VERSION 5.8 ;
BUSBITCHARS "[]" ;
DIVIDERCHAR "/" ;
UNITS
    DATABASE MICRONS 1000 ;
END UNITS

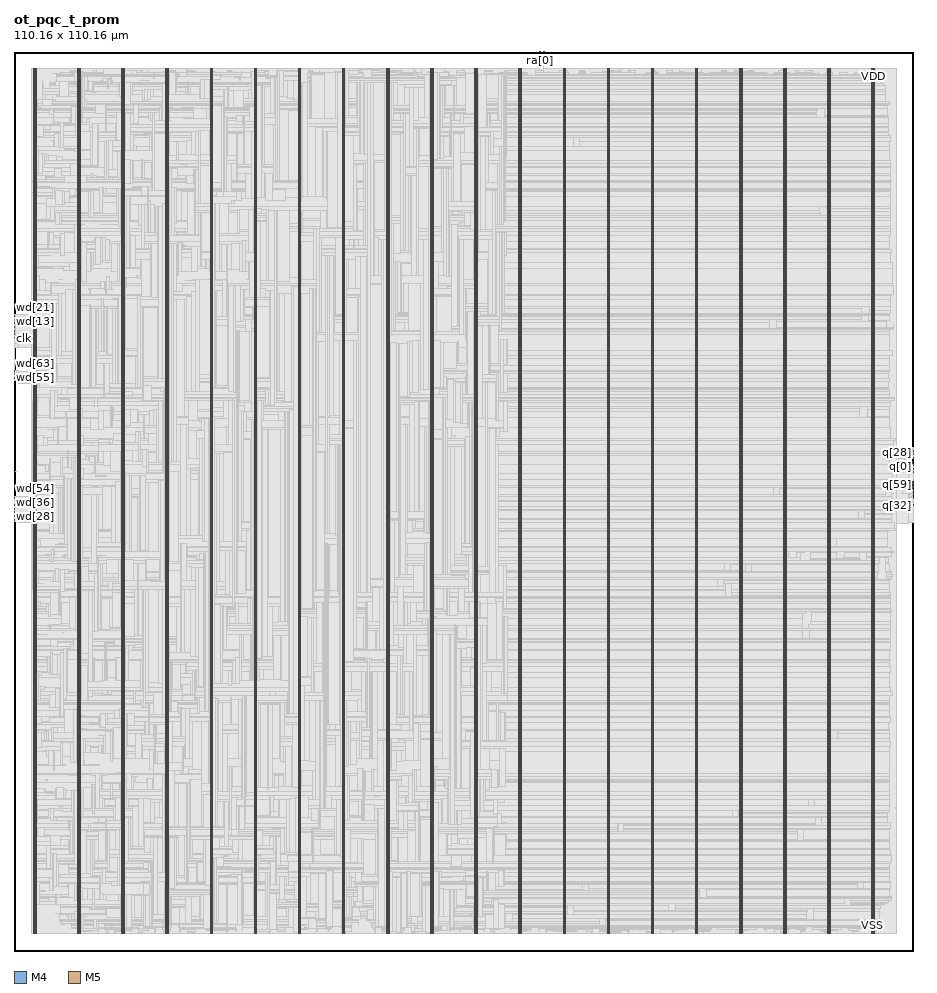
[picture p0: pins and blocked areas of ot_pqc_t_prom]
MACRO ot_pqc_t_prom
  FOREIGN ot_pqc_t_prom 0 0 ;
  CLASS BLOCK ;
  SIZE 110.16 BY 110.16 ;
  PIN clk
    DIRECTION INPUT ;
    USE SIGNAL ;
    PORT
      LAYER M4 ;
        RECT  0 74.928 0.084 74.952 ;
    END
  END clk
  PIN q[0]
    DIRECTION OUTPUT ;
    USE SIGNAL ;
    PORT
      LAYER M4 ;
        RECT  110.076 58.32 110.16 58.344 ;
    END
  END q[0]
  PIN q[10]
    DIRECTION OUTPUT ;
    USE SIGNAL ;
    PORT
      LAYER M4 ;
        RECT  110.076 59.28 110.16 59.304 ;
    END
  END q[10]
  PIN q[11]
    DIRECTION OUTPUT ;
    USE SIGNAL ;
    PORT
      LAYER M4 ;
        RECT  110.076 59.376 110.16 59.4 ;
    END
  END q[11]
  PIN q[12]
    DIRECTION OUTPUT ;
    USE SIGNAL ;
    PORT
      LAYER M4 ;
        RECT  110.076 59.472 110.16 59.496 ;
    END
  END q[12]
  PIN q[13]
    DIRECTION OUTPUT ;
    USE SIGNAL ;
    PORT
      LAYER M4 ;
        RECT  110.076 59.568 110.16 59.592 ;
    END
  END q[13]
  PIN q[14]
    DIRECTION OUTPUT ;
    USE SIGNAL ;
    PORT
      LAYER M4 ;
        RECT  110.076 59.664 110.16 59.688 ;
    END
  END q[14]
  PIN q[15]
    DIRECTION OUTPUT ;
    USE SIGNAL ;
    PORT
      LAYER M4 ;
        RECT  110.076 59.76 110.16 59.784 ;
    END
  END q[15]
  PIN q[16]
    DIRECTION OUTPUT ;
    USE SIGNAL ;
    PORT
      LAYER M4 ;
        RECT  110.076 59.856 110.16 59.88 ;
    END
  END q[16]
  PIN q[17]
    DIRECTION OUTPUT ;
    USE SIGNAL ;
    PORT
      LAYER M4 ;
        RECT  110.076 59.952 110.16 59.976 ;
    END
  END q[17]
  PIN q[18]
    DIRECTION OUTPUT ;
    USE SIGNAL ;
    PORT
      LAYER M4 ;
        RECT  110.076 60.048 110.16 60.072 ;
    END
  END q[18]
  PIN q[19]
    DIRECTION OUTPUT ;
    USE SIGNAL ;
    PORT
      LAYER M4 ;
        RECT  110.076 60.144 110.16 60.168 ;
    END
  END q[19]
  PIN q[1]
    DIRECTION OUTPUT ;
    USE SIGNAL ;
    PORT
      LAYER M4 ;
        RECT  110.076 58.416 110.16 58.44 ;
    END
  END q[1]
  PIN q[20]
    DIRECTION OUTPUT ;
    USE SIGNAL ;
    PORT
      LAYER M4 ;
        RECT  110.076 60.24 110.16 60.264 ;
    END
  END q[20]
  PIN q[21]
    DIRECTION OUTPUT ;
    USE SIGNAL ;
    PORT
      LAYER M4 ;
        RECT  110.076 60.336 110.16 60.36 ;
    END
  END q[21]
  PIN q[22]
    DIRECTION OUTPUT ;
    USE SIGNAL ;
    PORT
      LAYER M4 ;
        RECT  110.076 60.432 110.16 60.456 ;
    END
  END q[22]
  PIN q[23]
    DIRECTION OUTPUT ;
    USE SIGNAL ;
    PORT
      LAYER M4 ;
        RECT  110.076 60.528 110.16 60.552 ;
    END
  END q[23]
  PIN q[24]
    DIRECTION OUTPUT ;
    USE SIGNAL ;
    PORT
      LAYER M4 ;
        RECT  110.076 60.624 110.16 60.648 ;
    END
  END q[24]
  PIN q[25]
    DIRECTION OUTPUT ;
    USE SIGNAL ;
    PORT
      LAYER M4 ;
        RECT  110.076 60.72 110.16 60.744 ;
    END
  END q[25]
  PIN q[26]
    DIRECTION OUTPUT ;
    USE SIGNAL ;
    PORT
      LAYER M4 ;
        RECT  110.076 60.816 110.16 60.84 ;
    END
  END q[26]
  PIN q[27]
    DIRECTION OUTPUT ;
    USE SIGNAL ;
    PORT
      LAYER M4 ;
        RECT  110.076 60.912 110.16 60.936 ;
    END
  END q[27]
  PIN q[28]
    DIRECTION OUTPUT ;
    USE SIGNAL ;
    PORT
      LAYER M4 ;
        RECT  110.076 61.008 110.16 61.032 ;
    END
  END q[28]
  PIN q[29]
    DIRECTION OUTPUT ;
    USE SIGNAL ;
    PORT
      LAYER M4 ;
        RECT  110.076 61.104 110.16 61.128 ;
    END
  END q[29]
  PIN q[2]
    DIRECTION OUTPUT ;
    USE SIGNAL ;
    PORT
      LAYER M4 ;
        RECT  110.076 58.512 110.16 58.536 ;
    END
  END q[2]
  PIN q[30]
    DIRECTION OUTPUT ;
    USE SIGNAL ;
    PORT
      LAYER M4 ;
        RECT  110.076 61.2 110.16 61.224 ;
    END
  END q[30]
  PIN q[31]
    DIRECTION OUTPUT ;
    USE SIGNAL ;
    PORT
      LAYER M4 ;
        RECT  110.076 61.296 110.16 61.32 ;
    END
  END q[31]
  PIN q[32]
    DIRECTION OUTPUT ;
    USE SIGNAL ;
    PORT
      LAYER M4 ;
        RECT  110.076 54.48 110.16 54.504 ;
    END
  END q[32]
  PIN q[33]
    DIRECTION OUTPUT ;
    USE SIGNAL ;
    PORT
      LAYER M4 ;
        RECT  110.076 54.576 110.16 54.6 ;
    END
  END q[33]
  PIN q[34]
    DIRECTION OUTPUT ;
    USE SIGNAL ;
    PORT
      LAYER M4 ;
        RECT  110.076 54.672 110.16 54.696 ;
    END
  END q[34]
  PIN q[35]
    DIRECTION OUTPUT ;
    USE SIGNAL ;
    PORT
      LAYER M4 ;
        RECT  110.076 54.768 110.16 54.792 ;
    END
  END q[35]
  PIN q[36]
    DIRECTION OUTPUT ;
    USE SIGNAL ;
    PORT
      LAYER M4 ;
        RECT  110.076 54.864 110.16 54.888 ;
    END
  END q[36]
  PIN q[37]
    DIRECTION OUTPUT ;
    USE SIGNAL ;
    PORT
      LAYER M4 ;
        RECT  110.076 54.96 110.16 54.984 ;
    END
  END q[37]
  PIN q[38]
    DIRECTION OUTPUT ;
    USE SIGNAL ;
    PORT
      LAYER M4 ;
        RECT  110.076 55.056 110.16 55.08 ;
    END
  END q[38]
  PIN q[39]
    DIRECTION OUTPUT ;
    USE SIGNAL ;
    PORT
      LAYER M4 ;
        RECT  110.076 55.152 110.16 55.176 ;
    END
  END q[39]
  PIN q[3]
    DIRECTION OUTPUT ;
    USE SIGNAL ;
    PORT
      LAYER M4 ;
        RECT  110.076 58.608 110.16 58.632 ;
    END
  END q[3]
  PIN q[40]
    DIRECTION OUTPUT ;
    USE SIGNAL ;
    PORT
      LAYER M4 ;
        RECT  110.076 55.248 110.16 55.272 ;
    END
  END q[40]
  PIN q[41]
    DIRECTION OUTPUT ;
    USE SIGNAL ;
    PORT
      LAYER M4 ;
        RECT  110.076 55.344 110.16 55.368 ;
    END
  END q[41]
  PIN q[42]
    DIRECTION OUTPUT ;
    USE SIGNAL ;
    PORT
      LAYER M4 ;
        RECT  110.076 55.44 110.16 55.464 ;
    END
  END q[42]
  PIN q[43]
    DIRECTION OUTPUT ;
    USE SIGNAL ;
    PORT
      LAYER M4 ;
        RECT  110.076 55.536 110.16 55.56 ;
    END
  END q[43]
  PIN q[44]
    DIRECTION OUTPUT ;
    USE SIGNAL ;
    PORT
      LAYER M4 ;
        RECT  110.076 55.632 110.16 55.656 ;
    END
  END q[44]
  PIN q[45]
    DIRECTION OUTPUT ;
    USE SIGNAL ;
    PORT
      LAYER M4 ;
        RECT  110.076 55.728 110.16 55.752 ;
    END
  END q[45]
  PIN q[46]
    DIRECTION OUTPUT ;
    USE SIGNAL ;
    PORT
      LAYER M4 ;
        RECT  110.076 55.824 110.16 55.848 ;
    END
  END q[46]
  PIN q[47]
    DIRECTION OUTPUT ;
    USE SIGNAL ;
    PORT
      LAYER M4 ;
        RECT  110.076 55.92 110.16 55.944 ;
    END
  END q[47]
  PIN q[48]
    DIRECTION OUTPUT ;
    USE SIGNAL ;
    PORT
      LAYER M4 ;
        RECT  110.076 56.016 110.16 56.04 ;
    END
  END q[48]
  PIN q[49]
    DIRECTION OUTPUT ;
    USE SIGNAL ;
    PORT
      LAYER M4 ;
        RECT  110.076 56.112 110.16 56.136 ;
    END
  END q[49]
  PIN q[4]
    DIRECTION OUTPUT ;
    USE SIGNAL ;
    PORT
      LAYER M4 ;
        RECT  110.076 58.704 110.16 58.728 ;
    END
  END q[4]
  PIN q[50]
    DIRECTION OUTPUT ;
    USE SIGNAL ;
    PORT
      LAYER M4 ;
        RECT  110.076 56.208 110.16 56.232 ;
    END
  END q[50]
  PIN q[51]
    DIRECTION OUTPUT ;
    USE SIGNAL ;
    PORT
      LAYER M4 ;
        RECT  110.076 56.304 110.16 56.328 ;
    END
  END q[51]
  PIN q[52]
    DIRECTION OUTPUT ;
    USE SIGNAL ;
    PORT
      LAYER M4 ;
        RECT  110.076 56.4 110.16 56.424 ;
    END
  END q[52]
  PIN q[53]
    DIRECTION OUTPUT ;
    USE SIGNAL ;
    PORT
      LAYER M4 ;
        RECT  110.076 56.496 110.16 56.52 ;
    END
  END q[53]
  PIN q[54]
    DIRECTION OUTPUT ;
    USE SIGNAL ;
    PORT
      LAYER M4 ;
        RECT  110.076 56.592 110.16 56.616 ;
    END
  END q[54]
  PIN q[55]
    DIRECTION OUTPUT ;
    USE SIGNAL ;
    PORT
      LAYER M4 ;
        RECT  110.076 56.688 110.16 56.712 ;
    END
  END q[55]
  PIN q[56]
    DIRECTION OUTPUT ;
    USE SIGNAL ;
    PORT
      LAYER M4 ;
        RECT  110.076 56.784 110.16 56.808 ;
    END
  END q[56]
  PIN q[57]
    DIRECTION OUTPUT ;
    USE SIGNAL ;
    PORT
      LAYER M4 ;
        RECT  110.076 56.88 110.16 56.904 ;
    END
  END q[57]
  PIN q[58]
    DIRECTION OUTPUT ;
    USE SIGNAL ;
    PORT
      LAYER M4 ;
        RECT  110.076 56.976 110.16 57 ;
    END
  END q[58]
  PIN q[59]
    DIRECTION OUTPUT ;
    USE SIGNAL ;
    PORT
      LAYER M4 ;
        RECT  110.076 57.072 110.16 57.096 ;
    END
  END q[59]
  PIN q[5]
    DIRECTION OUTPUT ;
    USE SIGNAL ;
    PORT
      LAYER M4 ;
        RECT  110.076 58.8 110.16 58.824 ;
    END
  END q[5]
  PIN q[60]
    DIRECTION OUTPUT ;
    USE SIGNAL ;
    PORT
      LAYER M4 ;
        RECT  110.076 57.168 110.16 57.192 ;
    END
  END q[60]
  PIN q[61]
    DIRECTION OUTPUT ;
    USE SIGNAL ;
    PORT
      LAYER M4 ;
        RECT  110.076 57.264 110.16 57.288 ;
    END
  END q[61]
  PIN q[62]
    DIRECTION OUTPUT ;
    USE SIGNAL ;
    PORT
      LAYER M4 ;
        RECT  110.076 57.36 110.16 57.384 ;
    END
  END q[62]
  PIN q[63]
    DIRECTION OUTPUT ;
    USE SIGNAL ;
    PORT
      LAYER M4 ;
        RECT  110.076 57.456 110.16 57.48 ;
    END
  END q[63]
  PIN q[6]
    DIRECTION OUTPUT ;
    USE SIGNAL ;
    PORT
      LAYER M4 ;
        RECT  110.076 58.896 110.16 58.92 ;
    END
  END q[6]
  PIN q[7]
    DIRECTION OUTPUT ;
    USE SIGNAL ;
    PORT
      LAYER M4 ;
        RECT  110.076 58.992 110.16 59.016 ;
    END
  END q[7]
  PIN q[8]
    DIRECTION OUTPUT ;
    USE SIGNAL ;
    PORT
      LAYER M4 ;
        RECT  110.076 59.088 110.16 59.112 ;
    END
  END q[8]
  PIN q[9]
    DIRECTION OUTPUT ;
    USE SIGNAL ;
    PORT
      LAYER M4 ;
        RECT  110.076 59.184 110.16 59.208 ;
    END
  END q[9]
  PIN ra[0]
    DIRECTION INPUT ;
    USE SIGNAL ;
    PORT
      LAYER M5 ;
        RECT  64.368 110.076 64.392 110.16 ;
    END
  END ra[0]
  PIN ra[1]
    DIRECTION INPUT ;
    USE SIGNAL ;
    PORT
      LAYER M5 ;
        RECT  64.464 110.076 64.488 110.16 ;
    END
  END ra[1]
  PIN ra[2]
    DIRECTION INPUT ;
    USE SIGNAL ;
    PORT
      LAYER M5 ;
        RECT  64.56 110.076 64.584 110.16 ;
    END
  END ra[2]
  PIN ra[3]
    DIRECTION INPUT ;
    USE SIGNAL ;
    PORT
      LAYER M5 ;
        RECT  64.656 110.076 64.68 110.16 ;
    END
  END ra[3]
  PIN ra[4]
    DIRECTION INPUT ;
    USE SIGNAL ;
    PORT
      LAYER M5 ;
        RECT  64.752 110.076 64.776 110.16 ;
    END
  END ra[4]
  PIN ra[5]
    DIRECTION INPUT ;
    USE SIGNAL ;
    PORT
      LAYER M5 ;
        RECT  64.848 110.076 64.872 110.16 ;
    END
  END ra[5]
  PIN ra[6]
    DIRECTION INPUT ;
    USE SIGNAL ;
    PORT
      LAYER M5 ;
        RECT  64.944 110.076 64.968 110.16 ;
    END
  END ra[6]
  PIN rst_n
    DIRECTION INPUT ;
    USE SIGNAL ;
    PORT
      LAYER M4 ;
        RECT  0 75.024 0.084 75.048 ;
    END
  END rst_n
  PIN wa[0]
    DIRECTION INPUT ;
    USE SIGNAL ;
    PORT
      LAYER M4 ;
        RECT  0 75.12 0.084 75.144 ;
    END
  END wa[0]
  PIN wa[1]
    DIRECTION INPUT ;
    USE SIGNAL ;
    PORT
      LAYER M4 ;
        RECT  0 75.216 0.084 75.24 ;
    END
  END wa[1]
  PIN wa[2]
    DIRECTION INPUT ;
    USE SIGNAL ;
    PORT
      LAYER M4 ;
        RECT  0 75.312 0.084 75.336 ;
    END
  END wa[2]
  PIN wa[3]
    DIRECTION INPUT ;
    USE SIGNAL ;
    PORT
      LAYER M4 ;
        RECT  0 75.408 0.084 75.432 ;
    END
  END wa[3]
  PIN wa[4]
    DIRECTION INPUT ;
    USE SIGNAL ;
    PORT
      LAYER M4 ;
        RECT  0 75.504 0.084 75.528 ;
    END
  END wa[4]
  PIN wa[5]
    DIRECTION INPUT ;
    USE SIGNAL ;
    PORT
      LAYER M4 ;
        RECT  0 75.6 0.084 75.624 ;
    END
  END wa[5]
  PIN wa[6]
    DIRECTION INPUT ;
    USE SIGNAL ;
    PORT
      LAYER M4 ;
        RECT  0 75.696 0.084 75.72 ;
    END
  END wa[6]
  PIN wd[0]
    DIRECTION INPUT ;
    USE SIGNAL ;
    PORT
      LAYER M4 ;
        RECT  0 75.792 0.084 75.816 ;
    END
  END wd[0]
  PIN wd[10]
    DIRECTION INPUT ;
    USE SIGNAL ;
    PORT
      LAYER M4 ;
        RECT  0 76.752 0.084 76.776 ;
    END
  END wd[10]
  PIN wd[11]
    DIRECTION INPUT ;
    USE SIGNAL ;
    PORT
      LAYER M4 ;
        RECT  0 76.848 0.084 76.872 ;
    END
  END wd[11]
  PIN wd[12]
    DIRECTION INPUT ;
    USE SIGNAL ;
    PORT
      LAYER M4 ;
        RECT  0 76.944 0.084 76.968 ;
    END
  END wd[12]
  PIN wd[13]
    DIRECTION INPUT ;
    USE SIGNAL ;
    PORT
      LAYER M4 ;
        RECT  0 77.04 0.084 77.064 ;
    END
  END wd[13]
  PIN wd[14]
    DIRECTION INPUT ;
    USE SIGNAL ;
    PORT
      LAYER M4 ;
        RECT  0 77.136 0.084 77.16 ;
    END
  END wd[14]
  PIN wd[15]
    DIRECTION INPUT ;
    USE SIGNAL ;
    PORT
      LAYER M4 ;
        RECT  0 77.232 0.084 77.256 ;
    END
  END wd[15]
  PIN wd[16]
    DIRECTION INPUT ;
    USE SIGNAL ;
    PORT
      LAYER M4 ;
        RECT  0 77.328 0.084 77.352 ;
    END
  END wd[16]
  PIN wd[17]
    DIRECTION INPUT ;
    USE SIGNAL ;
    PORT
      LAYER M4 ;
        RECT  0 77.424 0.084 77.448 ;
    END
  END wd[17]
  PIN wd[18]
    DIRECTION INPUT ;
    USE SIGNAL ;
    PORT
      LAYER M4 ;
        RECT  0 77.52 0.084 77.544 ;
    END
  END wd[18]
  PIN wd[19]
    DIRECTION INPUT ;
    USE SIGNAL ;
    PORT
      LAYER M4 ;
        RECT  0 77.616 0.084 77.64 ;
    END
  END wd[19]
  PIN wd[1]
    DIRECTION INPUT ;
    USE SIGNAL ;
    PORT
      LAYER M4 ;
        RECT  0 75.888 0.084 75.912 ;
    END
  END wd[1]
  PIN wd[20]
    DIRECTION INPUT ;
    USE SIGNAL ;
    PORT
      LAYER M4 ;
        RECT  0 77.712 0.084 77.736 ;
    END
  END wd[20]
  PIN wd[21]
    DIRECTION INPUT ;
    USE SIGNAL ;
    PORT
      LAYER M4 ;
        RECT  0 77.808 0.084 77.832 ;
    END
  END wd[21]
  PIN wd[22]
    DIRECTION INPUT ;
    USE SIGNAL ;
    PORT
      LAYER M4 ;
        RECT  0 77.904 0.084 77.928 ;
    END
  END wd[22]
  PIN wd[23]
    DIRECTION INPUT ;
    USE SIGNAL ;
    PORT
      LAYER M4 ;
        RECT  0 52.656 0.084 52.68 ;
    END
  END wd[23]
  PIN wd[24]
    DIRECTION INPUT ;
    USE SIGNAL ;
    PORT
      LAYER M4 ;
        RECT  0 52.752 0.084 52.776 ;
    END
  END wd[24]
  PIN wd[25]
    DIRECTION INPUT ;
    USE SIGNAL ;
    PORT
      LAYER M4 ;
        RECT  0 52.848 0.084 52.872 ;
    END
  END wd[25]
  PIN wd[26]
    DIRECTION INPUT ;
    USE SIGNAL ;
    PORT
      LAYER M4 ;
        RECT  0 52.944 0.084 52.968 ;
    END
  END wd[26]
  PIN wd[27]
    DIRECTION INPUT ;
    USE SIGNAL ;
    PORT
      LAYER M4 ;
        RECT  0 53.04 0.084 53.064 ;
    END
  END wd[27]
  PIN wd[28]
    DIRECTION INPUT ;
    USE SIGNAL ;
    PORT
      LAYER M4 ;
        RECT  0 53.136 0.084 53.16 ;
    END
  END wd[28]
  PIN wd[29]
    DIRECTION INPUT ;
    USE SIGNAL ;
    PORT
      LAYER M4 ;
        RECT  0 53.232 0.084 53.256 ;
    END
  END wd[29]
  PIN wd[2]
    DIRECTION INPUT ;
    USE SIGNAL ;
    PORT
      LAYER M4 ;
        RECT  0 75.984 0.084 76.008 ;
    END
  END wd[2]
  PIN wd[30]
    DIRECTION INPUT ;
    USE SIGNAL ;
    PORT
      LAYER M4 ;
        RECT  0 53.328 0.084 53.352 ;
    END
  END wd[30]
  PIN wd[31]
    DIRECTION INPUT ;
    USE SIGNAL ;
    PORT
      LAYER M4 ;
        RECT  0 53.424 0.084 53.448 ;
    END
  END wd[31]
  PIN wd[32]
    DIRECTION INPUT ;
    USE SIGNAL ;
    PORT
      LAYER M4 ;
        RECT  0 53.52 0.084 53.544 ;
    END
  END wd[32]
  PIN wd[33]
    DIRECTION INPUT ;
    USE SIGNAL ;
    PORT
      LAYER M4 ;
        RECT  0 53.616 0.084 53.64 ;
    END
  END wd[33]
  PIN wd[34]
    DIRECTION INPUT ;
    USE SIGNAL ;
    PORT
      LAYER M4 ;
        RECT  0 53.712 0.084 53.736 ;
    END
  END wd[34]
  PIN wd[35]
    DIRECTION INPUT ;
    USE SIGNAL ;
    PORT
      LAYER M4 ;
        RECT  0 53.808 0.084 53.832 ;
    END
  END wd[35]
  PIN wd[36]
    DIRECTION INPUT ;
    USE SIGNAL ;
    PORT
      LAYER M4 ;
        RECT  0 53.904 0.084 53.928 ;
    END
  END wd[36]
  PIN wd[37]
    DIRECTION INPUT ;
    USE SIGNAL ;
    PORT
      LAYER M4 ;
        RECT  0 54 0.084 54.024 ;
    END
  END wd[37]
  PIN wd[38]
    DIRECTION INPUT ;
    USE SIGNAL ;
    PORT
      LAYER M4 ;
        RECT  0 54.096 0.084 54.12 ;
    END
  END wd[38]
  PIN wd[39]
    DIRECTION INPUT ;
    USE SIGNAL ;
    PORT
      LAYER M4 ;
        RECT  0 54.192 0.084 54.216 ;
    END
  END wd[39]
  PIN wd[3]
    DIRECTION INPUT ;
    USE SIGNAL ;
    PORT
      LAYER M4 ;
        RECT  0 76.08 0.084 76.104 ;
    END
  END wd[3]
  PIN wd[40]
    DIRECTION INPUT ;
    USE SIGNAL ;
    PORT
      LAYER M4 ;
        RECT  0 54.288 0.084 54.312 ;
    END
  END wd[40]
  PIN wd[41]
    DIRECTION INPUT ;
    USE SIGNAL ;
    PORT
      LAYER M4 ;
        RECT  0 54.384 0.084 54.408 ;
    END
  END wd[41]
  PIN wd[42]
    DIRECTION INPUT ;
    USE SIGNAL ;
    PORT
      LAYER M4 ;
        RECT  0 54.48 0.084 54.504 ;
    END
  END wd[42]
  PIN wd[43]
    DIRECTION INPUT ;
    USE SIGNAL ;
    PORT
      LAYER M4 ;
        RECT  0 54.576 0.084 54.6 ;
    END
  END wd[43]
  PIN wd[44]
    DIRECTION INPUT ;
    USE SIGNAL ;
    PORT
      LAYER M4 ;
        RECT  0 54.672 0.084 54.696 ;
    END
  END wd[44]
  PIN wd[45]
    DIRECTION INPUT ;
    USE SIGNAL ;
    PORT
      LAYER M4 ;
        RECT  0 54.768 0.084 54.792 ;
    END
  END wd[45]
  PIN wd[46]
    DIRECTION INPUT ;
    USE SIGNAL ;
    PORT
      LAYER M4 ;
        RECT  0 54.864 0.084 54.888 ;
    END
  END wd[46]
  PIN wd[47]
    DIRECTION INPUT ;
    USE SIGNAL ;
    PORT
      LAYER M4 ;
        RECT  0 54.96 0.084 54.984 ;
    END
  END wd[47]
  PIN wd[48]
    DIRECTION INPUT ;
    USE SIGNAL ;
    PORT
      LAYER M4 ;
        RECT  0 55.056 0.084 55.08 ;
    END
  END wd[48]
  PIN wd[49]
    DIRECTION INPUT ;
    USE SIGNAL ;
    PORT
      LAYER M4 ;
        RECT  0 55.152 0.084 55.176 ;
    END
  END wd[49]
  PIN wd[4]
    DIRECTION INPUT ;
    USE SIGNAL ;
    PORT
      LAYER M4 ;
        RECT  0 76.176 0.084 76.2 ;
    END
  END wd[4]
  PIN wd[50]
    DIRECTION INPUT ;
    USE SIGNAL ;
    PORT
      LAYER M4 ;
        RECT  0 55.248 0.084 55.272 ;
    END
  END wd[50]
  PIN wd[51]
    DIRECTION INPUT ;
    USE SIGNAL ;
    PORT
      LAYER M4 ;
        RECT  0 55.344 0.084 55.368 ;
    END
  END wd[51]
  PIN wd[52]
    DIRECTION INPUT ;
    USE SIGNAL ;
    PORT
      LAYER M4 ;
        RECT  0 55.44 0.084 55.464 ;
    END
  END wd[52]
  PIN wd[53]
    DIRECTION INPUT ;
    USE SIGNAL ;
    PORT
      LAYER M4 ;
        RECT  0 55.536 0.084 55.56 ;
    END
  END wd[53]
  PIN wd[54]
    DIRECTION INPUT ;
    USE SIGNAL ;
    PORT
      LAYER M4 ;
        RECT  0 55.632 0.084 55.656 ;
    END
  END wd[54]
  PIN wd[55]
    DIRECTION INPUT ;
    USE SIGNAL ;
    PORT
      LAYER M4 ;
        RECT  0 70.128 0.084 70.152 ;
    END
  END wd[55]
  PIN wd[56]
    DIRECTION INPUT ;
    USE SIGNAL ;
    PORT
      LAYER M4 ;
        RECT  0 70.224 0.084 70.248 ;
    END
  END wd[56]
  PIN wd[57]
    DIRECTION INPUT ;
    USE SIGNAL ;
    PORT
      LAYER M4 ;
        RECT  0 70.32 0.084 70.344 ;
    END
  END wd[57]
  PIN wd[58]
    DIRECTION INPUT ;
    USE SIGNAL ;
    PORT
      LAYER M4 ;
        RECT  0 70.416 0.084 70.44 ;
    END
  END wd[58]
  PIN wd[59]
    DIRECTION INPUT ;
    USE SIGNAL ;
    PORT
      LAYER M4 ;
        RECT  0 70.512 0.084 70.536 ;
    END
  END wd[59]
  PIN wd[5]
    DIRECTION INPUT ;
    USE SIGNAL ;
    PORT
      LAYER M4 ;
        RECT  0 76.272 0.084 76.296 ;
    END
  END wd[5]
  PIN wd[60]
    DIRECTION INPUT ;
    USE SIGNAL ;
    PORT
      LAYER M4 ;
        RECT  0 70.608 0.084 70.632 ;
    END
  END wd[60]
  PIN wd[61]
    DIRECTION INPUT ;
    USE SIGNAL ;
    PORT
      LAYER M4 ;
        RECT  0 70.704 0.084 70.728 ;
    END
  END wd[61]
  PIN wd[62]
    DIRECTION INPUT ;
    USE SIGNAL ;
    PORT
      LAYER M4 ;
        RECT  0 70.8 0.084 70.824 ;
    END
  END wd[62]
  PIN wd[63]
    DIRECTION INPUT ;
    USE SIGNAL ;
    PORT
      LAYER M4 ;
        RECT  0 70.896 0.084 70.92 ;
    END
  END wd[63]
  PIN wd[6]
    DIRECTION INPUT ;
    USE SIGNAL ;
    PORT
      LAYER M4 ;
        RECT  0 76.368 0.084 76.392 ;
    END
  END wd[6]
  PIN wd[7]
    DIRECTION INPUT ;
    USE SIGNAL ;
    PORT
      LAYER M4 ;
        RECT  0 76.464 0.084 76.488 ;
    END
  END wd[7]
  PIN wd[8]
    DIRECTION INPUT ;
    USE SIGNAL ;
    PORT
      LAYER M4 ;
        RECT  0 76.56 0.084 76.584 ;
    END
  END wd[8]
  PIN wd[9]
    DIRECTION INPUT ;
    USE SIGNAL ;
    PORT
      LAYER M4 ;
        RECT  0 76.656 0.084 76.68 ;
    END
  END wd[9]
  PIN we
    DIRECTION INPUT ;
    USE SIGNAL ;
    PORT
      LAYER M4 ;
        RECT  0 70.992 0.084 71.016 ;
    END
  END we
  PIN VSS
    DIRECTION INOUT ;
    USE GROUND ;
    PORT
      LAYER M5 ;
        RECT  105 2.137 105.12 108.023 ;
        RECT  99.6 2.137 99.72 108.023 ;
        RECT  94.2 2.137 94.32 108.023 ;
        RECT  88.8 2.137 88.92 108.023 ;
        RECT  83.4 2.137 83.52 108.023 ;
        RECT  78 2.137 78.12 108.023 ;
        RECT  72.6 2.137 72.72 108.023 ;
        RECT  67.2 2.137 67.32 108.023 ;
        RECT  61.8 2.137 61.92 108.023 ;
        RECT  56.4 2.137 56.52 108.023 ;
        RECT  51 2.137 51.12 108.023 ;
        RECT  45.6 2.137 45.72 108.023 ;
        RECT  40.2 2.137 40.32 108.023 ;
        RECT  34.8 2.137 34.92 108.023 ;
        RECT  29.4 2.137 29.52 108.023 ;
        RECT  24 2.137 24.12 108.023 ;
        RECT  18.6 2.137 18.72 108.023 ;
        RECT  13.2 2.137 13.32 108.023 ;
        RECT  7.8 2.137 7.92 108.023 ;
        RECT  2.4 2.137 2.52 108.023 ;
    END
  END VSS
  PIN VDD
    DIRECTION INOUT ;
    USE POWER ;
    PORT
      LAYER M5 ;
        RECT  105.192 2.151 105.312 108.009 ;
        RECT  99.792 2.151 99.912 108.009 ;
        RECT  94.392 2.151 94.512 108.009 ;
        RECT  88.992 2.151 89.112 108.009 ;
        RECT  83.592 2.151 83.712 108.009 ;
        RECT  78.192 2.151 78.312 108.009 ;
        RECT  72.792 2.151 72.912 108.009 ;
        RECT  67.392 2.151 67.512 108.009 ;
        RECT  61.992 2.151 62.112 108.009 ;
        RECT  56.592 2.151 56.712 108.009 ;
        RECT  51.192 2.151 51.312 108.009 ;
        RECT  45.792 2.151 45.912 108.009 ;
        RECT  40.392 2.151 40.512 108.009 ;
        RECT  34.992 2.151 35.112 108.009 ;
        RECT  29.592 2.151 29.712 108.009 ;
        RECT  24.192 2.151 24.312 108.009 ;
        RECT  18.792 2.151 18.912 108.009 ;
        RECT  13.392 2.151 13.512 108.009 ;
        RECT  7.992 2.151 8.112 108.009 ;
        RECT  2.592 2.151 2.712 108.009 ;
    END
  END VDD
  OBS
    LAYER RVTN ;
     RECT  2.16 2.16 108 2.295 ;
     RECT  2.16 2.565 108 2.835 ;
     RECT  2.16 3.105 108 3.375 ;
     RECT  2.16 3.645 108 3.915 ;
     RECT  2.16 4.185 108 4.455 ;
     RECT  2.16 4.725 108 4.995 ;
     RECT  2.16 5.265 108 5.535 ;
     RECT  2.16 5.805 108 6.075 ;
     RECT  2.16 6.345 108 6.615 ;
     RECT  2.16 6.885 108 7.155 ;
     RECT  2.16 7.425 108 7.695 ;
     RECT  2.16 7.965 108 8.235 ;
     RECT  2.16 8.505 108 8.775 ;
     RECT  2.16 9.045 108 9.315 ;
     RECT  2.16 9.585 108 9.855 ;
     RECT  2.16 10.125 108 10.395 ;
     RECT  2.16 10.665 108 10.935 ;
     RECT  2.16 11.205 108 11.475 ;
     RECT  2.16 11.745 108 12.015 ;
     RECT  2.16 12.285 108 12.555 ;
     RECT  2.16 12.825 108 13.095 ;
     RECT  2.16 13.365 108 13.635 ;
     RECT  2.16 13.905 108 14.175 ;
     RECT  2.16 14.445 108 14.715 ;
     RECT  2.16 14.985 108 15.255 ;
     RECT  2.16 15.525 108 15.795 ;
     RECT  2.16 16.065 108 16.335 ;
     RECT  2.16 16.605 108 16.875 ;
     RECT  2.16 17.145 108 17.415 ;
     RECT  2.16 17.685 108 17.955 ;
     RECT  2.16 18.225 108 18.495 ;
     RECT  2.16 18.765 108 19.035 ;
     RECT  2.16 19.305 108 19.575 ;
     RECT  2.16 19.845 108 20.115 ;
     RECT  2.16 20.385 108 20.655 ;
     RECT  2.16 20.925 108 21.195 ;
     RECT  2.16 21.465 108 21.735 ;
     RECT  2.16 22.005 108 22.275 ;
     RECT  2.16 22.545 108 22.815 ;
     RECT  2.16 23.085 108 23.355 ;
     RECT  2.16 23.625 108 23.895 ;
     RECT  2.16 24.165 108 24.435 ;
     RECT  2.16 24.705 108 24.975 ;
     RECT  2.16 25.245 108 25.515 ;
     RECT  2.16 25.785 108 26.055 ;
     RECT  2.16 26.325 108 26.595 ;
     RECT  2.16 26.865 108 27.135 ;
     RECT  2.16 27.405 108 27.675 ;
     RECT  2.16 27.945 108 28.215 ;
     RECT  2.16 28.485 108 28.755 ;
     RECT  2.16 29.025 108 29.295 ;
     RECT  2.16 29.565 108 29.835 ;
     RECT  2.16 30.105 108 30.375 ;
     RECT  2.16 30.645 108 30.915 ;
     RECT  2.16 31.185 108 31.455 ;
     RECT  2.16 31.725 108 31.995 ;
     RECT  2.16 32.265 108 32.535 ;
     RECT  2.16 32.805 108 33.075 ;
     RECT  2.16 33.345 108 33.615 ;
     RECT  2.16 33.885 108 34.155 ;
     RECT  2.16 34.425 108 34.695 ;
     RECT  2.16 34.965 108 35.235 ;
     RECT  2.16 35.505 108 35.775 ;
     RECT  2.16 36.045 108 36.315 ;
     RECT  2.16 36.585 108 36.855 ;
     RECT  2.16 37.125 108 37.395 ;
     RECT  2.16 37.665 108 37.935 ;
     RECT  2.16 38.205 108 38.475 ;
     RECT  2.16 38.745 108 39.015 ;
     RECT  2.16 39.285 108 39.555 ;
     RECT  2.16 39.825 108 40.095 ;
     RECT  2.16 40.365 108 40.635 ;
     RECT  2.16 40.905 108 41.175 ;
     RECT  2.16 41.445 108 41.715 ;
     RECT  2.16 41.985 108 42.255 ;
     RECT  2.16 42.525 108 42.795 ;
     RECT  2.16 43.065 108 43.335 ;
     RECT  2.16 43.605 108 43.875 ;
     RECT  2.16 44.145 108 44.415 ;
     RECT  2.16 44.685 108 44.955 ;
     RECT  2.16 45.225 108 45.495 ;
     RECT  2.16 45.765 108 46.035 ;
     RECT  2.16 46.305 108 46.575 ;
     RECT  2.16 46.845 108 47.115 ;
     RECT  2.16 47.385 108 47.655 ;
     RECT  2.16 47.925 108 48.195 ;
     RECT  2.16 48.465 108 48.735 ;
     RECT  2.16 49.005 108 49.275 ;
     RECT  2.16 49.545 108 49.815 ;
     RECT  2.16 50.085 108 50.355 ;
     RECT  2.16 50.625 108 50.895 ;
     RECT  2.16 51.165 108 51.435 ;
     RECT  2.16 51.705 108 51.975 ;
     RECT  2.16 52.245 108 52.515 ;
     RECT  2.16 52.785 108 53.055 ;
     RECT  2.16 53.325 108 53.595 ;
     RECT  2.16 53.865 108 54.135 ;
     RECT  2.16 54.405 108 54.675 ;
     RECT  2.16 54.945 108 55.215 ;
     RECT  2.16 55.485 108 55.755 ;
     RECT  2.16 56.025 108 56.295 ;
     RECT  2.16 56.565 108 56.835 ;
     RECT  2.16 57.105 108 57.375 ;
     RECT  2.16 57.645 108 57.915 ;
     RECT  2.16 58.185 108 58.455 ;
     RECT  2.16 58.725 108 58.995 ;
     RECT  2.16 59.265 108 59.535 ;
     RECT  2.16 59.805 108 60.075 ;
     RECT  2.16 60.345 108 60.615 ;
     RECT  2.16 60.885 108 61.155 ;
     RECT  2.16 61.425 108 61.695 ;
     RECT  2.16 61.965 108 62.235 ;
     RECT  2.16 62.505 108 62.775 ;
     RECT  2.16 63.045 108 63.315 ;
     RECT  2.16 63.585 108 63.855 ;
     RECT  2.16 64.125 108 64.395 ;
     RECT  2.16 64.665 108 64.935 ;
     RECT  2.16 65.205 108 65.475 ;
     RECT  2.16 65.745 108 66.015 ;
     RECT  2.16 66.285 108 66.555 ;
     RECT  2.16 66.825 108 67.095 ;
     RECT  2.16 67.365 108 67.635 ;
     RECT  2.16 67.905 108 68.175 ;
     RECT  2.16 68.445 108 68.715 ;
     RECT  2.16 68.985 108 69.255 ;
     RECT  2.16 69.525 108 69.795 ;
     RECT  2.16 70.065 108 70.335 ;
     RECT  2.16 70.605 108 70.875 ;
     RECT  2.16 71.145 108 71.415 ;
     RECT  2.16 71.685 108 71.955 ;
     RECT  2.16 72.225 108 72.495 ;
     RECT  2.16 72.765 108 73.035 ;
     RECT  2.16 73.305 108 73.575 ;
     RECT  2.16 73.845 108 74.115 ;
     RECT  2.16 74.385 108 74.655 ;
     RECT  2.16 74.925 108 75.195 ;
     RECT  2.16 75.465 108 75.735 ;
     RECT  2.16 76.005 108 76.275 ;
     RECT  2.16 76.545 108 76.815 ;
     RECT  2.16 77.085 108 77.355 ;
     RECT  2.16 77.625 108 77.895 ;
     RECT  2.16 78.165 108 78.435 ;
     RECT  2.16 78.705 108 78.975 ;
     RECT  2.16 79.245 108 79.515 ;
     RECT  2.16 79.785 108 80.055 ;
     RECT  2.16 80.325 108 80.595 ;
     RECT  2.16 80.865 108 81.135 ;
     RECT  2.16 81.405 108 81.675 ;
     RECT  2.16 81.945 108 82.215 ;
     RECT  2.16 82.485 108 82.755 ;
     RECT  2.16 83.025 108 83.295 ;
     RECT  2.16 83.565 108 83.835 ;
     RECT  2.16 84.105 108 84.375 ;
     RECT  2.16 84.645 108 84.915 ;
     RECT  2.16 85.185 108 85.455 ;
     RECT  2.16 85.725 108 85.995 ;
     RECT  2.16 86.265 108 86.535 ;
     RECT  2.16 86.805 108 87.075 ;
     RECT  2.16 87.345 108 87.615 ;
     RECT  2.16 87.885 108 88.155 ;
     RECT  2.16 88.425 108 88.695 ;
     RECT  2.16 88.965 108 89.235 ;
     RECT  2.16 89.505 108 89.775 ;
     RECT  2.16 90.045 108 90.315 ;
     RECT  2.16 90.585 108 90.855 ;
     RECT  2.16 91.125 108 91.395 ;
     RECT  2.16 91.665 108 91.935 ;
     RECT  2.16 92.205 108 92.475 ;
     RECT  2.16 92.745 108 93.015 ;
     RECT  2.16 93.285 108 93.555 ;
     RECT  2.16 93.825 108 94.095 ;
     RECT  2.16 94.365 108 94.635 ;
     RECT  2.16 94.905 108 95.175 ;
     RECT  2.16 95.445 108 95.715 ;
     RECT  2.16 95.985 108 96.255 ;
     RECT  2.16 96.525 108 96.795 ;
     RECT  2.16 97.065 108 97.335 ;
     RECT  2.16 97.605 108 97.875 ;
     RECT  2.16 98.145 108 98.415 ;
     RECT  2.16 98.685 108 98.955 ;
     RECT  2.16 99.225 108 99.495 ;
     RECT  2.16 99.765 108 100.035 ;
     RECT  2.16 100.305 108 100.575 ;
     RECT  2.16 100.845 108 101.115 ;
     RECT  2.16 101.385 108 101.655 ;
     RECT  2.16 101.925 108 102.195 ;
     RECT  2.16 102.465 108 102.735 ;
     RECT  2.16 103.005 108 103.275 ;
     RECT  2.16 103.545 108 103.815 ;
     RECT  2.16 104.085 108 104.355 ;
     RECT  2.16 104.625 108 104.895 ;
     RECT  2.16 105.165 108 105.435 ;
     RECT  2.16 105.705 108 105.975 ;
     RECT  2.16 106.245 108 106.515 ;
     RECT  2.16 106.785 108 107.055 ;
     RECT  2.16 107.325 108 107.595 ;
     RECT  2.16 107.865 108 108 ;
    LAYER RVTP ;
     RECT  2.16 2.295 108 2.565 ;
     RECT  2.16 2.835 108 3.105 ;
     RECT  2.16 3.375 108 3.645 ;
     RECT  2.16 3.915 108 4.185 ;
     RECT  2.16 4.455 108 4.725 ;
     RECT  2.16 4.995 108 5.265 ;
     RECT  2.16 5.535 108 5.805 ;
     RECT  2.16 6.075 108 6.345 ;
     RECT  2.16 6.615 108 6.885 ;
     RECT  2.16 7.155 108 7.425 ;
     RECT  2.16 7.695 108 7.965 ;
     RECT  2.16 8.235 108 8.505 ;
     RECT  2.16 8.775 108 9.045 ;
     RECT  2.16 9.315 108 9.585 ;
     RECT  2.16 9.855 108 10.125 ;
     RECT  2.16 10.395 108 10.665 ;
     RECT  2.16 10.935 108 11.205 ;
     RECT  2.16 11.475 108 11.745 ;
     RECT  2.16 12.015 108 12.285 ;
     RECT  2.16 12.555 108 12.825 ;
     RECT  2.16 13.095 108 13.365 ;
     RECT  2.16 13.635 108 13.905 ;
     RECT  2.16 14.175 108 14.445 ;
     RECT  2.16 14.715 108 14.985 ;
     RECT  2.16 15.255 108 15.525 ;
     RECT  2.16 15.795 108 16.065 ;
     RECT  2.16 16.335 108 16.605 ;
     RECT  2.16 16.875 108 17.145 ;
     RECT  2.16 17.415 108 17.685 ;
     RECT  2.16 17.955 108 18.225 ;
     RECT  2.16 18.495 108 18.765 ;
     RECT  2.16 19.035 108 19.305 ;
     RECT  2.16 19.575 108 19.845 ;
     RECT  2.16 20.115 108 20.385 ;
     RECT  2.16 20.655 108 20.925 ;
     RECT  2.16 21.195 108 21.465 ;
     RECT  2.16 21.735 108 22.005 ;
     RECT  2.16 22.275 108 22.545 ;
     RECT  2.16 22.815 108 23.085 ;
     RECT  2.16 23.355 108 23.625 ;
     RECT  2.16 23.895 108 24.165 ;
     RECT  2.16 24.435 108 24.705 ;
     RECT  2.16 24.975 108 25.245 ;
     RECT  2.16 25.515 108 25.785 ;
     RECT  2.16 26.055 108 26.325 ;
     RECT  2.16 26.595 108 26.865 ;
     RECT  2.16 27.135 108 27.405 ;
     RECT  2.16 27.675 108 27.945 ;
     RECT  2.16 28.215 108 28.485 ;
     RECT  2.16 28.755 108 29.025 ;
     RECT  2.16 29.295 108 29.565 ;
     RECT  2.16 29.835 108 30.105 ;
     RECT  2.16 30.375 108 30.645 ;
     RECT  2.16 30.915 108 31.185 ;
     RECT  2.16 31.455 108 31.725 ;
     RECT  2.16 31.995 108 32.265 ;
     RECT  2.16 32.535 108 32.805 ;
     RECT  2.16 33.075 108 33.345 ;
     RECT  2.16 33.615 108 33.885 ;
     RECT  2.16 34.155 108 34.425 ;
     RECT  2.16 34.695 108 34.965 ;
     RECT  2.16 35.235 108 35.505 ;
     RECT  2.16 35.775 108 36.045 ;
     RECT  2.16 36.315 108 36.585 ;
     RECT  2.16 36.855 108 37.125 ;
     RECT  2.16 37.395 108 37.665 ;
     RECT  2.16 37.935 108 38.205 ;
     RECT  2.16 38.475 108 38.745 ;
     RECT  2.16 39.015 108 39.285 ;
     RECT  2.16 39.555 108 39.825 ;
     RECT  2.16 40.095 108 40.365 ;
     RECT  2.16 40.635 108 40.905 ;
     RECT  2.16 41.175 108 41.445 ;
     RECT  2.16 41.715 108 41.985 ;
     RECT  2.16 42.255 108 42.525 ;
     RECT  2.16 42.795 108 43.065 ;
     RECT  2.16 43.335 108 43.605 ;
     RECT  2.16 43.875 108 44.145 ;
     RECT  2.16 44.415 108 44.685 ;
     RECT  2.16 44.955 108 45.225 ;
     RECT  2.16 45.495 108 45.765 ;
     RECT  2.16 46.035 108 46.305 ;
     RECT  2.16 46.575 108 46.845 ;
     RECT  2.16 47.115 108 47.385 ;
     RECT  2.16 47.655 108 47.925 ;
     RECT  2.16 48.195 108 48.465 ;
     RECT  2.16 48.735 108 49.005 ;
     RECT  2.16 49.275 108 49.545 ;
     RECT  2.16 49.815 108 50.085 ;
     RECT  2.16 50.355 108 50.625 ;
     RECT  2.16 50.895 108 51.165 ;
     RECT  2.16 51.435 108 51.705 ;
     RECT  2.16 51.975 108 52.245 ;
     RECT  2.16 52.515 108 52.785 ;
     RECT  2.16 53.055 108 53.325 ;
     RECT  2.16 53.595 108 53.865 ;
     RECT  2.16 54.135 108 54.405 ;
     RECT  2.16 54.675 108 54.945 ;
     RECT  2.16 55.215 108 55.485 ;
     RECT  2.16 55.755 108 56.025 ;
     RECT  2.16 56.295 108 56.565 ;
     RECT  2.16 56.835 108 57.105 ;
     RECT  2.16 57.375 108 57.645 ;
     RECT  2.16 57.915 108 58.185 ;
     RECT  2.16 58.455 108 58.725 ;
     RECT  2.16 58.995 108 59.265 ;
     RECT  2.16 59.535 108 59.805 ;
     RECT  2.16 60.075 108 60.345 ;
     RECT  2.16 60.615 108 60.885 ;
     RECT  2.16 61.155 108 61.425 ;
     RECT  2.16 61.695 108 61.965 ;
     RECT  2.16 62.235 108 62.505 ;
     RECT  2.16 62.775 108 63.045 ;
     RECT  2.16 63.315 108 63.585 ;
     RECT  2.16 63.855 108 64.125 ;
     RECT  2.16 64.395 108 64.665 ;
     RECT  2.16 64.935 108 65.205 ;
     RECT  2.16 65.475 108 65.745 ;
     RECT  2.16 66.015 108 66.285 ;
     RECT  2.16 66.555 108 66.825 ;
     RECT  2.16 67.095 108 67.365 ;
     RECT  2.16 67.635 108 67.905 ;
     RECT  2.16 68.175 108 68.445 ;
     RECT  2.16 68.715 108 68.985 ;
     RECT  2.16 69.255 108 69.525 ;
     RECT  2.16 69.795 108 70.065 ;
     RECT  2.16 70.335 108 70.605 ;
     RECT  2.16 70.875 108 71.145 ;
     RECT  2.16 71.415 108 71.685 ;
     RECT  2.16 71.955 108 72.225 ;
     RECT  2.16 72.495 108 72.765 ;
     RECT  2.16 73.035 108 73.305 ;
     RECT  2.16 73.575 108 73.845 ;
     RECT  2.16 74.115 108 74.385 ;
     RECT  2.16 74.655 108 74.925 ;
     RECT  2.16 75.195 108 75.465 ;
     RECT  2.16 75.735 108 76.005 ;
     RECT  2.16 76.275 108 76.545 ;
     RECT  2.16 76.815 108 77.085 ;
     RECT  2.16 77.355 108 77.625 ;
     RECT  2.16 77.895 108 78.165 ;
     RECT  2.16 78.435 108 78.705 ;
     RECT  2.16 78.975 108 79.245 ;
     RECT  2.16 79.515 108 79.785 ;
     RECT  2.16 80.055 108 80.325 ;
     RECT  2.16 80.595 108 80.865 ;
     RECT  2.16 81.135 108 81.405 ;
     RECT  2.16 81.675 108 81.945 ;
     RECT  2.16 82.215 108 82.485 ;
     RECT  2.16 82.755 108 83.025 ;
     RECT  2.16 83.295 108 83.565 ;
     RECT  2.16 83.835 108 84.105 ;
     RECT  2.16 84.375 108 84.645 ;
     RECT  2.16 84.915 108 85.185 ;
     RECT  2.16 85.455 108 85.725 ;
     RECT  2.16 85.995 108 86.265 ;
     RECT  2.16 86.535 108 86.805 ;
     RECT  2.16 87.075 108 87.345 ;
     RECT  2.16 87.615 108 87.885 ;
     RECT  2.16 88.155 108 88.425 ;
     RECT  2.16 88.695 108 88.965 ;
     RECT  2.16 89.235 108 89.505 ;
     RECT  2.16 89.775 108 90.045 ;
     RECT  2.16 90.315 108 90.585 ;
     RECT  2.16 90.855 108 91.125 ;
     RECT  2.16 91.395 108 91.665 ;
     RECT  2.16 91.935 108 92.205 ;
     RECT  2.16 92.475 108 92.745 ;
     RECT  2.16 93.015 108 93.285 ;
     RECT  2.16 93.555 108 93.825 ;
     RECT  2.16 94.095 108 94.365 ;
     RECT  2.16 94.635 108 94.905 ;
     RECT  2.16 95.175 108 95.445 ;
     RECT  2.16 95.715 108 95.985 ;
     RECT  2.16 96.255 108 96.525 ;
     RECT  2.16 96.795 108 97.065 ;
     RECT  2.16 97.335 108 97.605 ;
     RECT  2.16 97.875 108 98.145 ;
     RECT  2.16 98.415 108 98.685 ;
     RECT  2.16 98.955 108 99.225 ;
     RECT  2.16 99.495 108 99.765 ;
     RECT  2.16 100.035 108 100.305 ;
     RECT  2.16 100.575 108 100.845 ;
     RECT  2.16 101.115 108 101.385 ;
     RECT  2.16 101.655 108 101.925 ;
     RECT  2.16 102.195 108 102.465 ;
     RECT  2.16 102.735 108 103.005 ;
     RECT  2.16 103.275 108 103.545 ;
     RECT  2.16 103.815 108 104.085 ;
     RECT  2.16 104.355 108 104.625 ;
     RECT  2.16 104.895 108 105.165 ;
     RECT  2.16 105.435 108 105.705 ;
     RECT  2.16 105.975 108 106.245 ;
     RECT  2.16 106.515 108 106.785 ;
     RECT  2.16 107.055 108 107.325 ;
     RECT  2.16 107.595 108 107.865 ;
    LAYER M1 ;
     RECT  2.16 2.151 108 108.009 ;
    LAYER M2 ;
     RECT  0.031 69.804 0.103 69.822 ;
     RECT  0.103 75.204 0.463 75.222 ;
     RECT  0.103 69.804 0.499 70.02 ;
     RECT  0.103 52.992 0.535 54.162 ;
     RECT  0.499 69.804 0.535 70.524 ;
     RECT  0.499 73.926 0.535 73.944 ;
     RECT  0.463 74.826 0.535 75.222 ;
     RECT  0.535 52.452 2.16 54.162 ;
     RECT  0.103 55.26 2.16 55.278 ;
     RECT  0.535 69.498 2.16 70.524 ;
     RECT  0.535 73.926 2.16 75.222 ;
     RECT  0.103 76.86 2.16 76.878 ;
     RECT  2.16 2.151 74.011 108.009 ;
     RECT  74.011 2.106 75.155 108.009 ;
     RECT  75.155 2.151 104.971 108.009 ;
     RECT  104.971 2.106 105.431 108.009 ;
     RECT  105.431 2.151 108 108.009 ;
     RECT  108 52.326 109.463 61.614 ;
     RECT  109.463 52.326 109.499 56.754 ;
     RECT  109.463 57.546 109.499 61.614 ;
     RECT  109.499 52.326 109.535 55.584 ;
     RECT  109.499 56.574 109.535 56.592 ;
     RECT  109.499 60.354 109.535 61.614 ;
     RECT  109.499 58.392 109.571 59.454 ;
     RECT  109.571 58.626 109.607 59.454 ;
     RECT  109.535 52.416 109.679 55.584 ;
     RECT  109.679 52.416 109.751 53.892 ;
     RECT  109.751 52.416 109.787 52.974 ;
     RECT  109.679 55.224 109.931 55.584 ;
     RECT  109.931 55.26 109.967 55.584 ;
     RECT  109.967 55.26 110.003 55.278 ;
     RECT  109.751 53.874 110.039 53.892 ;
     RECT  109.607 58.806 110.039 59.454 ;
     RECT  109.535 60.354 110.039 60.534 ;
     RECT  109.787 52.416 110.075 52.434 ;
     RECT  109.499 57.546 110.075 57.564 ;
     RECT  110.039 58.806 110.075 59.184 ;
     RECT  110.039 60.516 110.075 60.534 ;
     RECT  109.535 61.596 110.075 61.614 ;
    LAYER M3 ;
     RECT  45.615 2.143 45.705 2.191 ;
     RECT  13.215 2.143 13.305 2.227 ;
     RECT  18.615 2.143 18.705 2.227 ;
     RECT  40.215 2.143 40.305 2.227 ;
     RECT  47.484 2.191 47.502 2.227 ;
     RECT  49.104 2.191 49.122 2.227 ;
     RECT  72.615 2.143 72.705 2.227 ;
     RECT  74.016 2.101 74.034 2.227 ;
     RECT  78.015 2.143 78.105 2.227 ;
     RECT  88.815 2.143 88.905 2.227 ;
     RECT  99.615 2.143 99.705 2.227 ;
     RECT  34.815 2.143 34.905 2.251 ;
     RECT  51.015 2.143 51.105 2.251 ;
     RECT  72.615 2.227 74.034 2.251 ;
     RECT  88.704 2.227 88.905 2.251 ;
     RECT  13.215 2.227 13.374 2.263 ;
     RECT  15.228 2.227 15.246 2.263 ;
     RECT  18.252 2.227 18.774 2.263 ;
     RECT  31.14 2.227 31.158 2.263 ;
     RECT  40.068 2.227 40.305 2.263 ;
     RECT  58.716 2.191 58.734 2.263 ;
     RECT  72.615 2.251 74.178 2.263 ;
     RECT  77.688 2.227 78.105 2.263 ;
     RECT  94.215 2.143 94.305 2.263 ;
     RECT  11.376 2.227 11.394 2.299 ;
     RECT  21.24 2.191 21.258 2.299 ;
     RECT  84.312 2.263 84.33 2.299 ;
     RECT  88.416 2.251 89.262 2.299 ;
     RECT  20.376 2.263 20.394 2.335 ;
     RECT  25.992 2.299 26.01 2.335 ;
     RECT  29.415 2.143 29.505 2.335 ;
     RECT  44.172 2.263 44.19 2.335 ;
     RECT  56.415 2.143 56.505 2.335 ;
     RECT  58.716 2.263 58.77 2.335 ;
     RECT  65.196 2.263 65.214 2.335 ;
     RECT  67.215 2.143 67.305 2.335 ;
     RECT  68.112 2.299 68.13 2.335 ;
     RECT  70.74 2.299 70.758 2.335 ;
     RECT  84.312 2.299 84.402 2.335 ;
     RECT  104.976 2.101 105.426 2.335 ;
     RECT  8.784 2.299 8.802 2.371 ;
     RECT  12.348 2.191 12.366 2.371 ;
     RECT  13.215 2.263 13.59 2.371 ;
     RECT  21.24 2.299 22.086 2.371 ;
     RECT  25.992 2.335 26.118 2.371 ;
     RECT  29.415 2.335 29.574 2.371 ;
     RECT  31.14 2.263 31.374 2.371 ;
     RECT  34.2 2.251 34.905 2.371 ;
     RECT  40.068 2.263 40.554 2.371 ;
     RECT  50.4 2.251 51.105 2.371 ;
     RECT  67.104 2.335 68.13 2.371 ;
     RECT  71.64 2.227 71.658 2.371 ;
     RECT  72.396 2.263 74.178 2.371 ;
     RECT  75.132 2.101 75.15 2.371 ;
     RECT  77.472 2.263 78.105 2.371 ;
     RECT  80.568 2.191 80.586 2.371 ;
     RECT  84.276 2.335 84.402 2.371 ;
     RECT  93.852 2.263 94.305 2.371 ;
     RECT  96.264 2.227 96.282 2.371 ;
     RECT  99.18 2.227 99.705 2.371 ;
     RECT  102.744 2.227 102.762 2.371 ;
     RECT  2.415 2.143 2.505 2.413 ;
     RECT  7.815 2.143 7.905 2.413 ;
     RECT  8.784 2.371 9.522 2.413 ;
     RECT  24.015 2.143 24.105 2.413 ;
     RECT  34.2 2.371 34.974 2.413 ;
     RECT  45.108 2.191 45.705 2.413 ;
     RECT  56.16 2.335 56.505 2.413 ;
     RECT  61.815 2.143 61.905 2.413 ;
     RECT  62.676 2.371 62.694 2.413 ;
     RECT  77.364 2.371 78.105 2.413 ;
     RECT  83.415 2.143 83.505 2.413 ;
     RECT  84.276 2.371 85.122 2.413 ;
     RECT  98.892 2.371 99.774 2.413 ;
     RECT  17.244 2.299 17.262 2.461 ;
     RECT  18.252 2.263 19.062 2.461 ;
     RECT  24.015 2.413 24.297 2.461 ;
     RECT  45.108 2.413 45.897 2.461 ;
     RECT  71.64 2.371 74.358 2.461 ;
     RECT  75.132 2.371 75.33 2.461 ;
     RECT  88.308 2.299 89.262 2.461 ;
     RECT  102.564 2.371 103.338 2.461 ;
     RECT  50.4 2.371 52.002 2.488 ;
     RECT  61.815 2.413 62.694 2.491 ;
     RECT  15.228 2.263 15.678 2.497 ;
     RECT  16.416 2.371 16.434 2.497 ;
     RECT  25.992 2.371 26.262 2.497 ;
     RECT  27.072 2.371 27.09 2.497 ;
     RECT  80.568 2.371 80.838 2.497 ;
     RECT  83.415 2.413 85.122 2.497 ;
     RECT  98.892 2.413 99.897 2.497 ;
     RECT  100.836 2.371 100.854 2.497 ;
     RECT  104.904 2.335 105.426 2.497 ;
     RECT  24.015 2.461 24.678 2.533 ;
     RECT  25.884 2.497 26.262 2.533 ;
     RECT  65.052 2.335 65.214 2.533 ;
     RECT  65.988 2.371 68.814 2.533 ;
     RECT  80.496 2.497 80.838 2.533 ;
     RECT  96.264 2.371 96.786 2.533 ;
     RECT  98.892 2.497 100.854 2.533 ;
     RECT  7.815 2.413 9.522 2.569 ;
     RECT  10.296 2.371 10.314 2.569 ;
     RECT  12.348 2.371 13.59 2.569 ;
     RECT  14.364 2.371 14.382 2.569 ;
     RECT  24.015 2.533 26.262 2.569 ;
     RECT  46.8 2.227 47.502 2.569 ;
     RECT  83.415 2.497 85.302 2.569 ;
     RECT  104.904 2.497 105.498 2.569 ;
     RECT  64.26 2.371 64.278 2.587 ;
     RECT  11.376 2.299 11.61 2.605 ;
     RECT  12.348 2.569 14.382 2.605 ;
     RECT  38.484 2.371 38.502 2.605 ;
     RECT  53.424 2.371 53.442 2.605 ;
     RECT  54.576 2.335 54.594 2.605 ;
     RECT  70.02 2.335 70.758 2.605 ;
     RECT  80.496 2.533 81.342 2.605 ;
     RECT  83.232 2.569 85.302 2.605 ;
     RECT  93.852 2.371 94.77 2.605 ;
     RECT  96.264 2.533 96.858 2.605 ;
     RECT  104.112 2.461 104.13 2.605 ;
     RECT  104.904 2.569 105.606 2.605 ;
     RECT  18.252 2.461 19.206 2.641 ;
     RECT  20.232 2.335 20.394 2.641 ;
     RECT  21.24 2.371 22.194 2.641 ;
     RECT  23.508 2.569 26.262 2.641 ;
     RECT  27.072 2.497 27.234 2.641 ;
     RECT  29.415 2.371 31.374 2.641 ;
     RECT  32.256 2.371 33.21 2.641 ;
     RECT  34.2 2.413 35.097 2.641 ;
     RECT  38.196 2.605 38.502 2.641 ;
     RECT  44.064 2.335 44.19 2.641 ;
     RECT  45.108 2.461 45.954 2.641 ;
     RECT  48.636 2.227 49.122 2.641 ;
     RECT  50.4 2.488 52.326 2.641 ;
     RECT  53.388 2.605 53.442 2.641 ;
     RECT  54.576 2.605 54.954 2.641 ;
     RECT  56.16 2.413 56.697 2.641 ;
     RECT  57.564 2.371 57.582 2.641 ;
     RECT  58.356 2.335 58.77 2.641 ;
     RECT  60.768 2.605 60.786 2.641 ;
     RECT  61.815 2.491 63.234 2.641 ;
     RECT  64.224 2.587 64.278 2.641 ;
     RECT  65.052 2.533 68.814 2.641 ;
     RECT  69.912 2.605 70.758 2.641 ;
     RECT  71.64 2.461 75.33 2.641 ;
     RECT  76.608 2.491 76.626 2.641 ;
     RECT  77.364 2.413 78.297 2.641 ;
     RECT  79.092 2.227 79.11 2.641 ;
     RECT  80.496 2.605 81.486 2.641 ;
     RECT  82.332 2.569 82.35 2.641 ;
     RECT  86.868 2.605 86.886 2.641 ;
     RECT  88.308 2.461 89.766 2.641 ;
     RECT  90.828 2.605 90.846 2.641 ;
     RECT  92.124 2.371 92.142 2.641 ;
     RECT  93.096 2.227 93.114 2.641 ;
     RECT  93.852 2.605 94.806 2.641 ;
     RECT  96.264 2.605 96.93 2.641 ;
     RECT  97.74 2.497 97.758 2.641 ;
     RECT  98.676 2.533 100.854 2.641 ;
     RECT  7.815 2.569 10.314 2.731 ;
     RECT  11.052 2.605 14.382 2.731 ;
     RECT  20.232 2.641 22.194 2.731 ;
     RECT  23.4 2.641 27.234 2.731 ;
     RECT  37.08 2.371 37.098 2.731 ;
     RECT  38.196 2.641 38.718 2.731 ;
     RECT  50.4 2.641 57.582 2.731 ;
     RECT  65.052 2.641 70.758 2.731 ;
     RECT  79.092 2.641 82.494 2.731 ;
     RECT  83.232 2.605 85.41 2.731 ;
     RECT  20.232 2.731 27.234 2.759 ;
     RECT  104.112 2.605 105.606 2.759 ;
     RECT  7.815 2.731 14.382 2.767 ;
     RECT  15.228 2.497 16.434 2.767 ;
     RECT  37.08 2.731 37.35 2.767 ;
     RECT  38.196 2.731 38.826 2.767 ;
     RECT  58.356 2.641 59.49 2.767 ;
     RECT  60.768 2.641 60.894 2.767 ;
     RECT  61.74 2.641 63.378 2.767 ;
     RECT  64.152 2.641 64.278 2.767 ;
     RECT  65.052 2.731 70.902 2.767 ;
     RECT  91.692 2.641 92.142 2.767 ;
     RECT  93.096 2.641 94.914 2.767 ;
     RECT  95.724 2.641 96.93 2.767 ;
     RECT  7.056 2.767 7.074 2.803 ;
     RECT  7.815 2.767 16.434 2.803 ;
     RECT  17.244 2.461 17.334 2.803 ;
     RECT  28.008 2.497 28.026 2.803 ;
     RECT  45 2.641 45.954 2.803 ;
     RECT  46.8 2.569 47.826 2.803 ;
     RECT  50.4 2.731 57.618 2.803 ;
     RECT  58.356 2.767 59.67 2.803 ;
     RECT  64.152 2.767 70.902 2.803 ;
     RECT  71.64 2.641 78.297 2.803 ;
     RECT  79.092 2.731 85.41 2.803 ;
     RECT  102.096 2.461 103.338 2.803 ;
     RECT  104.112 2.759 105.534 2.803 ;
     RECT  101.988 2.803 105.534 2.813 ;
     RECT  27.936 2.803 28.026 2.839 ;
     RECT  37.08 2.767 38.826 2.839 ;
     RECT  44.064 2.641 44.226 2.839 ;
     RECT  45 2.803 47.826 2.839 ;
     RECT  50.4 2.803 59.958 2.839 ;
     RECT  60.768 2.767 63.378 2.839 ;
     RECT  86.148 2.641 90.918 2.839 ;
     RECT  91.692 2.767 96.93 2.839 ;
     RECT  97.74 2.641 101.25 2.839 ;
     RECT  101.988 2.813 105.498 2.839 ;
     RECT  29.376 2.641 33.246 2.869 ;
     RECT  20.232 2.759 27.126 2.875 ;
     RECT  27.936 2.839 28.134 2.875 ;
     RECT  29.376 2.869 33.282 2.875 ;
     RECT  40.068 2.371 41.274 2.875 ;
     RECT  50.4 2.839 63.378 2.875 ;
     RECT  64.152 2.803 85.41 2.875 ;
     RECT  86.148 2.839 96.93 2.875 ;
     RECT  7.056 2.803 17.334 2.911 ;
     RECT  18.144 2.641 19.206 2.911 ;
     RECT  27.936 2.875 33.282 2.911 ;
     RECT  34.2 2.641 36.054 2.911 ;
     RECT  36.972 2.839 38.826 2.911 ;
     RECT  44.064 2.839 47.826 2.911 ;
     RECT  48.636 2.641 49.446 2.911 ;
     RECT  36.972 2.911 38.934 2.939 ;
     RECT  39.96 2.875 41.274 3.001 ;
     RECT  50.4 2.875 96.966 3.037 ;
     RECT  97.74 2.839 105.498 3.037 ;
     RECT  7.056 2.911 19.242 3.145 ;
     RECT  50.4 3.037 105.498 3.145 ;
     RECT  50.328 3.145 105.498 3.173 ;
     RECT  37.008 2.939 38.934 3.181 ;
     RECT  39.672 3.001 41.274 3.181 ;
     RECT  43.812 2.911 49.446 3.181 ;
     RECT  50.328 3.173 71.658 3.181 ;
     RECT  7.056 3.145 19.314 3.271 ;
     RECT  20.088 2.875 27.126 3.271 ;
     RECT  27.936 2.911 36.054 3.299 ;
     RECT  43.812 3.181 71.658 3.335 ;
     RECT  5.868 3.271 6.138 3.379 ;
     RECT  6.948 3.271 27.126 3.379 ;
     RECT  37.008 3.181 41.274 3.451 ;
     RECT  42.156 3.271 42.174 3.451 ;
     RECT  43.812 3.335 48.69 3.451 ;
     RECT  49.428 3.335 71.658 3.569 ;
     RECT  27.936 3.299 33.93 3.605 ;
     RECT  5.724 3.379 27.126 3.649 ;
     RECT  5.724 3.649 27.162 3.685 ;
     RECT  37.008 3.451 42.174 3.685 ;
     RECT  43.56 3.451 48.69 3.685 ;
     RECT  72.396 3.173 105.498 3.685 ;
     RECT  5.58 3.685 27.162 3.721 ;
     RECT  5.58 3.721 27.198 3.811 ;
     RECT  27.936 3.605 33.678 3.811 ;
     RECT  36.864 3.685 42.174 3.839 ;
     RECT  72.396 3.685 106.038 3.839 ;
     RECT  72.396 3.839 105.894 3.911 ;
     RECT  34.704 3.299 36.054 3.919 ;
     RECT  36.864 3.839 41.454 3.919 ;
     RECT  43.128 3.685 48.69 3.991 ;
     RECT  60.984 3.569 71.658 3.991 ;
     RECT  72.396 3.911 97.038 3.991 ;
     RECT  42.372 3.991 48.69 4.225 ;
     RECT  49.428 3.569 60.102 4.225 ;
     RECT  34.704 3.919 41.454 4.315 ;
     RECT  42.372 4.225 60.102 4.387 ;
     RECT  5.58 3.811 33.678 4.411 ;
     RECT  5.58 4.411 33.786 4.459 ;
     RECT  60.984 3.991 97.038 4.493 ;
     RECT  42.372 4.387 60.21 4.531 ;
     RECT  60.984 4.493 67.698 4.531 ;
     RECT  5.58 4.459 33.858 4.555 ;
     RECT  34.668 4.315 41.454 4.555 ;
     RECT  5.58 4.555 41.454 4.589 ;
     RECT  42.372 4.531 67.698 4.801 ;
     RECT  68.508 4.493 97.038 4.801 ;
     RECT  97.848 3.911 105.894 4.801 ;
     RECT  68.508 4.801 97.074 4.991 ;
     RECT  80.964 4.991 97.074 5.161 ;
     RECT  97.848 4.801 105.966 5.161 ;
     RECT  5.724 4.589 41.454 5.269 ;
     RECT  42.228 4.801 67.698 5.269 ;
     RECT  5.724 5.269 67.698 5.495 ;
     RECT  80.964 5.161 106.11 5.531 ;
     RECT  42.66 5.495 67.698 5.611 ;
     RECT  68.508 4.991 80.118 5.611 ;
     RECT  5.724 5.495 41.778 5.707 ;
     RECT  5.112 5.707 41.778 5.729 ;
     RECT  102.384 5.531 106.11 5.737 ;
     RECT  102.384 5.737 106.542 5.773 ;
     RECT  42.66 5.611 80.118 5.803 ;
     RECT  80.964 5.531 101.646 5.803 ;
     RECT  2.415 2.413 2.697 5.881 ;
     RECT  3.672 5.701 3.69 5.881 ;
     RECT  102.384 5.773 106.758 5.881 ;
     RECT  32.364 5.729 41.778 5.909 ;
     RECT  2.415 5.881 4.086 5.971 ;
     RECT  2.415 5.971 4.194 5.995 ;
     RECT  33.336 5.909 41.778 6.077 ;
     RECT  102.384 5.881 107.082 6.151 ;
     RECT  2.415 5.995 4.266 6.421 ;
     RECT  42.66 5.803 101.646 6.421 ;
     RECT  102.384 6.151 107.406 6.421 ;
     RECT  42.66 6.421 107.406 6.539 ;
     RECT  5.112 5.729 31.626 6.547 ;
     RECT  32.364 5.909 32.382 6.547 ;
     RECT  2.415 6.421 4.338 6.583 ;
     RECT  5.112 6.547 32.382 6.583 ;
     RECT  84.708 6.539 107.406 6.683 ;
     RECT  2.415 6.583 32.382 6.691 ;
     RECT  33.336 6.077 41.598 6.691 ;
     RECT  42.66 6.539 83.934 6.925 ;
     RECT  2.415 6.691 41.598 6.953 ;
     RECT  16.632 6.953 41.598 7.189 ;
     RECT  42.588 6.925 83.934 7.189 ;
     RECT  16.632 7.189 83.934 7.349 ;
     RECT  16.632 7.349 69.57 7.493 ;
     RECT  84.708 6.683 107.118 7.501 ;
     RECT  84.708 7.501 107.262 7.619 ;
     RECT  70.344 7.349 83.934 7.627 ;
     RECT  84.708 7.619 103.194 7.627 ;
     RECT  103.932 7.619 107.262 7.663 ;
     RECT  16.668 7.493 69.57 8.167 ;
     RECT  70.344 7.627 103.194 8.167 ;
     RECT  2.415 6.953 15.894 8.239 ;
     RECT  16.668 8.167 103.194 8.239 ;
     RECT  2.415 8.239 103.194 8.401 ;
     RECT  103.932 7.663 107.334 8.401 ;
     RECT  2.415 8.401 107.334 8.429 ;
     RECT  42.516 8.429 107.334 8.465 ;
     RECT  42.516 8.465 107.226 8.537 ;
     RECT  2.415 8.429 41.742 9.053 ;
     RECT  42.516 8.537 107.154 9.113 ;
     RECT  5.724 9.053 41.742 9.661 ;
     RECT  42.516 9.113 107.118 9.661 ;
     RECT  2.415 9.053 4.878 9.931 ;
     RECT  5.724 9.661 107.118 9.931 ;
     RECT  2.415 9.931 107.118 10.093 ;
     RECT  2.415 10.093 107.154 10.165 ;
     RECT  2.376 10.165 107.154 10.669 ;
     RECT  2.376 10.669 107.226 10.895 ;
     RECT  33.516 10.895 107.226 11.011 ;
     RECT  2.376 10.895 32.778 11.039 ;
     RECT  2.376 11.039 32.67 11.273 ;
     RECT  33.516 11.011 107.37 11.669 ;
     RECT  2.415 11.273 32.67 11.785 ;
     RECT  33.516 11.669 107.262 11.785 ;
     RECT  2.415 11.785 107.262 12.479 ;
     RECT  2.415 12.479 107.19 12.551 ;
     RECT  2.415 12.551 107.154 13.433 ;
     RECT  39.924 13.433 107.154 13.469 ;
     RECT  39.924 13.469 95.85 13.595 ;
     RECT  96.588 13.469 107.154 13.639 ;
     RECT  2.415 13.433 39.186 14.009 ;
     RECT  3.636 14.009 39.186 14.099 ;
     RECT  3.636 14.099 26.586 14.135 ;
     RECT  27.432 14.099 39.186 14.341 ;
     RECT  39.96 13.595 95.85 14.341 ;
     RECT  27.432 14.341 95.85 14.675 ;
     RECT  74.628 14.675 95.85 14.827 ;
     RECT  96.588 13.639 107.19 14.827 ;
     RECT  3.708 14.135 26.586 14.917 ;
     RECT  27.432 14.675 73.818 14.917 ;
     RECT  74.628 14.827 107.19 15.025 ;
     RECT  2.415 14.009 2.898 15.061 ;
     RECT  3.708 14.917 73.818 15.061 ;
     RECT  74.628 15.025 107.334 15.359 ;
     RECT  74.628 15.359 98.118 15.499 ;
     RECT  2.415 15.061 73.818 15.601 ;
     RECT  74.592 15.499 98.118 15.601 ;
     RECT  98.892 15.359 107.334 15.719 ;
     RECT  2.415 15.601 98.118 16.339 ;
     RECT  98.892 15.719 106.938 16.339 ;
     RECT  2.415 16.339 106.938 16.403 ;
     RECT  88.74 16.403 106.938 16.843 ;
     RECT  88.74 16.843 106.974 16.915 ;
     RECT  2.415 16.403 88.002 17.149 ;
     RECT  88.74 16.915 107.118 17.149 ;
     RECT  107.856 17.491 107.874 17.609 ;
     RECT  2.415 17.149 107.118 17.753 ;
     RECT  2.415 17.753 97.29 18.535 ;
     RECT  98.028 17.753 107.118 18.535 ;
     RECT  2.415 18.535 107.118 19.075 ;
     RECT  2.415 19.075 107.19 19.499 ;
     RECT  2.415 19.499 107.118 20.579 ;
     RECT  38.88 20.579 107.118 20.731 ;
     RECT  38.88 20.731 107.154 20.849 ;
     RECT  38.916 20.849 107.154 21.001 ;
     RECT  38.916 21.001 107.19 21.299 ;
     RECT  2.415 20.579 38.106 21.547 ;
     RECT  2.415 21.547 38.178 21.667 ;
     RECT  38.916 21.299 107.118 21.667 ;
     RECT  2.415 21.667 107.118 24.475 ;
     RECT  2.415 24.475 107.19 25.015 ;
     RECT  2.415 25.015 107.226 25.619 ;
     RECT  2.415 25.619 107.19 26.015 ;
     RECT  100.8 26.015 107.19 26.663 ;
     RECT  2.415 26.015 99.897 26.941 ;
     RECT  100.8 26.663 107.154 26.941 ;
     RECT  2.415 26.941 107.154 27.059 ;
     RECT  2.415 27.059 107.082 27.131 ;
     RECT  2.415 27.131 38.574 27.751 ;
     RECT  2.376 27.751 38.574 28.021 ;
     RECT  39.348 27.131 107.082 28.021 ;
     RECT  2.376 28.021 107.226 28.561 ;
     RECT  2.376 28.561 107.262 28.751 ;
     RECT  2.376 28.751 107.19 29.399 ;
     RECT  2.376 29.399 107.154 30.181 ;
     RECT  2.376 30.181 107.19 30.299 ;
     RECT  2.376 30.299 107.154 30.371 ;
     RECT  2.376 30.371 107.118 30.605 ;
     RECT  2.415 30.605 107.118 31.261 ;
     RECT  2.415 31.261 107.478 31.721 ;
     RECT  2.415 31.721 107.334 32.297 ;
     RECT  2.415 32.297 107.118 33.421 ;
     RECT  2.415 33.421 107.154 34.051 ;
     RECT  2.415 34.051 107.226 34.763 ;
     RECT  2.415 34.763 107.19 35.311 ;
     RECT  2.34 35.311 107.19 35.509 ;
     RECT  2.34 35.509 107.226 35.735 ;
     RECT  2.34 35.735 107.19 36.787 ;
     RECT  2.34 36.787 107.298 36.959 ;
     RECT  2.34 36.959 36.99 37.319 ;
     RECT  2.34 37.319 4.554 37.355 ;
     RECT  5.364 37.319 36.99 37.723 ;
     RECT  37.764 36.959 107.298 37.723 ;
     RECT  5.364 37.723 107.298 37.831 ;
     RECT  2.34 37.355 4.446 38.137 ;
     RECT  5.364 37.831 107.334 38.137 ;
     RECT  2.34 38.137 107.334 38.237 ;
     RECT  2.34 38.237 96.534 39.253 ;
     RECT  97.308 38.237 107.334 39.253 ;
     RECT  2.34 39.253 107.334 39.479 ;
     RECT  2.34 39.479 96.498 39.893 ;
     RECT  97.236 39.479 107.334 39.917 ;
     RECT  97.308 39.917 107.334 40.019 ;
     RECT  97.452 40.019 107.334 40.325 ;
     RECT  2.34 39.893 9.27 40.675 ;
     RECT  10.008 39.893 96.498 40.675 ;
     RECT  2.34 40.675 96.498 41.371 ;
     RECT  97.56 40.325 107.334 41.449 ;
     RECT  2.34 41.371 96.822 41.521 ;
     RECT  97.56 41.449 107.442 41.521 ;
     RECT  2.34 41.521 107.442 41.819 ;
     RECT  2.34 41.819 107.334 41.909 ;
     RECT  2.34 41.909 107.226 42.485 ;
     RECT  58.896 42.485 107.226 42.799 ;
     RECT  58.896 42.799 107.262 43.141 ;
     RECT  2.34 42.485 58.014 43.267 ;
     RECT  58.896 43.141 107.334 43.267 ;
     RECT  2.34 43.267 107.334 43.331 ;
     RECT  87.804 43.331 107.334 43.529 ;
     RECT  87.804 43.529 107.262 43.871 ;
     RECT  2.34 43.331 87.03 44.149 ;
     RECT  2.34 44.149 87.066 44.221 ;
     RECT  87.804 43.871 107.154 44.249 ;
     RECT  2.304 44.221 87.066 44.609 ;
     RECT  87.804 44.249 107.118 44.995 ;
     RECT  86.832 44.609 87.066 45.019 ;
     RECT  87.804 44.995 107.154 45.019 ;
     RECT  86.832 45.019 107.154 45.301 ;
     RECT  86.832 45.301 107.19 45.427 ;
     RECT  2.304 44.609 86.094 45.451 ;
     RECT  86.832 45.427 107.298 45.451 ;
     RECT  2.304 45.451 107.298 45.527 ;
     RECT  106.776 45.527 107.298 45.571 ;
     RECT  2.304 45.527 105.75 45.689 ;
     RECT  106.776 45.571 107.406 45.841 ;
     RECT  106.776 45.841 107.55 46.031 ;
     RECT  106.776 46.031 107.442 46.139 ;
     RECT  106.776 46.139 107.37 46.273 ;
     RECT  12.132 45.689 105.75 46.309 ;
     RECT  12.132 46.309 105.822 46.409 ;
     RECT  106.704 46.273 107.37 46.409 ;
     RECT  2.304 45.689 10.854 46.471 ;
     RECT  106.704 46.409 107.226 46.499 ;
     RECT  12.132 46.409 89.586 46.571 ;
     RECT  2.304 46.471 11.286 46.615 ;
     RECT  12.132 46.571 86.922 46.615 ;
     RECT  87.732 46.571 89.586 47.317 ;
     RECT  90.324 46.409 105.822 47.317 ;
     RECT  87.732 47.317 105.822 47.419 ;
     RECT  106.704 46.499 107.118 47.453 ;
     RECT  87.732 47.419 105.93 47.459 ;
     RECT  2.304 46.615 86.922 47.461 ;
     RECT  87.732 47.459 105.894 47.461 ;
     RECT  106.704 47.453 107.082 47.551 ;
     RECT  2.304 47.461 105.894 47.849 ;
     RECT  97.488 47.849 103.59 47.885 ;
     RECT  97.488 47.885 103.482 47.993 ;
     RECT  101.412 47.993 103.482 48.119 ;
     RECT  2.304 47.849 96.318 48.155 ;
     RECT  104.328 47.849 105.894 48.199 ;
     RECT  106.668 47.551 107.082 48.199 ;
     RECT  104.328 48.199 107.082 48.271 ;
     RECT  101.628 48.119 103.482 48.739 ;
     RECT  104.328 48.271 107.406 48.739 ;
     RECT  97.488 47.993 100.674 48.763 ;
     RECT  95.76 48.155 96.318 48.811 ;
     RECT  101.628 48.739 107.406 48.811 ;
     RECT  97.488 48.763 100.746 48.901 ;
     RECT  101.628 48.811 107.802 48.901 ;
     RECT  97.488 48.901 107.802 48.929 ;
     RECT  2.304 48.155 94.77 48.937 ;
     RECT  95.76 48.811 96.75 48.937 ;
     RECT  97.488 48.929 107.406 48.937 ;
     RECT  2.304 48.937 107.406 49.343 ;
     RECT  2.304 49.343 107.046 49.379 ;
     RECT  2.304 49.379 106.902 49.565 ;
     RECT  2.304 49.565 99.918 50.431 ;
     RECT  100.728 49.565 106.902 50.431 ;
     RECT  2.304 50.431 106.902 51.331 ;
     RECT  2.304 51.331 107.082 51.511 ;
     RECT  2.304 51.511 107.874 51.737 ;
     RECT  109.512 52.321 109.53 52.411 ;
     RECT  2.304 51.737 107.802 52.439 ;
     RECT  0.54 52.447 0.558 52.555 ;
     RECT  2.304 52.439 107.406 52.795 ;
     RECT  2.196 52.795 107.406 52.973 ;
     RECT  2.268 52.973 107.406 52.979 ;
     RECT  0.108 52.555 0.558 53.069 ;
     RECT  104.148 52.979 107.406 53.401 ;
     RECT  104.148 53.401 107.55 53.591 ;
     RECT  2.268 52.979 103.374 53.869 ;
     RECT  104.148 53.591 106.938 53.869 ;
     RECT  0.108 53.069 0.198 53.941 ;
     RECT  109.512 52.411 110.07 53.941 ;
     RECT  2.268 53.869 106.938 54.059 ;
     RECT  0.108 53.941 0.558 54.317 ;
     RECT  0.18 54.317 0.558 54.365 ;
     RECT  2.268 54.059 106.362 54.445 ;
     RECT  107.172 54.607 107.478 54.667 ;
     RECT  0.504 54.365 0.558 54.712 ;
     RECT  107.172 54.667 107.55 54.715 ;
     RECT  0.504 54.712 0.522 54.797 ;
     RECT  109.44 53.941 110.07 54.859 ;
     RECT  108.828 54.859 110.07 54.905 ;
     RECT  107.172 54.715 107.658 54.949 ;
     RECT  109.548 54.905 110.07 54.989 ;
     RECT  2.232 54.445 106.362 55.021 ;
     RECT  107.1 54.949 107.658 55.021 ;
     RECT  2.232 55.021 107.658 55.085 ;
     RECT  109.584 54.989 110.07 55.085 ;
     RECT  2.268 55.085 107.658 55.175 ;
     RECT  109.62 55.085 110.07 55.181 ;
     RECT  0.108 55.255 0.126 55.373 ;
     RECT  109.656 55.181 110.07 55.565 ;
     RECT  2.268 55.175 107.442 55.589 ;
     RECT  2.268 55.589 106.65 55.661 ;
     RECT  109.656 55.565 110.034 55.661 ;
     RECT  109.656 55.661 109.998 55.853 ;
     RECT  2.304 55.661 106.65 55.859 ;
     RECT  109.656 55.853 109.962 55.921 ;
     RECT  109.476 55.921 109.962 55.949 ;
     RECT  107.388 55.589 107.442 55.957 ;
     RECT  109.476 55.949 109.926 55.957 ;
     RECT  107.388 55.957 107.586 56.011 ;
     RECT  108.792 55.957 109.926 56.429 ;
     RECT  93.708 55.859 106.65 56.587 ;
     RECT  107.388 56.011 107.658 56.587 ;
     RECT  93.708 56.587 107.658 56.641 ;
     RECT  108.792 56.429 109.53 56.641 ;
     RECT  2.304 55.859 92.934 56.731 ;
     RECT  93.708 56.641 109.53 56.731 ;
     RECT  2.304 56.731 109.53 56.939 ;
     RECT  108.324 56.939 109.53 57.005 ;
     RECT  108.828 57.005 109.53 57.101 ;
     RECT  109.44 57.101 109.53 57.485 ;
     RECT  109.476 57.485 109.53 57.541 ;
     RECT  2.304 56.939 107.298 57.691 ;
     RECT  109.476 57.541 110.07 58.411 ;
     RECT  2.304 57.691 107.514 58.507 ;
     RECT  108.324 58.495 108.342 58.637 ;
     RECT  2.304 58.507 107.55 59.495 ;
     RECT  109.44 58.411 110.07 59.501 ;
     RECT  2.304 59.495 107.298 59.567 ;
     RECT  109.44 59.501 109.53 59.597 ;
     RECT  109.44 59.597 109.494 59.611 ;
     RECT  109.404 59.611 109.494 59.881 ;
     RECT  108.828 59.881 109.494 59.947 ;
     RECT  108.324 59.947 109.494 60.269 ;
     RECT  109.44 60.269 109.494 60.331 ;
     RECT  2.304 59.567 107.154 60.619 ;
     RECT  108.324 60.269 108.342 60.619 ;
     RECT  2.304 60.619 108.342 60.851 ;
     RECT  109.44 60.331 110.07 61.003 ;
     RECT  2.304 60.851 107.802 61.187 ;
     RECT  109.404 61.003 110.07 61.195 ;
     RECT  109.368 61.195 110.07 61.232 ;
     RECT  109.404 61.232 110.07 61.349 ;
     RECT  109.44 61.349 110.07 61.529 ;
     RECT  110.052 61.529 110.07 61.619 ;
     RECT  2.304 61.187 107.658 62.041 ;
     RECT  2.304 62.041 107.694 62.545 ;
     RECT  2.304 62.545 107.874 62.699 ;
     RECT  2.304 62.699 107.262 64.049 ;
     RECT  2.304 64.049 107.19 64.121 ;
     RECT  2.304 64.121 107.118 65.273 ;
     RECT  104.328 65.273 107.118 65.435 ;
     RECT  2.304 65.273 103.518 65.975 ;
     RECT  104.472 65.435 107.118 66.325 ;
     RECT  29.052 65.975 103.518 66.361 ;
     RECT  29.052 66.361 103.662 66.631 ;
     RECT  104.472 66.325 107.154 66.631 ;
     RECT  2.304 65.975 28.242 66.749 ;
     RECT  26.784 66.749 28.242 67.135 ;
     RECT  29.052 66.631 107.262 67.135 ;
     RECT  26.784 67.135 107.262 67.171 ;
     RECT  2.304 66.749 26.01 67.199 ;
     RECT  26.784 67.171 107.334 67.441 ;
     RECT  2.34 67.199 26.01 67.567 ;
     RECT  26.784 67.441 107.73 67.567 ;
     RECT  2.34 67.567 107.73 67.739 ;
     RECT  2.34 67.739 107.154 68.099 ;
     RECT  2.34 68.099 51.318 68.135 ;
     RECT  52.056 68.099 107.154 68.485 ;
     RECT  52.056 68.485 107.19 68.783 ;
     RECT  6.552 68.135 51.318 68.881 ;
     RECT  52.056 68.783 107.046 68.881 ;
     RECT  6.552 68.881 107.046 68.945 ;
     RECT  2.34 68.135 5.814 68.953 ;
     RECT  6.552 68.945 107.01 68.953 ;
     RECT  107.784 69.061 107.802 69.179 ;
     RECT  2.34 68.953 107.01 69.763 ;
     RECT  0.54 69.493 0.558 69.799 ;
     RECT  2.34 69.763 107.118 70.061 ;
     RECT  0.036 69.799 0.558 70.541 ;
     RECT  2.34 70.061 107.082 70.699 ;
     RECT  2.304 70.699 107.082 70.951 ;
     RECT  0.036 70.541 0.522 71.021 ;
     RECT  2.304 70.951 107.154 71.105 ;
     RECT  2.34 71.105 107.154 71.609 ;
     RECT  2.34 71.609 107.118 72.571 ;
     RECT  2.34 72.571 107.19 72.841 ;
     RECT  2.34 72.841 107.586 73.499 ;
     RECT  0.036 71.021 0.054 73.921 ;
     RECT  0.036 73.921 0.522 74.389 ;
     RECT  0.036 74.389 1.17 74.489 ;
     RECT  0.036 74.489 0.558 74.861 ;
     RECT  2.34 73.499 107.154 75.461 ;
     RECT  0.108 74.861 0.558 75.533 ;
     RECT  0.108 75.533 0.342 75.629 ;
     RECT  0.144 75.629 0.342 75.725 ;
     RECT  29.088 75.461 107.154 75.811 ;
     RECT  1.152 75.691 1.17 75.821 ;
     RECT  2.34 75.461 28.35 75.883 ;
     RECT  29.088 75.811 107.19 76.045 ;
     RECT  29.088 76.045 107.658 76.109 ;
     RECT  29.124 76.109 107.658 76.199 ;
     RECT  93.24 76.199 107.658 76.235 ;
     RECT  93.276 76.235 107.658 76.271 ;
     RECT  2.304 75.883 28.35 76.351 ;
     RECT  0.324 75.725 0.342 76.493 ;
     RECT  2.304 76.351 28.386 76.513 ;
     RECT  107.64 76.271 107.658 76.739 ;
     RECT  0.108 76.855 0.162 76.973 ;
     RECT  29.124 76.199 92.43 76.981 ;
     RECT  93.276 76.271 106.83 77.009 ;
     RECT  104.544 77.009 106.83 77.125 ;
     RECT  2.268 76.513 28.386 77.251 ;
     RECT  29.124 76.981 92.502 77.251 ;
     RECT  93.276 77.009 103.698 77.251 ;
     RECT  2.268 77.251 103.698 77.659 ;
     RECT  2.196 77.659 103.698 77.791 ;
     RECT  104.544 77.125 107.118 77.791 ;
     RECT  2.196 77.791 107.118 77.837 ;
     RECT  0.144 76.973 0.162 77.885 ;
     RECT  2.304 77.837 107.118 77.963 ;
     RECT  2.34 77.963 107.118 78.061 ;
     RECT  2.34 78.061 107.262 78.089 ;
     RECT  104.724 78.089 107.262 78.403 ;
     RECT  2.34 78.089 103.698 78.665 ;
     RECT  2.376 78.665 103.698 78.907 ;
     RECT  104.724 78.403 107.298 78.907 ;
     RECT  2.376 78.907 107.298 79.745 ;
     RECT  2.415 79.745 107.298 80.293 ;
     RECT  2.415 80.293 107.442 80.329 ;
     RECT  2.415 80.329 107.658 81.509 ;
     RECT  2.415 81.509 107.514 81.751 ;
     RECT  2.376 81.751 107.514 83.561 ;
     RECT  2.376 83.561 107.478 84.299 ;
     RECT  2.376 84.299 107.262 85.459 ;
     RECT  2.376 85.459 107.37 85.919 ;
     RECT  2.376 85.919 107.118 85.991 ;
     RECT  2.415 85.991 107.118 86.809 ;
     RECT  2.415 86.809 107.154 87.619 ;
     RECT  2.415 87.619 107.334 88.051 ;
     RECT  2.376 88.051 107.334 88.109 ;
     RECT  2.415 88.109 107.334 88.397 ;
     RECT  27.288 88.397 107.334 88.691 ;
     RECT  2.415 88.397 26.334 89.323 ;
     RECT  2.415 89.323 26.37 89.401 ;
     RECT  27.288 88.691 107.298 89.401 ;
     RECT  2.415 89.401 107.298 89.815 ;
     RECT  2.415 89.815 107.334 90.005 ;
     RECT  2.415 90.005 98.766 90.275 ;
     RECT  99.576 90.005 107.334 90.509 ;
     RECT  2.415 90.275 98.586 90.625 ;
     RECT  99.576 90.509 107.226 90.859 ;
     RECT  2.376 90.625 98.586 91.147 ;
     RECT  99.504 90.859 107.226 91.147 ;
     RECT  2.376 91.147 107.226 92.309 ;
     RECT  2.376 92.309 24.822 92.435 ;
     RECT  2.376 92.435 6.75 92.515 ;
     RECT  2.34 92.515 6.75 92.813 ;
     RECT  25.632 92.309 107.226 92.983 ;
     RECT  7.56 92.435 24.822 93.055 ;
     RECT  25.632 92.983 107.262 93.055 ;
     RECT  7.56 93.055 107.262 93.217 ;
     RECT  2.415 92.813 6.75 93.325 ;
     RECT  7.56 93.217 107.298 93.325 ;
     RECT  2.415 93.325 107.298 94.019 ;
     RECT  35.964 94.019 107.298 94.135 ;
     RECT  2.415 94.019 35.19 94.219 ;
     RECT  35.964 94.135 107.442 94.361 ;
     RECT  2.376 94.219 35.19 94.433 ;
     RECT  7.815 94.433 35.19 94.829 ;
     RECT  2.376 94.433 7.074 94.865 ;
     RECT  35.964 94.361 107.334 94.945 ;
     RECT  35.856 94.945 107.334 95.171 ;
     RECT  35.856 95.171 107.298 95.207 ;
     RECT  2.376 94.865 6.966 95.369 ;
     RECT  7.815 94.829 35.097 95.899 ;
     RECT  35.856 95.207 107.262 95.899 ;
     RECT  2.376 95.369 6.93 95.909 ;
     RECT  7.815 95.899 107.262 95.989 ;
     RECT  2.415 95.909 6.93 96.331 ;
     RECT  7.815 95.989 107.334 96.331 ;
     RECT  2.415 96.331 107.334 96.719 ;
     RECT  2.415 96.719 107.154 97.979 ;
     RECT  2.415 97.979 107.118 98.483 ;
     RECT  69.228 98.483 107.118 99.031 ;
     RECT  2.415 98.483 68.49 99.571 ;
     RECT  69.228 99.031 107.334 99.571 ;
     RECT  2.376 99.571 107.334 99.869 ;
     RECT  2.376 99.869 107.046 100.229 ;
     RECT  2.415 100.229 107.046 100.265 ;
     RECT  9 100.265 107.046 100.301 ;
     RECT  9.252 100.301 107.046 100.769 ;
     RECT  35.82 100.769 107.046 100.883 ;
     RECT  2.415 100.265 8.19 101.011 ;
     RECT  2.376 101.011 8.19 101.069 ;
     RECT  2.415 101.069 8.19 101.191 ;
     RECT  9.252 100.769 35.097 101.191 ;
     RECT  35.892 100.883 107.046 101.309 ;
     RECT  2.415 101.191 35.097 102.001 ;
     RECT  35.928 101.309 107.046 102.029 ;
     RECT  99.144 102.029 107.046 102.155 ;
     RECT  99.144 102.155 106.974 102.263 ;
     RECT  35.928 102.029 98.262 102.397 ;
     RECT  35.856 102.397 98.262 102.469 ;
     RECT  2.376 102.001 35.097 102.667 ;
     RECT  35.82 102.469 98.262 102.667 ;
     RECT  2.376 102.667 98.262 102.901 ;
     RECT  2.376 102.901 98.37 103.009 ;
     RECT  2.376 103.009 98.406 103.073 ;
     RECT  2.412 103.073 98.406 103.081 ;
     RECT  99.144 102.263 106.938 103.081 ;
     RECT  2.412 103.081 106.938 103.085 ;
     RECT  2.415 103.085 106.938 103.469 ;
     RECT  4.608 103.469 106.938 103.621 ;
     RECT  2.415 103.469 3.546 103.739 ;
     RECT  4.608 103.621 107.154 103.775 ;
     RECT  4.68 103.775 107.154 104.009 ;
     RECT  3.528 103.739 3.546 104.251 ;
     RECT  4.68 104.009 106.722 104.791 ;
     RECT  3.528 104.251 3.834 104.863 ;
     RECT  4.572 104.791 106.722 104.863 ;
     RECT  3.528 104.863 106.722 105.197 ;
     RECT  47.268 105.197 106.722 105.245 ;
     RECT  47.304 105.245 106.722 105.437 ;
     RECT  3.528 105.197 5.742 105.511 ;
     RECT  3.456 105.511 5.742 105.539 ;
     RECT  6.48 105.197 46.53 105.773 ;
     RECT  3.456 105.539 3.618 105.899 ;
     RECT  54.288 105.437 106.722 105.935 ;
     RECT  4.356 105.539 5.742 106.015 ;
     RECT  6.48 105.773 35.154 106.015 ;
     RECT  36 105.773 46.53 106.015 ;
     RECT  47.304 105.437 53.55 106.015 ;
     RECT  3.528 105.899 3.618 106.169 ;
     RECT  54.288 105.935 106.398 106.169 ;
     RECT  4.356 106.015 35.154 106.205 ;
     RECT  4.428 106.205 35.154 106.313 ;
     RECT  5.256 106.313 35.154 106.349 ;
     RECT  4.428 106.313 4.446 106.475 ;
     RECT  54.288 106.169 106.074 106.511 ;
     RECT  36 106.015 53.55 106.555 ;
     RECT  54.288 106.511 105.462 106.555 ;
     RECT  3.528 106.169 3.546 106.583 ;
     RECT  35.928 106.555 105.462 106.733 ;
     RECT  35.928 106.733 105.297 106.781 ;
     RECT  35.964 106.781 105.297 106.889 ;
     RECT  5.256 106.349 35.097 107.015 ;
     RECT  35.964 106.889 42.786 107.087 ;
     RECT  43.74 106.889 103.914 107.123 ;
     RECT  5.256 107.015 20.286 107.131 ;
     RECT  28.944 107.015 35.097 107.159 ;
     RECT  5.148 107.131 20.286 107.249 ;
     RECT  21.06 107.015 27.99 107.249 ;
     RECT  43.74 107.123 53.334 107.249 ;
     RECT  54.108 107.123 62.91 107.249 ;
     RECT  63.792 107.123 100.242 107.249 ;
     RECT  100.98 107.123 103.914 107.249 ;
     RECT  6.876 107.249 11.862 107.285 ;
     RECT  13.104 107.249 20.142 107.285 ;
     RECT  21.132 107.249 27.846 107.285 ;
     RECT  69.084 107.249 76.41 107.285 ;
     RECT  92.988 107.249 100.242 107.285 ;
     RECT  100.98 107.249 101.97 107.285 ;
     RECT  63.792 107.249 68.346 107.321 ;
     RECT  28.944 107.159 31.194 107.33 ;
     RECT  5.148 107.249 5.778 107.357 ;
     RECT  35.964 107.087 42.75 107.357 ;
     RECT  79.812 107.249 92.25 107.357 ;
     RECT  92.988 107.285 98.478 107.357 ;
     RECT  6.876 107.285 10.998 107.393 ;
     RECT  56.232 107.249 56.79 107.393 ;
     RECT  57.564 107.249 62.91 107.393 ;
     RECT  79.812 107.357 92.142 107.393 ;
     RECT  4.68 107.365 4.698 107.405 ;
     RECT  56.232 107.393 56.754 107.405 ;
     RECT  69.084 107.285 69.93 107.429 ;
     RECT  77.22 107.249 78.894 107.429 ;
     RECT  92.988 107.357 97.686 107.429 ;
     RECT  102.744 107.249 103.122 107.429 ;
     RECT  13.14 107.285 20.142 107.501 ;
     RECT  21.168 107.285 27.846 107.501 ;
     RECT  6.948 107.393 10.998 107.519 ;
     RECT  13.14 107.501 19.746 107.519 ;
     RECT  21.168 107.501 27.738 107.519 ;
     RECT  36.072 107.357 42.75 107.519 ;
     RECT  43.74 107.249 49.914 107.519 ;
     RECT  50.652 107.249 53.334 107.519 ;
     RECT  54.108 107.249 55.278 107.519 ;
     RECT  56.232 107.405 56.697 107.519 ;
     RECT  59.328 107.393 62.91 107.519 ;
     RECT  63.792 107.321 67.878 107.519 ;
     RECT  69.084 107.429 69.894 107.519 ;
     RECT  70.668 107.285 76.014 107.519 ;
     RECT  79.884 107.393 84.402 107.519 ;
     RECT  85.176 107.393 92.142 107.519 ;
     RECT  93.024 107.429 94.914 107.519 ;
     RECT  95.688 107.429 97.686 107.519 ;
     RECT  99.288 107.285 100.242 107.519 ;
     RECT  101.016 107.285 101.97 107.519 ;
     RECT  102.96 107.429 103.122 107.519 ;
     RECT  103.896 107.249 103.914 107.519 ;
     RECT  5.76 107.357 5.778 107.549 ;
     RECT  16.488 107.519 17.046 107.549 ;
     RECT  37.368 107.519 38.034 107.549 ;
     RECT  66.708 107.519 67.734 107.549 ;
     RECT  77.472 107.429 78.894 107.549 ;
     RECT  83.16 107.519 84.258 107.549 ;
     RECT  16.488 107.549 16.794 107.555 ;
     RECT  17.964 107.519 19.746 107.555 ;
     RECT  24.015 107.519 24.894 107.555 ;
     RECT  27.54 107.519 27.738 107.555 ;
     RECT  39.06 107.519 41.238 107.555 ;
     RECT  50.652 107.519 51.786 107.555 ;
     RECT  54.216 107.519 55.278 107.555 ;
     RECT  59.328 107.519 59.346 107.555 ;
     RECT  63.792 107.519 64.854 107.555 ;
     RECT  65.916 107.519 65.934 107.555 ;
     RECT  70.668 107.519 70.686 107.555 ;
     RECT  75.204 107.519 76.014 107.555 ;
     RECT  77.472 107.549 78.606 107.555 ;
     RECT  85.356 107.519 85.374 107.555 ;
     RECT  98.46 107.357 98.478 107.555 ;
     RECT  99.288 107.519 100.026 107.555 ;
     RECT  101.016 107.519 101.034 107.555 ;
     RECT  102.96 107.519 102.978 107.555 ;
     RECT  23.112 107.519 23.13 107.591 ;
     RECT  26.136 107.519 26.694 107.591 ;
     RECT  50.652 107.555 51.297 107.591 ;
     RECT  72.072 107.519 74.394 107.591 ;
     RECT  28.944 107.33 31.158 107.597 ;
     RECT  72.504 107.591 74.394 107.597 ;
     RECT  88.164 107.519 90.486 107.597 ;
     RECT  88.236 107.597 90.486 107.6 ;
     RECT  27.684 107.555 27.738 107.627 ;
     RECT  57.564 107.393 58.554 107.627 ;
     RECT  13.14 107.519 13.497 107.645 ;
     RECT  24.015 107.555 24.606 107.663 ;
     RECT  56.304 107.519 56.697 107.663 ;
     RECT  32.112 107.159 35.097 107.693 ;
     RECT  72.615 107.597 74.394 107.693 ;
     RECT  6.948 107.519 8.478 107.699 ;
     RECT  15.228 107.519 15.714 107.699 ;
     RECT  18.18 107.555 19.746 107.699 ;
     RECT  21.168 107.519 22.302 107.699 ;
     RECT  24.015 107.663 24.354 107.699 ;
     RECT  27.684 107.627 27.702 107.699 ;
     RECT  36.072 107.519 36.63 107.699 ;
     RECT  39.24 107.555 41.238 107.699 ;
     RECT  52.668 107.519 53.19 107.699 ;
     RECT  69.264 107.519 69.894 107.699 ;
     RECT  78.012 107.555 78.606 107.699 ;
     RECT  81.432 107.519 81.918 107.699 ;
     RECT  86.652 107.519 87.246 107.699 ;
     RECT  60.084 107.519 62.097 107.741 ;
     RECT  2.415 103.739 2.697 107.747 ;
     RECT  6.948 107.699 8.097 107.747 ;
     RECT  13.215 107.645 13.497 107.747 ;
     RECT  24.015 107.699 24.297 107.747 ;
     RECT  33.948 107.693 35.097 107.747 ;
     RECT  40.215 107.699 41.238 107.747 ;
     RECT  51.015 107.591 51.297 107.747 ;
     RECT  56.415 107.663 56.697 107.747 ;
     RECT  61.815 107.741 62.097 107.747 ;
     RECT  72.615 107.693 73.458 107.747 ;
     RECT  88.236 107.6 89.097 107.747 ;
     RECT  93.564 107.519 94.497 107.747 ;
     RECT  105.015 106.889 105.297 107.747 ;
     RECT  6.948 107.747 7.905 107.789 ;
     RECT  9.72 107.519 10.134 107.789 ;
     RECT  10.98 107.519 10.998 107.789 ;
     RECT  14.472 107.519 14.49 107.789 ;
     RECT  15.516 107.699 15.714 107.789 ;
     RECT  16.488 107.555 16.506 107.789 ;
     RECT  18.615 107.699 19.746 107.789 ;
     RECT  21.168 107.699 22.122 107.789 ;
     RECT  26.136 107.591 26.658 107.789 ;
     RECT  29.415 107.597 31.158 107.789 ;
     RECT  32.112 107.693 32.922 107.789 ;
     RECT  36.072 107.699 36.594 107.789 ;
     RECT  37.368 107.549 37.386 107.789 ;
     RECT  41.076 107.747 41.238 107.789 ;
     RECT  42.012 107.519 42.534 107.789 ;
     RECT  43.74 107.519 47.61 107.789 ;
     RECT  48.852 107.519 49.122 107.789 ;
     RECT  49.896 107.519 49.914 107.789 ;
     RECT  54.216 107.555 55.17 107.789 ;
     RECT  57.6 107.627 58.554 107.789 ;
     RECT  60.084 107.741 60.966 107.789 ;
     RECT  63.792 107.555 64.818 107.789 ;
     RECT  66.78 107.549 67.734 107.789 ;
     RECT  69.264 107.699 69.786 107.789 ;
     RECT  73.44 107.747 73.458 107.789 ;
     RECT  74.232 107.693 74.394 107.789 ;
     RECT  75.312 107.555 76.014 107.789 ;
     RECT  78.012 107.699 78.534 107.789 ;
     RECT  79.884 107.519 80.658 107.789 ;
     RECT  81.432 107.699 81.45 107.789 ;
     RECT  86.652 107.699 87.21 107.789 ;
     RECT  89.82 107.6 90.486 107.789 ;
     RECT  95.688 107.519 96.066 107.789 ;
     RECT  96.84 107.519 97.686 107.789 ;
     RECT  99.504 107.555 100.026 107.789 ;
     RECT  32.292 107.789 32.31 107.795 ;
     RECT  6.948 107.789 6.966 107.825 ;
     RECT  15.516 107.789 15.534 107.825 ;
     RECT  18.615 107.789 19.17 107.825 ;
     RECT  33.948 107.747 34.905 107.825 ;
     RECT  41.076 107.789 41.094 107.825 ;
     RECT  57.6 107.789 57.618 107.825 ;
     RECT  66.78 107.789 67.374 107.825 ;
     RECT  69.264 107.789 69.282 107.825 ;
     RECT  75.312 107.789 75.33 107.825 ;
     RECT  78.012 107.789 78.105 107.825 ;
     RECT  80.496 107.789 80.514 107.825 ;
     RECT  89.82 107.789 89.838 107.825 ;
     RECT  93.564 107.747 94.305 107.825 ;
     RECT  99.504 107.789 99.705 107.825 ;
     RECT  67.215 107.825 67.374 107.897 ;
     RECT  99.576 107.825 99.705 107.897 ;
     RECT  43.74 107.789 44.874 107.899 ;
     RECT  21.168 107.789 21.186 107.933 ;
     RECT  36.072 107.789 36.09 107.933 ;
     RECT  42.156 107.789 42.534 107.933 ;
     RECT  43.56 107.899 44.874 107.933 ;
     RECT  48.852 107.789 48.87 107.933 ;
     RECT  54.972 107.789 54.99 107.933 ;
     RECT  43.56 107.933 43.578 107.939 ;
     RECT  44.856 107.933 44.874 107.939 ;
     RECT  34.092 107.825 34.905 107.969 ;
     RECT  42.516 107.933 42.534 107.969 ;
     RECT  52.668 107.699 52.686 107.969 ;
     RECT  74.232 107.789 74.25 107.969 ;
     RECT  83.415 107.549 84.114 107.969 ;
     RECT  88.236 107.747 88.905 107.969 ;
     RECT  93.888 107.825 94.305 107.969 ;
     RECT  2.415 107.747 2.505 108.017 ;
     RECT  7.815 107.789 7.905 108.017 ;
     RECT  13.215 107.747 13.305 108.017 ;
     RECT  18.615 107.825 18.705 108.017 ;
     RECT  24.015 107.747 24.105 108.017 ;
     RECT  29.415 107.789 29.505 108.017 ;
     RECT  34.815 107.969 34.905 108.017 ;
     RECT  40.215 107.747 40.305 108.017 ;
     RECT  45.615 107.789 45.705 108.017 ;
     RECT  51.015 107.747 51.105 108.017 ;
     RECT  56.415 107.747 56.505 108.017 ;
     RECT  61.815 107.747 61.905 108.017 ;
     RECT  67.215 107.897 67.305 108.017 ;
     RECT  72.615 107.747 72.705 108.017 ;
     RECT  78.015 107.825 78.105 108.017 ;
     RECT  83.415 107.969 83.505 108.017 ;
     RECT  88.815 107.969 88.905 108.017 ;
     RECT  94.215 107.969 94.305 108.017 ;
     RECT  99.615 107.897 99.705 108.017 ;
     RECT  105.015 107.747 105.105 108.017 ;
     RECT  64.296 107.789 64.818 108.317 ;
     RECT  64.44 108.317 64.818 109.517 ;
     RECT  64.44 109.517 64.458 109.565 ;
    LAYER M4 ;
     RECT  0.025 74.832 0.06 74.856 ;
     RECT  0.06 52.656 0.097 55.656 ;
     RECT  0.06 74.832 0.137 77.928 ;
     RECT  0.137 74.928 0.227 77.928 ;
     RECT  0.06 70.128 0.277 71.016 ;
     RECT  0.181 58.656 0.323 58.68 ;
     RECT  0.277 70.032 0.533 71.016 ;
     RECT  2.293 94.032 2.365 94.248 ;
     RECT  2.365 41.904 2.408 41.928 ;
     RECT  2.365 44.976 2.408 45 ;
     RECT  0.097 52.56 2.408 55.656 ;
     RECT  0.533 70.032 2.408 70.92 ;
     RECT  2.365 72.72 2.408 72.744 ;
     RECT  0.227 75.216 2.408 77.928 ;
     RECT  2.365 88.08 2.408 88.104 ;
     RECT  2.285 92.784 2.408 92.808 ;
     RECT  2.365 94.032 2.408 95.784 ;
     RECT  2.365 101.04 2.408 101.064 ;
     RECT  2.401 103.056 2.408 103.08 ;
     RECT  2.408 2.148 2.512 108.012 ;
     RECT  2.512 2.418 2.704 107.742 ;
     RECT  2.704 15.84 2.819 18.408 ;
     RECT  2.704 68.928 2.86 72.744 ;
     RECT  2.819 16.272 2.867 18.408 ;
     RECT  2.704 59.472 2.867 59.736 ;
     RECT  2.704 65.52 2.867 67.848 ;
     RECT  2.704 103.056 2.867 104.28 ;
     RECT  2.704 61.008 2.873 63.096 ;
     RECT  2.704 93.504 2.873 94.056 ;
     RECT  2.867 17.328 2.908 17.64 ;
     RECT  2.704 30.72 2.945 34.2 ;
     RECT  2.704 83.712 2.945 85.128 ;
     RECT  2.704 44.976 2.963 46.632 ;
     RECT  2.945 83.712 2.963 84.024 ;
     RECT  2.704 41.904 2.981 42.744 ;
     RECT  2.704 95.184 2.981 98.136 ;
     RECT  2.704 5.712 3.089 8.568 ;
     RECT  2.704 80.832 3.089 82.68 ;
     RECT  2.704 64.08 3.107 64.104 ;
     RECT  3.089 5.712 3.155 8.52 ;
     RECT  2.963 46.608 3.161 46.632 ;
     RECT  2.86 68.928 3.161 70.824 ;
     RECT  2.704 49.536 3.203 50.232 ;
     RECT  2.981 42.144 3.233 42.744 ;
     RECT  2.945 30.72 3.269 32.376 ;
     RECT  2.704 27.888 3.305 28.68 ;
     RECT  2.867 103.2 3.305 103.224 ;
     RECT  2.704 24.96 3.347 26.76 ;
     RECT  2.945 33.696 3.377 34.2 ;
     RECT  2.981 95.184 3.443 97.56 ;
     RECT  2.963 44.976 3.449 45 ;
     RECT  2.873 61.92 3.629 63.096 ;
     RECT  2.704 99.696 3.635 101.064 ;
     RECT  3.347 25.728 3.697 26.76 ;
     RECT  2.704 19.392 3.701 19.848 ;
     RECT  3.203 49.536 3.737 49.56 ;
     RECT  3.269 32.016 3.773 32.376 ;
     RECT  3.443 96.192 3.773 97.56 ;
     RECT  2.867 59.472 3.841 59.496 ;
     RECT  3.701 19.392 3.845 19.752 ;
     RECT  3.773 32.352 3.845 32.376 ;
     RECT  3.089 80.832 3.845 82.248 ;
     RECT  3.155 7.344 3.881 7.368 ;
     RECT  2.704 48.384 3.913 48.408 ;
     RECT  3.161 69.744 3.925 70.824 ;
     RECT  2.86 71.808 3.925 72.744 ;
     RECT  2.704 89.568 3.925 91.464 ;
     RECT  3.913 19.344 3.949 19.368 ;
     RECT  3.697 24.528 3.949 24.552 ;
     RECT  3.233 42.144 3.949 42.504 ;
     RECT  3.925 89.568 3.971 92.136 ;
     RECT  3.829 94.608 3.971 94.824 ;
     RECT  3.697 14.112 3.985 14.136 ;
     RECT  2.704 36 3.985 36.024 ;
     RECT  3.773 96.72 3.989 97.56 ;
     RECT  2.704 10.128 4.021 10.68 ;
     RECT  2.704 11.952 4.021 12.888 ;
     RECT  3.985 35.472 4.021 36.024 ;
     RECT  3.697 25.728 4.025 26.808 ;
     RECT  3.841 20.928 4.061 20.952 ;
     RECT  3.629 61.92 4.061 62.856 ;
     RECT  3.949 39.84 4.093 39.864 ;
     RECT  2.704 38.688 4.097 38.712 ;
     RECT  2.704 86.448 4.117 88.104 ;
     RECT  3.377 34.128 4.129 34.2 ;
     RECT  4.021 35.376 4.129 36.024 ;
     RECT  4.025 25.776 4.165 26.808 ;
     RECT  2.867 16.272 4.201 16.296 ;
     RECT  2.908 17.328 4.201 17.352 ;
     RECT  2.704 22.752 4.201 22.776 ;
     RECT  3.949 23.808 4.201 24.552 ;
     RECT  3.949 41.616 4.201 42.504 ;
     RECT  4.117 86.16 4.204 88.104 ;
     RECT  3.985 14.112 4.205 14.232 ;
     RECT  4.093 39.744 4.237 39.864 ;
     RECT  3.841 58.704 4.273 59.496 ;
     RECT  2.873 93.504 4.273 93.528 ;
     RECT  3.989 96.72 4.277 97.464 ;
     RECT  3.269 30.72 4.309 30.888 ;
     RECT  4.237 39.744 4.309 39.912 ;
     RECT  2.704 51.648 4.309 55.896 ;
     RECT  4.273 58.656 4.309 59.496 ;
     RECT  2.867 65.52 4.309 67.704 ;
     RECT  4.204 86.496 4.313 88.104 ;
     RECT  4.273 93.408 4.313 93.528 ;
     RECT  3.155 8.496 4.345 8.52 ;
     RECT  4.309 30.624 4.345 30.888 ;
     RECT  3.913 48.384 4.345 48.504 ;
     RECT  4.309 102.96 4.345 102.984 ;
     RECT  4.345 7.392 4.381 8.52 ;
     RECT  4.345 29.808 4.381 30.888 ;
     RECT  4.129 34.128 4.381 36.024 ;
     RECT  3.925 69.744 4.381 72.744 ;
     RECT  2.704 73.824 4.381 79.032 ;
     RECT  3.305 28.128 4.385 28.68 ;
     RECT  2.704 57.6 4.405 57.624 ;
     RECT  4.309 58.656 4.405 60.264 ;
     RECT  4.021 10.128 4.417 12.888 ;
     RECT  4.205 14.112 4.417 14.136 ;
     RECT  4.309 39.216 4.421 39.912 ;
     RECT  4.201 40.992 4.421 42.504 ;
     RECT  4.405 57.6 4.421 60.264 ;
     RECT  2.945 85.104 4.421 85.128 ;
     RECT  4.421 58.128 4.451 60.264 ;
     RECT  4.421 41.232 4.453 42.504 ;
     RECT  3.971 92.112 4.453 92.136 ;
     RECT  4.417 10.128 4.489 14.136 ;
     RECT  4.201 16.272 4.489 17.448 ;
     RECT  3.845 80.832 4.489 81.768 ;
     RECT  4.489 10.08 4.493 14.136 ;
     RECT  3.635 100.512 4.493 101.064 ;
     RECT  4.381 33.792 4.525 36.024 ;
     RECT  4.453 41.232 4.525 42.792 ;
     RECT  2.704 43.872 4.525 43.896 ;
     RECT  4.309 65.136 4.525 67.704 ;
     RECT  3.971 89.568 4.525 91.128 ;
     RECT  4.489 80.256 4.529 81.768 ;
     RECT  4.345 47.664 4.561 48.504 ;
     RECT  4.165 25.776 4.597 27.096 ;
     RECT  4.381 69.744 4.597 72.84 ;
     RECT  4.381 73.824 4.597 79.272 ;
     RECT  4.421 39.744 4.673 39.912 ;
     RECT  4.453 92.112 4.705 92.376 ;
     RECT  4.313 93.408 4.705 93.432 ;
     RECT  4.525 33.792 4.709 36.504 ;
     RECT  4.381 7.392 4.741 9.048 ;
     RECT  4.493 10.08 4.741 11.976 ;
     RECT  2.963 83.712 4.745 83.784 ;
     RECT  4.525 45.264 4.777 45.288 ;
     RECT  4.549 101.28 4.777 101.304 ;
     RECT  4.345 102.384 4.777 102.984 ;
     RECT  4.313 86.496 4.781 87.912 ;
     RECT  4.453 99.168 4.813 99.192 ;
     RECT  4.777 101.28 4.835 102.984 ;
     RECT  4.061 62.448 4.849 62.856 ;
     RECT  4.129 63.84 4.849 63.864 ;
     RECT  4.741 7.392 4.853 11.976 ;
     RECT  4.309 51.12 4.885 55.896 ;
     RECT  4.489 15.936 4.889 17.448 ;
     RECT  4.597 25.776 4.889 27.384 ;
     RECT  4.561 47.664 4.889 49.128 ;
     RECT  4.201 22.752 4.892 24.552 ;
     RECT  4.673 39.84 4.925 39.912 ;
     RECT  4.889 48.48 4.925 49.128 ;
     RECT  4.525 65.136 4.925 68.568 ;
     RECT  4.525 89.424 4.925 91.128 ;
     RECT  4.705 92.112 4.925 93.432 ;
     RECT  4.835 102.624 4.925 102.984 ;
     RECT  4.813 98.592 4.957 99.192 ;
     RECT  4.892 22.128 4.979 24.552 ;
     RECT  2.867 104.256 4.988 104.28 ;
     RECT  3.971 94.656 4.993 94.824 ;
     RECT  4.957 98.496 4.993 99.192 ;
     RECT  4.381 29.808 5.029 31.368 ;
     RECT  4.777 45.264 5.029 46.2 ;
     RECT  4.345 105.984 5.029 106.008 ;
     RECT  4.925 92.112 5.065 93.096 ;
     RECT  4.988 104.112 5.075 104.28 ;
     RECT  3.155 5.712 5.101 6.024 ;
     RECT  3.949 19.248 5.101 19.368 ;
     RECT  4.925 89.424 5.101 90.36 ;
     RECT  4.597 69.744 5.141 79.272 ;
     RECT  5.101 5.712 5.171 6.888 ;
     RECT  4.889 15.936 5.177 16.296 ;
     RECT  4.925 48.48 5.177 48.504 ;
     RECT  5.101 18.72 5.209 19.848 ;
     RECT  4.853 7.92 5.213 11.976 ;
     RECT  5.213 7.92 5.249 11.832 ;
     RECT  4.277 96.72 5.249 97.368 ;
     RECT  4.925 66.624 5.285 68.568 ;
     RECT  4.709 33.792 5.317 36.264 ;
     RECT  4.889 26.736 5.321 27.384 ;
     RECT  4.849 62.448 5.353 63.864 ;
     RECT  5.285 67.248 5.357 68.568 ;
     RECT  5.141 70.032 5.363 71.928 ;
     RECT  5.353 62.448 5.381 64.152 ;
     RECT  4.529 81.744 5.393 81.768 ;
     RECT  4.925 102.96 5.393 102.984 ;
     RECT  4.835 101.28 5.429 101.592 ;
     RECT  5.029 45.264 5.437 46.776 ;
     RECT  4.889 17.424 5.461 17.448 ;
     RECT  4.525 41.232 5.461 43.896 ;
     RECT  5.029 49.728 5.461 49.752 ;
     RECT  4.993 98.496 5.461 100.104 ;
     RECT  5.249 7.92 5.465 10.92 ;
     RECT  5.381 62.16 5.465 64.152 ;
     RECT  4.885 51.12 5.497 55.992 ;
     RECT  5.141 72.912 5.497 79.272 ;
     RECT  4.529 80.256 5.497 80.424 ;
     RECT  5.413 60.864 5.5 60.888 ;
     RECT  5.461 17.424 5.533 17.496 ;
     RECT  4.385 28.656 5.533 28.68 ;
     RECT  5.029 29.808 5.533 32.184 ;
     RECT  5.461 41.232 5.533 44.088 ;
     RECT  5.245 104.64 5.533 104.712 ;
     RECT  5.029 105.984 5.533 106.392 ;
     RECT  5.101 88.944 5.597 90.36 ;
     RECT  4.781 86.496 5.605 87.336 ;
     RECT  5.357 67.248 5.645 67.608 ;
     RECT  4.925 39.888 5.653 39.912 ;
     RECT  5.533 41.04 5.677 44.088 ;
     RECT  5.437 45.264 5.677 46.728 ;
     RECT  5.461 98.352 5.677 100.104 ;
     RECT  5.429 101.28 5.677 101.448 ;
     RECT  5.653 39.888 5.699 40.056 ;
     RECT  5.497 51.12 5.713 56.712 ;
     RECT  5.605 86.064 5.713 87.336 ;
     RECT  5.171 6.576 5.717 6.888 ;
     RECT  5.677 41.04 5.717 46.728 ;
     RECT  4.493 12.96 5.747 14.136 ;
     RECT  4.979 22.752 5.749 24.552 ;
     RECT  5.533 28.656 5.749 32.184 ;
     RECT  5.317 33.744 5.749 36.264 ;
     RECT  4.451 58.128 5.749 59.784 ;
     RECT  5.713 85.728 5.749 87.336 ;
     RECT  4.669 107.376 5.749 107.4 ;
     RECT  5.125 4.56 5.753 4.584 ;
     RECT  5.497 72.912 5.753 80.424 ;
     RECT  4.745 83.76 5.785 83.784 ;
     RECT  5.597 88.896 5.789 90.36 ;
     RECT  4.993 94.656 5.789 95.736 ;
     RECT  5.749 107.376 5.789 107.544 ;
     RECT  5.699 40.032 5.845 40.056 ;
     RECT  5.717 41.04 5.845 42.648 ;
     RECT  5.713 51.12 5.893 56.76 ;
     RECT  5.749 58.128 5.897 60.408 ;
     RECT  5.461 82.224 5.897 82.248 ;
     RECT  5.533 17.424 5.929 17.688 ;
     RECT  5.749 22.752 5.933 25.512 ;
     RECT  5.249 96.72 5.933 97.272 ;
     RECT  5.929 17.04 5.969 17.688 ;
     RECT  5.065 91.344 5.969 93.096 ;
     RECT  5.749 28.656 6.005 36.504 ;
     RECT  5.893 38.976 6.005 39 ;
     RECT  5.677 98.352 6.005 101.448 ;
     RECT  5.461 49.728 6.037 49.848 ;
     RECT  5.893 51.12 6.037 56.952 ;
     RECT  6.005 30.768 6.073 36.504 ;
     RECT  6.005 98.352 6.077 98.376 ;
     RECT  6.037 50.928 6.109 56.952 ;
     RECT  5.897 58.128 6.109 58.152 ;
     RECT  5.785 83.52 6.109 83.784 ;
     RECT  5.209 18.72 6.113 20.04 ;
     RECT  5.321 26.784 6.145 27.384 ;
     RECT  6.005 28.656 6.145 29.592 ;
     RECT  5.789 94.656 6.145 94.968 ;
     RECT  5.717 44.064 6.149 46.728 ;
     RECT  6.109 50.928 6.149 58.152 ;
     RECT  5.749 85.152 6.149 87.864 ;
     RECT  5.969 91.344 6.149 92.904 ;
     RECT  5.929 48.336 6.181 48.36 ;
     RECT  6.037 49.728 6.181 49.896 ;
     RECT  6.149 50.928 6.181 57.864 ;
     RECT  6.149 44.4 6.185 46.728 ;
     RECT  6.149 85.536 6.217 87.864 ;
     RECT  6.181 48.336 6.289 48.504 ;
     RECT  5.753 73.344 6.289 80.424 ;
     RECT  6.113 18.72 6.293 19.944 ;
     RECT  5.933 22.752 6.293 22.776 ;
     RECT  4.925 65.136 6.332 65.16 ;
     RECT  5.465 62.544 6.373 64.152 ;
     RECT  6.332 65.136 6.373 65.928 ;
     RECT  6.373 62.544 6.419 65.928 ;
     RECT  5.929 4.416 6.433 4.44 ;
     RECT  6.073 30.768 6.437 37.08 ;
     RECT  5.789 88.896 6.473 88.968 ;
     RECT  5.897 59.232 6.505 60.408 ;
     RECT  6.419 62.544 6.505 65.16 ;
     RECT  5.177 15.936 6.541 15.96 ;
     RECT  6.437 31.68 6.545 37.08 ;
     RECT  5.465 7.92 6.577 8.232 ;
     RECT  6.289 48.096 6.577 48.504 ;
     RECT  6.181 49.728 6.577 57.864 ;
     RECT  5.747 12.96 6.613 13.704 ;
     RECT  6.541 15.888 6.613 15.96 ;
     RECT  6.505 59.232 6.617 61.32 ;
     RECT  5.465 9.408 6.653 10.632 ;
     RECT  6.185 46.176 6.653 46.728 ;
     RECT  5.533 104.64 6.653 106.392 ;
     RECT  6.433 4.176 6.685 4.44 ;
     RECT  6.613 15.6 6.685 15.96 ;
     RECT  5.645 67.248 6.685 67.464 ;
     RECT  5.717 6.576 6.721 6.6 ;
     RECT  6.577 7.632 6.721 8.232 ;
     RECT  6.653 9.408 6.725 9.624 ;
     RECT  6.505 21.552 6.725 21.576 ;
     RECT  6.613 12.432 6.757 13.704 ;
     RECT  6.685 14.832 6.757 15.96 ;
     RECT  6.149 91.584 6.761 92.904 ;
     RECT  5.845 40.032 6.793 42.648 ;
     RECT  6.685 67.248 6.793 67.8 ;
     RECT  6.653 46.176 6.797 46.632 ;
     RECT  6.109 83.28 6.805 83.784 ;
     RECT  6.793 40.032 6.829 43.32 ;
     RECT  6.005 101.28 6.853 101.448 ;
     RECT  6.577 48.096 6.86 57.864 ;
     RECT  6.545 36.912 6.865 37.08 ;
     RECT  6.853 101.28 6.865 101.88 ;
     RECT  6.757 11.904 6.901 13.704 ;
     RECT  6.757 14.688 6.901 15.96 ;
     RECT  5.933 23.856 6.901 25.512 ;
     RECT  6.86 47.76 7.004 57.864 ;
     RECT  6.685 3.84 7.009 4.44 ;
     RECT  5.363 70.32 7.009 71.928 ;
     RECT  5.969 17.04 7.045 17.448 ;
     RECT  6.293 18.72 7.045 19.656 ;
     RECT  6.617 59.232 7.045 60.408 ;
     RECT  6.865 101.28 7.081 102.744 ;
     RECT  6.901 11.904 7.117 15.96 ;
     RECT  7.009 69.36 7.189 71.928 ;
     RECT  6.289 73.344 7.189 81 ;
     RECT  6.901 23.04 7.225 25.512 ;
     RECT  7.004 47.712 7.225 57.864 ;
     RECT  7.045 58.944 7.225 60.408 ;
     RECT  7.117 11.904 7.237 16.056 ;
     RECT  7.045 17.04 7.237 19.656 ;
     RECT  7.225 23.04 7.333 25.56 ;
     RECT  6.145 26.784 7.333 29.592 ;
     RECT  6.865 36.912 7.333 37.464 ;
     RECT  7.009 3.84 7.369 4.488 ;
     RECT  6.721 6.576 7.369 8.232 ;
     RECT  6.217 85.536 7.369 87.912 ;
     RECT  6.473 88.896 7.369 88.92 ;
     RECT  6.217 98.16 7.369 98.184 ;
     RECT  6.653 106.368 7.369 106.392 ;
     RECT  7.369 3.84 7.429 4.776 ;
     RECT  6.653 10.608 7.441 10.632 ;
     RECT  7.237 11.904 7.441 19.656 ;
     RECT  6.185 44.4 7.441 45.048 ;
     RECT  6.797 46.176 7.441 46.248 ;
     RECT  7.369 106.368 7.441 106.536 ;
     RECT  5.789 107.52 7.441 107.544 ;
     RECT  6.829 39.504 7.513 43.32 ;
     RECT  7.189 69.36 7.513 81 ;
     RECT  6.005 99.792 7.549 100.296 ;
     RECT  7.081 101.28 7.549 103.32 ;
     RECT  7.225 47.712 7.585 60.408 ;
     RECT  7.513 69.36 7.585 81.96 ;
     RECT  6.653 104.64 7.657 104.952 ;
     RECT  7.369 6.144 7.669 8.232 ;
     RECT  7.333 23.04 7.669 29.592 ;
     RECT  7.669 23.04 7.729 29.784 ;
     RECT  7.657 104.544 7.729 104.952 ;
     RECT  6.505 62.496 7.765 65.16 ;
     RECT  7.369 97.824 7.801 98.184 ;
     RECT  7.549 99.792 7.801 103.32 ;
     RECT  7.045 2.784 7.808 2.808 ;
     RECT  7.429 3.84 7.808 4.872 ;
     RECT  7.669 6.144 7.808 8.424 ;
     RECT  6.725 9.408 7.808 9.576 ;
     RECT  7.441 10.608 7.808 19.656 ;
     RECT  6.829 21.504 7.808 21.528 ;
     RECT  7.729 23.04 7.808 30.696 ;
     RECT  6.545 31.68 7.808 35.736 ;
     RECT  7.333 36.912 7.808 38.184 ;
     RECT  7.513 39.312 7.808 43.32 ;
     RECT  7.441 44.4 7.808 46.248 ;
     RECT  7.585 47.712 7.808 60.648 ;
     RECT  7.765 61.92 7.808 65.16 ;
     RECT  6.793 66.336 7.808 67.8 ;
     RECT  7.585 69.36 7.808 82.2 ;
     RECT  6.805 83.28 7.808 84.264 ;
     RECT  7.369 85.536 7.808 88.92 ;
     RECT  5.789 90.048 7.808 90.36 ;
     RECT  6.761 91.584 7.808 92.232 ;
     RECT  6.145 94.032 7.808 94.968 ;
     RECT  5.933 96.72 7.808 96.84 ;
     RECT  7.801 97.824 7.808 103.32 ;
     RECT  7.729 104.544 7.808 105.24 ;
     RECT  7.441 106.368 7.808 107.544 ;
     RECT  7.808 2.148 7.912 108.012 ;
     RECT  7.912 2.418 8.104 107.742 ;
     RECT  8.104 80.256 8.165 80.28 ;
     RECT  8.104 97.824 8.165 100.296 ;
     RECT  8.104 30.672 8.201 47.064 ;
     RECT  8.104 81.936 8.237 87.336 ;
     RECT  8.104 67.536 8.243 67.56 ;
     RECT  8.104 2.784 8.273 4.488 ;
     RECT  8.104 16.032 8.273 19.992 ;
     RECT  8.104 101.424 8.273 107.544 ;
     RECT  8.201 36.384 8.291 47.064 ;
     RECT  8.104 88.752 8.309 88.92 ;
     RECT  8.104 48.096 8.345 56.856 ;
     RECT  8.273 101.424 8.38 107.016 ;
     RECT  8.104 6.336 8.381 7.752 ;
     RECT  8.345 49.392 8.381 56.856 ;
     RECT  8.104 65.136 8.417 66.36 ;
     RECT  8.104 57.84 8.453 59.112 ;
     RECT  8.273 2.784 8.489 4.2 ;
     RECT  8.273 16.656 8.489 19.992 ;
     RECT  8.104 61.92 8.525 63.096 ;
     RECT  8.453 58.512 8.531 59.112 ;
     RECT  8.104 22.752 8.561 26.04 ;
     RECT  8.525 61.92 8.561 62.28 ;
     RECT  8.531 59.088 8.572 59.112 ;
     RECT  8.309 88.896 8.597 88.92 ;
     RECT  8.38 103.2 8.597 107.016 ;
     RECT  8.561 22.752 8.669 23.304 ;
     RECT  8.104 60.144 8.705 60.936 ;
     RECT  8.561 24.336 8.741 26.04 ;
     RECT  8.104 28.8 8.741 28.824 ;
     RECT  8.237 81.936 8.813 86.76 ;
     RECT  8.104 94.032 8.813 94.968 ;
     RECT  8.597 103.2 8.813 104.28 ;
     RECT  8.104 9.504 8.849 14.712 ;
     RECT  8.38 101.424 8.849 101.976 ;
     RECT  8.104 27.168 8.921 27.192 ;
     RECT  8.489 4.176 8.957 4.2 ;
     RECT  8.381 6.336 8.957 7.704 ;
     RECT  8.201 30.672 8.957 34.92 ;
     RECT  8.597 105.36 8.957 107.016 ;
     RECT  8.104 90.336 9.097 93 ;
     RECT  8.705 60.144 9.131 60.552 ;
     RECT  8.849 14.688 9.133 14.712 ;
     RECT  8.291 45.264 9.133 47.064 ;
     RECT  8.345 48.096 9.133 48.216 ;
     RECT  9.097 81.072 9.133 81.096 ;
     RECT  8.957 30.672 9.137 31.944 ;
     RECT  8.957 105.36 9.137 106.536 ;
     RECT  9.133 45.264 9.155 48.216 ;
     RECT  8.957 32.928 9.169 34.92 ;
     RECT  8.291 36.384 9.169 44.088 ;
     RECT  9.131 60.096 9.205 60.552 ;
     RECT  9.205 5.184 9.241 5.208 ;
     RECT  9.133 80.976 9.241 81.096 ;
     RECT  8.849 101.424 9.245 101.928 ;
     RECT  8.104 68.928 9.269 78.984 ;
     RECT  8.417 65.136 9.313 65.16 ;
     RECT  9.133 14.688 9.317 15.336 ;
     RECT  8.813 83.232 9.317 85.512 ;
     RECT  9.097 89.808 9.349 93 ;
     RECT  8.741 24.336 9.353 25.176 ;
     RECT  9.269 68.928 9.353 79.08 ;
     RECT  9.241 80.304 9.353 81.096 ;
     RECT  8.849 9.504 9.385 13.656 ;
     RECT  9.313 64.272 9.385 65.16 ;
     RECT  8.104 96.144 9.385 96.84 ;
     RECT  8.165 98.16 9.385 100.296 ;
     RECT  9.317 83.28 9.425 85.512 ;
     RECT  9.353 68.928 9.461 78.744 ;
     RECT  8.489 17.424 9.493 19.992 ;
     RECT  9.155 47.376 9.493 48.216 ;
     RECT  8.381 49.392 9.493 55.896 ;
     RECT  9.425 83.328 9.497 85.512 ;
     RECT  9.205 21.648 9.529 21.672 ;
     RECT  8.813 94.704 9.529 94.968 ;
     RECT  9.137 105.36 9.565 106.44 ;
     RECT  8.561 61.92 9.596 62.232 ;
     RECT  9.385 9.168 9.605 13.656 ;
     RECT  9.169 32.928 9.605 44.088 ;
     RECT  9.241 5.088 9.637 5.208 ;
     RECT  8.957 6.336 9.637 7.608 ;
     RECT  9.493 17.424 9.637 20.328 ;
     RECT  9.385 96.144 9.637 100.296 ;
     RECT  9.137 31.104 9.641 31.944 ;
     RECT  9.605 37.344 9.641 44.088 ;
     RECT  9.529 94.704 9.683 95.16 ;
     RECT  8.489 2.784 9.709 3.144 ;
     RECT  9.497 83.904 9.713 85.512 ;
     RECT  9.605 32.928 9.749 35.88 ;
     RECT  9.349 89.808 9.749 93.096 ;
     RECT  9.565 105.072 9.749 106.44 ;
     RECT  9.493 67.776 9.817 67.8 ;
     RECT  9.637 5.088 9.821 7.608 ;
     RECT  9.641 31.488 9.821 31.944 ;
     RECT  9.749 32.976 9.821 35.88 ;
     RECT  9.637 16.8 9.827 20.328 ;
     RECT  9.641 39.12 9.853 44.088 ;
     RECT  9.155 45.264 9.853 46.248 ;
     RECT  9.601 58.56 9.884 58.584 ;
     RECT  9.205 59.808 9.884 60.552 ;
     RECT  9.817 66.864 9.889 67.8 ;
     RECT  8.813 86.496 9.889 86.76 ;
     RECT  9.605 10.32 9.893 13.656 ;
     RECT  9.884 58.56 9.925 60.552 ;
     RECT  9.713 84.048 9.925 85.512 ;
     RECT  9.889 86.496 9.925 87.288 ;
     RECT  8.813 103.2 9.925 103.56 ;
     RECT  9.461 68.928 9.929 78.648 ;
     RECT  9.925 58.128 9.971 60.552 ;
     RECT  9.827 17.424 10.033 20.328 ;
     RECT  9.529 21.504 10.033 21.672 ;
     RECT  9.971 59.808 10.033 60.552 ;
     RECT  9.749 105.072 10.037 105.096 ;
     RECT  9.709 2.784 10.073 3.912 ;
     RECT  9.929 69.312 10.073 78.648 ;
     RECT  9.493 47.376 10.109 55.896 ;
     RECT  9.317 14.688 10.141 14.712 ;
     RECT  9.683 94.704 10.145 94.968 ;
     RECT  10.109 47.376 10.153 49.032 ;
     RECT  9.853 39.12 10.177 46.248 ;
     RECT  10.153 47.376 10.177 48.456 ;
     RECT  10.033 59.808 10.177 60.648 ;
     RECT  9.637 96.144 10.177 101.256 ;
     RECT  10.177 39.12 10.217 48.456 ;
     RECT  9.637 56.88 10.217 56.904 ;
     RECT  9.889 66.672 10.253 67.8 ;
     RECT  9.893 11.088 10.285 13.656 ;
     RECT  10.141 14.64 10.285 14.712 ;
     RECT  10.073 2.784 10.289 3.336 ;
     RECT  10.073 73.152 10.289 78.648 ;
     RECT  10.177 95.952 10.289 101.256 ;
     RECT  10.177 59.808 10.321 60.936 ;
     RECT  9.596 61.92 10.321 62.28 ;
     RECT  10.217 39.312 10.325 48.456 ;
     RECT  10.109 50.016 10.325 55.896 ;
     RECT  10.285 26.352 10.357 26.376 ;
     RECT  9.205 27.84 10.357 27.864 ;
     RECT  9.753 15.696 10.393 15.72 ;
     RECT  9.353 24.336 10.393 24.936 ;
     RECT  9.385 63.792 10.393 65.16 ;
     RECT  10.321 59.808 10.397 62.568 ;
     RECT  10.357 27.84 10.465 28.728 ;
     RECT  9.749 90.336 10.465 93.096 ;
     RECT  10.033 17.424 10.469 21.672 ;
     RECT  9.821 6.336 10.501 7.608 ;
     RECT  9.605 9.168 10.501 9.192 ;
     RECT  8.669 22.752 10.505 22.776 ;
     RECT  9.353 81.072 10.537 81.096 ;
     RECT  10.501 6.336 10.541 9.192 ;
     RECT  10.325 39.312 10.541 47.4 ;
     RECT  9.925 84.048 10.541 87.288 ;
     RECT  10.537 81.072 10.609 81.96 ;
     RECT  10.465 27.408 10.645 28.728 ;
     RECT  10.289 73.344 10.681 78.648 ;
     RECT  10.681 73.344 10.717 78.984 ;
     RECT  10.541 39.312 10.721 43.608 ;
     RECT  10.469 19.776 10.753 21.672 ;
     RECT  10.393 24.336 10.753 25.128 ;
     RECT  9.749 106.416 10.753 106.44 ;
     RECT  10.253 67.68 10.757 67.8 ;
     RECT  10.753 24.192 10.789 25.128 ;
     RECT  9.821 31.488 10.789 31.848 ;
     RECT  10.469 17.424 10.793 18.792 ;
     RECT  10.465 90.336 10.825 93.48 ;
     RECT  10.753 106.416 10.825 106.584 ;
     RECT  9.821 32.976 10.829 35.544 ;
     RECT  10.541 8.208 10.837 9.192 ;
     RECT  10.753 19.776 10.865 21.768 ;
     RECT  10.541 44.688 10.865 47.4 ;
     RECT  10.541 84.288 10.865 87.288 ;
     RECT  10.825 90.24 10.865 93.48 ;
     RECT  10.325 51.648 10.885 55.896 ;
     RECT  10.717 73.344 10.937 79.848 ;
     RECT  10.789 24.192 10.969 25.176 ;
     RECT  10.357 26.352 10.969 26.424 ;
     RECT  10.397 59.808 11.005 61.176 ;
     RECT  10.757 67.776 11.005 67.8 ;
     RECT  10.073 69.312 11.005 71.928 ;
     RECT  10.145 94.704 11.005 94.728 ;
     RECT  10.541 6.336 11.009 7.032 ;
     RECT  10.393 63.792 11.009 66.216 ;
     RECT  10.865 92.688 11.009 93.48 ;
     RECT  10.937 73.344 11.045 78.984 ;
     RECT  10.289 2.88 11.081 3.336 ;
     RECT  10.609 81.072 11.113 82.008 ;
     RECT  11.005 94.464 11.113 94.728 ;
     RECT  10.289 95.952 11.113 99.144 ;
     RECT  10.793 17.424 11.117 18.696 ;
     RECT  11.005 67.776 11.117 71.928 ;
     RECT  10.829 33.072 11.125 35.544 ;
     RECT  9.641 37.344 11.125 37.944 ;
     RECT  10.969 24.192 11.149 26.424 ;
     RECT  10.645 27.408 11.149 29.064 ;
     RECT  10.285 11.088 11.185 14.712 ;
     RECT  10.393 15.696 11.185 16.392 ;
     RECT  10.837 8.208 11.189 10.056 ;
     RECT  11.125 33.072 11.189 37.944 ;
     RECT  10.325 48.432 11.189 48.456 ;
     RECT  10.865 84.576 11.219 87.288 ;
     RECT  9.821 5.088 11.221 5.208 ;
     RECT  11.113 80.976 11.221 82.008 ;
     RECT  10.289 100.272 11.221 101.256 ;
     RECT  9.925 102.48 11.221 103.56 ;
     RECT  11.149 24.192 11.225 29.064 ;
     RECT  11.221 100.272 11.261 103.56 ;
     RECT  11.221 80.352 11.293 82.008 ;
     RECT  11.185 11.088 11.297 16.392 ;
     RECT  10.865 21.504 11.297 21.768 ;
     RECT  11.189 33.072 11.297 37.704 ;
     RECT  11.009 92.688 11.297 93.384 ;
     RECT  11.261 100.272 11.308 102.648 ;
     RECT  11.113 94.464 11.327 99.144 ;
     RECT  11.081 2.88 11.329 3.144 ;
     RECT  11.221 4.464 11.329 5.208 ;
     RECT  11.297 37.344 11.333 37.704 ;
     RECT  9.971 58.128 11.333 58.152 ;
     RECT  11.009 6.336 11.365 6.888 ;
     RECT  10.865 46.224 11.365 47.4 ;
     RECT  11.045 73.344 11.365 78.792 ;
     RECT  11.293 80.352 11.369 82.584 ;
     RECT  11.308 102.288 11.369 102.648 ;
     RECT  10.753 104.832 11.369 104.856 ;
     RECT  11.189 9.744 11.401 10.056 ;
     RECT  11.297 11.088 11.401 14.856 ;
     RECT  10.825 106.416 11.401 106.776 ;
     RECT  11.365 72.96 11.405 78.792 ;
     RECT  11.401 9.744 11.411 14.856 ;
     RECT  10.789 31.44 11.413 31.848 ;
     RECT  11.225 27.84 11.441 29.064 ;
     RECT  11.297 33.072 11.441 35.544 ;
     RECT  11.413 31.44 11.513 31.944 ;
     RECT  11.401 105.6 11.549 106.776 ;
     RECT  10.865 44.688 11.581 45.192 ;
     RECT  11.327 94.464 11.621 99.192 ;
     RECT  10.397 62.208 11.653 62.568 ;
     RECT  11.219 84.576 11.657 87.144 ;
     RECT  11.411 9.744 11.729 14.712 ;
     RECT  10.721 39.312 11.729 43.176 ;
     RECT  11.117 68.208 11.729 71.928 ;
     RECT  11.369 80.976 11.729 82.584 ;
     RECT  11.225 24.192 11.761 26.808 ;
     RECT  11.009 64.08 11.761 66.216 ;
     RECT  11.761 24.096 11.797 26.808 ;
     RECT  11.005 59.472 11.797 61.176 ;
     RECT  11.549 106.032 11.797 106.776 ;
     RECT  11.117 18.624 11.833 18.696 ;
     RECT  10.865 19.776 11.833 20.52 ;
     RECT  11.513 31.44 11.873 31.848 ;
     RECT  11.797 106.032 11.884 107.256 ;
     RECT  11.729 80.976 11.909 82.008 ;
     RECT  11.329 2.832 11.941 3.144 ;
     RECT  11.189 8.208 11.941 8.472 ;
     RECT  11.761 64.08 11.969 66.696 ;
     RECT  10.325 50.016 11.977 50.616 ;
     RECT  10.885 51.648 11.977 56.856 ;
     RECT  11.761 83.136 11.989 83.208 ;
     RECT  11.657 84.576 11.989 86.568 ;
     RECT  11.729 69.504 12.013 71.928 ;
     RECT  11.405 72.96 12.013 78.648 ;
     RECT  11.941 2.784 12.017 3.144 ;
     RECT  11.833 18.624 12.017 20.52 ;
     RECT  11.653 62.16 12.017 62.568 ;
     RECT  11.621 94.464 12.017 94.728 ;
     RECT  11.621 95.712 12.017 99.192 ;
     RECT  11.797 23.184 12.028 26.808 ;
     RECT  11.729 39.6 12.037 43.176 ;
     RECT  11.581 44.304 12.037 45.192 ;
     RECT  11.969 64.08 12.053 66.744 ;
     RECT  12.037 39.6 12.083 45.192 ;
     RECT  11.884 106.032 12.089 106.584 ;
     RECT  12.053 64.896 12.125 66.552 ;
     RECT  11.297 16.032 12.157 16.392 ;
     RECT  11.117 17.424 12.157 17.64 ;
     RECT  12.017 62.496 12.193 62.568 ;
     RECT  12.125 64.896 12.197 66.216 ;
     RECT  12.028 23.616 12.229 26.808 ;
     RECT  11.297 21.744 12.233 21.768 ;
     RECT  11.909 80.976 12.233 81 ;
     RECT  11.441 28.512 12.301 29.064 ;
     RECT  11.333 37.344 12.337 37.656 ;
     RECT  12.017 99.168 12.373 99.192 ;
     RECT  11.308 100.272 12.373 101.256 ;
     RECT  12.157 16.032 12.401 17.64 ;
     RECT  12.401 15.984 12.409 17.64 ;
     RECT  12.017 18.624 12.409 18.744 ;
     RECT  11.729 12.48 12.445 14.712 ;
     RECT  11.873 31.824 12.481 31.848 ;
     RECT  11.441 33.456 12.481 35.544 ;
     RECT  11.977 50.016 12.481 56.856 ;
     RECT  12.013 69.504 12.481 78.648 ;
     RECT  12.481 33.12 12.517 35.832 ;
     RECT  10.865 90.24 12.553 91.608 ;
     RECT  11.297 92.688 12.553 93.288 ;
     RECT  12.373 99.168 12.553 101.256 ;
     RECT  11.369 102.288 12.553 102.6 ;
     RECT  11.941 8.016 12.625 8.472 ;
     RECT  11.729 9.744 12.625 11.4 ;
     RECT  12.017 94.656 12.661 94.728 ;
     RECT  12.017 95.712 12.661 97.8 ;
     RECT  12.481 69.504 12.697 78.696 ;
     RECT  12.049 79.824 12.697 79.848 ;
     RECT  11.909 81.984 12.697 82.008 ;
     RECT  11.989 83.136 12.697 86.568 ;
     RECT  12.697 69.504 12.733 79.848 ;
     RECT  11.365 6.24 12.769 6.888 ;
     RECT  12.089 106.032 12.769 106.296 ;
     RECT  10.645 88.896 12.805 88.92 ;
     RECT  12.553 90.24 12.805 93.288 ;
     RECT  12.083 44.928 12.841 45.192 ;
     RECT  11.365 46.224 12.841 47.976 ;
     RECT  12.805 88.896 12.841 93.288 ;
     RECT  12.017 19.776 12.877 20.52 ;
     RECT  12.625 8.016 12.913 11.4 ;
     RECT  12.445 12.48 12.913 14.856 ;
     RECT  12.301 28.512 12.913 29.448 ;
     RECT  12.769 105.168 12.913 106.296 ;
     RECT  12.697 81.984 12.949 86.568 ;
     RECT  12.481 50.016 12.985 57.432 ;
     RECT  11.797 58.656 12.985 61.176 ;
     RECT  12.409 15.984 13.045 18.744 ;
     RECT  12.877 19.776 13.045 20.664 ;
     RECT  11.329 4.128 13.057 5.208 ;
     RECT  12.769 6.24 13.057 6.936 ;
     RECT  12.841 88.656 13.057 93.288 ;
     RECT  12.661 94.656 13.057 97.8 ;
     RECT  12.083 39.6 13.093 43.896 ;
     RECT  12.841 44.928 13.093 47.976 ;
     RECT  13.057 94.656 13.093 97.944 ;
     RECT  12.949 81.984 13.129 86.616 ;
     RECT  13.057 87.696 13.129 93.288 ;
     RECT  12.017 2.784 13.165 2.904 ;
     RECT  12.517 33.12 13.165 35.928 ;
     RECT  13.165 2.784 13.208 3.048 ;
     RECT  13.057 4.128 13.208 6.936 ;
     RECT  12.913 8.016 13.208 14.856 ;
     RECT  13.045 15.984 13.208 20.664 ;
     RECT  12.517 21.792 13.208 21.816 ;
     RECT  12.229 23.616 13.208 27.384 ;
     RECT  12.913 28.512 13.208 29.64 ;
     RECT  12.481 31.824 13.208 31.944 ;
     RECT  13.165 33.024 13.208 35.928 ;
     RECT  12.337 37.344 13.208 38.184 ;
     RECT  13.093 39.6 13.208 47.976 ;
     RECT  12.985 50.016 13.208 61.176 ;
     RECT  12.193 62.496 13.208 63.288 ;
     RECT  12.197 64.896 13.208 65.688 ;
     RECT  11.729 68.208 13.208 68.52 ;
     RECT  12.733 69.504 13.208 80.28 ;
     RECT  13.129 81.984 13.208 93.288 ;
     RECT  13.093 94.416 13.208 97.944 ;
     RECT  12.553 99.168 13.208 102.6 ;
     RECT  12.733 103.584 13.208 103.608 ;
     RECT  12.913 104.64 13.208 106.296 ;
     RECT  13.129 107.616 13.208 107.64 ;
     RECT  13.208 2.148 13.312 108.012 ;
     RECT  13.312 2.418 13.504 107.742 ;
     RECT  13.504 62.256 13.565 63.288 ;
     RECT  13.504 73.776 13.619 82.488 ;
     RECT  13.504 33.024 13.637 37.368 ;
     RECT  13.504 97.92 13.637 102.552 ;
     RECT  13.504 48.96 13.673 58.68 ;
     RECT  13.619 73.776 13.673 82.44 ;
     RECT  13.504 2.784 13.709 6.936 ;
     RECT  13.504 8.976 13.709 9.096 ;
     RECT  13.504 17.424 13.709 21.768 ;
     RECT  13.709 19.776 13.745 21.768 ;
     RECT  13.504 23.616 13.745 29.016 ;
     RECT  13.673 81.168 13.781 82.44 ;
     RECT  13.504 83.616 13.781 92.472 ;
     RECT  13.781 81.168 13.817 81.192 ;
     RECT  13.745 25.104 13.889 29.016 ;
     RECT  13.504 10.896 13.997 16.296 ;
     RECT  13.637 33.072 13.997 37.368 ;
     RECT  13.709 17.424 14.033 18.696 ;
     RECT  13.781 83.664 14.105 92.472 ;
     RECT  13.673 48.96 14.177 58.488 ;
     RECT  13.504 64.32 14.213 66.264 ;
     RECT  13.504 103.584 14.213 106.296 ;
     RECT  13.997 10.896 14.249 10.92 ;
     RECT  13.997 12.432 14.285 16.296 ;
     RECT  14.105 83.664 14.285 87.864 ;
     RECT  14.105 89.472 14.285 92.472 ;
     RECT  13.504 93.936 14.285 96.936 ;
     RECT  13.637 98.016 14.291 102.552 ;
     RECT  13.709 2.832 14.357 6.936 ;
     RECT  14.177 48.96 14.357 58.2 ;
     RECT  14.357 56.592 14.393 58.2 ;
     RECT  14.357 4.128 14.429 6.936 ;
     RECT  13.745 19.776 14.429 21.72 ;
     RECT  13.504 107.28 14.461 107.742 ;
     RECT  14.285 93.936 14.465 96.744 ;
     RECT  14.285 12.768 14.485 16.296 ;
     RECT  14.033 17.424 14.485 17.688 ;
     RECT  13.997 36.768 14.501 37.368 ;
     RECT  14.213 103.584 14.501 103.656 ;
     RECT  13.504 60.048 14.533 61.272 ;
     RECT  13.504 67.968 14.537 68.52 ;
     RECT  14.213 104.88 14.537 106.296 ;
     RECT  13.504 30.288 14.569 30.888 ;
     RECT  13.504 31.872 14.569 31.896 ;
     RECT  14.291 98.016 14.573 99.96 ;
     RECT  14.291 101.328 14.641 102.552 ;
     RECT  14.501 103.584 14.641 103.608 ;
     RECT  14.465 94.608 14.645 96.744 ;
     RECT  14.429 19.776 14.681 21.336 ;
     RECT  13.504 45.36 14.681 47.928 ;
     RECT  14.501 37.104 14.713 37.368 ;
     RECT  13.504 38.496 14.713 42.552 ;
     RECT  13.504 43.872 14.713 44.232 ;
     RECT  13.889 27.648 14.717 29.016 ;
     RECT  14.713 38.496 14.717 44.232 ;
     RECT  14.429 4.128 14.753 6.84 ;
     RECT  13.709 8.976 14.753 9 ;
     RECT  14.713 37.104 14.753 37.464 ;
     RECT  13.745 23.616 14.821 24.12 ;
     RECT  13.889 25.104 14.821 26.616 ;
     RECT  13.565 62.256 14.821 63.192 ;
     RECT  13.504 69.504 14.821 72.792 ;
     RECT  14.681 20.88 14.825 21.336 ;
     RECT  14.569 30.288 14.861 31.896 ;
     RECT  14.285 83.664 14.897 87.576 ;
     RECT  14.537 106.272 14.897 106.296 ;
     RECT  14.461 107.28 14.933 107.784 ;
     RECT  13.781 82.416 14.965 82.44 ;
     RECT  14.573 98.016 15.041 98.616 ;
     RECT  14.821 68.928 15.073 72.792 ;
     RECT  13.673 73.776 15.073 79.848 ;
     RECT  14.965 82.416 15.073 82.68 ;
     RECT  14.357 2.832 15.109 3.096 ;
     RECT  14.825 21.312 15.113 21.336 ;
     RECT  14.213 64.704 15.113 66.264 ;
     RECT  14.357 48.96 15.145 55.512 ;
     RECT  14.717 38.592 15.157 44.232 ;
     RECT  14.681 45.36 15.157 47.448 ;
     RECT  15.073 68.928 15.164 79.848 ;
     RECT  14.485 12.768 15.217 17.688 ;
     RECT  14.033 18.672 15.217 18.696 ;
     RECT  15.113 64.704 15.221 65.976 ;
     RECT  14.641 101.328 15.221 103.608 ;
     RECT  15.157 38.592 15.244 47.448 ;
     RECT  14.533 59.904 15.253 61.272 ;
     RECT  14.821 62.256 15.253 63.624 ;
     RECT  14.285 89.472 15.26 91.416 ;
     RECT  15.145 48.912 15.349 55.512 ;
     RECT  14.393 56.592 15.349 58.152 ;
     RECT  15.109 2.784 15.361 3.096 ;
     RECT  14.861 30.288 15.433 30.696 ;
     RECT  15.073 82.32 15.433 82.68 ;
     RECT  14.897 83.664 15.433 84.6 ;
     RECT  15.164 68.928 15.437 80.232 ;
     RECT  15.349 48.912 15.473 58.152 ;
     RECT  14.749 67.296 15.473 67.32 ;
     RECT  15.253 59.904 15.509 63.624 ;
     RECT  14.861 31.872 15.541 31.896 ;
     RECT  13.997 33.072 15.541 35.592 ;
     RECT  14.933 107.52 15.545 107.784 ;
     RECT  15.437 80.112 15.577 80.232 ;
     RECT  15.433 82.32 15.577 84.6 ;
     RECT  14.897 86.016 15.577 87.576 ;
     RECT  15.26 88.752 15.577 91.416 ;
     RECT  14.821 23.616 15.581 26.616 ;
     RECT  14.285 92.448 15.589 92.472 ;
     RECT  14.497 93.456 15.589 93.528 ;
     RECT  14.753 4.128 15.613 6.744 ;
     RECT  15.221 103.584 15.617 103.608 ;
     RECT  14.645 94.656 15.637 96.744 ;
     RECT  15.433 30.144 15.649 30.696 ;
     RECT  15.541 31.872 15.685 35.592 ;
     RECT  15.637 94.656 15.685 96.936 ;
     RECT  14.537 104.88 15.685 105.288 ;
     RECT  14.753 37.2 15.721 37.464 ;
     RECT  15.244 38.592 15.721 44.232 ;
     RECT  15.509 59.904 15.721 61.416 ;
     RECT  15.685 94.512 15.725 96.936 ;
     RECT  15.685 31.872 15.757 36.072 ;
     RECT  15.721 37.2 15.757 44.232 ;
     RECT  15.613 67.392 15.757 67.416 ;
     RECT  15.437 68.928 15.757 78.744 ;
     RECT  15.581 23.616 15.761 25.32 ;
     RECT  15.361 2.736 15.793 3.096 ;
     RECT  15.613 4.08 15.793 6.744 ;
     RECT  14.573 99.936 15.829 99.96 ;
     RECT  15.793 2.736 15.833 6.744 ;
     RECT  15.685 10.08 15.865 10.104 ;
     RECT  15.649 29.808 15.865 30.696 ;
     RECT  15.757 31.872 15.865 44.232 ;
     RECT  15.217 12.768 15.869 18.696 ;
     RECT  15.757 67.392 15.875 78.744 ;
     RECT  15.509 62.736 15.901 63.624 ;
     RECT  15.221 64.704 15.901 65.688 ;
     RECT  15.829 99.936 15.913 100.344 ;
     RECT  15.725 94.512 15.923 96.744 ;
     RECT  15.581 26.496 15.937 26.616 ;
     RECT  14.717 27.648 15.937 28.152 ;
     RECT  15.685 104.112 15.973 105.288 ;
     RECT  15.577 86.016 15.977 91.416 ;
     RECT  15.869 12.768 16.009 14.664 ;
     RECT  15.901 62.736 16.013 65.688 ;
     RECT  16.009 12.048 16.019 14.664 ;
     RECT  15.244 45.36 16.045 47.448 ;
     RECT  15.865 29.808 16.049 44.232 ;
     RECT  15.473 49.056 16.049 58.152 ;
     RECT  15.937 26.496 16.067 28.152 ;
     RECT  15.833 3.024 16.153 6.744 ;
     RECT  15.721 59.328 16.189 61.416 ;
     RECT  16.045 45.36 16.265 47.88 ;
     RECT  15.977 87.888 16.316 91.416 ;
     RECT  15.589 92.448 16.316 93.528 ;
     RECT  15.973 104.112 16.337 105.48 ;
     RECT  14.681 19.776 16.369 19.8 ;
     RECT  16.225 20.928 16.369 21.144 ;
     RECT  16.316 87.888 16.403 93.528 ;
     RECT  15.865 10.08 16.405 10.872 ;
     RECT  15.221 102.144 16.405 102.6 ;
     RECT  16.049 49.056 16.441 57.336 ;
     RECT  16.189 58.608 16.445 61.416 ;
     RECT  15.977 86.016 16.445 86.616 ;
     RECT  16.067 26.544 16.477 28.152 ;
     RECT  16.049 29.808 16.477 30.312 ;
     RECT  16.013 62.736 16.477 63.288 ;
     RECT  16.049 31.632 16.517 44.232 ;
     RECT  15.761 23.616 16.549 24.648 ;
     RECT  16.013 64.368 16.549 65.688 ;
     RECT  15.041 98.016 16.585 98.52 ;
     RECT  15.913 99.936 16.585 100.056 ;
     RECT  16.477 26.544 16.589 30.312 ;
     RECT  16.153 3.024 16.621 6.84 ;
     RECT  15.361 106.512 16.625 106.536 ;
     RECT  15.541 8.496 16.645 8.52 ;
     RECT  16.405 9.696 16.657 10.872 ;
     RECT  16.019 12.048 16.657 13.896 ;
     RECT  15.869 15.744 16.661 18.696 ;
     RECT  16.403 87.888 16.697 91.848 ;
     RECT  16.657 11.952 16.729 13.896 ;
     RECT  16.661 15.744 16.733 18.552 ;
     RECT  16.337 104.208 16.733 105.48 ;
     RECT  15.577 80.112 16.765 84.6 ;
     RECT  16.445 86.016 16.765 86.568 ;
     RECT  16.405 101.952 16.765 102.6 ;
     RECT  15.875 67.392 16.769 69.192 ;
     RECT  16.403 93.072 16.801 93.528 ;
     RECT  15.923 94.512 16.801 96.456 ;
     RECT  16.621 3.024 16.837 6.888 ;
     RECT  16.645 7.92 16.837 8.52 ;
     RECT  16.837 3.024 16.873 8.52 ;
     RECT  16.657 9.6 16.873 10.872 ;
     RECT  16.265 45.36 16.873 45.384 ;
     RECT  16.765 80.112 16.873 86.568 ;
     RECT  16.585 98.016 16.873 100.056 ;
     RECT  16.769 67.392 16.877 68.952 ;
     RECT  16.873 3.024 16.913 10.872 ;
     RECT  16.873 97.968 16.945 100.056 ;
     RECT  16.369 19.776 16.981 21.144 ;
     RECT  16.801 93.072 16.981 96.456 ;
     RECT  16.945 97.824 16.981 100.056 ;
     RECT  16.765 101.616 16.981 102.6 ;
     RECT  16.589 28.992 17.017 30.312 ;
     RECT  16.517 31.632 17.017 31.656 ;
     RECT  15.545 107.52 17.017 107.544 ;
     RECT  16.981 19.728 17.029 21.144 ;
     RECT  16.549 22.176 17.029 24.648 ;
     RECT  16.913 4.368 17.053 10.872 ;
     RECT  16.729 11.856 17.053 13.896 ;
     RECT  17.029 19.728 17.068 24.648 ;
     RECT  17.068 19.776 17.075 24.648 ;
     RECT  16.589 26.544 17.089 27.672 ;
     RECT  16.549 64.368 17.125 66.216 ;
     RECT  17.053 4.368 17.129 13.896 ;
     RECT  16.733 104.592 17.129 105.48 ;
     RECT  17.075 22.896 17.161 24.648 ;
     RECT  17.089 25.968 17.161 27.672 ;
     RECT  17.017 106.848 17.164 107.544 ;
     RECT  16.697 87.888 17.171 91.416 ;
     RECT  16.981 93.072 17.219 102.6 ;
     RECT  16.733 15.744 17.237 18.168 ;
     RECT  17.219 93.072 17.237 100.488 ;
     RECT  17.171 87.888 17.269 91.176 ;
     RECT  17.161 22.896 17.345 27.672 ;
     RECT  17.345 25.392 17.453 27.672 ;
     RECT  16.445 59.76 17.485 60.984 ;
     RECT  16.477 61.968 17.485 63.288 ;
     RECT  17.125 64.368 17.485 66.312 ;
     RECT  16.873 45.264 17.521 45.384 ;
     RECT  17.345 22.896 17.525 24.408 ;
     RECT  17.129 4.512 17.561 13.896 ;
     RECT  15.875 70.32 17.593 78.744 ;
     RECT  16.873 80.016 17.601 86.568 ;
     RECT  17.269 87.792 17.601 91.176 ;
     RECT  16.517 32.88 17.629 44.232 ;
     RECT  17.485 59.76 17.629 66.312 ;
     RECT  16.877 67.392 17.629 67.416 ;
     RECT  17.593 70.032 17.701 78.744 ;
     RECT  17.601 80.016 17.701 91.176 ;
     RECT  16.441 48.912 17.737 57.336 ;
     RECT  17.237 16.32 17.773 18.168 ;
     RECT  16.265 46.464 17.809 47.88 ;
     RECT  17.219 101.616 17.809 102.6 ;
     RECT  17.521 45.264 17.845 45.432 ;
     RECT  17.809 46.464 17.845 47.928 ;
     RECT  17.845 45.264 17.881 47.928 ;
     RECT  17.737 48.912 17.881 57.576 ;
     RECT  16.877 68.928 17.953 68.952 ;
     RECT  17.809 101.616 18.061 103.272 ;
     RECT  16.913 3.024 18.133 3.384 ;
     RECT  17.773 16.32 18.133 18.264 ;
     RECT  17.075 19.776 18.133 21.624 ;
     RECT  17.129 104.592 18.133 105.432 ;
     RECT  17.017 28.992 18.181 31.656 ;
     RECT  17.629 32.688 18.181 44.232 ;
     RECT  17.561 9.6 18.197 13.896 ;
     RECT  18.097 14.928 18.197 15.24 ;
     RECT  18.197 9.6 18.205 15.24 ;
     RECT  18.133 16.32 18.205 21.624 ;
     RECT  16.445 58.608 18.205 58.776 ;
     RECT  17.629 59.76 18.205 67.416 ;
     RECT  17.701 70.032 18.205 91.176 ;
     RECT  18.061 101.616 18.205 103.608 ;
     RECT  18.133 104.592 18.205 106.2 ;
     RECT  17.953 68.496 18.313 68.952 ;
     RECT  18.205 58.608 18.349 67.416 ;
     RECT  18.313 68.496 18.349 69 ;
     RECT  17.525 22.992 18.385 24.408 ;
     RECT  17.453 25.392 18.385 25.416 ;
     RECT  17.881 45.264 18.421 57.576 ;
     RECT  18.349 58.608 18.421 69 ;
     RECT  18.205 9.6 18.428 21.624 ;
     RECT  18.133 3.024 18.469 3.432 ;
     RECT  17.561 4.512 18.469 8.52 ;
     RECT  18.428 9.6 18.493 21.72 ;
     RECT  17.237 93.072 18.565 100.056 ;
     RECT  18.469 3.024 18.608 8.52 ;
     RECT  18.493 9.6 18.608 21.816 ;
     RECT  18.385 22.992 18.608 25.416 ;
     RECT  17.453 26.64 18.608 27.672 ;
     RECT  18.181 28.992 18.608 44.232 ;
     RECT  18.421 45.264 18.608 69 ;
     RECT  18.205 70.032 18.608 91.464 ;
     RECT  18.565 93.024 18.608 100.056 ;
     RECT  18.205 101.616 18.608 106.2 ;
     RECT  17.164 107.52 18.608 107.544 ;
     RECT  18.608 2.148 18.712 108.012 ;
     RECT  18.712 2.418 18.904 107.742 ;
     RECT  18.904 3.36 19.001 13.896 ;
     RECT  18.904 104.88 19.001 107.544 ;
     RECT  18.904 47.616 19.037 95.736 ;
     RECT  18.904 97.392 19.043 100.344 ;
     RECT  18.904 101.616 19.043 103.272 ;
     RECT  18.904 29.28 19.073 37.464 ;
     RECT  19.037 47.616 19.073 86.568 ;
     RECT  19.043 101.616 19.073 101.928 ;
     RECT  19.001 3.36 19.109 6.696 ;
     RECT  19.043 100.032 19.109 100.344 ;
     RECT  19.073 29.28 19.181 35.544 ;
     RECT  19.109 100.032 19.181 100.056 ;
     RECT  19.109 3.36 19.253 6.648 ;
     RECT  19.181 29.28 19.253 35.496 ;
     RECT  19.253 29.28 19.289 35.448 ;
     RECT  19.073 59.76 19.289 86.568 ;
     RECT  19.037 87.552 19.325 95.736 ;
     RECT  19.073 101.616 19.325 101.64 ;
     RECT  18.904 23.088 19.397 28.056 ;
     RECT  19.289 32.016 19.433 35.448 ;
     RECT  19.289 59.856 19.469 86.568 ;
     RECT  19.043 103.248 19.469 103.272 ;
     RECT  18.904 15.216 19.613 22.104 ;
     RECT  19.001 7.68 19.649 13.896 ;
     RECT  19.325 87.552 19.685 93.48 ;
     RECT  19.001 104.88 19.793 107.496 ;
     RECT  19.469 80.784 19.829 86.568 ;
     RECT  19.685 87.552 19.829 88.008 ;
     RECT  19.685 88.992 19.865 93.48 ;
     RECT  19.043 97.392 19.897 99.048 ;
     RECT  19.649 7.968 19.901 13.896 ;
     RECT  19.469 59.856 19.901 79.752 ;
     RECT  19.865 89.472 19.901 93.48 ;
     RECT  19.793 105.168 19.901 107.496 ;
     RECT  19.073 36.576 19.933 37.464 ;
     RECT  18.904 38.496 19.933 42.216 ;
     RECT  19.829 87.552 19.973 87.96 ;
     RECT  19.325 94.608 19.973 95.736 ;
     RECT  19.829 82.704 20.041 86.568 ;
     RECT  19.901 7.968 20.045 7.992 ;
     RECT  19.289 29.28 20.045 30.6 ;
     RECT  19.901 106.8 20.045 107.496 ;
     RECT  19.897 96.864 20.081 99.048 ;
     RECT  19.901 9.216 20.113 13.896 ;
     RECT  20.045 29.28 20.113 29.784 ;
     RECT  19.073 47.616 20.117 58.68 ;
     RECT  20.041 82.704 20.153 86.76 ;
     RECT  19.613 15.216 20.189 20.52 ;
     RECT  19.253 3.36 20.197 5.352 ;
     RECT  19.253 6.336 20.221 6.648 ;
     RECT  20.197 2.64 20.284 5.352 ;
     RECT  19.613 21.6 20.333 22.104 ;
     RECT  19.433 32.016 20.369 35.064 ;
     RECT  19.397 26.256 20.401 28.056 ;
     RECT  20.113 29.088 20.401 29.784 ;
     RECT  20.369 32.016 20.401 32.568 ;
     RECT  20.117 50.832 20.401 58.68 ;
     RECT  19.901 59.856 20.401 64.392 ;
     RECT  19.933 36.576 20.437 42.216 ;
     RECT  18.904 43.392 20.437 46.584 ;
     RECT  20.117 47.616 20.437 49.848 ;
     RECT  19.901 89.472 20.441 93.048 ;
     RECT  20.153 83.184 20.483 86.76 ;
     RECT  20.401 26.256 20.531 29.784 ;
     RECT  20.401 31.968 20.54 32.568 ;
     RECT  20.437 36.576 20.549 49.848 ;
     RECT  20.333 21.744 20.581 22.104 ;
     RECT  19.397 23.088 20.581 25.08 ;
     RECT  20.485 30.768 20.581 30.792 ;
     RECT  20.54 31.92 20.581 32.568 ;
     RECT  19.829 80.784 20.585 81.72 ;
     RECT  20.483 86.016 20.585 86.76 ;
     RECT  20.581 30.768 20.627 32.568 ;
     RECT  20.585 81.696 20.657 81.72 ;
     RECT  20.581 21.744 20.693 25.08 ;
     RECT  20.585 86.016 20.729 86.52 ;
     RECT  20.729 86.208 20.801 86.52 ;
     RECT  20.693 23.616 20.833 25.08 ;
     RECT  19.901 65.376 20.837 79.752 ;
     RECT  20.113 9.216 20.869 14.136 ;
     RECT  20.549 36.576 20.869 44.232 ;
     RECT  20.369 33.936 20.941 35.064 ;
     RECT  20.284 3.408 20.977 5.352 ;
     RECT  20.221 6.336 20.977 6.696 ;
     RECT  20.833 23.616 20.977 25.272 ;
     RECT  20.531 26.256 20.977 29.64 ;
     RECT  19.973 87.744 21.02 87.96 ;
     RECT  19.973 94.608 21.048 94.92 ;
     RECT  19.901 105.168 21.049 105.672 ;
     RECT  20.837 68.448 21.085 79.752 ;
     RECT  20.549 45.312 21.107 49.848 ;
     RECT  20.437 96.288 21.109 96.312 ;
     RECT  20.869 8.928 21.121 14.136 ;
     RECT  20.189 15.216 21.121 20.472 ;
     RECT  21.048 94.608 21.121 94.968 ;
     RECT  21.107 45.312 21.125 47.16 ;
     RECT  20.401 50.832 21.125 64.392 ;
     RECT  20.801 86.208 21.125 86.328 ;
     RECT  21.109 96 21.155 96.312 ;
     RECT  21.121 8.928 21.157 20.472 ;
     RECT  20.941 33.936 21.161 35.352 ;
     RECT  20.081 97.44 21.164 99.048 ;
     RECT  21.049 104.88 21.253 105.672 ;
     RECT  21.02 87.744 21.265 88.392 ;
     RECT  20.441 89.472 21.265 92.952 ;
     RECT  21.157 8.448 21.269 20.472 ;
     RECT  21.107 48.336 21.269 49.512 ;
     RECT  20.045 107.472 21.299 107.496 ;
     RECT  21.269 8.448 21.301 10.248 ;
     RECT  20.693 21.744 21.305 22.584 ;
     RECT  21.253 104.88 21.341 106.44 ;
     RECT  21.125 60.288 21.409 64.392 ;
     RECT  20.837 65.376 21.409 67.416 ;
     RECT  21.409 60.288 21.413 67.416 ;
     RECT  21.269 11.376 21.445 20.472 ;
     RECT  20.977 23.616 21.449 29.64 ;
     RECT  21.125 50.832 21.557 59.112 ;
     RECT  20.627 31.344 21.589 32.568 ;
     RECT  21.155 96 21.593 96.024 ;
     RECT  21.341 104.88 21.625 105.768 ;
     RECT  21.445 11.376 21.629 21.048 ;
     RECT  20.869 36.48 21.661 44.232 ;
     RECT  21.125 45.312 21.683 47.064 ;
     RECT  20.483 83.184 21.692 84.84 ;
     RECT  21.125 86.208 21.692 86.28 ;
     RECT  21.164 97.44 21.697 99.192 ;
     RECT  21.205 100.32 21.697 100.344 ;
     RECT  20.977 3.408 21.701 6.696 ;
     RECT  21.085 68.448 21.769 80.088 ;
     RECT  21.305 22.176 21.841 22.584 ;
     RECT  21.449 23.616 21.841 28.056 ;
     RECT  21.049 82.032 21.841 82.056 ;
     RECT  21.589 31.344 21.877 32.952 ;
     RECT  21.161 33.936 21.877 34.392 ;
     RECT  21.629 11.376 21.881 13.704 ;
     RECT  20.509 103.248 21.917 103.272 ;
     RECT  21.841 82.032 21.949 82.152 ;
     RECT  20.689 101.856 21.949 101.88 ;
     RECT  21.121 93.984 22.021 94.968 ;
     RECT  21.877 31.344 22.057 34.392 ;
     RECT  21.265 87.744 22.093 92.952 ;
     RECT  22.021 93.984 22.093 95.688 ;
     RECT  22.057 30.816 22.165 34.392 ;
     RECT  21.661 36.048 22.165 44.232 ;
     RECT  21.683 45.312 22.165 46.92 ;
     RECT  21.697 97.44 22.165 100.344 ;
     RECT  22.165 30.816 22.169 34.488 ;
     RECT  21.269 49.488 22.205 49.512 ;
     RECT  22.093 87.744 22.205 95.688 ;
     RECT  21.557 58.8 22.237 59.112 ;
     RECT  21.769 68.448 22.273 80.664 ;
     RECT  21.949 82.032 22.273 82.2 ;
     RECT  22.169 32.016 22.277 34.488 ;
     RECT  21.413 60.288 22.277 63.768 ;
     RECT  22.169 30.816 22.309 30.984 ;
     RECT  21.269 48.336 22.309 48.36 ;
     RECT  21.301 8.4 22.381 10.248 ;
     RECT  22.309 47.952 22.381 48.36 ;
     RECT  22.381 8.4 22.421 10.872 ;
     RECT  21.413 64.944 22.421 67.416 ;
     RECT  21.449 29.088 22.453 29.64 ;
     RECT  22.309 30.624 22.453 30.984 ;
     RECT  21.692 83.184 22.457 86.28 ;
     RECT  22.277 63.744 22.489 63.768 ;
     RECT  22.277 32.352 22.561 34.488 ;
     RECT  22.165 36.048 22.561 46.92 ;
     RECT  22.205 91.44 22.561 95.688 ;
     RECT  22.165 97.344 22.561 100.344 ;
     RECT  22.205 87.744 22.597 90.36 ;
     RECT  21.557 50.832 22.633 57.72 ;
     RECT  22.237 58.8 22.633 59.208 ;
     RECT  22.421 64.944 22.705 65.208 ;
     RECT  21.625 104.784 22.705 105.768 ;
     RECT  21.701 4.224 22.741 6.696 ;
     RECT  22.381 47.952 22.741 48.456 ;
     RECT  22.633 50.832 22.741 59.208 ;
     RECT  22.277 60.288 22.741 62.712 ;
     RECT  22.453 29.088 22.745 30.984 ;
     RECT  22.273 68.448 22.745 82.2 ;
     RECT  22.705 104.4 22.777 105.768 ;
     RECT  22.561 91.44 22.835 100.44 ;
     RECT  22.457 83.76 22.849 86.28 ;
     RECT  22.597 87.552 22.849 90.36 ;
     RECT  22.129 2.736 22.853 2.76 ;
     RECT  22.741 3.888 22.885 6.696 ;
     RECT  21.841 22.176 22.921 28.056 ;
     RECT  22.849 83.76 22.925 90.36 ;
     RECT  22.489 63.744 22.957 63.816 ;
     RECT  22.705 64.848 22.957 65.208 ;
     RECT  21.629 15.216 22.993 21.048 ;
     RECT  22.921 22.176 22.993 28.152 ;
     RECT  22.993 15.216 22.997 28.152 ;
     RECT  22.741 50.832 23.065 62.712 ;
     RECT  23.065 50.592 23.101 62.712 ;
     RECT  22.421 8.448 23.173 10.872 ;
     RECT  21.881 11.904 23.173 13.704 ;
     RECT  22.957 2.784 23.209 2.808 ;
     RECT  22.885 3.888 23.209 6.888 ;
     RECT  22.561 32.352 23.209 46.92 ;
     RECT  22.741 47.952 23.209 48.696 ;
     RECT  22.997 15.216 23.221 19.128 ;
     RECT  22.745 29.28 23.317 30.984 ;
     RECT  23.209 32.352 23.317 48.696 ;
     RECT  23.101 50.16 23.353 62.712 ;
     RECT  22.957 63.744 23.353 65.208 ;
     RECT  22.777 104.4 23.353 106.728 ;
     RECT  22.925 83.76 23.461 84.6 ;
     RECT  23.173 8.448 23.497 13.704 ;
     RECT  23.317 29.28 23.497 48.696 ;
     RECT  23.461 83.616 23.533 84.6 ;
     RECT  21.949 101.856 23.612 103.08 ;
     RECT  23.497 29.28 23.749 48.888 ;
     RECT  23.353 50.16 23.749 65.208 ;
     RECT  22.997 20.448 23.821 28.152 ;
     RECT  22.835 97.44 23.929 100.44 ;
     RECT  23.821 20.448 23.965 28.2 ;
     RECT  23.749 29.28 23.965 65.208 ;
     RECT  23.533 83.568 23.965 84.6 ;
     RECT  23.612 101.856 23.965 103.128 ;
     RECT  23.353 104.352 23.965 106.728 ;
     RECT  23.209 2.784 24.008 6.888 ;
     RECT  23.497 7.968 24.008 13.704 ;
     RECT  23.221 15.072 24.008 19.128 ;
     RECT  23.965 20.448 24.008 65.208 ;
     RECT  22.421 66.24 24.008 67.416 ;
     RECT  22.745 68.448 24.008 69.624 ;
     RECT  22.745 70.608 24.008 82.2 ;
     RECT  23.965 83.232 24.008 84.6 ;
     RECT  22.925 85.632 24.008 90.36 ;
     RECT  22.835 91.44 24.008 96.12 ;
     RECT  23.929 97.296 24.008 100.44 ;
     RECT  23.965 101.856 24.008 106.728 ;
     RECT  24.008 2.148 24.112 108.012 ;
     RECT  24.112 2.418 24.304 107.742 ;
     RECT  24.304 2.784 24.329 13.944 ;
     RECT  24.329 2.784 24.473 11.496 ;
     RECT  24.304 32.736 24.515 65.448 ;
     RECT  24.473 3.312 24.581 11.496 ;
     RECT  24.515 43.68 24.581 64.056 ;
     RECT  24.304 68.928 24.581 91.464 ;
     RECT  24.581 68.928 24.653 80.904 ;
     RECT  24.304 15.216 24.689 30.984 ;
     RECT  24.581 82.032 24.689 91.464 ;
     RECT  24.581 43.68 24.761 60.936 ;
     RECT  24.581 3.312 24.833 11.4 ;
     RECT  24.653 69.168 24.833 80.904 ;
     RECT  24.689 15.216 24.94 30.936 ;
     RECT  24.94 19.488 25.013 30.936 ;
     RECT  24.833 3.312 25.085 9.24 ;
     RECT  24.329 12.576 25.121 13.944 ;
     RECT  24.761 45.216 25.121 60.936 ;
     RECT  24.689 83.232 25.187 91.464 ;
     RECT  24.304 106.704 25.229 107.16 ;
     RECT  24.515 32.736 25.301 42.456 ;
     RECT  25.187 83.232 25.337 86.568 ;
     RECT  25.229 106.992 25.337 107.16 ;
     RECT  24.304 92.928 25.369 92.952 ;
     RECT  24.304 94.08 25.369 103.512 ;
     RECT  25.301 32.736 25.509 42.264 ;
     RECT  25.509 32.736 25.516 35.496 ;
     RECT  24.833 77.664 25.549 80.904 ;
     RECT  24.689 82.032 25.549 82.248 ;
     RECT  25.013 19.488 25.553 30.408 ;
     RECT  24.833 10.368 25.585 11.4 ;
     RECT  24.94 15.216 25.621 18.312 ;
     RECT  25.121 50.064 25.621 60.936 ;
     RECT  25.369 92.928 25.621 103.512 ;
     RECT  24.304 104.544 25.621 105.48 ;
     RECT  25.509 36.912 25.661 42.264 ;
     RECT  24.515 65.184 25.693 65.448 ;
     RECT  24.304 66.576 25.693 67.416 ;
     RECT  25.585 10.368 25.697 11.64 ;
     RECT  25.621 92.928 25.733 105.48 ;
     RECT  25.121 12.768 25.801 13.944 ;
     RECT  25.621 15.168 25.801 18.312 ;
     RECT  24.761 43.68 25.945 44.232 ;
     RECT  25.121 45.216 25.945 48.984 ;
     RECT  25.733 92.928 25.949 102.168 ;
     RECT  25.661 36.912 25.985 42.216 ;
     RECT  25.549 77.664 26.005 82.248 ;
     RECT  25.337 83.232 26.005 86.472 ;
     RECT  24.581 61.968 26.017 64.056 ;
     RECT  25.085 3.312 26.06 8.088 ;
     RECT  25.985 39.744 26.093 42.216 ;
     RECT  25.553 19.488 26.129 26.664 ;
     RECT  26.06 2.832 26.147 8.088 ;
     RECT  26.005 77.664 26.147 86.472 ;
     RECT  25.949 97.344 26.147 101.928 ;
     RECT  25.733 103.2 26.156 105.48 ;
     RECT  24.833 69.168 26.161 76.584 ;
     RECT  26.147 77.664 26.161 81.672 ;
     RECT  25.516 32.736 26.197 34.344 ;
     RECT  26.017 61.968 26.233 64.152 ;
     RECT  25.693 65.184 26.233 67.416 ;
     RECT  25.801 12.768 26.237 18.312 ;
     RECT  26.156 103.2 26.243 105.816 ;
     RECT  26.161 69.168 26.269 81.672 ;
     RECT  25.697 11.616 26.273 11.64 ;
     RECT  26.237 12.768 26.309 13.752 ;
     RECT  26.269 68.448 26.309 81.672 ;
     RECT  25.187 87.84 26.309 91.464 ;
     RECT  26.237 14.88 26.377 18.312 ;
     RECT  26.129 19.488 26.377 22.632 ;
     RECT  25.945 43.68 26.377 48.984 ;
     RECT  26.093 39.84 26.417 40.968 ;
     RECT  25.553 27.744 26.444 30.408 ;
     RECT  25.085 9.072 26.449 9.24 ;
     RECT  25.697 10.368 26.489 10.392 ;
     RECT  26.444 27.744 26.531 31.272 ;
     RECT  26.377 14.88 26.561 22.632 ;
     RECT  26.309 91.44 26.593 91.464 ;
     RECT  26.147 83.376 26.629 86.472 ;
     RECT  26.531 27.744 26.633 30.936 ;
     RECT  25.949 92.928 26.633 96.36 ;
     RECT  26.629 83.376 26.665 86.52 ;
     RECT  26.197 32.448 26.669 34.344 ;
     RECT  26.669 32.736 26.701 34.344 ;
     RECT  25.516 35.472 26.701 35.496 ;
     RECT  26.093 42 26.701 42.216 ;
     RECT  26.377 43.344 26.701 48.984 ;
     RECT  26.309 12.768 26.737 13.704 ;
     RECT  26.701 42 26.737 48.984 ;
     RECT  25.621 50.064 26.737 60.984 ;
     RECT  26.233 61.968 26.737 67.416 ;
     RECT  26.561 20.064 26.779 22.632 ;
     RECT  26.243 103.2 26.813 105.384 ;
     RECT  26.309 68.448 26.845 81.48 ;
     RECT  26.737 42 26.957 67.416 ;
     RECT  25.337 106.992 26.989 107.016 ;
     RECT  26.593 91.44 26.993 91.896 ;
     RECT  26.845 68.4 27.059 81.48 ;
     RECT  26.417 40.128 27.061 40.968 ;
     RECT  26.957 42 27.061 42.6 ;
     RECT  26.701 32.736 27.157 35.592 ;
     RECT  26.633 94.272 27.197 96.36 ;
     RECT  26.147 97.344 27.197 100.056 ;
     RECT  26.561 14.88 27.203 18.792 ;
     RECT  26.147 101.616 27.205 101.928 ;
     RECT  26.957 43.728 27.241 67.416 ;
     RECT  27.059 68.4 27.241 75.96 ;
     RECT  26.993 91.872 27.241 91.896 ;
     RECT  26.633 92.928 27.241 93.096 ;
     RECT  27.205 101.616 27.277 102.312 ;
     RECT  27.241 91.872 27.281 93.096 ;
     RECT  26.147 3.216 27.313 8.088 ;
     RECT  26.449 9.072 27.313 9.384 ;
     RECT  26.309 87.84 27.313 90.408 ;
     RECT  27.197 94.272 27.317 100.056 ;
     RECT  27.241 43.728 27.395 75.96 ;
     RECT  26.737 12.048 27.421 13.704 ;
     RECT  27.395 50.064 27.425 75.96 ;
     RECT  27.203 14.88 27.493 17.736 ;
     RECT  26.129 23.616 27.493 26.664 ;
     RECT  26.633 27.744 27.493 30.744 ;
     RECT  27.061 40.128 27.497 42.6 ;
     RECT  27.157 32.736 27.565 35.88 ;
     RECT  25.985 36.912 27.565 38.712 ;
     RECT  27.565 32.736 27.569 38.712 ;
     RECT  26.989 106.896 27.589 107.016 ;
     RECT  27.425 67.248 27.605 75.96 ;
     RECT  26.665 83.376 27.637 86.616 ;
     RECT  27.493 14.832 27.641 17.736 ;
     RECT  27.313 87.84 27.641 90.792 ;
     RECT  27.589 106.56 27.676 107.016 ;
     RECT  27.059 76.992 27.713 81.48 ;
     RECT  27.203 18.768 27.817 18.792 ;
     RECT  26.779 20.112 27.817 22.632 ;
     RECT  27.493 23.616 27.817 30.744 ;
     RECT  27.676 106.896 27.817 107.016 ;
     RECT  27.425 50.064 27.82 66.168 ;
     RECT  27.569 33.072 27.857 38.712 ;
     RECT  27.313 3.216 27.877 9.384 ;
     RECT  27.82 50.064 27.893 66.072 ;
     RECT  27.281 91.872 27.893 92.952 ;
     RECT  27.877 3.216 27.923 10.008 ;
     RECT  27.421 11.088 27.923 13.704 ;
     RECT  27.277 101.472 27.925 102.312 ;
     RECT  27.637 83.232 27.932 86.616 ;
     RECT  27.817 18.768 27.961 30.744 ;
     RECT  27.923 3.216 27.965 8.424 ;
     RECT  27.317 96.24 28.033 100.056 ;
     RECT  27.925 101.04 28.033 102.312 ;
     RECT  27.857 35.52 28.037 38.712 ;
     RECT  27.893 52.512 28.037 66.072 ;
     RECT  26.813 103.296 28.067 105.384 ;
     RECT  27.965 3.216 28.073 8.232 ;
     RECT  27.713 76.992 28.145 81 ;
     RECT  27.641 14.88 28.177 17.736 ;
     RECT  27.961 18.768 28.177 31.32 ;
     RECT  28.177 14.88 28.217 31.32 ;
     RECT  28.145 77.904 28.217 81 ;
     RECT  28.033 96.24 28.217 102.312 ;
     RECT  27.893 92.112 28.285 92.952 ;
     RECT  27.317 94.272 28.285 95.208 ;
     RECT  27.932 83.232 28.289 87 ;
     RECT  27.923 9.792 28.325 10.008 ;
     RECT  28.217 15.648 28.355 31.32 ;
     RECT  27.395 43.728 28.361 49.08 ;
     RECT  28.355 18.864 28.397 31.32 ;
     RECT  28.037 63.6 28.397 66.072 ;
     RECT  28.361 44.208 28.453 49.08 ;
     RECT  27.893 50.064 28.453 51.48 ;
     RECT  27.497 40.128 28.537 42.216 ;
     RECT  28.465 82.224 28.645 82.248 ;
     RECT  28.289 83.232 28.645 84.36 ;
     RECT  28.289 85.44 28.753 87 ;
     RECT  27.641 88.368 28.753 90.792 ;
     RECT  28.067 104.352 28.753 105.384 ;
     RECT  28.217 101.472 28.789 102.312 ;
     RECT  28.067 103.296 28.789 103.32 ;
     RECT  27.857 33.072 28.825 34.2 ;
     RECT  27.605 67.392 28.861 75.768 ;
     RECT  28.217 79.968 28.861 81 ;
     RECT  28.645 82.224 28.861 84.36 ;
     RECT  28.825 33.072 28.933 34.44 ;
     RECT  28.453 44.208 28.933 51.48 ;
     RECT  28.037 52.512 28.933 62.616 ;
     RECT  27.817 106.896 28.933 107.496 ;
     RECT  28.537 40.128 28.969 43.128 ;
     RECT  28.933 33.072 29.005 34.488 ;
     RECT  28.037 35.712 29.005 38.712 ;
     RECT  28.933 44.208 29.041 62.616 ;
     RECT  28.397 63.6 29.041 65.016 ;
     RECT  28.397 66.048 29.041 66.072 ;
     RECT  28.861 67.152 29.041 75.768 ;
     RECT  29.005 33.072 29.077 38.712 ;
     RECT  29.041 66.048 29.077 75.768 ;
     RECT  28.285 92.112 29.077 95.208 ;
     RECT  28.217 96.24 29.077 100.296 ;
     RECT  28.753 104.352 29.105 105.48 ;
     RECT  28.933 106.896 29.105 107.592 ;
     RECT  29.077 33.072 29.185 38.76 ;
     RECT  28.969 39.84 29.185 43.128 ;
     RECT  28.217 77.904 29.185 78.744 ;
     RECT  28.073 4.32 29.293 8.232 ;
     RECT  28.325 9.792 29.293 9.816 ;
     RECT  29.185 77.328 29.293 78.744 ;
     RECT  29.185 33.072 29.365 43.128 ;
     RECT  29.041 44.208 29.365 65.016 ;
     RECT  28.753 85.44 29.365 90.792 ;
     RECT  28.355 15.648 29.401 17.736 ;
     RECT  28.397 19.392 29.401 31.32 ;
     RECT  28.073 3.216 29.408 3.24 ;
     RECT  29.293 4.32 29.408 9.816 ;
     RECT  27.923 11.136 29.408 13.704 ;
     RECT  29.401 15.648 29.408 31.32 ;
     RECT  29.365 33.072 29.408 65.016 ;
     RECT  29.077 66.048 29.408 75.864 ;
     RECT  29.293 77.28 29.408 78.744 ;
     RECT  28.861 79.968 29.408 84.36 ;
     RECT  29.365 85.44 29.408 91.08 ;
     RECT  29.077 92.112 29.408 100.296 ;
     RECT  28.789 101.472 29.408 103.32 ;
     RECT  29.105 104.352 29.408 107.592 ;
     RECT  29.408 2.148 29.512 108.012 ;
     RECT  29.512 2.418 29.704 107.742 ;
     RECT  29.704 33.12 29.837 67.416 ;
     RECT  29.704 8.448 29.891 11.736 ;
     RECT  29.704 19.968 29.945 30.696 ;
     RECT  29.837 33.12 30.089 34.488 ;
     RECT  29.945 19.968 30.161 30.264 ;
     RECT  29.891 10.704 30.197 11.736 ;
     RECT  29.704 79.968 30.227 89.256 ;
     RECT  29.704 92.208 30.233 105.912 ;
     RECT  30.197 11.712 30.269 11.736 ;
     RECT  29.837 35.856 30.269 67.416 ;
     RECT  29.704 90.288 30.305 90.936 ;
     RECT  30.269 35.856 30.377 63.912 ;
     RECT  30.233 96.24 30.377 105.912 ;
     RECT  29.704 12.864 30.413 14.76 ;
     RECT  30.377 35.856 30.419 63.816 ;
     RECT  30.269 64.944 30.485 67.416 ;
     RECT  30.089 33.264 30.557 34.488 ;
     RECT  29.704 107.568 30.661 107.742 ;
     RECT  30.377 96.24 30.665 105.816 ;
     RECT  30.233 92.208 30.701 95.256 ;
     RECT  30.227 79.968 30.737 81.096 ;
     RECT  30.661 107.568 30.757 107.784 ;
     RECT  30.757 106.848 30.803 107.784 ;
     RECT  29.704 4.176 30.805 7.368 ;
     RECT  29.891 8.448 30.805 9.576 ;
     RECT  30.485 66.768 30.805 67.416 ;
     RECT  29.704 68.496 30.805 68.712 ;
     RECT  30.701 92.208 30.805 95.208 ;
     RECT  30.227 82.08 30.901 89.256 ;
     RECT  30.305 90.288 30.901 90.792 ;
     RECT  29.704 2.592 30.985 3.192 ;
     RECT  30.805 4.176 30.985 9.576 ;
     RECT  30.161 19.968 30.985 30.168 ;
     RECT  30.419 36.096 31.025 63.816 ;
     RECT  30.901 82.08 31.091 90.792 ;
     RECT  30.985 19.824 31.097 30.168 ;
     RECT  31.025 43.248 31.097 63.816 ;
     RECT  30.197 10.704 31.165 10.728 ;
     RECT  30.805 66.768 31.165 68.712 ;
     RECT  29.704 31.776 31.237 31.8 ;
     RECT  29.704 16.608 31.273 18.6 ;
     RECT  29.704 70.176 31.273 78.936 ;
     RECT  30.737 79.968 31.273 80.856 ;
     RECT  30.413 12.864 31.277 14.136 ;
     RECT  30.985 2.592 31.313 9.576 ;
     RECT  31.273 16.608 31.349 19.032 ;
     RECT  31.165 66.768 31.417 68.904 ;
     RECT  31.273 70.176 31.417 80.856 ;
     RECT  30.665 102.48 31.429 105.816 ;
     RECT  30.803 106.848 31.429 106.872 ;
     RECT  31.313 8.16 31.436 9.576 ;
     RECT  31.165 10.704 31.436 10.968 ;
     RECT  31.097 20.064 31.637 30.168 ;
     RECT  31.025 36.096 31.637 42.216 ;
     RECT  30.805 91.872 31.637 95.208 ;
     RECT  31.637 23.04 31.673 30.168 ;
     RECT  31.277 12.864 31.741 13.992 ;
     RECT  30.557 33.264 31.741 34.44 ;
     RECT  31.741 33.264 31.813 35.064 ;
     RECT  31.637 36.096 31.813 38.664 ;
     RECT  31.637 94.368 31.813 95.208 ;
     RECT  30.665 96.24 31.813 101.16 ;
     RECT  31.349 17.04 31.817 19.032 ;
     RECT  31.417 66.768 31.849 80.856 ;
     RECT  31.091 82.08 31.849 90.696 ;
     RECT  31.849 66.768 31.853 90.696 ;
     RECT  31.429 102.48 31.861 106.872 ;
     RECT  31.637 20.064 31.907 21.672 ;
     RECT  31.436 8.16 31.993 10.968 ;
     RECT  31.741 12.048 31.993 13.992 ;
     RECT  31.813 94.368 31.993 101.16 ;
     RECT  31.861 102.24 31.993 106.872 ;
     RECT  31.237 31.296 32.033 31.8 ;
     RECT  31.313 2.592 32.069 7.08 ;
     RECT  31.853 67.152 32.069 90.696 ;
     RECT  32.069 4.176 32.105 7.08 ;
     RECT  31.993 8.16 32.141 13.992 ;
     RECT  32.069 68.544 32.213 90.696 ;
     RECT  31.993 94.368 32.281 106.872 ;
     RECT  32.069 2.592 32.285 3.144 ;
     RECT  32.213 68.544 32.285 90.6 ;
     RECT  31.907 20.064 32.348 21.48 ;
     RECT  31.637 40.176 32.38 42.216 ;
     RECT  31.817 17.04 32.425 18.504 ;
     RECT  30.485 64.944 32.425 65.688 ;
     RECT  32.348 19.68 32.435 21.48 ;
     RECT  32.425 16.608 32.461 18.504 ;
     RECT  32.281 94.368 32.465 107.784 ;
     RECT  32.105 6.336 32.485 7.08 ;
     RECT  32.141 8.16 32.485 9.144 ;
     RECT  31.673 23.616 32.497 30.168 ;
     RECT  32.285 68.544 32.531 80.52 ;
     RECT  31.097 43.344 32.569 63.816 ;
     RECT  32.38 40.32 32.605 42.216 ;
     RECT  32.141 10.416 32.609 13.992 ;
     RECT  32.497 23.616 32.609 30.36 ;
     RECT  31.813 33.264 32.609 38.664 ;
     RECT  32.609 11.952 32.629 13.992 ;
     RECT  31.561 15.024 32.629 15.048 ;
     RECT  32.609 23.616 32.641 24.984 ;
     RECT  32.605 40.32 32.677 42.264 ;
     RECT  32.569 43.248 32.677 63.816 ;
     RECT  32.069 67.152 32.681 67.416 ;
     RECT  32.609 33.264 32.713 38.616 ;
     RECT  32.641 23.184 32.965 24.984 ;
     RECT  32.465 104.544 33.005 107.784 ;
     RECT  32.435 20.112 33.037 21.48 ;
     RECT  32.629 11.952 33.059 15.048 ;
     RECT  32.677 40.32 33.061 63.816 ;
     RECT  32.425 64.944 33.061 65.976 ;
     RECT  32.681 67.248 33.073 67.416 ;
     RECT  32.531 68.544 33.073 80.472 ;
     RECT  32.609 26.256 33.077 30.36 ;
     RECT  32.485 6.336 33.113 9.144 ;
     RECT  31.637 91.872 33.181 93.192 ;
     RECT  33.181 91.872 33.221 93.336 ;
     RECT  33.037 20.112 33.253 21.72 ;
     RECT  33.253 20.112 33.289 21.816 ;
     RECT  32.965 23.04 33.289 24.984 ;
     RECT  33.061 40.32 33.289 65.976 ;
     RECT  33.077 28.704 33.293 30.36 ;
     RECT  33.113 7.968 33.329 9.144 ;
     RECT  33.293 29.04 33.361 30.36 ;
     RECT  32.105 4.176 33.397 5.256 ;
     RECT  33.059 12 33.397 15.048 ;
     RECT  32.461 16.32 33.397 18.504 ;
     RECT  33.005 104.544 33.433 106.584 ;
     RECT  33.289 40.32 33.5 66.024 ;
     RECT  33.361 29.04 33.505 30.792 ;
     RECT  32.033 31.776 33.505 31.8 ;
     RECT  33.005 107.664 33.545 107.784 ;
     RECT  33.505 29.04 33.577 31.8 ;
     RECT  32.713 33.072 33.577 38.616 ;
     RECT  33.5 39.888 33.577 66.024 ;
     RECT  32.465 94.368 33.581 103.032 ;
     RECT  32.285 2.88 33.649 3.144 ;
     RECT  33.397 4.176 33.649 5.352 ;
     RECT  33.329 8.016 33.649 9.144 ;
     RECT  32.609 10.416 33.649 10.968 ;
     RECT  33.649 8.016 33.653 10.968 ;
     RECT  32.285 81.936 33.683 90.6 ;
     RECT  33.397 12 33.721 18.504 ;
     RECT  33.683 81.936 33.725 88.008 ;
     RECT  33.577 29.04 33.757 66.024 ;
     RECT  33.073 67.248 33.937 80.472 ;
     RECT  33.289 20.112 34.021 24.984 ;
     RECT  34.021 19.968 34.081 24.984 ;
     RECT  33.077 26.256 34.081 27.72 ;
     RECT  33.433 104.4 34.153 106.584 ;
     RECT  33.649 2.88 34.172 5.352 ;
     RECT  34.153 104.304 34.261 106.584 ;
     RECT  33.757 29.04 34.268 66.264 ;
     RECT  33.937 67.248 34.268 81.336 ;
     RECT  33.113 6.336 34.369 6.888 ;
     RECT  33.653 8.016 34.369 8.568 ;
     RECT  33.721 12 34.477 18.696 ;
     RECT  33.653 9.696 34.765 10.968 ;
     RECT  34.477 12 34.765 18.792 ;
     RECT  34.172 2.256 34.808 5.352 ;
     RECT  34.369 6.336 34.808 8.568 ;
     RECT  34.765 9.696 34.808 18.84 ;
     RECT  34.081 19.968 34.808 27.72 ;
     RECT  34.268 29.04 34.808 81.336 ;
     RECT  33.725 82.464 34.808 88.008 ;
     RECT  33.683 89.088 34.808 90.6 ;
     RECT  33.221 92.256 34.808 93.336 ;
     RECT  33.581 94.368 34.808 102.936 ;
     RECT  34.261 104.256 34.808 106.584 ;
     RECT  33.545 107.76 34.808 107.784 ;
     RECT  34.808 2.148 34.912 108.012 ;
     RECT  34.912 2.418 35.104 107.742 ;
     RECT  35.104 20.112 35.201 22.152 ;
     RECT  35.104 41.904 35.219 80.424 ;
     RECT  35.104 81.6 35.219 86.808 ;
     RECT  35.104 87.84 35.219 90.696 ;
     RECT  35.104 91.728 35.219 106.296 ;
     RECT  35.104 10.176 35.273 10.728 ;
     RECT  35.219 87.888 35.273 90.696 ;
     RECT  35.219 92.256 35.345 106.296 ;
     RECT  35.104 23.328 35.555 32.52 ;
     RECT  35.104 2.736 35.561 3.144 ;
     RECT  35.104 4.128 35.849 9.096 ;
     RECT  35.104 33.552 35.885 40.92 ;
     RECT  35.345 92.4 35.98 106.296 ;
     RECT  35.104 16.32 36.065 19.08 ;
     RECT  35.273 10.272 36.137 10.728 ;
     RECT  35.98 101.856 36.169 106.296 ;
     RECT  35.555 23.328 36.205 30.648 ;
     RECT  35.219 64.32 36.205 80.424 ;
     RECT  36.169 101.856 36.277 106.584 ;
     RECT  35.849 5.76 36.313 9.096 ;
     RECT  35.104 11.76 36.385 14.472 ;
     RECT  35.555 31.68 36.421 32.52 ;
     RECT  35.885 33.552 36.421 40.872 ;
     RECT  36.065 16.32 36.457 17.496 ;
     RECT  36.277 101.856 36.461 107.304 ;
     RECT  35.219 41.904 36.493 63.144 ;
     RECT  36.205 64.32 36.493 81.144 ;
     RECT  36.137 10.704 36.529 10.728 ;
     RECT  36.385 11.76 36.529 14.952 ;
     RECT  36.065 18.576 36.565 19.08 ;
     RECT  35.201 20.208 36.565 22.152 ;
     RECT  36.529 10.704 36.605 14.952 ;
     RECT  36.493 41.904 36.605 81.144 ;
     RECT  36.605 11.664 36.641 14.952 ;
     RECT  36.421 31.68 36.641 40.872 ;
     RECT  35.219 82.176 36.709 86.808 ;
     RECT  35.273 87.888 36.709 88.392 ;
     RECT  36.641 31.68 36.745 34.2 ;
     RECT  36.605 41.904 36.745 42.6 ;
     RECT  35.98 92.4 36.851 100.872 ;
     RECT  36.565 18.576 36.853 22.152 ;
     RECT  36.205 23.184 36.853 30.648 ;
     RECT  35.849 4.128 36.925 4.776 ;
     RECT  36.605 43.968 36.929 81.144 ;
     RECT  36.929 44.208 36.965 81.144 ;
     RECT  35.561 2.736 36.997 2.76 ;
     RECT  36.965 61.968 36.997 81.144 ;
     RECT  36.709 82.176 36.997 88.392 ;
     RECT  36.641 35.184 37.033 40.872 ;
     RECT  36.745 41.856 37.033 42.6 ;
     RECT  36.997 61.968 37.073 88.392 ;
     RECT  36.641 14.928 37.213 14.952 ;
     RECT  36.457 15.984 37.213 17.496 ;
     RECT  37.073 61.968 37.217 74.664 ;
     RECT  36.925 3.936 37.249 4.776 ;
     RECT  36.313 5.76 37.249 9.528 ;
     RECT  37.073 75.744 37.361 88.392 ;
     RECT  37.213 14.928 37.381 17.496 ;
     RECT  36.853 18.576 37.381 30.648 ;
     RECT  36.641 11.664 37.469 13.704 ;
     RECT  37.381 14.928 37.469 30.648 ;
     RECT  35.273 89.616 37.573 90.696 ;
     RECT  37.361 75.744 37.685 87.384 ;
     RECT  36.745 31.632 37.717 34.2 ;
     RECT  37.033 35.184 37.717 42.6 ;
     RECT  36.851 92.4 37.757 100.824 ;
     RECT  37.757 92.4 37.789 100.296 ;
     RECT  37.789 92.304 37.861 100.296 ;
     RECT  37.469 17.424 37.897 30.648 ;
     RECT  37.717 31.632 37.897 42.6 ;
     RECT  37.897 17.424 38.005 42.6 ;
     RECT  36.965 44.208 38.005 60.984 ;
     RECT  36.461 101.952 38.005 107.304 ;
     RECT  38.005 17.424 38.045 60.984 ;
     RECT  38.045 51.12 38.113 60.984 ;
     RECT  37.217 61.968 38.113 64.392 ;
     RECT  38.045 17.424 38.117 49.848 ;
     RECT  36.997 2.736 38.185 2.952 ;
     RECT  37.249 3.936 38.185 9.528 ;
     RECT  38.113 51.12 38.185 64.392 ;
     RECT  37.217 65.424 38.185 74.664 ;
     RECT  37.685 75.744 38.185 85.08 ;
     RECT  38.117 20.112 38.189 49.848 ;
     RECT  38.185 2.736 38.225 9.528 ;
     RECT  38.189 20.112 38.225 26.376 ;
     RECT  37.573 88.464 38.225 90.696 ;
     RECT  38.225 88.512 38.243 90.696 ;
     RECT  37.861 92.256 38.245 100.296 ;
     RECT  38.225 3.024 38.257 9.528 ;
     RECT  38.243 88.608 38.329 90.696 ;
     RECT  38.245 92.112 38.329 100.296 ;
     RECT  38.189 27.696 38.333 49.848 ;
     RECT  38.185 51.12 38.405 85.08 ;
     RECT  38.333 27.696 38.441 49.8 ;
     RECT  38.441 43.68 38.585 49.8 ;
     RECT  38.405 51.12 38.621 64.392 ;
     RECT  38.405 65.424 38.657 85.08 ;
     RECT  38.117 17.424 38.801 19.08 ;
     RECT  38.257 3.024 38.945 9.816 ;
     RECT  38.945 6.24 39.053 9.816 ;
     RECT  38.657 65.568 39.053 85.08 ;
     RECT  39.053 75.744 39.197 85.08 ;
     RECT  37.469 11.76 39.265 13.704 ;
     RECT  37.469 14.928 39.265 16.44 ;
     RECT  38.225 20.112 39.301 25.32 ;
     RECT  38.225 26.352 39.301 26.376 ;
     RECT  39.197 77.904 39.301 85.08 ;
     RECT  37.685 86.304 39.301 87.384 ;
     RECT  38.005 101.952 39.301 107.544 ;
     RECT  38.621 51.12 39.349 61.992 ;
     RECT  39.265 11.76 39.481 16.44 ;
     RECT  38.801 17.424 39.481 18.6 ;
     RECT  38.585 44.112 39.589 49.8 ;
     RECT  39.349 50.832 39.589 61.992 ;
     RECT  38.329 88.608 39.589 100.296 ;
     RECT  39.301 101.856 39.589 107.544 ;
     RECT  39.589 44.112 39.625 61.992 ;
     RECT  39.625 44.016 39.733 61.992 ;
     RECT  38.441 27.696 39.877 42.6 ;
     RECT  39.733 43.584 39.877 61.992 ;
     RECT  38.621 63.216 39.877 64.392 ;
     RECT  39.053 65.568 39.877 74.712 ;
     RECT  39.301 20.112 39.913 26.376 ;
     RECT  39.877 27.696 39.913 61.992 ;
     RECT  39.481 11.76 39.985 18.6 ;
     RECT  38.945 3.024 40.057 5.208 ;
     RECT  39.913 20.112 40.165 61.992 ;
     RECT  39.877 63.216 40.165 74.712 ;
     RECT  40.057 2.784 40.208 5.208 ;
     RECT  39.053 6.24 40.208 9.624 ;
     RECT  39.985 11.424 40.208 18.6 ;
     RECT  40.165 20.064 40.208 74.712 ;
     RECT  39.197 75.744 40.208 76.92 ;
     RECT  39.301 77.904 40.208 87.384 ;
     RECT  39.589 88.608 40.208 107.544 ;
     RECT  40.208 2.148 40.312 108.012 ;
     RECT  40.312 2.418 40.504 107.784 ;
     RECT  40.504 101.04 40.529 107.784 ;
     RECT  40.504 75.744 40.637 84.696 ;
     RECT  40.504 2.88 40.673 2.904 ;
     RECT  40.504 3.936 40.673 9.624 ;
     RECT  40.673 4.128 40.739 9.624 ;
     RECT  40.504 22.56 40.745 30.696 ;
     RECT  40.504 15.984 40.817 21.528 ;
     RECT  40.529 102.288 40.925 107.784 ;
     RECT  40.745 22.56 40.961 28.104 ;
     RECT  40.925 102.288 40.961 106.296 ;
     RECT  40.637 80.976 40.997 84.648 ;
     RECT  40.739 7.728 41.027 9.624 ;
     RECT  40.739 4.128 41.033 6.696 ;
     RECT  40.817 16.032 41.033 21.528 ;
     RECT  41.033 16.032 41.069 18.504 ;
     RECT  40.504 86.304 41.069 87.144 ;
     RECT  41.069 16.608 41.105 18.504 ;
     RECT  40.504 10.8 41.171 14.856 ;
     RECT  41.171 10.8 41.213 14.136 ;
     RECT  40.961 22.848 41.213 28.104 ;
     RECT  41.027 7.728 41.249 9.096 ;
     RECT  41.033 4.128 41.285 6.648 ;
     RECT  41.285 4.176 41.321 6.648 ;
     RECT  40.504 31.776 41.357 34.2 ;
     RECT  40.504 89.28 41.497 99.816 ;
     RECT  41.321 5.472 41.537 6.648 ;
     RECT  40.504 35.472 41.569 63.912 ;
     RECT  40.504 64.992 41.569 74.712 ;
     RECT  41.069 86.304 41.569 87.096 ;
     RECT  41.497 88.8 41.569 99.816 ;
     RECT  41.569 35.472 41.603 74.712 ;
     RECT  41.569 88.224 41.603 99.816 ;
     RECT  41.603 35.472 41.609 35.928 ;
     RECT  41.249 7.728 41.681 8.472 ;
     RECT  41.569 86.064 41.681 87.096 ;
     RECT  40.997 81.12 41.785 84.648 ;
     RECT  41.213 22.848 41.861 25.752 ;
     RECT  41.603 37.008 41.861 74.712 ;
     RECT  41.603 88.224 41.861 96.312 ;
     RECT  41.861 41.76 41.897 74.712 ;
     RECT  40.961 102.288 41.929 103.224 ;
     RECT  40.961 104.352 41.929 106.296 ;
     RECT  41.213 26.784 41.939 28.104 ;
     RECT  41.897 41.76 41.969 42.696 ;
     RECT  41.213 10.8 42.001 13.8 ;
     RECT  40.637 75.744 42.001 79.992 ;
     RECT  41.861 88.224 42.005 93.288 ;
     RECT  41.537 6 42.037 6.648 ;
     RECT  41.681 7.728 42.037 7.896 ;
     RECT  40.529 101.04 42.037 101.064 ;
     RECT  41.929 102.288 42.037 106.296 ;
     RECT  41.033 19.632 42.073 21.528 ;
     RECT  40.745 29.28 42.073 30.696 ;
     RECT  41.897 43.824 42.109 74.712 ;
     RECT  42.001 75.696 42.109 79.992 ;
     RECT  41.681 86.304 42.109 87.096 ;
     RECT  41.105 16.608 42.145 18.312 ;
     RECT  40.925 107.328 42.145 107.784 ;
     RECT  41.609 35.76 42.185 35.928 ;
     RECT  42.145 107.328 42.221 107.928 ;
     RECT  41.861 23.616 42.325 25.752 ;
     RECT  41.939 26.784 42.325 28.056 ;
     RECT  41.603 97.584 42.325 99.816 ;
     RECT  42.037 101.04 42.325 106.296 ;
     RECT  42.325 97.584 42.361 106.296 ;
     RECT  42.109 43.824 42.397 80.088 ;
     RECT  41.785 81.12 42.397 84.984 ;
     RECT  42.145 16.608 42.541 18.6 ;
     RECT  42.001 10.752 42.545 13.8 ;
     RECT  42.325 23.616 42.545 28.056 ;
     RECT  42.073 29.28 42.577 30.744 ;
     RECT  41.357 32.016 42.577 34.2 ;
     RECT  42.545 25.728 42.581 28.056 ;
     RECT  42.541 15.984 42.649 18.6 ;
     RECT  42.073 19.632 42.649 22.344 ;
     RECT  42.037 6 42.685 7.896 ;
     RECT  42.649 9.408 42.685 9.432 ;
     RECT  41.861 37.008 42.721 40.776 ;
     RECT  41.861 94.272 42.721 96.312 ;
     RECT  42.649 15.984 42.725 22.344 ;
     RECT  42.361 97.584 42.725 106.536 ;
     RECT  42.685 9.408 42.757 9.624 ;
     RECT  42.545 10.752 42.757 13.704 ;
     RECT  42.109 86.304 42.793 87.144 ;
     RECT  42.005 88.224 42.793 90.744 ;
     RECT  42.685 6 42.797 7.944 ;
     RECT  42.005 91.728 42.829 93.288 ;
     RECT  42.721 94.272 42.829 96.504 ;
     RECT  42.185 35.76 42.865 35.88 ;
     RECT  42.725 15.984 42.899 21.96 ;
     RECT  42.725 97.584 42.949 106.296 ;
     RECT  42.721 36.96 42.973 40.776 ;
     RECT  41.969 42.048 42.973 42.696 ;
     RECT  42.899 19.296 42.977 21.96 ;
     RECT  42.577 29.28 43.009 34.2 ;
     RECT  42.793 86.304 43.009 90.744 ;
     RECT  42.829 91.728 43.009 96.504 ;
     RECT  42.865 35.472 43.049 35.88 ;
     RECT  41.321 4.176 43.117 4.2 ;
     RECT  42.581 27.312 43.189 28.056 ;
     RECT  43.009 29.232 43.189 34.2 ;
     RECT  42.973 36.96 43.189 42.696 ;
     RECT  42.397 43.824 43.189 84.984 ;
     RECT  43.009 86.304 43.225 96.504 ;
     RECT  42.949 97.536 43.225 106.296 ;
     RECT  43.189 27.312 43.261 34.2 ;
     RECT  43.049 35.472 43.261 35.832 ;
     RECT  43.189 43.824 43.261 85.128 ;
     RECT  43.225 86.304 43.261 106.296 ;
     RECT  43.189 36.96 43.265 42.744 ;
     RECT  43.117 3.888 43.285 4.2 ;
     RECT  43.261 27.312 43.517 35.832 ;
     RECT  42.545 23.616 43.525 24.696 ;
     RECT  42.581 25.728 43.525 26.28 ;
     RECT  43.525 23.616 43.585 26.28 ;
     RECT  43.517 27.312 43.585 34.2 ;
     RECT  43.261 43.824 43.589 106.296 ;
     RECT  43.589 43.824 43.667 81.576 ;
     RECT  42.977 19.584 43.724 21.96 ;
     RECT  43.585 23.616 43.765 34.2 ;
     RECT  43.517 35.28 43.769 35.832 ;
     RECT  43.265 40.32 43.868 42.744 ;
     RECT  43.667 43.824 43.868 44.472 ;
     RECT  43.765 23.568 43.913 34.2 ;
     RECT  43.724 19.584 44.021 22.2 ;
     RECT  43.589 82.704 44.021 106.296 ;
     RECT  43.285 3.888 44.053 5.064 ;
     RECT  42.797 6.144 44.053 7.944 ;
     RECT  44.012 2.688 44.099 2.712 ;
     RECT  42.899 15.984 44.129 17.928 ;
     RECT  44.021 82.704 44.129 96.504 ;
     RECT  42.757 9.408 44.197 13.704 ;
     RECT  43.265 36.96 44.197 39.288 ;
     RECT  44.053 3.888 44.269 7.944 ;
     RECT  44.197 36.768 44.417 39.288 ;
     RECT  44.197 9.408 44.449 14.424 ;
     RECT  44.129 15.984 44.449 17.496 ;
     RECT  44.021 20.112 44.485 22.2 ;
     RECT  43.913 23.568 44.485 34.152 ;
     RECT  44.485 20.112 44.525 34.152 ;
     RECT  44.269 3.024 44.557 7.944 ;
     RECT  44.449 9.168 44.557 17.496 ;
     RECT  44.129 82.704 44.561 87.288 ;
     RECT  44.161 18.96 44.597 18.984 ;
     RECT  44.417 36.96 44.737 39.288 ;
     RECT  43.868 40.32 44.737 44.472 ;
     RECT  42.221 107.904 44.845 107.928 ;
     RECT  43.667 45.552 44.989 81.576 ;
     RECT  44.561 82.704 44.989 87.096 ;
     RECT  44.737 36.96 45.205 44.472 ;
     RECT  44.989 45.552 45.205 87.096 ;
     RECT  44.525 20.112 45.277 25.752 ;
     RECT  44.525 27.072 45.277 34.152 ;
     RECT  43.769 35.28 45.277 35.592 ;
     RECT  44.557 3.024 45.385 17.496 ;
     RECT  44.953 18.528 45.385 18.552 ;
     RECT  44.129 88.368 45.385 96.504 ;
     RECT  44.021 97.536 45.385 106.296 ;
     RECT  45.385 3.024 45.608 18.552 ;
     RECT  45.277 19.536 45.608 25.752 ;
     RECT  45.277 27.072 45.608 34.2 ;
     RECT  45.277 35.28 45.608 35.832 ;
     RECT  45.205 36.96 45.608 87.096 ;
     RECT  45.385 88.368 45.608 106.296 ;
     RECT  44.845 107.712 45.608 107.928 ;
     RECT  45.608 2.148 45.712 108.012 ;
     RECT  45.712 2.418 45.904 107.742 ;
     RECT  45.904 2.418 45.929 9.816 ;
     RECT  45.904 27.072 45.929 34.2 ;
     RECT  45.904 35.184 46.019 42.792 ;
     RECT  45.904 43.92 46.045 74.424 ;
     RECT  45.904 21.936 46.109 25.992 ;
     RECT  45.904 11.136 46.145 15.048 ;
     RECT  45.904 75.408 46.163 106.296 ;
     RECT  46.163 90 46.252 106.296 ;
     RECT  46.109 22.128 46.253 25.992 ;
     RECT  46.163 75.408 46.253 89.016 ;
     RECT  46.252 90 46.253 100.584 ;
     RECT  45.929 2.418 46.289 9.72 ;
     RECT  46.019 37.344 46.433 42.792 ;
     RECT  46.252 101.712 46.469 106.296 ;
     RECT  46.253 75.984 46.505 89.016 ;
     RECT  46.045 43.92 46.54 52.728 ;
     RECT  46.505 75.984 46.685 84.36 ;
     RECT  45.904 16.032 46.757 20.904 ;
     RECT  46.289 2.418 46.789 9 ;
     RECT  45.929 27.696 46.793 34.2 ;
     RECT  46.045 53.856 46.793 74.424 ;
     RECT  46.253 22.128 46.828 24.504 ;
     RECT  46.828 22.752 46.865 24.504 ;
     RECT  46.793 28.944 46.885 34.2 ;
     RECT  46.019 35.184 46.885 36.12 ;
     RECT  46.433 39.792 46.897 42.792 ;
     RECT  46.54 43.92 46.897 44.616 ;
     RECT  46.469 103.536 46.901 106.296 ;
     RECT  46.145 11.136 46.933 13.896 ;
     RECT  46.685 77.952 46.973 84.36 ;
     RECT  46.433 37.344 47.005 38.712 ;
     RECT  46.757 18.048 47.009 20.904 ;
     RECT  45.904 107.616 47.041 107.736 ;
     RECT  46.933 10.704 47.045 13.896 ;
     RECT  46.145 14.928 47.077 15.048 ;
     RECT  46.757 16.032 47.077 17.064 ;
     RECT  46.793 27.696 47.077 27.72 ;
     RECT  46.54 45.744 47.113 52.728 ;
     RECT  46.793 53.856 47.113 74.328 ;
     RECT  46.253 25.536 47.117 25.992 ;
     RECT  47.113 45.744 47.153 74.328 ;
     RECT  47.153 46.032 47.189 74.328 ;
     RECT  46.789 2.256 47.257 9 ;
     RECT  46.505 85.344 47.257 89.016 ;
     RECT  46.253 90 47.257 99.96 ;
     RECT  46.469 101.712 47.257 102.504 ;
     RECT  47.257 85.344 47.261 99.96 ;
     RECT  47.257 2.256 47.315 9.432 ;
     RECT  46.885 28.944 47.329 36.12 ;
     RECT  47.261 85.728 47.329 99.96 ;
     RECT  47.189 46.032 47.333 66.84 ;
     RECT  46.973 78.192 47.333 84.36 ;
     RECT  47.041 107.376 47.333 107.736 ;
     RECT  47.315 2.64 47.369 9.432 ;
     RECT  47.333 78.192 47.369 84.312 ;
     RECT  47.009 20.112 47.401 20.904 ;
     RECT  47.077 27.6 47.401 27.72 ;
     RECT  47.333 107.376 47.401 107.4 ;
     RECT  47.369 82.704 47.405 84.312 ;
     RECT  46.865 23.184 47.441 24.504 ;
     RECT  47.329 28.944 47.585 36.168 ;
     RECT  47.077 14.928 47.621 17.064 ;
     RECT  47.585 35.232 47.653 36.168 ;
     RECT  47.005 37.152 47.653 38.712 ;
     RECT  47.369 78.192 47.657 81.72 ;
     RECT  47.329 85.728 47.725 100.104 ;
     RECT  47.257 101.664 47.725 102.504 ;
     RECT  46.897 39.792 47.729 44.616 ;
     RECT  47.585 28.944 47.761 34.248 ;
     RECT  46.685 75.984 47.797 76.92 ;
     RECT  47.117 25.536 47.801 25.848 ;
     RECT  47.729 39.792 47.801 42.744 ;
     RECT  46.901 103.536 47.801 106.056 ;
     RECT  47.441 23.328 47.869 24.504 ;
     RECT  47.801 25.536 47.869 25.8 ;
     RECT  47.333 46.032 47.873 64.44 ;
     RECT  47.009 18.048 47.891 18.84 ;
     RECT  47.873 48.432 47.909 64.44 ;
     RECT  47.725 85.728 47.945 102.504 ;
     RECT  47.369 2.832 48.049 9.432 ;
     RECT  47.891 18.192 48.049 18.84 ;
     RECT  47.401 107.328 48.049 107.4 ;
     RECT  47.653 35.232 48.085 38.712 ;
     RECT  47.801 39.792 48.125 42.6 ;
     RECT  47.909 48.432 48.125 49.848 ;
     RECT  47.045 10.896 48.157 13.848 ;
     RECT  47.621 14.928 48.157 17.016 ;
     RECT  47.189 67.824 48.157 74.328 ;
     RECT  48.049 2.832 48.161 9.672 ;
     RECT  47.909 51.168 48.161 64.44 ;
     RECT  47.873 46.032 48.169 47.352 ;
     RECT  48.161 2.832 48.197 3.144 ;
     RECT  48.157 10.896 48.197 17.016 ;
     RECT  48.049 18.192 48.229 18.936 ;
     RECT  47.401 20.112 48.229 21.528 ;
     RECT  47.797 75.936 48.265 76.92 ;
     RECT  47.657 78.192 48.265 81.672 ;
     RECT  47.945 85.728 48.301 94.968 ;
     RECT  47.401 26.976 48.373 27.72 ;
     RECT  47.761 28.704 48.373 34.248 ;
     RECT  48.157 67.824 48.377 74.664 ;
     RECT  48.161 53.856 48.38 64.44 ;
     RECT  47.333 65.472 48.38 66.84 ;
     RECT  47.945 96 48.409 102.504 ;
     RECT  47.801 103.536 48.409 105.672 ;
     RECT  48.301 85.44 48.481 94.968 ;
     RECT  48.161 4.176 48.557 9.672 ;
     RECT  48.125 40.128 48.557 42.6 ;
     RECT  48.197 2.832 48.625 3.096 ;
     RECT  47.405 82.704 48.625 84.12 ;
     RECT  48.481 85.2 48.625 94.968 ;
     RECT  48.229 18.192 48.733 21.528 ;
     RECT  48.161 51.168 48.773 52.728 ;
     RECT  48.373 26.976 48.805 34.248 ;
     RECT  48.377 68.352 48.805 74.664 ;
     RECT  48.805 26.88 48.841 34.248 ;
     RECT  48.085 35.232 48.841 38.76 ;
     RECT  48.049 107.28 48.841 107.4 ;
     RECT  48.409 96 48.845 105.672 ;
     RECT  47.869 23.328 48.913 25.8 ;
     RECT  48.841 26.88 48.913 38.76 ;
     RECT  47.729 43.92 48.913 44.616 ;
     RECT  48.169 46.032 48.913 47.16 ;
     RECT  48.913 23.328 48.953 38.76 ;
     RECT  48.197 15.984 48.985 17.016 ;
     RECT  48.38 53.856 49.021 66.84 ;
     RECT  48.625 2.352 49.025 3.096 ;
     RECT  49.025 2.352 49.061 2.856 ;
     RECT  48.733 18.192 49.061 22.2 ;
     RECT  48.773 51.696 49.097 52.728 ;
     RECT  48.197 10.896 49.165 14.76 ;
     RECT  48.985 15.984 49.165 17.112 ;
     RECT  49.061 19.536 49.205 22.2 ;
     RECT  48.557 40.272 49.241 42.6 ;
     RECT  48.953 28.848 49.277 38.76 ;
     RECT  48.625 82.704 49.309 94.968 ;
     RECT  48.845 96 49.309 100.632 ;
     RECT  48.841 107.184 49.345 107.4 ;
     RECT  49.345 107.088 49.385 107.4 ;
     RECT  49.309 82.704 49.493 100.632 ;
     RECT  49.021 53.856 49.523 67.32 ;
     RECT  48.805 68.352 49.523 74.76 ;
     RECT  48.953 23.328 49.529 27.816 ;
     RECT  48.845 101.664 49.529 105.672 ;
     RECT  49.165 10.896 49.561 17.112 ;
     RECT  49.061 18.192 49.561 18.264 ;
     RECT  48.557 4.176 49.597 9.432 ;
     RECT  49.561 10.896 49.601 18.264 ;
     RECT  49.523 53.856 49.601 67.272 ;
     RECT  49.601 65.136 49.637 67.272 ;
     RECT  49.493 97.104 49.637 100.632 ;
     RECT  49.523 68.688 49.705 74.76 ;
     RECT  48.265 75.936 49.705 81.672 ;
     RECT  49.529 23.328 49.709 27.72 ;
     RECT  49.601 10.896 49.781 16.344 ;
     RECT  49.205 20.112 49.813 22.2 ;
     RECT  49.709 23.328 49.813 25.896 ;
     RECT  49.597 4.176 49.817 9.528 ;
     RECT  49.241 40.272 49.957 40.728 ;
     RECT  49.277 28.848 49.997 36.216 ;
     RECT  49.061 2.352 50.06 2.76 ;
     RECT  49.817 4.176 50.06 8.04 ;
     RECT  49.097 51.696 50.065 52.584 ;
     RECT  49.705 68.688 50.101 81.672 ;
     RECT  49.493 82.704 50.101 87.096 ;
     RECT  49.241 41.712 50.149 42.6 ;
     RECT  48.913 43.92 50.149 47.16 ;
     RECT  50.065 51.216 50.173 52.584 ;
     RECT  49.529 102 50.209 105.672 ;
     RECT  49.385 107.088 50.209 107.304 ;
     RECT  50.173 51.168 50.245 52.824 ;
     RECT  49.601 53.856 50.245 64.152 ;
     RECT  50.149 41.712 50.281 47.16 ;
     RECT  48.125 48.48 50.281 49.848 ;
     RECT  49.957 39.888 50.353 40.728 ;
     RECT  50.06 2.352 50.389 8.04 ;
     RECT  50.281 41.712 50.444 49.848 ;
     RECT  50.245 51.168 50.533 64.152 ;
     RECT  49.601 17.328 50.569 18.264 ;
     RECT  49.277 37.44 50.605 38.76 ;
     RECT  50.353 39.792 50.605 40.728 ;
     RECT  49.997 28.992 50.677 36.216 ;
     RECT  50.605 37.44 50.677 40.728 ;
     RECT  50.101 68.688 50.713 87.096 ;
     RECT  49.493 88.416 50.713 96.024 ;
     RECT  50.533 51.12 50.725 64.152 ;
     RECT  49.637 65.184 50.725 67.272 ;
     RECT  50.725 51.12 50.821 67.272 ;
     RECT  49.637 97.344 50.821 100.632 ;
     RECT  50.677 28.992 50.869 40.728 ;
     RECT  50.444 41.712 50.869 50.04 ;
     RECT  50.821 97.008 50.893 100.632 ;
     RECT  50.209 102 50.893 107.304 ;
     RECT  49.709 26.88 50.965 27.72 ;
     RECT  50.869 28.992 50.965 50.04 ;
     RECT  50.389 2.256 51.008 8.04 ;
     RECT  49.817 9.024 51.008 9.528 ;
     RECT  49.781 10.896 51.008 16.056 ;
     RECT  50.569 17.184 51.008 18.264 ;
     RECT  49.813 20.112 51.008 25.896 ;
     RECT  50.965 26.88 51.008 50.04 ;
     RECT  50.821 51.12 51.008 67.32 ;
     RECT  50.713 68.688 51.008 96.024 ;
     RECT  50.893 97.008 51.008 107.304 ;
     RECT  51.008 2.148 51.112 108.012 ;
     RECT  51.112 2.418 51.304 107.742 ;
     RECT  51.304 40.848 51.401 44.904 ;
     RECT  51.304 19.632 51.473 22.584 ;
     RECT  51.401 41.952 51.491 44.904 ;
     RECT  51.473 19.632 51.587 20.904 ;
     RECT  51.401 40.848 51.617 40.968 ;
     RECT  51.617 40.944 51.653 40.968 ;
     RECT  51.304 26.784 51.689 39.288 ;
     RECT  51.304 75.744 51.761 80.136 ;
     RECT  51.473 22.224 51.797 22.584 ;
     RECT  51.304 96.912 51.833 107.544 ;
     RECT  51.304 3.024 51.905 9.672 ;
     RECT  51.304 10.896 51.941 18.216 ;
     RECT  51.941 10.896 52.013 14.328 ;
     RECT  51.304 81.12 52.013 84.456 ;
     RECT  51.833 97.008 52.049 107.544 ;
     RECT  51.905 4.176 52.121 9.672 ;
     RECT  51.304 68.976 52.157 74.712 ;
     RECT  52.049 97.008 52.229 105.96 ;
     RECT  51.905 3.024 52.297 3.096 ;
     RECT  51.304 85.488 52.297 87.624 ;
     RECT  51.304 88.656 52.297 95.736 ;
     RECT  51.941 15.6 52.333 18.216 ;
     RECT  52.121 9.024 52.373 9.672 ;
     RECT  51.304 46.032 52.405 62.616 ;
     RECT  51.304 63.84 52.405 67.704 ;
     RECT  52.229 100.848 52.409 105.96 ;
     RECT  52.333 15.6 52.441 18.6 ;
     RECT  51.304 23.616 52.441 25.8 ;
     RECT  51.689 26.784 52.441 38.76 ;
     RECT  52.405 46.032 52.513 67.704 ;
     RECT  52.121 4.176 52.517 7.608 ;
     RECT  51.491 41.952 52.549 44.376 ;
     RECT  52.229 97.008 52.553 99.72 ;
     RECT  51.587 20.208 52.585 20.904 ;
     RECT  52.157 68.976 52.589 74.472 ;
     RECT  52.013 82.656 52.621 84.456 ;
     RECT  52.297 85.488 52.621 95.736 ;
     RECT  52.409 102 52.661 105.96 ;
     RECT  52.585 20.112 52.721 20.904 ;
     RECT  52.721 20.112 52.765 20.952 ;
     RECT  52.661 103.488 52.769 105.96 ;
     RECT  52.513 46.032 52.805 67.8 ;
     RECT  52.549 41.712 52.945 44.376 ;
     RECT  52.621 82.656 52.981 95.736 ;
     RECT  52.013 11.664 52.985 14.328 ;
     RECT  52.589 68.976 52.985 70.296 ;
     RECT  52.297 2.496 53.017 3.096 ;
     RECT  52.805 65.088 53.017 67.8 ;
     RECT  52.985 68.976 53.017 70.008 ;
     RECT  52.013 81.12 53.017 81.144 ;
     RECT  52.945 41.04 53.057 44.376 ;
     RECT  52.805 46.032 53.057 64.104 ;
     RECT  53.017 65.088 53.075 70.008 ;
     RECT  52.441 15.6 53.077 18.648 ;
     RECT  52.765 19.92 53.077 20.952 ;
     RECT  52.985 11.664 53.093 14.232 ;
     RECT  53.077 15.6 53.125 20.952 ;
     RECT  53.093 11.664 53.129 11.736 ;
     RECT  52.049 106.992 53.129 107.544 ;
     RECT  53.125 15.504 53.197 20.952 ;
     RECT  52.981 82.56 53.201 95.736 ;
     RECT  53.017 2.496 53.269 3.144 ;
     RECT  52.517 4.176 53.269 7.512 ;
     RECT  51.797 22.224 53.269 22.248 ;
     RECT  52.441 23.616 53.269 38.76 ;
     RECT  52.553 97.248 53.269 99.72 ;
     RECT  53.057 41.04 53.273 44.328 ;
     RECT  53.201 82.56 53.309 90.648 ;
     RECT  53.269 2.496 53.315 7.512 ;
     RECT  53.269 97.248 53.377 100.44 ;
     RECT  52.661 102 53.377 102.504 ;
     RECT  53.197 15.504 53.413 21.24 ;
     RECT  53.269 22.224 53.413 38.76 ;
     RECT  53.315 2.64 53.417 7.512 ;
     RECT  53.057 46.032 53.417 61.752 ;
     RECT  53.377 97.248 53.489 102.504 ;
     RECT  51.761 75.84 53.507 80.136 ;
     RECT  53.449 10.368 53.521 10.392 ;
     RECT  53.129 11.664 53.521 11.688 ;
     RECT  53.129 106.992 53.521 107.112 ;
     RECT  53.093 12.864 53.525 14.232 ;
     RECT  53.057 62.784 53.548 64.104 ;
     RECT  53.417 46.032 53.557 46.056 ;
     RECT  53.507 76.464 53.557 80.136 ;
     RECT  53.017 81.12 53.557 81.336 ;
     RECT  53.309 82.56 53.557 88.872 ;
     RECT  53.201 91.68 53.557 95.736 ;
     RECT  52.373 9.024 53.561 9.048 ;
     RECT  53.309 90 53.603 90.648 ;
     RECT  53.603 90.192 53.633 90.648 ;
     RECT  53.521 106.944 53.741 107.112 ;
     RECT  53.489 101.712 53.809 102.504 ;
     RECT  52.769 103.536 53.809 105.96 ;
     RECT  53.741 106.944 53.813 107.016 ;
     RECT  53.075 65.088 53.845 69.96 ;
     RECT  53.557 91.68 53.845 96.024 ;
     RECT  53.489 97.248 53.845 100.248 ;
     RECT  53.417 2.832 53.849 7.512 ;
     RECT  53.845 64.704 53.849 69.96 ;
     RECT  53.845 91.68 53.849 100.248 ;
     RECT  53.417 47.136 53.885 61.752 ;
     RECT  53.809 101.712 53.893 105.96 ;
     RECT  53.413 15.504 53.921 38.76 ;
     RECT  53.921 19.872 53.948 38.76 ;
     RECT  53.917 39.888 53.948 39.912 ;
     RECT  53.849 2.832 53.957 3.384 ;
     RECT  53.849 4.368 53.957 7.512 ;
     RECT  53.548 62.784 53.957 63.144 ;
     RECT  53.957 63.12 53.993 63.144 ;
     RECT  53.849 64.704 53.993 69.864 ;
     RECT  53.948 19.872 54.001 39.912 ;
     RECT  53.921 15.504 54.101 17.256 ;
     RECT  53.893 103.536 54.133 105.96 ;
     RECT  53.813 106.944 54.133 106.968 ;
     RECT  52.589 71.28 54.173 74.472 ;
     RECT  53.957 5.232 54.209 7.512 ;
     RECT  54.001 19.872 54.209 39.864 ;
     RECT  54.173 71.856 54.229 74.472 ;
     RECT  53.525 13.104 54.236 14.232 ;
     RECT  54.101 15.504 54.236 17.208 ;
     RECT  54.236 13.104 54.281 17.208 ;
     RECT  54.209 38.208 54.281 39.864 ;
     RECT  53.273 41.04 54.281 42.84 ;
     RECT  53.557 76.464 54.317 88.872 ;
     RECT  54.281 15.168 54.323 17.208 ;
     RECT  54.281 41.568 54.349 42.84 ;
     RECT  53.273 43.92 54.349 44.328 ;
     RECT  54.229 71.856 54.353 74.568 ;
     RECT  54.317 88.656 54.421 88.872 ;
     RECT  53.633 90.192 54.425 90.552 ;
     RECT  54.317 76.464 54.461 87.576 ;
     RECT  54.281 13.104 54.493 13.752 ;
     RECT  54.461 76.464 54.529 87.096 ;
     RECT  53.993 64.704 54.601 69.624 ;
     RECT  54.421 88.656 54.605 89.112 ;
     RECT  53.849 91.68 54.605 100.056 ;
     RECT  53.893 101.712 54.637 102.504 ;
     RECT  54.209 19.872 54.641 37.08 ;
     RECT  54.641 32.496 54.749 37.08 ;
     RECT  54.425 90.192 54.749 90.456 ;
     RECT  53.885 48.528 54.785 61.752 ;
     RECT  54.605 91.68 54.785 96.552 ;
     RECT  53.521 10.368 54.821 11.688 ;
     RECT  54.323 15.504 54.821 17.208 ;
     RECT  54.641 19.872 54.821 31.512 ;
     RECT  54.601 64.608 54.857 69.624 ;
     RECT  53.957 2.832 54.965 3.096 ;
     RECT  54.529 75.504 54.995 87.096 ;
     RECT  54.601 8.592 55.033 8.616 ;
     RECT  54.637 101.28 55.037 102.504 ;
     RECT  54.605 88.848 55.105 89.112 ;
     RECT  54.749 90.192 55.105 90.36 ;
     RECT  54.349 41.568 55.109 44.328 ;
     RECT  54.785 48.528 55.141 48.552 ;
     RECT  54.785 49.824 55.141 61.752 ;
     RECT  54.605 97.776 55.141 100.056 ;
     RECT  54.209 5.568 55.217 7.512 ;
     RECT  54.821 25.776 55.217 27.144 ;
     RECT  55.033 8.592 55.249 9.144 ;
     RECT  54.857 68.16 55.249 69.624 ;
     RECT  55.037 102.48 55.249 102.504 ;
     RECT  54.133 103.536 55.249 106.968 ;
     RECT  55.217 25.776 55.253 26.952 ;
     RECT  54.995 75.504 55.253 81.144 ;
     RECT  55.253 75.504 55.283 78.264 ;
     RECT  55.249 8.592 55.289 9.816 ;
     RECT  53.557 45.936 55.321 46.056 ;
     RECT  55.141 49.824 55.321 62.568 ;
     RECT  55.283 75.504 55.321 78.216 ;
     RECT  55.217 6.624 55.325 7.512 ;
     RECT  55.253 79.248 55.325 81.144 ;
     RECT  55.249 68.16 55.357 70.296 ;
     RECT  55.325 6.72 55.393 7.512 ;
     RECT  54.821 11.664 55.393 11.688 ;
     RECT  53.885 47.136 55.393 47.16 ;
     RECT  55.141 48.432 55.393 48.552 ;
     RECT  54.353 71.856 55.393 73.848 ;
     RECT  55.321 74.88 55.393 78.216 ;
     RECT  54.749 35.904 55.429 37.08 ;
     RECT  54.281 38.256 55.429 39.864 ;
     RECT  55.357 68.16 55.429 70.584 ;
     RECT  54.493 13.056 55.501 13.752 ;
     RECT  55.429 68.16 55.501 70.776 ;
     RECT  55.393 71.856 55.501 78.216 ;
     RECT  54.857 64.608 55.537 67.08 ;
     RECT  55.109 41.568 55.573 42.84 ;
     RECT  55.109 43.872 55.609 44.328 ;
     RECT  55.321 45.552 55.609 46.056 ;
     RECT  55.393 47.136 55.609 48.552 ;
     RECT  55.537 64.176 55.645 67.08 ;
     RECT  55.321 49.824 55.753 63 ;
     RECT  55.645 64.08 55.753 67.08 ;
     RECT  53.921 18.432 55.765 18.84 ;
     RECT  54.821 19.872 55.765 24.744 ;
     RECT  55.573 41.424 55.789 42.84 ;
     RECT  55.765 18.432 55.82 24.744 ;
     RECT  55.253 25.776 55.82 26.808 ;
     RECT  54.821 16.176 55.861 17.208 ;
     RECT  55.82 18.432 55.861 26.808 ;
     RECT  54.749 32.496 55.861 34.2 ;
     RECT  55.105 88.848 55.909 90.36 ;
     RECT  55.393 11.664 55.964 11.736 ;
     RECT  55.717 4.512 55.969 4.536 ;
     RECT  55.429 35.904 55.969 37.176 ;
     RECT  55.753 49.824 56.005 67.08 ;
     RECT  54.965 3.072 56.041 3.096 ;
     RECT  55.609 43.872 56.077 48.552 ;
     RECT  56.005 49.584 56.077 67.08 ;
     RECT  56.077 43.872 56.185 67.08 ;
     RECT  55.501 68.16 56.185 78.216 ;
     RECT  55.969 4.224 56.221 4.536 ;
     RECT  55.217 5.568 56.221 5.592 ;
     RECT  54.995 82.224 56.221 87.096 ;
     RECT  56.041 2.784 56.257 3.096 ;
     RECT  56.221 4.224 56.257 5.592 ;
     RECT  55.325 79.296 56.329 81.144 ;
     RECT  56.221 82.128 56.329 87.096 ;
     RECT  55.909 88.272 56.365 90.36 ;
     RECT  55.393 6.72 56.401 8.184 ;
     RECT  56.257 2.784 56.408 5.592 ;
     RECT  56.401 6.624 56.408 8.184 ;
     RECT  55.289 9.264 56.408 9.816 ;
     RECT  55.964 10.992 56.408 11.736 ;
     RECT  55.501 13.008 56.408 13.752 ;
     RECT  55.861 16.176 56.408 26.808 ;
     RECT  54.821 28.752 56.408 31.224 ;
     RECT  55.861 32.496 56.408 34.728 ;
     RECT  55.969 35.76 56.408 37.176 ;
     RECT  55.429 38.16 56.408 39.864 ;
     RECT  55.789 40.848 56.408 42.84 ;
     RECT  56.185 43.872 56.408 78.216 ;
     RECT  56.329 79.296 56.408 87.096 ;
     RECT  56.365 88.08 56.408 90.36 ;
     RECT  54.785 91.68 56.408 96.312 ;
     RECT  55.141 97.776 56.408 100.92 ;
     RECT  55.249 102.48 56.408 107.4 ;
     RECT  56.408 2.148 56.512 108.012 ;
     RECT  56.512 2.418 56.704 107.742 ;
     RECT  56.704 85.632 56.765 107.4 ;
     RECT  56.704 4.224 56.819 9.288 ;
     RECT  56.765 85.632 56.873 107.256 ;
     RECT  56.873 85.632 56.908 99.72 ;
     RECT  56.704 14.928 56.909 15.048 ;
     RECT  56.704 40.848 56.989 42.84 ;
     RECT  56.704 16.656 57.017 20.952 ;
     RECT  57.017 17.088 57.053 20.952 ;
     RECT  56.989 40.848 57.053 42.792 ;
     RECT  56.908 88.08 57.053 99.72 ;
     RECT  56.704 22.176 57.125 39.864 ;
     RECT  56.704 43.872 57.125 46.056 ;
     RECT  56.704 77.616 57.125 78.264 ;
     RECT  56.819 4.224 57.305 9 ;
     RECT  56.704 65.184 57.305 76.584 ;
     RECT  57.125 25.776 57.341 39.864 ;
     RECT  57.053 17.136 57.413 20.952 ;
     RECT  57.305 5.664 57.449 9 ;
     RECT  56.704 2.784 57.697 3.144 ;
     RECT  57.305 4.224 57.697 4.44 ;
     RECT  57.053 88.368 57.701 99.72 ;
     RECT  57.413 18.432 57.737 20.952 ;
     RECT  56.704 47.088 57.769 64.2 ;
     RECT  57.305 65.184 57.769 69.624 ;
     RECT  57.341 25.776 57.773 34.2 ;
     RECT  56.873 100.752 57.779 107.256 ;
     RECT  57.341 35.232 57.845 39.864 ;
     RECT  56.704 10.896 57.877 13.848 ;
     RECT  56.909 15.024 57.877 15.048 ;
     RECT  57.449 7.392 57.884 9 ;
     RECT  57.845 35.664 57.949 39.864 ;
     RECT  57.053 40.848 57.949 42.504 ;
     RECT  57.769 47.088 57.953 69.624 ;
     RECT  57.884 7.392 57.971 9.768 ;
     RECT  57.125 77.904 57.98 78.264 ;
     RECT  56.704 79.296 57.98 84.6 ;
     RECT  57.953 47.088 57.989 64.008 ;
     RECT  57.779 100.752 57.989 103.176 ;
     RECT  57.773 25.776 58.061 30.456 ;
     RECT  57.701 94.08 58.061 99.72 ;
     RECT  57.98 77.904 58.093 84.6 ;
     RECT  56.908 85.632 58.093 87.096 ;
     RECT  57.971 7.392 58.097 9.624 ;
     RECT  57.305 70.608 58.124 76.584 ;
     RECT  57.125 43.92 58.165 46.056 ;
     RECT  57.989 47.088 58.165 63.912 ;
     RECT  57.125 22.176 58.205 24.744 ;
     RECT  58.124 70.608 58.211 76.68 ;
     RECT  57.737 19.776 58.241 20.952 ;
     RECT  57.989 100.752 58.241 102.504 ;
     RECT  58.061 97.536 58.273 99.72 ;
     RECT  58.205 22.176 58.349 22.344 ;
     RECT  58.241 101.424 58.349 102.504 ;
     RECT  58.211 70.608 58.355 76.584 ;
     RECT  57.449 5.664 58.417 6.024 ;
     RECT  58.241 20.016 58.417 20.952 ;
     RECT  58.349 22.176 58.417 22.248 ;
     RECT  57.773 31.776 58.493 34.2 ;
     RECT  58.093 77.904 58.525 87.096 ;
     RECT  57.701 88.368 58.525 93.096 ;
     RECT  57.877 10.896 58.561 15.048 ;
     RECT  57.413 17.136 58.645 17.256 ;
     RECT  57.737 18.432 58.645 18.552 ;
     RECT  57.697 2.784 58.669 4.44 ;
     RECT  58.417 5.664 58.669 6.36 ;
     RECT  58.561 10.8 58.669 15.048 ;
     RECT  58.645 17.136 58.669 18.552 ;
     RECT  58.669 10.8 58.709 15.24 ;
     RECT  58.669 16.704 58.721 18.552 ;
     RECT  58.273 97.536 58.745 100.248 ;
     RECT  58.709 11.664 58.781 15.24 ;
     RECT  58.525 77.904 58.889 93.096 ;
     RECT  58.097 7.44 58.925 9.624 ;
     RECT  57.953 65.184 58.933 69.624 ;
     RECT  58.165 43.92 58.979 63.912 ;
     RECT  57.949 35.664 59.029 42.504 ;
     RECT  58.889 77.904 59.029 87.912 ;
     RECT  58.933 64.992 59.036 69.624 ;
     RECT  58.355 70.608 59.036 70.776 ;
     RECT  58.979 62.976 59.065 63.912 ;
     RECT  58.061 25.776 59.101 29.304 ;
     RECT  58.061 30.288 59.101 30.456 ;
     RECT  58.781 15.216 59.137 15.24 ;
     RECT  58.721 16.656 59.137 18.552 ;
     RECT  58.349 101.712 59.137 102.504 ;
     RECT  59.137 15.216 59.141 18.552 ;
     RECT  58.417 20.016 59.177 22.248 ;
     RECT  59.141 15.6 59.213 18.552 ;
     RECT  58.889 88.896 59.221 93.096 ;
     RECT  58.061 94.08 59.221 96.36 ;
     RECT  58.669 2.784 59.249 6.36 ;
     RECT  57.779 104.4 59.269 107.256 ;
     RECT  58.979 43.92 59.285 61.992 ;
     RECT  58.925 7.92 59.317 9.624 ;
     RECT  59.137 101.712 59.317 103.224 ;
     RECT  59.269 104.256 59.317 107.256 ;
     RECT  59.177 20.064 59.321 22.248 ;
     RECT  59.101 25.776 59.321 30.456 ;
     RECT  59.036 64.992 59.357 70.776 ;
     RECT  58.355 71.856 59.357 76.584 ;
     RECT  59.221 88.896 59.389 96.36 ;
     RECT  58.745 97.536 59.389 98.424 ;
     RECT  59.065 62.976 59.393 63.96 ;
     RECT  59.389 88.896 59.393 98.424 ;
     RECT  59.321 20.112 59.413 22.248 ;
     RECT  58.205 23.328 59.413 24.744 ;
     RECT  59.357 75.984 59.42 76.584 ;
     RECT  59.029 77.616 59.42 87.912 ;
     RECT  59.357 68.352 59.497 70.776 ;
     RECT  59.357 71.856 59.497 74.904 ;
     RECT  59.321 25.776 59.573 29.304 ;
     RECT  59.213 15.6 59.609 16.872 ;
     RECT  59.42 75.984 59.609 87.912 ;
     RECT  58.745 99.504 59.641 100.248 ;
     RECT  59.317 101.712 59.641 107.256 ;
     RECT  58.493 32.208 59.713 34.2 ;
     RECT  59.393 88.944 59.713 98.424 ;
     RECT  59.029 35.664 59.761 42.792 ;
     RECT  59.609 77.616 59.825 87.912 ;
     RECT  59.497 68.352 59.861 74.904 ;
     RECT  59.713 88.944 59.891 98.472 ;
     RECT  59.285 43.92 59.893 47.16 ;
     RECT  59.393 63.552 59.893 63.96 ;
     RECT  59.357 64.992 59.893 67.272 ;
     RECT  59.761 41.952 59.929 42.792 ;
     RECT  59.893 43.824 59.929 47.16 ;
     RECT  59.891 89.328 59.929 98.472 ;
     RECT  59.641 99.504 59.929 107.256 ;
     RECT  59.317 7.92 59.933 9.816 ;
     RECT  59.713 31.536 59.965 34.2 ;
     RECT  59.761 35.664 59.965 40.968 ;
     RECT  59.249 2.784 60.005 5.736 ;
     RECT  59.573 25.776 60.005 29.208 ;
     RECT  59.965 31.536 60.005 40.968 ;
     RECT  59.825 78.048 60.005 87.912 ;
     RECT  59.933 7.968 60.041 9.816 ;
     RECT  59.213 18.144 60.073 18.552 ;
     RECT  60.005 31.536 60.073 40.92 ;
     RECT  59.929 89.328 60.073 107.256 ;
     RECT  59.413 20.112 60.109 24.744 ;
     RECT  60.005 25.776 60.109 29.16 ;
     RECT  58.781 11.664 60.113 14.232 ;
     RECT  59.321 30.384 60.185 30.456 ;
     RECT  60.073 89.328 60.185 107.736 ;
     RECT  60.185 97.104 60.257 107.736 ;
     RECT  59.929 41.952 60.293 47.16 ;
     RECT  59.861 71.808 60.323 74.904 ;
     RECT  60.113 12.768 60.325 14.232 ;
     RECT  59.609 15.6 60.325 15.72 ;
     RECT  60.005 85.104 60.329 87.912 ;
     RECT  60.185 30.432 60.361 30.456 ;
     RECT  60.073 31.488 60.361 40.92 ;
     RECT  59.893 63.552 60.361 67.272 ;
     RECT  59.861 68.352 60.361 70.68 ;
     RECT  60.361 30.432 60.401 40.92 ;
     RECT  60.323 71.904 60.401 74.904 ;
     RECT  60.329 85.344 60.437 87.912 ;
     RECT  60.257 102.336 60.437 107.736 ;
     RECT  60.437 85.344 60.581 85.752 ;
     RECT  59.609 16.704 60.649 16.872 ;
     RECT  60.073 18.144 60.649 19.08 ;
     RECT  60.113 11.664 60.685 11.784 ;
     RECT  60.325 12.768 60.721 15.72 ;
     RECT  60.649 16.704 60.721 19.08 ;
     RECT  60.257 97.104 60.761 100.92 ;
     RECT  60.041 8.496 60.793 9.816 ;
     RECT  60.685 10.896 60.793 11.784 ;
     RECT  60.005 2.784 60.797 3.336 ;
     RECT  59.609 75.984 60.829 76.584 ;
     RECT  60.361 63.552 60.865 70.68 ;
     RECT  60.829 75.984 60.865 76.632 ;
     RECT  60.005 78.048 60.865 83.784 ;
     RECT  59.285 48.144 60.901 61.992 ;
     RECT  60.437 86.832 60.973 87.912 ;
     RECT  60.185 89.328 60.973 95.736 ;
     RECT  60.401 37.104 61.009 40.92 ;
     RECT  60.293 41.952 61.009 44.52 ;
     RECT  60.865 75.984 61.009 83.784 ;
     RECT  60.721 12.768 61.045 19.08 ;
     RECT  60.109 20.112 61.045 29.16 ;
     RECT  60.865 63.552 61.045 70.92 ;
     RECT  59.929 6.864 61.261 6.888 ;
     RECT  60.793 8.496 61.261 11.784 ;
     RECT  60.293 45.744 61.261 47.16 ;
     RECT  60.901 48.144 61.261 62.04 ;
     RECT  61.261 45.744 61.297 62.04 ;
     RECT  61.045 63.216 61.297 70.92 ;
     RECT  61.009 75.984 61.436 84.312 ;
     RECT  61.297 45.744 61.513 70.92 ;
     RECT  60.401 71.904 61.513 74.616 ;
     RECT  61.261 6.864 61.621 11.784 ;
     RECT  61.045 12.768 61.621 29.16 ;
     RECT  61.009 37.104 61.621 44.52 ;
     RECT  61.513 45.744 61.621 74.616 ;
     RECT  61.436 75.792 61.621 84.312 ;
     RECT  60.581 85.392 61.621 85.752 ;
     RECT  60.973 86.832 61.621 95.736 ;
     RECT  61.621 37.104 61.628 74.616 ;
     RECT  61.628 37.104 61.657 74.712 ;
     RECT  61.621 75.792 61.729 95.736 ;
     RECT  60.797 2.88 61.808 3.336 ;
     RECT  60.005 4.944 61.808 5.736 ;
     RECT  61.621 6.864 61.808 29.16 ;
     RECT  60.401 30.432 61.808 35.736 ;
     RECT  61.657 37.056 61.808 74.712 ;
     RECT  61.729 75.696 61.808 95.736 ;
     RECT  60.761 97.104 61.808 100.344 ;
     RECT  60.437 102.336 61.808 105.624 ;
     RECT  60.437 106.848 61.808 107.736 ;
     RECT  61.808 2.148 61.912 108.012 ;
     RECT  61.912 2.418 62.104 107.742 ;
     RECT  62.104 51.696 62.165 74.712 ;
     RECT  62.104 15.456 62.273 25.128 ;
     RECT  62.104 75.696 62.273 90.072 ;
     RECT  62.104 11.76 62.339 14.472 ;
     RECT  62.104 4.176 62.345 10.632 ;
     RECT  62.339 11.76 62.345 14.232 ;
     RECT  62.104 26.736 62.387 29.112 ;
     RECT  62.273 15.456 62.417 22.584 ;
     RECT  62.165 51.696 62.489 69.624 ;
     RECT  62.417 15.456 62.525 21.816 ;
     RECT  62.273 75.744 62.531 90.072 ;
     RECT  62.489 63.264 62.597 69.624 ;
     RECT  62.165 70.608 62.705 74.712 ;
     RECT  62.531 88.896 62.705 90.072 ;
     RECT  62.705 70.656 62.723 74.712 ;
     RECT  62.387 28.464 62.741 29.112 ;
     RECT  62.531 75.744 62.741 87.672 ;
     RECT  62.273 23.664 62.777 25.128 ;
     RECT  62.104 103.488 62.849 106.728 ;
     RECT  62.777 23.664 62.921 24.12 ;
     RECT  62.597 68.976 62.993 69.624 ;
     RECT  62.849 103.488 63.029 105.48 ;
     RECT  62.849 106.464 63.029 106.728 ;
     RECT  62.104 102.48 63.097 102.504 ;
     RECT  62.705 88.896 63.101 89.784 ;
     RECT  62.387 26.736 63.116 27.48 ;
     RECT  62.345 11.76 63.137 13.704 ;
     RECT  62.777 25.104 63.157 25.128 ;
     RECT  63.029 104.304 63.209 105.48 ;
     RECT  62.104 2.496 63.245 3.144 ;
     RECT  63.097 102.096 63.253 102.504 ;
     RECT  62.104 94.368 63.281 100.104 ;
     RECT  63.253 101.424 63.299 102.504 ;
     RECT  62.345 4.176 63.313 7.944 ;
     RECT  62.345 9.072 63.313 10.632 ;
     RECT  63.209 104.4 63.317 105.48 ;
     RECT  63.245 2.592 63.349 3.144 ;
     RECT  63.313 4.176 63.349 10.632 ;
     RECT  62.597 63.264 63.353 67.896 ;
     RECT  62.104 30.432 63.385 50.712 ;
     RECT  62.489 51.696 63.385 62.28 ;
     RECT  63.299 102.48 63.385 102.504 ;
     RECT  63.281 97.488 63.389 100.104 ;
     RECT  62.921 23.664 63.421 23.928 ;
     RECT  63.157 25.104 63.457 25.368 ;
     RECT  63.116 26.448 63.457 27.48 ;
     RECT  63.349 2.592 63.461 10.632 ;
     RECT  62.104 91.584 63.493 93.24 ;
     RECT  63.281 94.368 63.493 96.504 ;
     RECT  63.353 63.264 63.497 67.704 ;
     RECT  62.741 86.832 63.601 87.672 ;
     RECT  63.457 25.104 63.637 27.48 ;
     RECT  62.741 28.464 63.637 29.016 ;
     RECT  62.525 15.456 63.673 18.456 ;
     RECT  63.385 30.432 63.677 62.28 ;
     RECT  63.493 91.584 63.677 96.504 ;
     RECT  63.677 30.432 63.745 37.08 ;
     RECT  63.101 89.472 63.745 89.784 ;
     RECT  63.461 10.464 63.781 10.632 ;
     RECT  63.299 101.424 63.785 101.448 ;
     RECT  62.993 69.12 63.817 69.624 ;
     RECT  62.723 70.656 63.817 74.616 ;
     RECT  63.677 91.584 63.817 95.592 ;
     RECT  63.421 23.568 63.889 23.928 ;
     RECT  63.817 91.104 63.893 95.592 ;
     RECT  63.677 38.448 63.929 62.28 ;
     RECT  63.893 91.104 63.929 95.496 ;
     RECT  63.889 22.848 63.932 23.928 ;
     RECT  62.525 19.68 63.961 21.816 ;
     RECT  63.932 22.848 63.961 24.12 ;
     RECT  63.817 69.12 63.973 74.616 ;
     RECT  63.137 13.008 63.997 13.704 ;
     RECT  63.673 14.736 63.997 18.456 ;
     RECT  63.961 19.68 63.997 24.12 ;
     RECT  63.637 25.104 63.997 29.016 ;
     RECT  63.973 68.976 64.06 74.616 ;
     RECT  63.929 44.208 64.069 62.28 ;
     RECT  63.497 63.264 64.069 67.416 ;
     RECT  64.06 69.312 64.069 74.616 ;
     RECT  62.741 75.744 64.069 85.752 ;
     RECT  63.601 86.832 64.069 88.488 ;
     RECT  64.069 69.312 64.073 88.488 ;
     RECT  63.781 10.464 64.105 10.68 ;
     RECT  63.137 11.76 64.105 12.024 ;
     RECT  64.105 10.464 64.177 12.024 ;
     RECT  63.997 13.008 64.177 18.456 ;
     RECT  63.317 104.4 64.213 105.24 ;
     RECT  64.177 10.464 64.217 18.456 ;
     RECT  64.073 72.24 64.249 88.488 ;
     RECT  63.745 89.472 64.249 90.024 ;
     RECT  63.461 2.592 64.253 9.288 ;
     RECT  64.073 69.312 64.253 71.16 ;
     RECT  64.217 15.84 64.285 18.456 ;
     RECT  63.997 19.68 64.285 29.016 ;
     RECT  64.253 70.608 64.325 71.16 ;
     RECT  64.249 72.24 64.385 90.024 ;
     RECT  63.929 91.104 64.385 95.16 ;
     RECT  64.285 15.84 64.393 29.016 ;
     RECT  64.285 108.288 64.393 108.312 ;
     RECT  64.385 72.24 64.397 95.16 ;
     RECT  63.389 97.584 64.465 100.056 ;
     RECT  63.929 38.448 64.469 43.176 ;
     RECT  64.397 72.624 64.469 95.16 ;
     RECT  64.393 108.24 64.498 108.312 ;
     RECT  64.469 91.248 64.505 95.16 ;
     RECT  64.325 70.608 64.577 70.872 ;
     RECT  64.505 91.68 64.613 95.16 ;
     RECT  64.469 72.624 64.649 80.136 ;
     RECT  64.069 44.208 64.681 67.416 ;
     RECT  64.613 91.68 64.685 93.384 ;
     RECT  64.429 109.536 64.7 109.56 ;
     RECT  63.745 30.192 64.717 37.08 ;
     RECT  64.717 30.192 64.721 37.224 ;
     RECT  64.498 108.192 64.721 108.312 ;
     RECT  64.681 44.208 64.757 67.56 ;
     RECT  64.649 77.376 64.757 80.136 ;
     RECT  64.7 109.44 64.787 109.56 ;
     RECT  63.029 106.704 64.825 106.728 ;
     RECT  64.253 2.784 64.829 9.288 ;
     RECT  64.787 109.488 64.883 109.56 ;
     RECT  64.825 106.704 64.892 107.544 ;
     RECT  64.757 44.208 64.897 44.424 ;
     RECT  64.217 10.464 64.901 14.808 ;
     RECT  64.721 35.424 64.933 37.224 ;
     RECT  64.469 38.448 64.933 42.744 ;
     RECT  64.465 96.912 64.933 100.056 ;
     RECT  64.613 94.368 64.969 95.16 ;
     RECT  63.385 102.48 64.969 103.08 ;
     RECT  64.213 104.304 64.969 105.24 ;
     RECT  64.892 106.32 64.979 107.544 ;
     RECT  64.883 109.536 64.979 109.56 ;
     RECT  64.933 96.912 65.009 100.104 ;
     RECT  65.009 97.104 65.039 100.104 ;
     RECT  64.393 15.84 65.045 29.112 ;
     RECT  64.469 81.12 65.045 89.976 ;
     RECT  64.577 70.608 65.081 70.728 ;
     RECT  65.045 22.992 65.153 29.112 ;
     RECT  64.649 72.72 65.153 76.344 ;
     RECT  65.153 72.72 65.189 74.184 ;
     RECT  65.153 23.376 65.225 29.112 ;
     RECT  64.901 13.968 65.297 14.808 ;
     RECT  64.757 45.456 65.305 67.56 ;
     RECT  65.045 81.12 65.333 86.04 ;
     RECT  65.225 25.344 65.365 29.112 ;
     RECT  64.721 30.192 65.365 32.232 ;
     RECT  64.933 35.424 65.405 42.744 ;
     RECT  64.829 2.784 65.441 8.76 ;
     RECT  64.969 102.48 65.509 105.24 ;
     RECT  64.897 43.92 65.545 44.424 ;
     RECT  65.545 43.776 65.549 44.424 ;
     RECT  65.039 97.104 65.557 101.064 ;
     RECT  65.509 102.48 65.557 105.48 ;
     RECT  65.153 75.168 65.585 76.344 ;
     RECT  65.557 97.104 65.603 105.48 ;
     RECT  64.901 10.464 65.621 12.744 ;
     RECT  65.297 14.736 65.621 14.808 ;
     RECT  64.685 91.68 65.621 93.336 ;
     RECT  65.549 43.776 65.653 44.376 ;
     RECT  65.045 87.072 65.657 89.976 ;
     RECT  65.621 10.464 65.689 11.688 ;
     RECT  65.621 14.784 65.689 14.808 ;
     RECT  65.045 15.84 65.689 22.008 ;
     RECT  64.721 33.216 65.689 34.2 ;
     RECT  65.405 35.424 65.689 42.168 ;
     RECT  64.969 94.368 65.689 95.592 ;
     RECT  65.365 25.344 65.725 32.232 ;
     RECT  65.689 33.216 65.725 42.168 ;
     RECT  65.653 43.296 65.74 44.376 ;
     RECT  65.725 25.344 65.747 42.168 ;
     RECT  64.757 77.712 65.833 80.136 ;
     RECT  65.333 81.12 65.833 85.8 ;
     RECT  65.689 14.784 65.837 22.008 ;
     RECT  65.747 25.344 65.837 36.072 ;
     RECT  65.657 89.952 65.837 89.976 ;
     RECT  65.603 103.68 65.837 105.48 ;
     RECT  65.621 12.72 65.843 12.744 ;
     RECT  65.797 67.92 65.869 68.232 ;
     RECT  64.253 69.312 65.869 69.624 ;
     RECT  65.689 94.368 65.909 95.976 ;
     RECT  65.621 91.68 65.977 93.096 ;
     RECT  65.441 4.752 66.013 8.76 ;
     RECT  64.979 107.52 66.157 107.544 ;
     RECT  66.013 4.752 66.161 9.096 ;
     RECT  65.603 97.104 66.161 102.552 ;
     RECT  65.837 14.832 66.179 22.008 ;
     RECT  66.157 107.28 66.193 107.544 ;
     RECT  65.081 70.656 66.229 70.728 ;
     RECT  65.869 67.92 66.265 69.624 ;
     RECT  66.229 70.656 66.265 71.208 ;
     RECT  65.977 91.632 66.265 93.096 ;
     RECT  66.301 72.432 66.332 72.456 ;
     RECT  65.189 73.584 66.332 74.184 ;
     RECT  65.585 75.216 66.337 76.344 ;
     RECT  66.337 75.216 66.373 76.728 ;
     RECT  65.833 77.712 66.373 85.8 ;
     RECT  65.837 103.728 66.373 105.48 ;
     RECT  66.193 106.512 66.373 107.544 ;
     RECT  66.332 72.432 66.445 74.184 ;
     RECT  66.373 75.216 66.445 85.8 ;
     RECT  65.305 45.456 66.481 66.936 ;
     RECT  66.265 67.92 66.481 71.208 ;
     RECT  65.441 2.784 66.565 3.384 ;
     RECT  65.837 25.344 66.589 29.832 ;
     RECT  66.179 16.272 66.623 22.008 ;
     RECT  65.225 23.376 66.623 24.12 ;
     RECT  66.265 91.008 66.625 93.096 ;
     RECT  65.689 10.08 66.661 11.688 ;
     RECT  66.445 75.216 66.661 85.944 ;
     RECT  65.657 87.072 66.661 88.968 ;
     RECT  66.161 97.104 66.661 100.104 ;
     RECT  66.373 103.728 66.709 107.544 ;
     RECT  66.565 2.784 66.769 3.432 ;
     RECT  66.661 87.072 66.805 89.016 ;
     RECT  66.625 90.24 66.805 93.096 ;
     RECT  66.769 2.784 66.841 3.624 ;
     RECT  66.161 4.752 66.841 5.208 ;
     RECT  66.161 6.24 66.913 9.096 ;
     RECT  66.661 10.08 66.913 12.6 ;
     RECT  66.179 14.832 67.057 14.856 ;
     RECT  67.057 13.92 67.093 14.856 ;
     RECT  65.74 43.776 67.093 44.376 ;
     RECT  66.481 45.456 67.093 71.208 ;
     RECT  66.805 87.072 67.093 93.096 ;
     RECT  67.093 43.776 67.129 71.208 ;
     RECT  66.161 101.856 67.165 102.552 ;
     RECT  66.709 103.728 67.165 107.784 ;
     RECT  66.841 2.784 67.208 5.208 ;
     RECT  66.913 6.24 67.208 12.6 ;
     RECT  67.093 13.584 67.208 14.856 ;
     RECT  66.623 16.272 67.208 24.12 ;
     RECT  66.589 25.248 67.208 29.832 ;
     RECT  65.837 30.912 67.208 36.072 ;
     RECT  65.747 37.104 67.208 42.168 ;
     RECT  67.129 43.296 67.208 71.208 ;
     RECT  66.445 72.192 67.208 74.184 ;
     RECT  66.661 75.168 67.208 85.944 ;
     RECT  67.093 87.072 67.208 93.336 ;
     RECT  65.909 94.368 67.208 95.928 ;
     RECT  66.661 97.056 67.208 100.104 ;
     RECT  67.165 101.856 67.208 107.784 ;
     RECT  67.208 2.148 67.312 108.012 ;
     RECT  67.312 2.418 67.504 107.742 ;
     RECT  67.504 30.912 67.601 36.552 ;
     RECT  67.504 23.616 67.709 29.256 ;
     RECT  67.504 7.392 67.745 18.744 ;
     RECT  67.504 102.48 67.745 107.112 ;
     RECT  67.504 2.784 67.853 6.408 ;
     RECT  67.504 19.776 67.853 22.488 ;
     RECT  67.504 75.216 67.853 87.672 ;
     RECT  67.601 31.008 68.003 36.552 ;
     RECT  67.504 37.68 68.033 41.928 ;
     RECT  67.853 78.096 68.105 87.672 ;
     RECT  67.504 44.352 68.141 74.088 ;
     RECT  67.745 12.768 68.177 18.744 ;
     RECT  68.177 12.768 68.185 14.568 ;
     RECT  67.504 43.296 68.285 43.32 ;
     RECT  68.141 44.352 68.38 50.664 ;
     RECT  67.745 7.392 68.393 11.784 ;
     RECT  68.177 15.6 68.429 18.744 ;
     RECT  67.504 89.328 68.465 93.336 ;
     RECT  67.745 102.48 68.497 105.528 ;
     RECT  67.745 106.704 68.533 107.112 ;
     RECT  68.141 51.648 68.569 74.088 ;
     RECT  68.465 89.424 68.629 93.336 ;
     RECT  67.504 94.32 68.629 100.776 ;
     RECT  67.853 2.784 68.677 3.384 ;
     RECT  68.38 44.352 68.677 48.792 ;
     RECT  68.003 31.2 68.713 36.552 ;
     RECT  68.569 51.648 68.723 74.232 ;
     RECT  67.709 26.304 68.749 29.256 ;
     RECT  68.749 26.304 68.785 29.4 ;
     RECT  68.723 51.648 68.825 72.936 ;
     RECT  68.723 74.064 68.857 74.232 ;
     RECT  67.853 75.216 68.857 77.112 ;
     RECT  68.713 31.2 68.897 36.6 ;
     RECT  68.629 89.424 68.965 100.776 ;
     RECT  68.497 102.24 68.965 105.528 ;
     RECT  68.533 106.704 68.965 107.16 ;
     RECT  67.853 19.776 68.969 22.008 ;
     RECT  68.897 31.2 69.005 36.312 ;
     RECT  68.677 43.968 69.005 48.792 ;
     RECT  68.429 15.696 69.077 18.744 ;
     RECT  68.965 89.424 69.077 105.528 ;
     RECT  67.709 23.616 69.109 25.272 ;
     RECT  68.785 26.256 69.109 29.4 ;
     RECT  68.033 37.68 69.217 41.64 ;
     RECT  67.853 4.416 69.221 6.408 ;
     RECT  68.185 12.768 69.221 13.944 ;
     RECT  69.077 16.656 69.251 18.744 ;
     RECT  68.825 62.976 69.257 72.936 ;
     RECT  68.713 42.96 69.289 42.984 ;
     RECT  68.965 106.704 69.293 107.784 ;
     RECT  69.005 44.352 69.361 48.792 ;
     RECT  68.38 49.824 69.361 50.664 ;
     RECT  68.969 20.928 69.397 22.008 ;
     RECT  69.221 4.416 69.433 5.832 ;
     RECT  69.077 101.712 69.505 105.528 ;
     RECT  69.293 106.704 69.505 107.16 ;
     RECT  68.105 78.096 69.541 87.48 ;
     RECT  68.393 7.44 69.545 11.784 ;
     RECT  69.545 7.68 69.581 11.784 ;
     RECT  69.077 89.424 69.587 100.728 ;
     RECT  69.109 23.616 69.617 29.4 ;
     RECT  68.857 74.064 69.637 77.112 ;
     RECT  69.541 78.096 69.637 88.344 ;
     RECT  69.005 31.632 69.653 36.312 ;
     RECT  69.637 74.064 69.653 88.344 ;
     RECT  68.677 2.64 69.685 3.384 ;
     RECT  69.433 4.368 69.685 5.832 ;
     RECT  69.581 8.592 69.797 11.784 ;
     RECT  69.685 2.64 69.833 5.832 ;
     RECT  69.653 74.112 69.833 88.344 ;
     RECT  69.797 11.28 69.865 11.784 ;
     RECT  69.221 12.768 69.865 13.224 ;
     RECT  69.361 44.352 69.865 50.664 ;
     RECT  68.825 51.648 69.865 61.752 ;
     RECT  69.833 77.952 69.868 88.344 ;
     RECT  69.617 27.792 69.937 29.4 ;
     RECT  69.937 27.792 69.973 29.784 ;
     RECT  69.865 44.352 69.977 61.752 ;
     RECT  69.587 89.616 69.977 100.728 ;
     RECT  69.973 27.792 70.06 30.6 ;
     RECT  69.397 20.928 70.081 22.296 ;
     RECT  69.617 23.616 70.081 26.808 ;
     RECT  69.251 16.656 70.117 16.92 ;
     RECT  69.865 11.28 70.121 13.224 ;
     RECT  69.653 31.632 70.121 33.096 ;
     RECT  69.868 78.192 70.121 88.344 ;
     RECT  69.977 44.448 70.153 61.752 ;
     RECT  69.257 62.976 70.153 72.84 ;
     RECT  70.081 20.928 70.211 26.808 ;
     RECT  69.397 14.784 70.261 14.808 ;
     RECT  70.121 31.728 70.337 33.096 ;
     RECT  69.505 101.712 70.337 107.16 ;
     RECT  69.251 18.384 70.357 18.744 ;
     RECT  68.969 19.776 70.357 19.896 ;
     RECT  70.337 101.712 70.373 103.656 ;
     RECT  70.117 16.512 70.405 16.92 ;
     RECT  70.357 18.384 70.405 19.896 ;
     RECT  69.833 2.64 70.547 5.4 ;
     RECT  70.261 14.784 70.553 15.048 ;
     RECT  70.405 16.512 70.585 19.896 ;
     RECT  70.211 20.928 70.585 26.76 ;
     RECT  70.121 11.424 70.621 13.224 ;
     RECT  69.217 37.584 70.621 41.64 ;
     RECT  69.653 34.128 70.657 36.312 ;
     RECT  70.621 37.392 70.657 41.64 ;
     RECT  69.977 89.616 70.657 96.216 ;
     RECT  70.337 104.64 70.661 107.16 ;
     RECT  69.289 42.96 70.693 43.128 ;
     RECT  70.153 44.448 70.693 72.84 ;
     RECT  69.833 74.112 70.693 76.872 ;
     RECT  70.657 34.128 70.733 41.64 ;
     RECT  70.693 42.96 70.733 43.32 ;
     RECT  70.693 44.448 70.733 76.872 ;
     RECT  70.373 101.712 70.733 103.56 ;
     RECT  70.657 89.376 70.801 96.216 ;
     RECT  70.06 27.792 70.805 30.168 ;
     RECT  70.121 78.192 70.805 87.672 ;
     RECT  70.805 27.792 70.913 29.784 ;
     RECT  70.733 103.536 70.913 103.56 ;
     RECT  69.977 97.584 70.945 100.728 ;
     RECT  70.733 101.712 70.945 102.408 ;
     RECT  70.585 16.512 70.949 26.76 ;
     RECT  70.913 28.272 70.949 29.784 ;
     RECT  70.805 85.632 71.027 87.672 ;
     RECT  69.797 8.592 71.089 10.056 ;
     RECT  70.621 11.424 71.089 13.608 ;
     RECT  70.733 72.576 71.089 76.872 ;
     RECT  70.805 78.192 71.089 84.6 ;
     RECT  71.089 8.592 71.129 13.608 ;
     RECT  70.949 16.512 71.161 25.464 ;
     RECT  71.027 86.064 71.161 87.672 ;
     RECT  70.801 89.184 71.201 96.216 ;
     RECT  71.161 5.808 71.233 6.408 ;
     RECT  71.161 15.984 71.237 25.464 ;
     RECT  71.089 72.576 71.267 84.6 ;
     RECT  70.661 107.088 71.269 107.16 ;
     RECT  71.129 8.592 71.305 13.224 ;
     RECT  70.337 31.728 71.305 33.048 ;
     RECT  71.237 15.984 71.309 22.008 ;
     RECT  70.553 14.784 71.341 14.952 ;
     RECT  71.305 7.872 71.417 13.224 ;
     RECT  71.417 8.976 71.489 13.224 ;
     RECT  71.237 23.232 71.489 25.464 ;
     RECT  71.489 9.072 71.561 13.224 ;
     RECT  71.267 73.2 71.597 79.704 ;
     RECT  70.547 2.64 71.629 4.536 ;
     RECT  70.949 26.496 71.629 26.76 ;
     RECT  70.733 44.448 71.737 71.208 ;
     RECT  71.737 44.448 71.773 71.4 ;
     RECT  70.733 35.184 71.845 41.64 ;
     RECT  70.733 43.104 71.852 43.32 ;
     RECT  71.773 44.448 71.852 72.216 ;
     RECT  70.945 97.584 71.881 102.408 ;
     RECT  70.661 104.64 71.917 106.008 ;
     RECT  71.305 30.816 71.953 33.048 ;
     RECT  71.953 30.816 72.025 33.816 ;
     RECT  70.949 28.272 72.097 29.112 ;
     RECT  71.161 86.064 72.097 87.96 ;
     RECT  71.629 26.496 72.169 27.096 ;
     RECT  72.025 30.816 72.169 34.152 ;
     RECT  71.845 35.184 72.169 41.784 ;
     RECT  71.233 5.808 72.205 6.648 ;
     RECT  72.169 26.496 72.229 27.144 ;
     RECT  72.097 28.272 72.229 29.64 ;
     RECT  71.417 7.872 72.241 7.992 ;
     RECT  72.241 7.68 72.313 7.992 ;
     RECT  71.881 97.296 72.313 102.408 ;
     RECT  71.309 20.928 72.325 22.008 ;
     RECT  72.229 26.496 72.341 29.64 ;
     RECT  72.169 30.816 72.341 41.784 ;
     RECT  72.097 85.776 72.373 87.96 ;
     RECT  71.201 89.184 72.373 89.64 ;
     RECT  71.201 90.624 72.373 96.216 ;
     RECT  72.373 85.776 72.385 96.216 ;
     RECT  71.267 80.832 72.421 84.6 ;
     RECT  71.852 43.104 72.457 72.216 ;
     RECT  71.597 73.2 72.457 79.32 ;
     RECT  72.385 85.728 72.469 96.216 ;
     RECT  72.313 97.296 72.469 102.504 ;
     RECT  71.269 107.088 72.493 107.4 ;
     RECT  71.629 2.496 72.608 4.536 ;
     RECT  72.205 5.568 72.608 6.648 ;
     RECT  72.313 7.632 72.608 7.992 ;
     RECT  71.561 9.12 72.608 13.224 ;
     RECT  71.341 14.208 72.608 14.952 ;
     RECT  71.309 15.984 72.608 19.896 ;
     RECT  72.325 20.928 72.608 22.152 ;
     RECT  71.489 23.232 72.608 25.272 ;
     RECT  72.341 26.496 72.608 41.784 ;
     RECT  72.457 43.104 72.608 79.32 ;
     RECT  72.421 80.304 72.608 84.6 ;
     RECT  72.469 85.728 72.608 102.504 ;
     RECT  71.917 103.968 72.608 106.008 ;
     RECT  72.493 107.088 72.608 107.592 ;
     RECT  72.608 2.148 72.712 108.012 ;
     RECT  72.712 2.418 72.904 107.742 ;
     RECT  72.904 43.824 72.965 50.088 ;
     RECT  72.904 51.216 72.965 66.84 ;
     RECT  72.904 15.312 73.001 27.192 ;
     RECT  72.904 28.272 73.001 29.016 ;
     RECT  73.001 15.312 73.073 16.008 ;
     RECT  72.965 45.024 73.109 50.088 ;
     RECT  72.904 86.928 73.145 95.256 ;
     RECT  72.904 2.496 73.217 9.384 ;
     RECT  73.109 47.136 73.325 50.088 ;
     RECT  72.904 72.432 73.325 76.968 ;
     RECT  73.325 72.432 73.361 76.776 ;
     RECT  72.904 70.8 73.397 71.4 ;
     RECT  73.361 72.816 73.397 76.776 ;
     RECT  73.001 28.464 73.433 29.016 ;
     RECT  73.145 91.44 73.433 95.256 ;
     RECT  72.904 31.104 73.571 42.36 ;
     RECT  73.001 17.04 73.577 27.192 ;
     RECT  72.904 10.368 73.613 14.28 ;
     RECT  72.904 96.432 73.667 100.632 ;
     RECT  73.109 45.024 73.685 46.104 ;
     RECT  73.613 10.704 73.721 14.28 ;
     RECT  73.721 13.008 73.756 14.28 ;
     RECT  73.073 15.312 73.793 15.912 ;
     RECT  72.904 101.712 73.811 106.296 ;
     RECT  73.433 28.992 73.897 29.016 ;
     RECT  73.577 20.208 73.937 27.192 ;
     RECT  72.904 67.92 73.937 69.768 ;
     RECT  72.965 51.216 73.969 64.824 ;
     RECT  72.965 66 73.969 66.84 ;
     RECT  73.897 28.992 74.005 29.304 ;
     RECT  73.811 101.712 74.005 105.24 ;
     RECT  73.937 24.624 74.077 27.192 ;
     RECT  72.904 107.568 74.077 107.688 ;
     RECT  73.217 2.496 74.149 3.768 ;
     RECT  73.571 31.104 74.149 35.496 ;
     RECT  73.217 5.184 74.153 9.384 ;
     RECT  73.969 51.216 74.153 66.84 ;
     RECT  73.667 98.304 74.153 100.632 ;
     RECT  73.685 45.264 74.189 46.104 ;
     RECT  74.153 62.784 74.189 66.84 ;
     RECT  73.397 72.912 74.189 76.776 ;
     RECT  74.153 98.688 74.189 100.632 ;
     RECT  74.189 99.168 74.257 100.632 ;
     RECT  74.005 101.616 74.257 105.24 ;
     RECT  74.189 62.784 74.261 63.288 ;
     RECT  74.261 62.784 74.333 63.096 ;
     RECT  73.145 86.928 74.333 90.408 ;
     RECT  73.325 47.664 74.365 50.088 ;
     RECT  74.153 51.216 74.365 61.752 ;
     RECT  74.153 5.184 74.369 7.944 ;
     RECT  74.149 30.816 74.369 35.496 ;
     RECT  74.369 30.816 74.396 34.776 ;
     RECT  73.571 36.816 74.401 42.36 ;
     RECT  74.149 2.256 74.437 3.768 ;
     RECT  74.437 2.256 74.483 4.152 ;
     RECT  74.369 5.472 74.585 7.944 ;
     RECT  74.333 88.896 74.585 90.408 ;
     RECT  73.756 13.632 74.617 14.28 ;
     RECT  73.793 15.312 74.617 15.528 ;
     RECT  74.401 36.816 74.617 42.552 ;
     RECT  73.433 91.44 74.621 94.968 ;
     RECT  73.721 10.704 74.653 11.976 ;
     RECT  73.811 106.272 74.653 106.296 ;
     RECT  74.077 107.28 74.653 107.688 ;
     RECT  74.585 5.52 74.657 7.944 ;
     RECT  74.585 88.896 74.675 90.36 ;
     RECT  73.577 17.04 74.689 18.984 ;
     RECT  74.077 24.624 74.693 28.008 ;
     RECT  74.257 99.168 74.693 105.24 ;
     RECT  74.693 25.248 74.729 28.008 ;
     RECT  74.189 45.264 74.729 45.288 ;
     RECT  74.333 86.928 74.729 87.912 ;
     RECT  72.904 78.048 74.761 85.8 ;
     RECT  74.729 86.928 74.761 87.672 ;
     RECT  74.396 30.768 74.765 34.776 ;
     RECT  74.761 78.048 74.765 87.672 ;
     RECT  74.765 78.048 74.801 85.512 ;
     RECT  74.693 101.616 74.801 105.24 ;
     RECT  74.189 73.488 74.819 76.776 ;
     RECT  74.689 16.896 74.833 18.984 ;
     RECT  74.653 106.272 74.833 107.688 ;
     RECT  73.937 20.208 74.837 23.64 ;
     RECT  73.937 68.112 74.837 69.768 ;
     RECT  74.765 30.768 74.909 34.44 ;
     RECT  74.005 28.992 74.941 29.352 ;
     RECT  74.909 30.768 74.941 32.664 ;
     RECT  73.667 96.432 74.941 97.32 ;
     RECT  74.765 86.592 74.963 87.672 ;
     RECT  74.617 13.632 74.977 15.528 ;
     RECT  74.833 16.896 74.977 19.224 ;
     RECT  74.801 104.352 74.977 105.24 ;
     RECT  74.833 106.224 74.977 107.688 ;
     RECT  74.617 36.432 74.981 42.552 ;
     RECT  74.819 73.488 75.017 75 ;
     RECT  74.977 13.632 75.068 19.224 ;
     RECT  74.653 10.608 75.109 11.976 ;
     RECT  75.068 13.296 75.109 19.224 ;
     RECT  74.729 25.248 75.125 27.336 ;
     RECT  74.153 9.12 75.157 9.384 ;
     RECT  75.109 10.608 75.157 19.224 ;
     RECT  74.621 91.584 75.157 94.968 ;
     RECT  74.837 69.312 75.185 69.768 ;
     RECT  73.397 70.8 75.185 71.352 ;
     RECT  74.365 47.664 75.193 61.752 ;
     RECT  74.819 76.08 75.193 76.776 ;
     RECT  74.801 78.048 75.193 84.648 ;
     RECT  75.185 69.312 75.205 71.352 ;
     RECT  75.157 72.384 75.205 72.408 ;
     RECT  74.977 104.352 75.205 107.688 ;
     RECT  74.657 5.664 75.229 7.944 ;
     RECT  75.157 9.12 75.229 19.224 ;
     RECT  72.965 43.824 75.229 43.848 ;
     RECT  74.189 64.272 75.229 66.84 ;
     RECT  74.837 68.112 75.229 68.136 ;
     RECT  75.193 76.08 75.233 84.648 ;
     RECT  75.193 47.424 75.265 61.752 ;
     RECT  74.801 101.712 75.269 103.08 ;
     RECT  75.229 64.272 75.301 68.136 ;
     RECT  74.483 2.88 75.341 4.152 ;
     RECT  75.205 104.352 75.341 107.784 ;
     RECT  74.941 28.992 75.445 29.64 ;
     RECT  74.941 30.624 75.445 32.664 ;
     RECT  75.205 69.312 75.445 72.408 ;
     RECT  75.017 73.488 75.445 74.712 ;
     RECT  75.229 5.664 75.449 19.224 ;
     RECT  74.693 99.168 75.452 100.632 ;
     RECT  75.157 91.584 75.481 95.256 ;
     RECT  74.941 96.432 75.481 97.416 ;
     RECT  75.449 9.12 75.485 19.224 ;
     RECT  75.452 98.496 75.539 100.632 ;
     RECT  74.837 20.688 75.557 23.64 ;
     RECT  74.981 36.912 75.557 42.552 ;
     RECT  74.333 62.784 75.589 62.808 ;
     RECT  75.445 28.992 75.629 32.664 ;
     RECT  75.233 76.608 75.629 84.648 ;
     RECT  75.341 104.352 75.629 107.064 ;
     RECT  75.629 28.992 75.661 32.616 ;
     RECT  75.539 98.64 75.665 100.632 ;
     RECT  74.909 34.032 75.701 34.44 ;
     RECT  75.661 28.752 75.769 32.616 ;
     RECT  75.229 43.824 75.769 44.472 ;
     RECT  75.265 47.328 75.769 61.752 ;
     RECT  75.589 62.784 75.769 62.904 ;
     RECT  74.963 87.072 75.769 87.672 ;
     RECT  74.675 88.944 75.769 90.36 ;
     RECT  75.481 91.584 75.769 97.416 ;
     RECT  75.341 3.456 75.773 4.152 ;
     RECT  75.125 25.68 75.829 27.336 ;
     RECT  75.769 28.464 75.829 32.616 ;
     RECT  75.481 45.552 75.841 45.672 ;
     RECT  75.769 47.328 75.841 62.904 ;
     RECT  75.301 63.984 75.841 68.136 ;
     RECT  75.445 69.312 75.841 74.712 ;
     RECT  75.485 9.12 75.845 12.84 ;
     RECT  75.769 43.344 75.877 44.472 ;
     RECT  75.841 45.552 75.877 46.008 ;
     RECT  75.829 25.68 75.881 32.616 ;
     RECT  75.769 91.584 75.881 97.608 ;
     RECT  75.269 102.48 75.913 103.08 ;
     RECT  75.557 20.688 75.917 23.208 ;
     RECT  75.881 30.768 75.964 32.616 ;
     RECT  75.769 87.072 75.989 90.36 ;
     RECT  75.485 14.112 76.021 19.224 ;
     RECT  75.917 20.688 76.021 22.584 ;
     RECT  75.877 43.344 76.021 46.008 ;
     RECT  75.841 47.328 76.021 74.712 ;
     RECT  75.989 87.072 76.021 88.872 ;
     RECT  76.021 43.344 76.093 74.712 ;
     RECT  75.629 104.544 76.097 107.064 ;
     RECT  76.021 14.112 76.105 22.584 ;
     RECT  75.773 4.128 76.241 4.152 ;
     RECT  76.093 43.344 76.313 75.24 ;
     RECT  76.021 86.88 76.349 88.872 ;
     RECT  75.913 102.48 76.385 103.512 ;
     RECT  76.105 20.688 76.421 22.584 ;
     RECT  75.881 25.68 76.421 29.64 ;
     RECT  75.629 76.608 76.421 78.648 ;
     RECT  75.881 91.776 76.457 97.608 ;
     RECT  75.557 36.912 76.525 42.36 ;
     RECT  76.313 43.344 76.525 72.216 ;
     RECT  76.313 73.488 76.525 75.24 ;
     RECT  76.097 104.544 76.565 106.008 ;
     RECT  75.845 12.528 76.633 12.84 ;
     RECT  76.105 14.112 76.633 19.224 ;
     RECT  76.525 36.912 76.637 72.216 ;
     RECT  75.629 79.776 76.669 84.648 ;
     RECT  75.964 31.296 76.745 32.616 ;
     RECT  76.669 79.728 76.777 84.648 ;
     RECT  76.457 92.352 76.813 97.608 ;
     RECT  75.665 98.64 76.813 100.008 ;
     RECT  76.777 79.728 76.861 85.032 ;
     RECT  75.769 34.704 76.885 35.256 ;
     RECT  76.633 12.528 76.889 19.224 ;
     RECT  75.989 90.048 76.921 90.36 ;
     RECT  75.845 9.12 76.925 11.112 ;
     RECT  76.421 25.968 76.925 29.64 ;
     RECT  76.925 11.088 76.961 11.112 ;
     RECT  76.861 79.728 76.961 80.04 ;
     RECT  76.385 103.488 76.961 103.512 ;
     RECT  76.885 34.416 76.993 35.256 ;
     RECT  76.889 12.528 76.997 16.92 ;
     RECT  76.889 18.048 77.033 19.224 ;
     RECT  76.421 20.736 77.033 22.584 ;
     RECT  76.925 9.12 77.101 10.056 ;
     RECT  75.449 5.664 77.173 7.704 ;
     RECT  77.101 9.024 77.173 10.056 ;
     RECT  76.861 81.12 77.173 85.032 ;
     RECT  76.349 86.88 77.173 88.776 ;
     RECT  76.565 104.832 77.173 106.008 ;
     RECT  76.097 107.04 77.173 107.064 ;
     RECT  76.993 34.416 77.209 35.4 ;
     RECT  76.813 92.352 77.245 100.008 ;
     RECT  75.805 100.992 77.245 101.352 ;
     RECT  77.209 34.416 77.281 35.736 ;
     RECT  77.173 5.04 77.317 7.704 ;
     RECT  77.173 8.784 77.317 10.056 ;
     RECT  77.281 34.416 77.317 35.832 ;
     RECT  76.637 36.912 77.317 43.32 ;
     RECT  76.385 102.48 77.317 102.504 ;
     RECT  76.637 44.448 77.353 72.216 ;
     RECT  76.525 73.488 77.353 76.056 ;
     RECT  76.597 2.496 77.461 2.52 ;
     RECT  77.033 20.736 77.461 22.104 ;
     RECT  77.173 81.12 77.461 88.776 ;
     RECT  76.921 90.048 77.461 90.648 ;
     RECT  77.245 92.352 77.461 101.352 ;
     RECT  77.317 102.384 77.461 102.504 ;
     RECT  77.173 104.832 77.461 107.064 ;
     RECT  77.461 20.496 77.509 22.104 ;
     RECT  77.461 81.12 77.533 90.648 ;
     RECT  77.353 44.448 77.569 76.056 ;
     RECT  76.421 77.424 77.569 78.648 ;
     RECT  77.533 81.12 77.605 90.84 ;
     RECT  77.461 92.352 77.677 102.504 ;
     RECT  77.317 34.416 77.749 43.32 ;
     RECT  76.925 26.784 77.845 29.64 ;
     RECT  77.749 34.416 77.857 43.416 ;
     RECT  77.569 44.448 77.857 78.648 ;
     RECT  76.961 80.016 77.929 80.04 ;
     RECT  77.605 81.12 77.929 91.272 ;
     RECT  77.821 25.728 78.001 25.752 ;
     RECT  77.845 26.784 78.001 30.216 ;
     RECT  77.461 2.496 78.008 2.856 ;
     RECT  77.317 5.04 78.008 10.056 ;
     RECT  77.461 11.664 78.008 11.688 ;
     RECT  76.997 13.44 78.008 16.92 ;
     RECT  77.033 18.048 78.008 18.984 ;
     RECT  77.509 20.064 78.008 22.104 ;
     RECT  77.137 23.28 78.008 23.304 ;
     RECT  78.001 25.728 78.008 30.216 ;
     RECT  76.745 31.776 78.008 32.616 ;
     RECT  77.857 34.416 78.008 78.648 ;
     RECT  77.929 80.016 78.008 91.272 ;
     RECT  77.677 92.352 78.008 103.464 ;
     RECT  77.461 104.832 78.008 107.544 ;
     RECT  78.008 2.148 78.112 108.012 ;
     RECT  78.112 2.418 78.304 107.742 ;
     RECT  78.304 10.944 78.329 17.112 ;
     RECT  78.304 31.488 78.329 67.704 ;
     RECT  78.304 28.512 78.365 30.504 ;
     RECT  78.329 10.944 78.419 14.952 ;
     RECT  78.365 28.656 78.419 30.504 ;
     RECT  78.329 31.488 78.419 35.784 ;
     RECT  78.419 10.944 78.473 14.664 ;
     RECT  78.304 96.72 78.473 102.504 ;
     RECT  78.304 76.032 78.617 95.256 ;
     RECT  78.304 4.848 78.659 9.72 ;
     RECT  78.419 31.488 78.689 31.704 ;
     RECT  78.329 36.912 78.689 67.704 ;
     RECT  78.419 32.688 78.725 35.784 ;
     RECT  78.304 18.24 78.761 27.288 ;
     RECT  78.304 2.832 78.797 3.336 ;
     RECT  78.659 4.848 78.797 8.184 ;
     RECT  78.689 36.912 78.797 67.176 ;
     RECT  78.797 5.04 78.941 8.184 ;
     RECT  78.419 30.48 78.941 30.504 ;
     RECT  78.941 5.04 79.085 7.368 ;
     RECT  78.617 80.304 79.193 95.256 ;
     RECT  78.304 73.056 79.229 74.328 ;
     RECT  78.473 96.72 79.229 99.72 ;
     RECT  78.797 40.32 79.235 67.176 ;
     RECT  79.235 40.32 79.265 43.128 ;
     RECT  78.304 104.784 79.265 107.544 ;
     RECT  79.229 96.72 79.301 96.888 ;
     RECT  78.617 76.032 79.369 78.84 ;
     RECT  79.193 89.856 79.409 95.256 ;
     RECT  78.761 23.328 79.436 27.288 ;
     RECT  78.419 28.656 79.436 29.304 ;
     RECT  79.193 80.304 79.445 88.776 ;
     RECT  79.436 23.328 79.477 29.304 ;
     RECT  78.329 15.984 79.513 17.112 ;
     RECT  78.761 18.24 79.513 22.248 ;
     RECT  79.301 96.72 79.513 96.744 ;
     RECT  79.235 66 79.517 67.176 ;
     RECT  79.265 104.784 79.517 105.72 ;
     RECT  79.477 23.328 79.523 30.264 ;
     RECT  79.085 5.04 79.553 5.976 ;
     RECT  79.229 73.056 79.585 73.896 ;
     RECT  79.229 97.968 79.625 99.72 ;
     RECT  78.304 68.928 79.657 71.304 ;
     RECT  79.585 73.008 79.657 73.896 ;
     RECT  78.473 10.944 79.693 14.136 ;
     RECT  79.445 80.304 79.693 87.096 ;
     RECT  79.235 44.448 79.697 65.016 ;
     RECT  79.523 23.328 79.729 27.288 ;
     RECT  79.693 79.824 79.733 87.096 ;
     RECT  79.445 88.656 79.733 88.776 ;
     RECT  78.473 100.896 79.733 102.504 ;
     RECT  78.797 3.072 79.765 3.336 ;
     RECT  78.659 9.264 79.765 9.72 ;
     RECT  79.625 99.408 79.769 99.72 ;
     RECT  78.725 34.944 79.813 35.784 ;
     RECT  78.797 36.912 79.813 39.288 ;
     RECT  79.765 9.264 79.837 9.912 ;
     RECT  79.693 10.944 79.837 14.904 ;
     RECT  79.517 104.784 79.841 105.528 ;
     RECT  79.265 106.752 79.841 107.544 ;
     RECT  79.841 106.992 79.873 107.544 ;
     RECT  79.733 84.96 79.877 87.096 ;
     RECT  79.813 34.944 79.9 39.288 ;
     RECT  79.409 92.208 79.981 95.256 ;
     RECT  79.513 96.432 79.981 96.744 ;
     RECT  78.725 32.688 80.053 33.96 ;
     RECT  79.523 28.272 80.089 30.264 ;
     RECT  79.837 31.296 80.089 31.32 ;
     RECT  79.657 68.928 80.129 71.832 ;
     RECT  79.409 89.856 80.129 91.176 ;
     RECT  80.129 68.976 80.149 71.832 ;
     RECT  79.657 72.864 80.149 73.896 ;
     RECT  79.553 5.76 80.161 5.976 ;
     RECT  80.053 32.352 80.165 33.96 ;
     RECT  79.265 40.32 80.201 42.84 ;
     RECT  79.085 7.344 80.233 7.368 ;
     RECT  80.149 68.976 80.236 73.896 ;
     RECT  80.233 7.344 80.237 8.28 ;
     RECT  79.513 15.984 80.237 22.248 ;
     RECT  80.201 41.328 80.245 42.84 ;
     RECT  80.237 7.68 80.269 8.28 ;
     RECT  79.837 9.264 80.269 14.904 ;
     RECT  79.625 97.968 80.269 98.424 ;
     RECT  80.129 90.192 80.273 91.176 ;
     RECT  79.369 75.12 80.291 78.84 ;
     RECT  79.877 84.96 80.309 85.512 ;
     RECT  79.733 100.992 80.377 102.504 ;
     RECT  79.477 103.488 80.377 103.512 ;
     RECT  79.981 92.208 80.381 96.744 ;
     RECT  79.697 64.128 80.413 65.016 ;
     RECT  79.517 66 80.413 66.84 ;
     RECT  79.765 2.832 80.417 3.336 ;
     RECT  80.236 72.864 80.417 73.896 ;
     RECT  79.697 44.448 80.435 62.808 ;
     RECT  80.269 7.68 80.449 14.904 ;
     RECT  80.291 77.088 80.453 78.84 ;
     RECT  80.417 73.008 80.525 73.896 ;
     RECT  79.873 106.992 80.525 107.784 ;
     RECT  80.165 32.592 80.665 33.96 ;
     RECT  79.9 34.944 80.665 35.784 ;
     RECT  80.237 16.8 80.669 22.248 ;
     RECT  80.669 18.24 80.705 22.248 ;
     RECT  79.9 36.912 80.737 39.288 ;
     RECT  80.201 40.32 80.737 40.344 ;
     RECT  80.737 36.912 80.741 40.344 ;
     RECT  79.729 23.232 80.773 27.288 ;
     RECT  80.089 28.272 80.773 31.32 ;
     RECT  80.435 44.448 80.773 46.584 ;
     RECT  80.449 7.68 80.777 15.288 ;
     RECT  80.449 4.656 80.809 4.68 ;
     RECT  80.161 5.76 80.809 6.072 ;
     RECT  80.705 20.544 80.845 22.248 ;
     RECT  80.773 23.232 80.845 31.32 ;
     RECT  80.381 93.072 80.849 96.744 ;
     RECT  79.733 88.656 80.881 88.68 ;
     RECT  80.435 47.664 80.915 62.808 ;
     RECT  79.733 79.824 80.917 83.784 ;
     RECT  80.309 84.96 80.917 84.984 ;
     RECT  80.917 79.824 80.921 84.984 ;
     RECT  80.849 93.072 80.921 95.64 ;
     RECT  80.881 88.656 80.953 88.776 ;
     RECT  80.777 7.872 80.957 15.288 ;
     RECT  79.877 87.072 81.013 87.096 ;
     RECT  80.953 88.464 81.013 88.776 ;
     RECT  80.957 7.968 81.065 15.288 ;
     RECT  79.769 99.408 81.097 99.528 ;
     RECT  80.377 100.992 81.097 103.8 ;
     RECT  80.809 3.84 81.133 4.68 ;
     RECT  80.809 5.76 81.133 6.312 ;
     RECT  81.013 87.072 81.157 88.776 ;
     RECT  81.025 67.872 81.169 67.896 ;
     RECT  80.245 41.328 81.205 42.552 ;
     RECT  80.413 64.128 81.205 66.84 ;
     RECT  81.169 67.872 81.205 67.992 ;
     RECT  79.841 105.168 81.241 105.528 ;
     RECT  80.525 106.992 81.241 107.064 ;
     RECT  80.845 20.544 81.245 31.32 ;
     RECT  80.915 51.072 81.277 62.808 ;
     RECT  81.205 64.128 81.277 67.992 ;
     RECT  80.236 68.976 81.277 71.736 ;
     RECT  80.665 32.592 81.281 35.784 ;
     RECT  80.773 43.632 81.281 46.584 ;
     RECT  80.453 78.192 81.308 78.84 ;
     RECT  80.921 79.824 81.308 81.144 ;
     RECT  81.205 41.04 81.313 42.552 ;
     RECT  81.277 64.128 81.317 71.736 ;
     RECT  81.245 30.816 81.349 31.32 ;
     RECT  81.281 32.592 81.349 35.736 ;
     RECT  81.349 30.816 81.353 35.736 ;
     RECT  80.705 18.24 81.389 19.416 ;
     RECT  81.281 43.824 81.421 46.584 ;
     RECT  80.915 47.664 81.421 50.04 ;
     RECT  80.417 2.832 81.457 2.856 ;
     RECT  81.133 3.84 81.457 6.312 ;
     RECT  81.317 64.176 81.457 71.736 ;
     RECT  80.453 77.088 81.457 77.112 ;
     RECT  81.308 78.192 81.457 81.144 ;
     RECT  80.921 93.072 81.529 95.16 ;
     RECT  80.269 97.824 81.529 98.424 ;
     RECT  81.097 99.408 81.529 103.8 ;
     RECT  81.457 2.832 81.533 6.312 ;
     RECT  80.291 75.12 81.533 76.104 ;
     RECT  81.241 105.168 81.533 107.064 ;
     RECT  81.157 86.64 81.565 88.776 ;
     RECT  80.921 82.272 81.601 84.984 ;
     RECT  80.849 96.624 81.637 96.744 ;
     RECT  81.529 97.824 81.637 103.8 ;
     RECT  81.245 20.544 81.641 29.832 ;
     RECT  80.669 16.8 81.673 17.256 ;
     RECT  81.457 64.176 81.677 72.024 ;
     RECT  81.677 72 81.709 72.024 ;
     RECT  80.525 73.056 81.709 73.896 ;
     RECT  81.673 16.8 81.745 17.448 ;
     RECT  81.529 92.16 81.821 95.16 ;
     RECT  81.533 75.12 81.853 76.008 ;
     RECT  81.709 72 81.857 73.896 ;
     RECT  81.533 4.608 81.889 6.312 ;
     RECT  81.277 51.072 81.889 62.856 ;
     RECT  81.601 82.272 81.889 85.176 ;
     RECT  81.565 86.64 81.889 89.544 ;
     RECT  80.273 90.624 81.889 91.176 ;
     RECT  81.889 82.224 81.925 85.176 ;
     RECT  81.637 96.624 81.932 103.8 ;
     RECT  81.533 105.168 81.932 106.392 ;
     RECT  81.889 4.608 81.961 6.84 ;
     RECT  81.065 7.968 81.961 13.464 ;
     RECT  81.932 96.624 81.965 106.392 ;
     RECT  81.925 82.224 81.997 85.272 ;
     RECT  81.889 86.64 81.997 91.176 ;
     RECT  81.965 101.424 82.019 106.392 ;
     RECT  81.997 82.224 82.021 91.176 ;
     RECT  82.021 82.224 82.067 91.896 ;
     RECT  81.353 30.816 82.109 35.304 ;
     RECT  81.853 74.928 82.109 76.008 ;
     RECT  81.961 4.608 82.213 13.464 ;
     RECT  81.065 14.496 82.213 15.288 ;
     RECT  81.457 77.088 82.213 81.144 ;
     RECT  82.067 82.224 82.213 90.072 ;
     RECT  82.213 4.608 82.217 15.288 ;
     RECT  82.213 77.088 82.289 90.072 ;
     RECT  82.217 4.656 82.316 15.288 ;
     RECT  81.745 16.512 82.316 17.448 ;
     RECT  81.889 51.072 82.321 63 ;
     RECT  81.677 64.176 82.321 70.824 ;
     RECT  81.965 96.624 82.321 100.344 ;
     RECT  81.421 43.824 82.361 50.04 ;
     RECT  80.741 36.912 82.393 40.008 ;
     RECT  82.321 96.288 82.393 100.344 ;
     RECT  81.313 41.04 82.429 42.84 ;
     RECT  82.361 43.824 82.429 46.584 ;
     RECT  82.109 32.544 82.501 35.304 ;
     RECT  82.393 36.48 82.501 40.008 ;
     RECT  82.361 47.664 82.501 50.04 ;
     RECT  82.321 51.072 82.501 70.824 ;
     RECT  82.316 4.656 82.537 17.448 ;
     RECT  81.389 18.48 82.537 19.416 ;
     RECT  81.641 20.592 82.604 29.832 ;
     RECT  82.109 30.816 82.604 31.272 ;
     RECT  82.537 4.656 82.645 19.416 ;
     RECT  82.604 20.592 82.645 31.272 ;
     RECT  82.109 75.984 82.741 76.008 ;
     RECT  82.289 77.088 82.741 88.776 ;
     RECT  81.781 107.52 82.789 107.544 ;
     RECT  81.857 73.056 82.825 73.896 ;
     RECT  82.825 73.056 82.861 73.944 ;
     RECT  82.109 74.928 82.861 74.952 ;
     RECT  82.067 91.2 83.005 91.896 ;
     RECT  82.019 101.424 83.005 103.8 ;
     RECT  81.857 72 83.036 72.024 ;
     RECT  82.861 73.056 83.036 74.952 ;
     RECT  83.036 72 83.077 74.952 ;
     RECT  82.501 47.664 83.149 70.824 ;
     RECT  83.077 71.808 83.149 74.952 ;
     RECT  83.005 91.2 83.185 91.944 ;
     RECT  81.821 93.072 83.185 95.16 ;
     RECT  83.185 91.2 83.221 95.16 ;
     RECT  82.789 107.088 83.221 107.544 ;
     RECT  82.645 4.656 83.228 31.272 ;
     RECT  82.501 32.544 83.293 40.008 ;
     RECT  82.429 41.04 83.293 46.584 ;
     RECT  81.533 2.832 83.408 3.336 ;
     RECT  83.228 4.608 83.408 31.272 ;
     RECT  83.293 32.544 83.408 46.584 ;
     RECT  83.149 47.664 83.408 74.952 ;
     RECT  82.741 75.984 83.408 88.776 ;
     RECT  83.221 91.152 83.408 95.16 ;
     RECT  82.393 96.192 83.408 100.344 ;
     RECT  83.005 101.424 83.408 103.848 ;
     RECT  82.019 105.168 83.408 105.624 ;
     RECT  83.221 107.04 83.408 107.544 ;
     RECT  83.408 2.148 83.512 108.012 ;
     RECT  83.512 2.418 83.704 107.742 ;
     RECT  83.704 107.088 83.729 107.544 ;
     RECT  83.704 6.048 83.801 6.312 ;
     RECT  83.704 13.728 83.843 25.848 ;
     RECT  83.704 101.568 83.909 103.848 ;
     RECT  83.704 96.288 83.939 100.44 ;
     RECT  83.801 6.096 83.945 6.312 ;
     RECT  83.843 13.728 83.945 25.8 ;
     RECT  83.939 96.288 83.981 100.344 ;
     RECT  83.704 82.176 84.053 89.496 ;
     RECT  83.981 96.288 84.053 100.296 ;
     RECT  83.704 7.632 84.089 12.456 ;
     RECT  84.053 96.288 84.227 100.248 ;
     RECT  83.704 36.288 84.371 68.232 ;
     RECT  84.227 99.792 84.377 100.248 ;
     RECT  83.704 2.784 84.413 5.064 ;
     RECT  83.704 26.88 84.413 35.304 ;
     RECT  83.704 73.776 84.413 75.432 ;
     RECT  83.945 6.144 84.485 6.312 ;
     RECT  84.371 44.928 84.557 68.232 ;
     RECT  84.053 82.176 84.659 88.776 ;
     RECT  84.413 74.88 84.668 75.432 ;
     RECT  83.704 76.464 84.668 81.144 ;
     RECT  84.668 74.88 84.755 81.144 ;
     RECT  84.755 76.944 84.769 81.144 ;
     RECT  84.659 82.176 84.769 87.096 ;
     RECT  84.769 76.944 84.809 87.096 ;
     RECT  83.704 69.504 84.841 72.648 ;
     RECT  84.413 73.776 84.841 73.896 ;
     RECT  83.729 107.328 84.841 107.544 ;
     RECT  83.704 91.344 84.877 95.16 ;
     RECT  84.557 47.664 84.953 68.232 ;
     RECT  84.809 78.048 84.953 87.096 ;
     RECT  84.371 36.288 84.989 43.848 ;
     RECT  84.841 69.504 84.989 73.896 ;
     RECT  84.413 3.408 85.025 5.064 ;
     RECT  84.377 100.224 85.025 100.248 ;
     RECT  84.413 26.88 85.045 29.304 ;
     RECT  84.953 65.136 85.057 68.232 ;
     RECT  84.989 69.504 85.057 71.976 ;
     RECT  84.089 8.016 85.093 12.456 ;
     RECT  85.045 26.496 85.097 29.304 ;
     RECT  84.413 30.336 85.097 35.304 ;
     RECT  83.909 101.904 85.097 103.848 ;
     RECT  83.945 13.728 85.165 25.512 ;
     RECT  85.025 3.648 85.237 5.064 ;
     RECT  84.485 6.144 85.237 6.168 ;
     RECT  84.877 90.72 85.273 95.16 ;
     RECT  84.227 96.288 85.277 98.568 ;
     RECT  85.165 13.488 85.283 25.512 ;
     RECT  85.283 25.2 85.309 25.512 ;
     RECT  85.097 26.496 85.309 27.816 ;
     RECT  85.097 30.576 85.349 35.304 ;
     RECT  85.097 102.384 85.349 103.848 ;
     RECT  84.809 76.944 85.385 76.968 ;
     RECT  84.841 106.464 85.385 107.544 ;
     RECT  85.349 102.72 85.417 103.848 ;
     RECT  83.704 104.832 85.417 105.48 ;
     RECT  85.417 102.72 85.421 105.48 ;
     RECT  85.349 31.872 85.453 35.304 ;
     RECT  84.989 36.288 85.453 43.416 ;
     RECT  84.989 73.104 85.477 73.896 ;
     RECT  84.755 74.88 85.477 75.288 ;
     RECT  85.057 65.136 85.493 71.976 ;
     RECT  85.273 90.672 85.493 95.16 ;
     RECT  84.659 88.368 85.525 88.776 ;
     RECT  85.493 65.136 85.529 68.232 ;
     RECT  85.477 73.104 85.564 75.288 ;
     RECT  85.385 106.464 85.565 106.488 ;
     RECT  85.093 7.44 85.573 12.456 ;
     RECT  85.283 13.488 85.573 23.688 ;
     RECT  85.573 7.44 85.66 23.688 ;
     RECT  84.953 81.12 85.708 87.096 ;
     RECT  85.66 7.44 85.709 12.504 ;
     RECT  85.493 69.264 85.709 71.976 ;
     RECT  85.564 73.104 85.709 74.136 ;
     RECT  85.708 86.64 85.777 87.096 ;
     RECT  85.493 90.72 85.777 95.16 ;
     RECT  85.453 31.872 85.817 43.416 ;
     RECT  85.777 86.64 85.817 87.24 ;
     RECT  84.557 44.928 85.849 46.584 ;
     RECT  85.849 44.448 85.885 46.584 ;
     RECT  84.953 47.664 85.885 49.848 ;
     RECT  85.709 69.264 85.961 71.928 ;
     RECT  85.885 44.448 85.993 49.848 ;
     RECT  84.953 51.456 85.993 63.768 ;
     RECT  85.529 65.136 85.993 67.944 ;
     RECT  85.993 44.448 86.005 50.376 ;
     RECT  85.993 51.456 86.005 67.944 ;
     RECT  85.708 81.12 86.029 85.32 ;
     RECT  85.849 99.84 86.029 99.864 ;
     RECT  86.029 99.84 86.101 100.152 ;
     RECT  86.029 101.328 86.101 101.352 ;
     RECT  85.709 7.44 86.141 7.464 ;
     RECT  85.961 69.504 86.141 71.928 ;
     RECT  85.817 39.36 86.147 43.416 ;
     RECT  86.005 44.448 86.147 67.944 ;
     RECT  85.237 3.648 86.173 6.168 ;
     RECT  85.349 30.576 86.285 30.888 ;
     RECT  86.173 3.072 86.317 6.168 ;
     RECT  86.147 40.032 86.317 43.416 ;
     RECT  86.147 44.448 86.317 48.648 ;
     RECT  86.317 40.032 86.357 48.648 ;
     RECT  84.953 78.048 86.389 79.8 ;
     RECT  86.029 81.024 86.389 85.32 ;
     RECT  86.101 99.84 86.465 101.352 ;
     RECT  86.389 78.048 86.476 85.32 ;
     RECT  86.285 30.624 86.497 30.888 ;
     RECT  85.817 31.872 86.497 38.28 ;
     RECT  86.476 78.048 86.497 79.752 ;
     RECT  86.317 3.024 86.533 6.168 ;
     RECT  86.497 77.616 86.569 79.752 ;
     RECT  85.777 90.72 86.569 95.256 ;
     RECT  85.277 96.288 86.569 96.36 ;
     RECT  85.277 97.44 86.569 98.568 ;
     RECT  85.66 13.488 86.573 23.688 ;
     RECT  85.309 25.2 86.605 27.816 ;
     RECT  86.147 49.824 86.605 67.944 ;
     RECT  85.817 86.832 86.605 87.24 ;
     RECT  85.525 88.368 86.605 89.112 ;
     RECT  85.421 102.72 86.605 105.384 ;
     RECT  85.564 75.168 86.608 75.288 ;
     RECT  86.476 80.832 86.609 85.32 ;
     RECT  86.605 102.432 86.645 105.384 ;
     RECT  85.709 8.448 86.677 12.504 ;
     RECT  86.573 13.488 86.677 15.576 ;
     RECT  86.569 77.376 86.677 79.752 ;
     RECT  85.385 107.52 86.677 107.544 ;
     RECT  86.357 40.032 86.681 46.632 ;
     RECT  86.677 106.752 86.681 107.544 ;
     RECT  86.569 96.288 86.713 98.568 ;
     RECT  86.677 77.328 86.717 79.752 ;
     RECT  86.533 3.024 86.771 6.264 ;
     RECT  86.573 16.656 86.785 23.688 ;
     RECT  86.605 24.72 86.785 27.816 ;
     RECT  86.497 30.624 86.785 38.28 ;
     RECT  86.785 30.624 86.789 38.808 ;
     RECT  86.569 90.624 86.821 95.256 ;
     RECT  86.713 96.288 86.821 98.616 ;
     RECT  86.608 75.168 86.825 75.336 ;
     RECT  86.717 77.328 86.825 79.704 ;
     RECT  86.771 3.024 86.857 4.776 ;
     RECT  86.825 77.328 86.857 79.656 ;
     RECT  86.821 90.624 86.867 98.616 ;
     RECT  86.867 90.624 86.908 96.072 ;
     RECT  85.709 73.248 86.929 74.136 ;
     RECT  86.465 101.328 86.933 101.352 ;
     RECT  86.645 104.832 86.965 105.384 ;
     RECT  86.681 40.032 86.969 43.416 ;
     RECT  86.929 72.864 87.037 74.136 ;
     RECT  86.825 75.168 87.037 75.192 ;
     RECT  86.857 76.464 87.113 79.656 ;
     RECT  86.771 6 87.145 6.264 ;
     RECT  86.645 102.432 87.145 103.8 ;
     RECT  86.141 69.504 87.185 71.688 ;
     RECT  86.965 104.832 87.217 105.768 ;
     RECT  86.681 106.752 87.217 106.92 ;
     RECT  86.357 47.664 87.221 48.648 ;
     RECT  87.185 70.752 87.221 71.688 ;
     RECT  85.097 28.848 87.257 29.304 ;
     RECT  86.677 8.448 87.289 15.576 ;
     RECT  86.609 81.024 87.293 85.32 ;
     RECT  87.217 104.832 87.293 106.92 ;
     RECT  86.785 16.656 87.325 27.816 ;
     RECT  86.605 86.832 87.325 89.544 ;
     RECT  86.857 2.832 87.329 4.776 ;
     RECT  87.289 7.536 87.329 15.576 ;
     RECT  86.605 49.824 87.329 68.424 ;
     RECT  87.145 102.288 87.329 103.8 ;
     RECT  86.969 41.184 87.365 42.36 ;
     RECT  87.257 29.04 87.397 29.304 ;
     RECT  86.789 30.624 87.397 36.984 ;
     RECT  86.465 100.128 87.469 100.296 ;
     RECT  86.908 90.624 87.473 95.64 ;
     RECT  87.293 81.024 87.491 84.936 ;
     RECT  87.329 7.536 87.505 7.944 ;
     RECT  87.325 16.656 87.532 28.008 ;
     RECT  87.037 72.864 87.545 75.192 ;
     RECT  87.113 78.048 87.545 79.656 ;
     RECT  87.293 104.832 87.545 106.584 ;
     RECT  87.325 86.448 87.577 89.544 ;
     RECT  87.397 29.04 87.581 36.984 ;
     RECT  87.577 86.064 87.613 89.544 ;
     RECT  87.473 90.624 87.613 94.392 ;
     RECT  87.329 8.976 87.617 15.576 ;
     RECT  87.532 16.656 87.617 19.8 ;
     RECT  87.145 6 87.685 6.36 ;
     RECT  87.505 7.44 87.685 7.944 ;
     RECT  87.617 8.976 87.725 12.648 ;
     RECT  87.329 49.824 87.725 67.368 ;
     RECT  86.789 37.968 87.757 38.808 ;
     RECT  87.329 68.352 87.757 68.424 ;
     RECT  87.185 69.504 87.757 69.72 ;
     RECT  86.681 44.496 87.781 46.632 ;
     RECT  87.221 47.664 87.781 48.456 ;
     RECT  87.617 13.632 87.797 15.336 ;
     RECT  87.781 44.496 87.797 48.456 ;
     RECT  87.491 81.024 87.797 84.696 ;
     RECT  87.581 35.28 87.827 36.984 ;
     RECT  87.797 14.928 87.833 15.336 ;
     RECT  87.797 44.496 87.833 48.264 ;
     RECT  87.545 72.864 87.833 74.952 ;
     RECT  86.969 43.344 87.865 43.416 ;
     RECT  86.867 97.872 87.973 98.616 ;
     RECT  87.469 99.696 88.009 100.296 ;
     RECT  87.113 76.464 88.117 76.488 ;
     RECT  88.117 76.32 88.189 76.488 ;
     RECT  87.757 37.968 88.225 39.048 ;
     RECT  86.969 40.032 88.225 40.056 ;
     RECT  88.189 76.32 88.225 77.064 ;
     RECT  87.545 78.048 88.225 79.416 ;
     RECT  87.221 70.752 88.261 71.448 ;
     RECT  88.009 99.696 88.369 100.824 ;
     RECT  87.329 2.832 88.405 4.584 ;
     RECT  87.329 102.288 88.477 103.56 ;
     RECT  87.473 95.616 88.513 95.64 ;
     RECT  87.725 63.792 88.585 67.368 ;
     RECT  87.757 68.352 88.585 69.72 ;
     RECT  87.365 41.52 88.657 42.36 ;
     RECT  87.865 43.344 88.657 43.704 ;
     RECT  88.405 2.256 88.693 4.584 ;
     RECT  87.532 20.928 88.693 28.008 ;
     RECT  87.581 29.04 88.693 34.104 ;
     RECT  87.827 35.28 88.693 36.936 ;
     RECT  87.613 86.064 88.693 94.392 ;
     RECT  88.513 95.472 88.693 95.64 ;
     RECT  88.261 70.752 88.765 71.688 ;
     RECT  88.693 2.256 88.808 4.68 ;
     RECT  87.685 6 88.808 7.944 ;
     RECT  87.725 8.976 88.808 12.504 ;
     RECT  87.797 13.632 88.808 13.8 ;
     RECT  87.833 14.928 88.808 14.952 ;
     RECT  88.765 16.032 88.808 16.056 ;
     RECT  87.617 17.04 88.808 19.8 ;
     RECT  88.693 20.928 88.808 36.936 ;
     RECT  88.225 37.968 88.808 40.056 ;
     RECT  88.657 41.52 88.808 43.704 ;
     RECT  87.833 44.736 88.808 48.264 ;
     RECT  87.725 49.824 88.808 62.76 ;
     RECT  88.585 63.792 88.808 69.72 ;
     RECT  88.765 70.752 88.808 71.928 ;
     RECT  87.833 72.96 88.808 74.952 ;
     RECT  88.225 76.32 88.808 79.416 ;
     RECT  87.797 81.12 88.808 84.696 ;
     RECT  88.693 86.064 88.808 95.64 ;
     RECT  87.973 97.104 88.808 98.616 ;
     RECT  88.369 99.696 88.808 101.064 ;
     RECT  88.477 102.288 88.808 103.848 ;
     RECT  87.545 104.832 88.808 106.008 ;
     RECT  88.153 107.568 88.808 107.592 ;
     RECT  88.808 2.148 88.912 108.012 ;
     RECT  88.912 2.256 89.104 107.742 ;
     RECT  89.104 7.44 89.129 9.528 ;
     RECT  89.104 78.192 89.201 81.144 ;
     RECT  89.104 17.04 89.245 18.216 ;
     RECT  89.104 2.256 89.273 5.16 ;
     RECT  89.104 10.704 89.309 16.056 ;
     RECT  89.104 34.752 89.309 74.664 ;
     RECT  89.309 45.024 89.345 74.664 ;
     RECT  89.129 7.44 89.381 8.232 ;
     RECT  89.345 72.96 89.381 74.664 ;
     RECT  89.104 82.512 89.381 84.696 ;
     RECT  89.104 88.128 89.417 95.688 ;
     RECT  89.273 2.64 89.459 5.16 ;
     RECT  89.104 19.344 89.489 28.008 ;
     RECT  89.459 3.984 89.525 5.16 ;
     RECT  89.104 107.232 89.525 107.592 ;
     RECT  89.345 45.024 89.597 71.928 ;
     RECT  89.417 92.688 89.597 95.688 ;
     RECT  89.597 45.024 89.603 71.736 ;
     RECT  89.597 92.88 89.669 95.688 ;
     RECT  89.669 92.88 89.777 95.496 ;
     RECT  89.777 92.88 89.813 95.16 ;
     RECT  89.245 17.04 89.849 18.024 ;
     RECT  89.603 51.168 89.849 71.736 ;
     RECT  89.104 96.768 89.932 101.4 ;
     RECT  89.309 34.752 90.029 43.848 ;
     RECT  89.104 29.232 90.097 30.696 ;
     RECT  89.489 20.352 90.101 28.008 ;
     RECT  90.029 35.808 90.101 43.848 ;
     RECT  89.104 103.776 90.133 104.04 ;
     RECT  89.104 105.216 90.133 106.2 ;
     RECT  89.525 107.232 90.133 107.256 ;
     RECT  89.104 6.144 90.169 6.312 ;
     RECT  89.381 7.44 90.169 7.8 ;
     RECT  89.129 9.504 90.169 9.528 ;
     RECT  89.603 45.024 90.173 50.136 ;
     RECT  89.932 96.768 90.173 99.72 ;
     RECT  89.201 78.192 90.205 79.416 ;
     RECT  89.201 80.448 90.205 81.144 ;
     RECT  90.133 103.776 90.245 104.136 ;
     RECT  89.104 86.208 90.277 86.904 ;
     RECT  89.417 88.128 90.277 91.608 ;
     RECT  90.277 86.208 90.281 91.608 ;
     RECT  89.309 10.8 90.313 16.056 ;
     RECT  89.849 17.04 90.313 17.64 ;
     RECT  90.097 29.088 90.313 30.696 ;
     RECT  89.104 31.776 90.313 33.624 ;
     RECT  89.932 101.088 90.385 101.4 ;
     RECT  90.277 102.816 90.385 102.84 ;
     RECT  90.101 20.736 90.421 28.008 ;
     RECT  90.313 29.088 90.421 33.624 ;
     RECT  89.381 73.632 90.421 74.664 ;
     RECT  90.169 6.144 90.524 7.8 ;
     RECT  90.169 8.976 90.524 9.528 ;
     RECT  90.173 96.768 90.533 96.792 ;
     RECT  90.524 6.144 90.605 9.528 ;
     RECT  90.313 10.8 90.605 17.64 ;
     RECT  90.605 8.496 90.611 9.528 ;
     RECT  90.601 3.168 90.637 3.192 ;
     RECT  89.525 4.176 90.637 5.16 ;
     RECT  90.421 20.736 90.659 33.624 ;
     RECT  89.489 19.344 90.785 19.368 ;
     RECT  90.133 105.216 90.785 107.256 ;
     RECT  90.659 28.56 90.817 33.624 ;
     RECT  90.029 34.752 90.817 34.776 ;
     RECT  89.813 92.88 90.817 94.728 ;
     RECT  89.849 67.824 90.889 71.736 ;
     RECT  90.659 20.736 90.893 27.384 ;
     RECT  90.205 78.192 90.925 81.144 ;
     RECT  90.605 12.912 90.929 17.64 ;
     RECT  90.101 35.856 90.929 43.848 ;
     RECT  89.104 75.936 90.949 76.392 ;
     RECT  89.381 82.8 90.956 84.696 ;
     RECT  90.817 28.56 90.965 34.776 ;
     RECT  90.889 67.824 90.965 71.928 ;
     RECT  90.611 8.976 90.997 9.528 ;
     RECT  90.605 10.8 90.997 11.544 ;
     RECT  90.949 75.936 90.997 77.016 ;
     RECT  90.925 78.192 90.997 81.768 ;
     RECT  90.637 3.168 91.033 5.16 ;
     RECT  90.605 6.144 91.033 6.984 ;
     RECT  90.997 8.976 91.037 11.544 ;
     RECT  90.965 67.824 91.037 67.896 ;
     RECT  90.385 101.088 91.037 102.84 ;
     RECT  90.929 40.656 91.069 43.848 ;
     RECT  90.173 45.024 91.069 49.848 ;
     RECT  90.281 86.688 91.073 91.608 ;
     RECT  90.893 20.736 91.177 27.192 ;
     RECT  89.849 51.168 91.177 66.84 ;
     RECT  91.037 67.824 91.177 67.848 ;
     RECT  90.173 97.872 91.187 99.72 ;
     RECT  90.956 82.8 91.189 84.792 ;
     RECT  90.929 15.984 91.213 17.64 ;
     RECT  90.929 35.856 91.217 39.624 ;
     RECT  91.177 51.168 91.217 67.848 ;
     RECT  90.785 105.216 91.217 107.064 ;
     RECT  90.817 92.88 91.228 95.688 ;
     RECT  91.069 40.656 91.253 49.848 ;
     RECT  91.217 51.168 91.285 67.704 ;
     RECT  91.228 92.88 91.285 95.16 ;
     RECT  90.997 75.936 91.321 81.768 ;
     RECT  91.189 82.8 91.321 84.936 ;
     RECT  91.073 91.584 91.357 91.608 ;
     RECT  91.285 92.736 91.357 95.16 ;
     RECT  91.253 48.624 91.361 49.848 ;
     RECT  90.421 73.104 91.393 74.664 ;
     RECT  91.321 75.936 91.393 84.936 ;
     RECT  91.393 73.104 91.433 84.936 ;
     RECT  91.361 49.056 91.537 49.848 ;
     RECT  91.073 86.688 91.541 90.552 ;
     RECT  91.537 49.056 91.645 50.088 ;
     RECT  91.285 51.072 91.645 67.704 ;
     RECT  90.965 68.88 91.667 71.928 ;
     RECT  91.217 35.856 91.681 38.808 ;
     RECT  90.965 28.56 91.753 31.416 ;
     RECT  91.187 98.016 91.753 99.72 ;
     RECT  91.037 101.088 91.763 101.448 ;
     RECT  91.033 3.168 91.825 6.984 ;
     RECT  91.177 20.496 91.829 27.192 ;
     RECT  91.433 75.12 91.909 84.936 ;
     RECT  91.037 102.528 91.916 102.84 ;
     RECT  90.245 103.872 91.916 104.136 ;
     RECT  91.825 3.072 91.937 6.984 ;
     RECT  91.763 101.088 91.937 101.4 ;
     RECT  91.916 102.528 91.957 104.136 ;
     RECT  91.217 105.216 91.957 106.872 ;
     RECT  91.909 75.12 91.973 80.088 ;
     RECT  91.037 9.12 92.005 11.544 ;
     RECT  91.753 98.016 92.012 99.816 ;
     RECT  91.667 69.168 92.077 71.928 ;
     RECT  91.433 73.104 92.077 73.896 ;
     RECT  91.937 101.088 92.081 101.16 ;
     RECT  92.005 9.072 92.113 11.544 ;
     RECT  92.113 8.304 92.149 11.544 ;
     RECT  90.929 12.912 92.149 14.856 ;
     RECT  91.645 49.056 92.185 67.704 ;
     RECT  90.965 32.448 92.257 34.776 ;
     RECT  91.681 35.76 92.257 38.808 ;
     RECT  91.253 43.632 92.257 46.968 ;
     RECT  91.357 91.584 92.257 95.16 ;
     RECT  91.909 81.12 92.329 84.936 ;
     RECT  92.012 98.016 92.329 99.912 ;
     RECT  91.541 90.528 92.341 90.552 ;
     RECT  92.257 91.584 92.341 95.352 ;
     RECT  91.541 86.688 92.387 89.496 ;
     RECT  92.257 43.632 92.405 47.4 ;
     RECT  92.387 86.688 92.405 89.16 ;
     RECT  91.357 96.336 92.405 96.36 ;
     RECT  91.829 20.496 92.437 21.768 ;
     RECT  92.405 86.688 92.477 89.064 ;
     RECT  91.957 102.528 92.549 106.872 ;
     RECT  92.329 81.12 92.581 85.56 ;
     RECT  92.477 86.688 92.581 88.776 ;
     RECT  92.549 103.2 92.585 106.872 ;
     RECT  92.405 43.632 92.653 44.136 ;
     RECT  92.185 49.056 92.653 67.944 ;
     RECT  92.077 69.168 92.653 73.896 ;
     RECT  92.341 90.528 92.653 95.352 ;
     RECT  92.437 20.16 92.657 21.768 ;
     RECT  92.657 20.16 92.765 21.672 ;
     RECT  92.581 81.12 92.765 88.776 ;
     RECT  92.329 98.016 92.765 100.824 ;
     RECT  92.761 96.864 92.797 96.888 ;
     RECT  92.585 103.68 92.801 106.872 ;
     RECT  91.213 15.984 92.821 18.6 ;
     RECT  92.765 20.16 92.821 21.144 ;
     RECT  91.253 40.656 92.821 42.168 ;
     RECT  92.653 49.056 92.861 73.896 ;
     RECT  91.937 3.12 92.869 6.984 ;
     RECT  92.821 15.984 92.908 21.144 ;
     RECT  92.149 8.304 92.909 14.856 ;
     RECT  92.821 40.656 92.909 42.216 ;
     RECT  92.797 96.864 92.909 96.984 ;
     RECT  91.753 28.368 92.941 31.416 ;
     RECT  92.257 32.448 92.941 38.808 ;
     RECT  91.973 77.232 92.941 80.088 ;
     RECT  92.765 81.12 92.941 81.144 ;
     RECT  92.861 49.008 92.945 73.896 ;
     RECT  92.945 49.824 93.013 73.896 ;
     RECT  91.973 75.12 93.013 76.104 ;
     RECT  92.941 28.368 93.017 38.808 ;
     RECT  93.017 28.368 93.053 31.224 ;
     RECT  93.017 32.208 93.053 38.808 ;
     RECT  93.013 49.824 93.053 76.104 ;
     RECT  92.869 3.12 93.068 7.08 ;
     RECT  92.801 104.256 93.068 106.872 ;
     RECT  91.829 22.992 93.085 27.192 ;
     RECT  93.053 28.368 93.085 30.936 ;
     RECT  92.941 77.232 93.107 81.144 ;
     RECT  93.068 104.256 93.109 107.496 ;
     RECT  93.068 2.688 93.155 7.08 ;
     RECT  92.909 40.656 93.157 42.168 ;
     RECT  93.155 3.024 93.193 7.08 ;
     RECT  93.193 3.024 93.233 7.128 ;
     RECT  92.653 43.344 93.301 44.136 ;
     RECT  93.157 40.464 93.337 42.168 ;
     RECT  93.337 40.32 93.409 42.168 ;
     RECT  92.405 45.264 93.409 47.4 ;
     RECT  93.233 4.128 93.445 7.128 ;
     RECT  92.909 8.304 93.445 10.872 ;
     RECT  92.653 90.288 93.445 95.352 ;
     RECT  92.909 11.952 93.493 14.856 ;
     RECT  93.445 90.144 93.517 95.352 ;
     RECT  92.765 98.016 93.517 100.296 ;
     RECT  93.301 43.152 93.553 44.136 ;
     RECT  93.493 11.952 93.637 14.904 ;
     RECT  92.908 15.984 93.637 18.744 ;
     RECT  92.765 82.512 93.685 88.776 ;
     RECT  93.517 89.904 93.685 95.352 ;
     RECT  93.085 22.992 93.733 30.936 ;
     RECT  93.409 45.264 93.733 47.928 ;
     RECT  93.661 103.2 93.733 103.224 ;
     RECT  93.733 22.56 93.877 30.936 ;
     RECT  93.685 82.512 94.021 95.352 ;
     RECT  93.445 4.128 94.069 10.872 ;
     RECT  93.637 11.952 94.069 18.744 ;
     RECT  92.908 20.16 94.069 21.144 ;
     RECT  93.233 3.024 94.208 3.144 ;
     RECT  94.069 4.128 94.208 18.744 ;
     RECT  94.069 20.064 94.208 21.144 ;
     RECT  93.877 22.176 94.208 30.936 ;
     RECT  93.053 32.592 94.208 38.808 ;
     RECT  93.409 39.888 94.208 42.168 ;
     RECT  93.553 43.152 94.208 44.184 ;
     RECT  93.733 45.264 94.208 48.792 ;
     RECT  93.053 49.824 94.208 72.84 ;
     RECT  93.053 73.872 94.208 76.104 ;
     RECT  93.107 77.232 94.208 77.688 ;
     RECT  93.107 78.864 94.208 81.144 ;
     RECT  94.021 82.512 94.208 95.448 ;
     RECT  92.909 96.864 94.208 96.888 ;
     RECT  93.517 97.92 94.208 100.296 ;
     RECT  93.733 103.008 94.208 103.224 ;
     RECT  93.109 104.256 94.208 107.784 ;
     RECT  94.208 2.148 94.312 108.012 ;
     RECT  94.312 2.418 94.504 107.742 ;
     RECT  94.504 105.168 94.529 106.584 ;
     RECT  94.504 3.072 94.565 10.92 ;
     RECT  94.504 77.088 94.565 77.688 ;
     RECT  94.565 3.072 94.637 7.176 ;
     RECT  94.504 97.92 94.673 100.296 ;
     RECT  94.529 105.216 94.673 106.584 ;
     RECT  94.637 3.072 94.781 7.08 ;
     RECT  94.504 48.768 94.781 49.176 ;
     RECT  94.565 77.088 94.781 77.352 ;
     RECT  94.504 29.184 94.787 43.848 ;
     RECT  94.504 16.512 94.817 22.584 ;
     RECT  94.781 3.072 94.889 6.888 ;
     RECT  94.673 97.92 94.889 99.576 ;
     RECT  94.504 23.664 94.925 28.008 ;
     RECT  94.787 36.912 94.961 43.848 ;
     RECT  94.961 43.824 94.997 43.848 ;
     RECT  94.504 50.16 94.997 72.216 ;
     RECT  94.817 16.512 95.171 21.576 ;
     RECT  94.889 5.808 95.249 6.888 ;
     RECT  95.171 18.384 95.249 21.576 ;
     RECT  95.249 5.856 95.321 6.888 ;
     RECT  94.504 12.048 95.321 15.336 ;
     RECT  95.249 18.384 95.321 21.144 ;
     RECT  95.321 13.104 95.357 15.336 ;
     RECT  95.357 13.392 95.465 15.336 ;
     RECT  94.504 45.264 95.465 47.688 ;
     RECT  94.781 48.96 95.497 49.176 ;
     RECT  94.997 50.16 95.497 68.088 ;
     RECT  94.504 88.752 95.497 89.544 ;
     RECT  95.321 12.048 95.501 12.072 ;
     RECT  95.468 44.064 95.509 44.088 ;
     RECT  95.465 45.264 95.509 47.496 ;
     RECT  94.817 22.56 95.533 22.584 ;
     RECT  94.925 23.664 95.533 27.72 ;
     RECT  94.673 105.408 95.537 106.584 ;
     RECT  94.565 8.208 95.569 10.92 ;
     RECT  95.509 44.064 95.596 47.496 ;
     RECT  94.787 29.184 95.609 35.928 ;
     RECT  95.321 18.384 95.645 19.128 ;
     RECT  95.609 29.184 95.681 34.92 ;
     RECT  95.497 88.752 95.749 89.832 ;
     RECT  94.504 91.152 95.749 95.784 ;
     RECT  94.889 97.92 95.749 99.528 ;
     RECT  95.749 88.752 95.785 95.784 ;
     RECT  95.749 97.44 95.785 99.528 ;
     RECT  95.681 29.28 95.789 34.92 ;
     RECT  95.596 44.064 95.789 44.616 ;
     RECT  95.497 48.96 95.789 68.088 ;
     RECT  95.785 88.752 95.789 99.528 ;
     RECT  95.537 105.408 95.789 105.432 ;
     RECT  94.889 3.072 95.795 4.824 ;
     RECT  94.504 82.32 95.825 87.72 ;
     RECT  94.781 77.088 95.857 77.208 ;
     RECT  94.504 78.768 95.857 81.144 ;
     RECT  94.504 101.376 95.857 101.4 ;
     RECT  95.321 6.096 95.861 6.888 ;
     RECT  95.569 8.208 95.861 11.256 ;
     RECT  95.789 68.064 95.861 68.088 ;
     RECT  95.465 14.832 95.929 15.336 ;
     RECT  95.171 16.512 95.929 17.256 ;
     RECT  95.789 91.872 95.965 99.528 ;
     RECT  95.825 82.512 95.969 87.72 ;
     RECT  95.537 106.416 96.005 106.584 ;
     RECT  94.961 36.912 96.041 42.744 ;
     RECT  94.997 69.408 96.041 72.216 ;
     RECT  95.609 35.904 96.073 35.928 ;
     RECT  96.041 36.912 96.073 38.856 ;
     RECT  96.073 35.904 96.113 38.856 ;
     RECT  95.533 22.56 96.145 27.72 ;
     RECT  95.857 101.088 96.145 101.4 ;
     RECT  95.965 91.872 96.185 99.96 ;
     RECT  95.795 3.072 96.253 4.536 ;
     RECT  96.185 97.92 96.253 99.96 ;
     RECT  96.145 22.176 96.275 28.2 ;
     RECT  96.253 2.256 96.337 4.536 ;
     RECT  95.789 44.064 96.361 44.328 ;
     RECT  96.275 22.512 96.401 28.2 ;
     RECT  95.857 77.088 96.433 81.144 ;
     RECT  96.041 69.408 96.509 71.736 ;
     RECT  94.504 73.392 96.509 75.144 ;
     RECT  95.861 8.496 96.545 11.256 ;
     RECT  96.113 36.384 96.545 38.856 ;
     RECT  96.337 3.072 96.581 4.536 ;
     RECT  95.465 13.392 96.613 13.464 ;
     RECT  95.645 18.624 96.613 19.128 ;
     RECT  96.433 76.368 96.617 81.144 ;
     RECT  95.789 88.752 96.617 90.696 ;
     RECT  95.789 32.448 96.653 34.92 ;
     RECT  95.861 6.096 96.661 6.36 ;
     RECT  96.545 9.072 96.709 11.256 ;
     RECT  95.929 14.832 96.725 17.256 ;
     RECT  96.661 5.952 96.748 6.36 ;
     RECT  96.725 16.512 96.757 17.256 ;
     RECT  96.613 18.624 96.757 19.368 ;
     RECT  95.789 48.96 96.793 67.08 ;
     RECT  95.789 29.28 96.833 31.416 ;
     RECT  96.613 13.392 96.853 13.608 ;
     RECT  96.833 29.28 96.853 31.128 ;
     RECT  96.853 13.104 96.86 13.608 ;
     RECT  96.853 28.944 96.899 31.128 ;
     RECT  96.86 12.768 96.901 13.608 ;
     RECT  95.596 45.792 96.901 47.496 ;
     RECT  96.253 97.92 96.937 100.104 ;
     RECT  96.145 101.088 96.937 101.88 ;
     RECT  96.709 9.072 96.941 11.352 ;
     RECT  96.937 97.92 96.956 101.88 ;
     RECT  94.504 102.912 96.956 103.704 ;
     RECT  96.956 97.92 96.977 103.704 ;
     RECT  96.901 12.336 97.009 13.608 ;
     RECT  96.977 100.896 97.013 103.704 ;
     RECT  96.005 106.512 97.013 106.584 ;
     RECT  97.013 102.288 97.043 103.704 ;
     RECT  96.901 45.744 97.045 47.496 ;
     RECT  96.725 14.832 97.049 15.336 ;
     RECT  96.757 16.512 97.049 19.368 ;
     RECT  96.401 22.512 97.049 27.72 ;
     RECT  96.899 30.624 97.049 31.128 ;
     RECT  95.321 20.352 97.085 21.144 ;
     RECT  96.748 6.048 97.117 6.36 ;
     RECT  96.361 43.776 97.117 44.328 ;
     RECT  97.045 45.552 97.117 47.688 ;
     RECT  96.617 76.368 97.157 80.904 ;
     RECT  96.041 41.376 97.189 42.744 ;
     RECT  97.117 43.776 97.189 47.688 ;
     RECT  95.677 107.664 97.189 107.688 ;
     RECT  96.509 69.408 97.193 70.824 ;
     RECT  97.157 78.576 97.193 80.904 ;
     RECT  97.009 11.376 97.225 13.608 ;
     RECT  97.049 14.832 97.225 15.192 ;
     RECT  95.969 84.912 97.225 87.72 ;
     RECT  97.225 11.376 97.229 15.192 ;
     RECT  97.157 76.368 97.229 77.256 ;
     RECT  96.185 91.872 97.229 96.888 ;
     RECT  97.189 106.752 97.229 107.688 ;
     RECT  95.969 82.512 97.237 83.832 ;
     RECT  97.225 84.912 97.237 87.816 ;
     RECT  97.237 82.512 97.309 87.816 ;
     RECT  96.653 32.448 97.333 34.488 ;
     RECT  96.617 89.04 97.337 90.696 ;
     RECT  97.043 102.672 97.369 103.704 ;
     RECT  97.049 16.512 97.373 18.888 ;
     RECT  97.229 96.864 97.405 96.888 ;
     RECT  96.977 97.92 97.405 99.72 ;
     RECT  97.141 68.4 97.441 68.424 ;
     RECT  97.193 69.408 97.441 70.728 ;
     RECT  96.509 73.392 97.477 73.416 ;
     RECT  96.509 74.4 97.477 75.144 ;
     RECT  96.041 39.888 97.481 39.912 ;
     RECT  97.369 102.672 97.481 103.752 ;
     RECT  97.477 73.392 97.523 75.144 ;
     RECT  97.049 26.832 97.549 27.72 ;
     RECT  97.481 102.912 97.553 103.752 ;
     RECT  96.545 36.384 97.589 38.232 ;
     RECT  97.229 76.368 97.589 77.208 ;
     RECT  97.049 22.512 97.625 25.704 ;
     RECT  97.405 96.864 97.625 99.72 ;
     RECT  97.477 72.288 97.657 72.312 ;
     RECT  97.523 74.112 97.697 75.144 ;
     RECT  97.309 82.512 97.697 87.72 ;
     RECT  97.189 41.376 97.729 47.688 ;
     RECT  97.229 11.952 97.733 14.856 ;
     RECT  97.589 37.152 97.733 38.232 ;
     RECT  97.657 71.952 97.733 72.312 ;
     RECT  96.581 3.072 97.765 4.152 ;
     RECT  97.733 11.952 97.769 13.656 ;
     RECT  97.729 40.992 97.805 47.688 ;
     RECT  97.765 2.784 97.82 4.152 ;
     RECT  97.805 40.992 97.945 43.08 ;
     RECT  97.697 74.496 97.981 75.144 ;
     RECT  97.589 76.368 97.981 76.392 ;
     RECT  97.733 37.536 98.005 38.232 ;
     RECT  97.049 30.912 98.017 31.128 ;
     RECT  97.229 91.872 98.017 95.64 ;
     RECT  97.697 82.656 98.021 86.664 ;
     RECT  97.013 100.896 98.021 101.064 ;
     RECT  97.82 2.784 98.053 4.632 ;
     RECT  97.945 105.696 98.053 105.72 ;
     RECT  97.229 106.752 98.053 107.544 ;
     RECT  97.441 68.4 98.057 70.728 ;
     RECT  97.085 20.352 98.089 21.048 ;
     RECT  98.017 30.816 98.089 31.128 ;
     RECT  97.553 103.104 98.099 103.752 ;
     RECT  97.337 89.04 98.125 89.88 ;
     RECT  96.899 28.944 98.129 29.304 ;
     RECT  98.005 37.536 98.129 39.192 ;
     RECT  97.945 40.704 98.129 43.08 ;
     RECT  96.793 48.96 98.129 67.368 ;
     RECT  97.625 99.168 98.129 99.72 ;
     RECT  98.053 105.696 98.129 107.544 ;
     RECT  98.053 2.784 98.161 4.968 ;
     RECT  98.099 103.488 98.161 103.752 ;
     RECT  98.129 105.696 98.161 106.392 ;
     RECT  97.193 78.768 98.237 80.904 ;
     RECT  98.129 53.04 98.269 67.368 ;
     RECT  98.057 68.4 98.269 68.664 ;
     RECT  98.129 40.704 98.273 42.696 ;
     RECT  97.117 6.048 98.293 6.408 ;
     RECT  96.289 7.44 98.293 7.464 ;
     RECT  97.333 32.304 98.305 34.488 ;
     RECT  97.805 44.4 98.305 47.688 ;
     RECT  96.941 9.072 98.309 10.296 ;
     RECT  98.293 6.048 98.38 7.464 ;
     RECT  97.373 16.656 98.381 18.888 ;
     RECT  98.309 9.216 98.413 10.296 ;
     RECT  97.549 26.832 98.417 27.96 ;
     RECT  97.697 87.696 98.449 87.72 ;
     RECT  97.981 74.496 98.453 76.392 ;
     RECT  98.161 103.488 98.483 106.392 ;
     RECT  98.057 69.696 98.485 70.728 ;
     RECT  97.733 71.952 98.485 71.976 ;
     RECT  98.237 78.768 98.485 80.376 ;
     RECT  98.129 48.96 98.489 52.056 ;
     RECT  98.449 87.696 98.489 87.912 ;
     RECT  98.483 105.696 98.489 106.392 ;
     RECT  98.413 9.216 98.521 10.872 ;
     RECT  98.129 38.208 98.521 39.192 ;
     RECT  98.453 74.496 98.531 76.104 ;
     RECT  98.485 78.096 98.533 80.376 ;
     RECT  98.305 32.304 98.557 34.824 ;
     RECT  98.273 41.376 98.561 42.696 ;
     RECT  98.381 17.664 98.593 18.888 ;
     RECT  97.625 22.56 98.593 25.704 ;
     RECT  98.017 91.392 98.593 95.64 ;
     RECT  98.489 105.696 98.597 106.056 ;
     RECT  98.521 9.216 98.605 10.968 ;
     RECT  98.485 69.696 98.633 71.976 ;
     RECT  98.533 78.096 98.633 79.224 ;
     RECT  98.593 91.392 98.633 95.784 ;
     RECT  98.129 29.28 98.665 29.304 ;
     RECT  98.089 30.336 98.665 31.128 ;
     RECT  98.665 29.28 98.701 31.128 ;
     RECT  98.557 32.208 98.701 34.824 ;
     RECT  98.125 88.944 98.725 89.88 ;
     RECT  97.733 14.832 98.737 14.856 ;
     RECT  98.377 81.648 98.773 81.672 ;
     RECT  98.021 82.656 98.773 84.312 ;
     RECT  98.305 44.4 98.809 47.88 ;
     RECT  98.593 22.56 98.845 25.8 ;
     RECT  98.417 26.832 98.845 27.864 ;
     RECT  98.593 17.664 98.881 18.984 ;
     RECT  98.531 74.496 98.917 75.096 ;
     RECT  97.967 72.96 98.953 72.984 ;
     RECT  98.917 74.352 98.953 75.096 ;
     RECT  98.881 17.664 98.989 19.32 ;
     RECT  98.773 81.648 98.989 84.312 ;
     RECT  98.021 85.776 98.989 86.664 ;
     RECT  98.725 88.944 99.025 90.264 ;
     RECT  98.633 91.392 99.025 94.584 ;
     RECT  98.633 95.616 99.025 95.784 ;
     RECT  97.625 96.864 99.025 98.184 ;
     RECT  98.809 100.8 99.025 100.824 ;
     RECT  98.633 69.792 99.061 71.976 ;
     RECT  98.953 72.96 99.061 75.096 ;
     RECT  98.809 44.112 99.133 47.88 ;
     RECT  99.025 95.616 99.133 98.184 ;
     RECT  98.129 99.696 99.133 99.72 ;
     RECT  98.089 20.352 99.157 21.432 ;
     RECT  98.845 22.56 99.157 27.864 ;
     RECT  99.133 44.112 99.241 47.976 ;
     RECT  98.701 29.28 99.277 34.824 ;
     RECT  99.133 36.816 99.277 36.84 ;
     RECT  98.521 38.208 99.277 40.056 ;
     RECT  98.161 2.784 99.349 5.064 ;
     RECT  98.38 6.048 99.349 6.408 ;
     RECT  98.269 53.04 99.349 68.664 ;
     RECT  97.769 12.48 99.493 13.656 ;
     RECT  99.277 29.28 99.493 35.448 ;
     RECT  99.349 2.784 99.565 6.408 ;
     RECT  98.38 7.44 99.565 7.464 ;
     RECT  99.565 2.784 99.608 7.464 ;
     RECT  98.605 9.216 99.608 10.632 ;
     RECT  99.493 12.048 99.608 13.656 ;
     RECT  98.737 14.736 99.608 14.856 ;
     RECT  98.381 16.656 99.608 16.68 ;
     RECT  98.989 17.664 99.608 19.368 ;
     RECT  99.157 20.352 99.608 27.864 ;
     RECT  99.493 29.232 99.608 35.448 ;
     RECT  99.277 36.816 99.608 40.056 ;
     RECT  98.561 41.376 99.608 42.216 ;
     RECT  99.241 43.344 99.608 47.976 ;
     RECT  98.489 48.96 99.608 49.272 ;
     RECT  98.489 50.64 99.608 52.056 ;
     RECT  99.349 53.04 99.608 68.76 ;
     RECT  99.061 69.792 99.608 75.096 ;
     RECT  98.531 76.08 99.608 76.104 ;
     RECT  98.917 77.28 99.608 77.304 ;
     RECT  98.633 78.624 99.608 79.224 ;
     RECT  98.533 80.352 99.608 80.376 ;
     RECT  98.989 81.648 99.608 86.664 ;
     RECT  98.489 87.888 99.608 87.912 ;
     RECT  99.025 88.944 99.608 94.584 ;
     RECT  99.133 95.616 99.608 99.72 ;
     RECT  99.025 100.8 99.608 101.448 ;
     RECT  98.483 103.488 99.608 104.616 ;
     RECT  98.597 105.696 99.608 106.008 ;
     RECT  98.129 107.52 99.608 107.544 ;
     RECT  99.608 2.148 99.712 108.012 ;
     RECT  99.712 2.418 99.904 107.742 ;
     RECT  99.904 89.472 99.929 93.336 ;
     RECT  99.904 77.28 100.073 77.592 ;
     RECT  99.904 17.712 100.109 20.136 ;
     RECT  99.904 82.272 100.109 84.888 ;
     RECT  99.904 104.592 100.109 106.008 ;
     RECT  99.929 89.472 100.115 90.888 ;
     RECT  100.109 17.808 100.145 20.136 ;
     RECT  100.109 104.784 100.145 106.008 ;
     RECT  100.109 82.56 100.211 84.888 ;
     RECT  99.904 100.8 100.217 100.824 ;
     RECT  99.904 32.448 100.253 49.56 ;
     RECT  99.904 27.072 100.307 31.128 ;
     RECT  100.253 36.048 100.325 49.56 ;
     RECT  100.145 18.144 100.361 20.136 ;
     RECT  99.904 51.168 100.361 51.384 ;
     RECT  100.361 18.432 100.396 20.136 ;
     RECT  100.325 36.048 100.433 47.784 ;
     RECT  100.073 77.568 100.433 77.592 ;
     RECT  100.211 82.56 100.433 84.312 ;
     RECT  99.904 95.712 100.433 99.096 ;
     RECT  100.433 38.256 100.469 47.784 ;
     RECT  99.904 101.856 100.469 103.272 ;
     RECT  100.433 96.288 100.505 99.096 ;
     RECT  99.904 74.64 100.541 75 ;
     RECT  99.904 2.784 100.577 12.744 ;
     RECT  100.396 18.96 100.577 20.136 ;
     RECT  100.577 3.264 100.595 12.744 ;
     RECT  100.595 3.264 100.636 6.072 ;
     RECT  100.115 89.472 100.649 90.072 ;
     RECT  99.904 16.272 100.721 16.68 ;
     RECT  100.325 48.768 100.721 49.56 ;
     RECT  99.904 80.784 100.757 80.808 ;
     RECT  99.904 67.92 100.885 73.656 ;
     RECT  99.904 21.408 100.897 23.928 ;
     RECT  99.904 25.44 100.897 25.464 ;
     RECT  100.145 105.408 100.901 106.008 ;
     RECT  100.595 7.152 100.937 12.744 ;
     RECT  100.577 19.2 100.937 20.136 ;
     RECT  99.904 52.56 100.937 63.144 ;
     RECT  100.307 28.992 100.94 31.128 ;
     RECT  100.253 32.448 100.94 34.536 ;
     RECT  99.904 86.064 100.94 86.088 ;
     RECT  100.721 16.272 100.969 16.296 ;
     RECT  100.937 54.192 100.969 63.144 ;
     RECT  99.904 64.176 100.969 66.744 ;
     RECT  100.937 9.792 100.973 12.744 ;
     RECT  100.469 39.216 100.973 47.784 ;
     RECT  100.892 88.896 100.979 88.92 ;
     RECT  100.94 85.824 100.981 86.088 ;
     RECT  100.969 87.216 100.981 87.24 ;
     RECT  100.937 7.152 101.009 8.712 ;
     RECT  100.94 28.992 101.009 34.536 ;
     RECT  101.009 31.824 101.027 34.536 ;
     RECT  100.885 67.92 101.027 74.616 ;
     RECT  100.981 85.824 101.027 87.24 ;
     RECT  100.307 27.072 101.041 27.96 ;
     RECT  100.973 9.792 101.045 10.152 ;
     RECT  100.897 21.408 101.045 25.464 ;
     RECT  101.009 28.992 101.045 30.648 ;
     RECT  100.973 42.144 101.045 43.368 ;
     RECT  100.973 45.072 101.045 47.784 ;
     RECT  100.901 105.408 101.045 105.912 ;
     RECT  99.904 107.52 101.045 107.544 ;
     RECT  101.027 86.592 101.053 87.24 ;
     RECT  101.045 21.408 101.123 25.128 ;
     RECT  101.045 45.552 101.153 47.784 ;
     RECT  101.045 9.792 101.189 10.104 ;
     RECT  101.045 42.144 101.189 43.176 ;
     RECT  99.904 14.832 101.225 14.856 ;
     RECT  100.969 54.192 101.261 66.744 ;
     RECT  101.027 67.92 101.261 72.264 ;
     RECT  101.113 80.88 101.261 80.904 ;
     RECT  101.041 26.544 101.293 27.96 ;
     RECT  100.721 49.056 101.293 49.56 ;
     RECT  100.361 51.36 101.293 51.384 ;
     RECT  100.937 52.56 101.293 53.112 ;
     RECT  101.189 9.888 101.297 10.104 ;
     RECT  101.027 31.872 101.329 34.536 ;
     RECT  101.293 51.36 101.333 53.112 ;
     RECT  100.636 3.264 101.369 3.336 ;
     RECT  100.433 36.048 101.401 36.072 ;
     RECT  100.433 37.056 101.401 37.08 ;
     RECT  101.153 47.616 101.401 47.784 ;
     RECT  100.649 90.048 101.401 90.072 ;
     RECT  100.636 4.368 101.441 6.072 ;
     RECT  101.123 21.648 101.441 25.128 ;
     RECT  101.441 22.8 101.459 25.128 ;
     RECT  100.505 97.104 101.545 99.096 ;
     RECT  101.297 9.888 101.549 9.912 ;
     RECT  100.937 20.016 101.549 20.136 ;
     RECT  101.459 22.8 101.549 24.792 ;
     RECT  101.261 67.92 101.549 67.944 ;
     RECT  100.469 101.856 101.581 101.88 ;
     RECT  101.549 20.016 101.585 20.04 ;
     RECT  100.969 75.696 101.605 75.816 ;
     RECT  100.433 82.56 101.617 83.256 ;
     RECT  101.441 6.048 101.621 6.072 ;
     RECT  101.605 75.696 101.653 76.728 ;
     RECT  101.441 21.648 101.657 21.768 ;
     RECT  101.333 51.36 101.657 52.056 ;
     RECT  101.027 73.632 101.657 74.616 ;
     RECT  100.969 15.936 101.693 16.296 ;
     RECT  101.293 49.056 101.693 50.376 ;
     RECT  101.261 54.192 101.765 66.456 ;
     RECT  101.009 7.152 101.833 7.176 ;
     RECT  101.617 82.128 101.833 83.256 ;
     RECT  101.189 42.192 101.837 43.176 ;
     RECT  99.904 78.624 101.9 79.8 ;
     RECT  101.329 31.872 101.909 34.776 ;
     RECT  101.473 95.136 101.941 95.16 ;
     RECT  101.765 54.192 101.945 65.976 ;
     RECT  101.9 78.528 101.977 79.8 ;
     RECT  101.653 75.696 101.987 77.448 ;
     RECT  101.977 78.432 101.987 79.8 ;
     RECT  100.973 39.216 102.017 41.112 ;
     RECT  101.045 28.992 102.049 29.736 ;
     RECT  101.945 54.192 102.053 63.288 ;
     RECT  101.833 81.312 102.085 83.256 ;
     RECT  100.433 84.288 102.085 84.312 ;
     RECT  101.401 90.048 102.121 90.6 ;
     RECT  101.657 21.648 102.157 21.672 ;
     RECT  102.085 81.312 102.157 84.312 ;
     RECT  101.833 6.432 102.161 7.176 ;
     RECT  102.049 28.992 102.161 30.168 ;
     RECT  101.369 3.264 102.193 3.288 ;
     RECT  102.017 40.56 102.233 41.112 ;
     RECT  101.261 68.928 102.233 70.536 ;
     RECT  101.545 97.104 102.233 99.192 ;
     RECT  101.293 26.208 102.269 27.96 ;
     RECT  101.153 45.552 102.277 46.584 ;
     RECT  101.401 47.616 102.277 47.928 ;
     RECT  101.977 38.16 102.301 38.184 ;
     RECT  102.017 39.216 102.301 39.24 ;
     RECT  102.157 81.312 102.305 84.744 ;
     RECT  102.277 45.552 102.323 47.928 ;
     RECT  102.301 18.96 102.337 18.984 ;
     RECT  101.549 22.8 102.341 24.744 ;
     RECT  102.193 3.168 102.373 3.288 ;
     RECT  101.441 4.368 102.409 4.392 ;
     RECT  100.973 11.232 102.409 12.552 ;
     RECT  101.261 71.76 102.409 72.264 ;
     RECT  101.657 74.352 102.409 74.616 ;
     RECT  101.987 75.696 102.409 76.728 ;
     RECT  99.929 92.256 102.409 93.336 ;
     RECT  102.233 40.56 102.413 41.016 ;
     RECT  101.689 17.616 102.445 17.64 ;
     RECT  101.401 36.048 102.445 37.08 ;
     RECT  102.301 38.16 102.445 39.24 ;
     RECT  102.305 83.088 102.445 84.744 ;
     RECT  101.053 86.592 102.449 86.616 ;
     RECT  101.693 15.936 102.481 15.96 ;
     RECT  102.373 2.832 102.517 3.288 ;
     RECT  102.409 91.92 102.517 93.336 ;
     RECT  102.373 44.16 102.521 44.184 ;
     RECT  102.517 2.592 102.553 3.288 ;
     RECT  102.445 17.616 102.553 17.736 ;
     RECT  102.157 21.552 102.553 21.672 ;
     RECT  101.693 49.2 102.553 50.376 ;
     RECT  101.657 51.36 102.553 51.48 ;
     RECT  101.333 53.088 102.565 53.112 ;
     RECT  100.469 103.248 102.565 103.272 ;
     RECT  102.265 104.784 102.565 104.808 ;
     RECT  101.009 8.688 102.589 8.712 ;
     RECT  102.409 10.8 102.589 12.552 ;
     RECT  102.409 71.76 102.589 72.456 ;
     RECT  102.121 89.712 102.589 90.6 ;
     RECT  102.565 103.248 102.611 104.808 ;
     RECT  101.941 95.136 102.613 96.072 ;
     RECT  102.233 97.104 102.613 98.664 ;
     RECT  102.269 27.168 102.629 27.96 ;
     RECT  102.553 49.2 102.629 51.48 ;
     RECT  102.233 69.552 102.629 70.536 ;
     RECT  101.581 101.712 102.629 101.88 ;
     RECT  102.629 50.352 102.637 51.48 ;
     RECT  102.637 51.36 102.661 51.48 ;
     RECT  102.565 52.704 102.661 53.112 ;
     RECT  102.589 89.472 102.673 90.6 ;
     RECT  102.553 2.592 102.689 3.336 ;
     RECT  101.837 42.288 102.697 43.176 ;
     RECT  102.613 95.136 102.7 98.664 ;
     RECT  102.589 71.52 102.701 72.456 ;
     RECT  102.409 4.368 102.733 5.112 ;
     RECT  102.161 6.432 102.733 6.936 ;
     RECT  102.049 100.224 102.733 100.248 ;
     RECT  101.045 105.888 102.733 105.912 ;
     RECT  102.625 106.992 102.733 107.016 ;
     RECT  102.689 2.256 102.773 3.336 ;
     RECT  102.733 4.368 102.773 6.936 ;
     RECT  102.553 17.04 102.805 17.736 ;
     RECT  102.337 18.768 102.805 18.984 ;
     RECT  102.481 15.168 102.809 15.96 ;
     RECT  102.517 25.632 102.809 25.656 ;
     RECT  102.733 105.888 102.809 107.016 ;
     RECT  102.161 29.28 102.841 30.168 ;
     RECT  102.661 51.36 102.841 53.112 ;
     RECT  102.053 54.192 102.841 63.24 ;
     RECT  101.945 64.416 102.845 65.976 ;
     RECT  102.773 4.368 102.881 5.64 ;
     RECT  102.845 64.416 102.881 64.44 ;
     RECT  101.987 78.432 102.917 79.08 ;
     RECT  102.589 7.968 102.949 8.712 ;
     RECT  102.845 65.952 102.949 65.976 ;
     RECT  102.773 2.592 102.953 3.336 ;
     RECT  102.773 6.912 102.989 6.936 ;
     RECT  102.445 36.048 102.989 39.24 ;
     RECT  102.949 7.968 103.021 9.672 ;
     RECT  102.589 10.704 103.021 12.552 ;
     RECT  102.517 91.872 103.021 93.336 ;
     RECT  102.7 95.136 103.025 98.52 ;
     RECT  102.953 2.88 103.061 3.288 ;
     RECT  102.841 29.28 103.085 30.84 ;
     RECT  101.909 31.872 103.085 31.896 ;
     RECT  102.373 67.776 103.093 67.8 ;
     RECT  102.323 45.744 103.129 47.928 ;
     RECT  102.445 83.088 103.141 84.936 ;
     RECT  103.021 7.968 103.169 12.552 ;
     RECT  103.141 83.088 103.187 85.656 ;
     RECT  103.169 7.968 103.205 12.072 ;
     RECT  102.611 103.296 103.205 104.184 ;
     RECT  102.841 51.36 103.241 63.24 ;
     RECT  102.409 74.352 103.241 76.728 ;
     RECT  103.187 85.632 103.241 85.656 ;
     RECT  102.445 87.792 103.273 87.816 ;
     RECT  103.093 67.248 103.277 67.8 ;
     RECT  103.085 29.28 103.309 31.896 ;
     RECT  101.909 33.072 103.309 34.776 ;
     RECT  102.949 65.952 103.309 66.12 ;
     RECT  103.277 67.248 103.309 67.272 ;
     RECT  103.241 54.096 103.313 63.24 ;
     RECT  102.305 81.312 103.349 81.768 ;
     RECT  102.413 40.56 103.381 40.584 ;
     RECT  102.629 49.2 103.417 49.224 ;
     RECT  103.205 8.688 103.421 12.072 ;
     RECT  102.733 99.696 103.429 100.248 ;
     RECT  102.629 27.168 103.453 27.384 ;
     RECT  103.381 40.56 103.453 40.728 ;
     RECT  102.697 42.288 103.453 43.32 ;
     RECT  102.673 89.712 103.453 90.6 ;
     RECT  102.637 50.352 103.457 50.376 ;
     RECT  102.701 72.432 103.457 72.456 ;
     RECT  103.021 91.872 103.489 93.432 ;
     RECT  103.241 51.36 103.493 53.112 ;
     RECT  103.187 83.088 103.493 84.648 ;
     RECT  103.025 95.52 103.493 98.52 ;
     RECT  103.453 40.56 103.565 43.32 ;
     RECT  102.553 20.592 103.58 21.672 ;
     RECT  102.341 22.8 103.58 24.36 ;
     RECT  102.989 39.216 103.597 39.24 ;
     RECT  103.565 40.56 103.597 40.872 ;
     RECT  102.805 17.04 103.628 18.984 ;
     RECT  102.809 105.888 103.637 106.872 ;
     RECT  103.309 29.28 103.673 34.776 ;
     RECT  103.309 65.952 103.673 67.272 ;
     RECT  103.673 29.28 103.705 29.64 ;
     RECT  102.989 36.048 103.705 38.232 ;
     RECT  103.669 76.992 103.705 77.016 ;
     RECT  102.917 78.432 103.705 79.032 ;
     RECT  102.629 69.552 103.709 70.296 ;
     RECT  103.628 16.176 103.715 18.984 ;
     RECT  103.58 20.592 103.715 24.36 ;
     RECT  103.453 26.832 103.717 27.384 ;
     RECT  103.705 28.416 103.717 29.64 ;
     RECT  103.717 26.832 103.745 29.64 ;
     RECT  103.673 30.816 103.777 34.776 ;
     RECT  103.705 36 103.777 38.232 ;
     RECT  103.493 95.52 103.811 98.088 ;
     RECT  103.429 99.696 103.813 100.344 ;
     RECT  102.629 101.856 103.813 101.88 ;
     RECT  103.129 45.744 103.817 47.976 ;
     RECT  103.493 83.088 103.817 84.312 ;
     RECT  103.205 103.296 103.817 104.136 ;
     RECT  103.525 82.032 103.849 82.056 ;
     RECT  103.241 74.352 103.852 75.96 ;
     RECT  103.852 74.304 103.853 75.96 ;
     RECT  103.705 76.992 103.853 79.032 ;
     RECT  103.813 99.168 103.859 100.344 ;
     RECT  103.811 97.248 103.889 98.088 ;
     RECT  103.813 13.584 103.909 13.608 ;
     RECT  103.421 8.688 103.925 10.824 ;
     RECT  103.565 42.288 103.957 43.32 ;
     RECT  103.909 13.584 103.996 13.992 ;
     RECT  102.881 5.616 103.997 5.64 ;
     RECT  103.745 26.832 103.997 29.544 ;
     RECT  103.925 10.32 104.033 10.824 ;
     RECT  103.453 89.712 104.065 90.84 ;
     RECT  103.489 91.872 104.065 94.296 ;
     RECT  103.813 101.472 104.065 101.88 ;
     RECT  103.061 3.024 104.101 3.288 ;
     RECT  102.809 15.168 104.101 15.192 ;
     RECT  103.715 20.592 104.137 21.144 ;
     RECT  104.101 2.784 104.209 3.288 ;
     RECT  102.881 4.368 104.209 4.584 ;
     RECT  103.417 48.96 104.209 49.224 ;
     RECT  103.313 54.432 104.245 63.24 ;
     RECT  103.273 87.072 104.245 87.816 ;
     RECT  104.065 89.712 104.273 94.296 ;
     RECT  103.957 42.288 104.281 43.368 ;
     RECT  102.949 44.448 104.281 44.472 ;
     RECT  103.925 8.688 104.389 9.288 ;
     RECT  103.421 11.952 104.389 12.072 ;
     RECT  103.715 22.176 104.389 24.36 ;
     RECT  103.817 45.744 104.389 46.056 ;
     RECT  103.493 52.704 104.425 53.112 ;
     RECT  104.245 54.432 104.425 63.864 ;
     RECT  103.817 47.136 104.461 47.976 ;
     RECT  104.209 48.96 104.461 50.184 ;
     RECT  104.281 86.016 104.485 86.04 ;
     RECT  104.245 87.024 104.485 87.816 ;
     RECT  104.389 22.176 104.533 24.504 ;
     RECT  103.817 83.76 104.641 84.312 ;
     RECT  103.817 103.344 104.677 104.136 ;
     RECT  104.137 20.304 104.713 21.144 ;
     RECT  104.569 25.824 104.725 25.848 ;
     RECT  104.684 64.944 104.725 64.968 ;
     RECT  103.673 65.952 104.725 66.12 ;
     RECT  104.725 64.944 104.773 66.12 ;
     RECT  103.673 67.248 104.773 67.272 ;
     RECT  103.997 28.416 104.785 29.544 ;
     RECT  104.389 8.496 104.821 9.288 ;
     RECT  104.533 22.176 104.857 24.648 ;
     RECT  104.725 25.728 104.857 25.848 ;
     RECT  104.389 45.648 104.857 46.056 ;
     RECT  104.773 64.944 104.857 67.8 ;
     RECT  103.853 75.744 104.857 75.96 ;
     RECT  104.101 15.024 104.869 15.192 ;
     RECT  103.715 16.272 104.869 18.984 ;
     RECT  104.245 71.952 104.869 71.976 ;
     RECT  104.281 42.288 104.893 44.472 ;
     RECT  104.857 45.552 104.893 46.056 ;
     RECT  103.849 82.032 104.893 82.536 ;
     RECT  104.785 28.416 104.965 29.784 ;
     RECT  103.777 30.816 104.965 38.232 ;
     RECT  103.853 74.304 104.965 74.328 ;
     RECT  103.921 80.832 104.965 80.856 ;
     RECT  103.859 100.224 104.965 100.344 ;
     RECT  104.065 101.472 104.965 102.072 ;
     RECT  104.857 64.944 105.001 67.848 ;
     RECT  104.209 2.784 105.008 4.824 ;
     RECT  104.101 6.624 105.008 6.648 ;
     RECT  104.821 8.016 105.008 9.288 ;
     RECT  104.033 10.32 105.008 10.728 ;
     RECT  104.389 11.952 105.008 12.552 ;
     RECT  103.996 13.584 105.008 13.608 ;
     RECT  104.869 15.024 105.008 18.984 ;
     RECT  104.713 20.16 105.008 21.144 ;
     RECT  104.857 22.176 105.008 25.848 ;
     RECT  103.997 26.832 105.008 27.24 ;
     RECT  104.965 28.416 105.008 38.232 ;
     RECT  103.597 39.216 105.008 40.872 ;
     RECT  104.893 42.288 105.008 46.056 ;
     RECT  104.461 47.136 105.008 50.184 ;
     RECT  103.493 51.36 105.008 51.384 ;
     RECT  104.425 52.704 105.008 63.864 ;
     RECT  105.001 64.944 105.008 67.896 ;
     RECT  103.709 70.272 105.008 70.296 ;
     RECT  104.869 71.952 105.008 72.6 ;
     RECT  104.965 73.872 105.008 74.328 ;
     RECT  104.857 75.744 105.008 76.008 ;
     RECT  103.853 76.992 105.008 78.936 ;
     RECT  104.965 80.592 105.008 80.856 ;
     RECT  104.893 81.936 105.008 82.536 ;
     RECT  104.641 83.76 105.008 84.552 ;
     RECT  104.485 86.016 105.008 87.816 ;
     RECT  104.273 88.896 105.008 94.296 ;
     RECT  103.811 95.52 105.008 95.928 ;
     RECT  103.889 98.064 105.008 98.088 ;
     RECT  103.859 99.168 105.008 99.192 ;
     RECT  104.965 100.224 105.008 102.072 ;
     RECT  104.677 103.344 105.008 104.712 ;
     RECT  103.637 106.608 105.008 106.872 ;
     RECT  105.008 2.148 105.112 108.012 ;
     RECT  105.112 2.418 105.304 107.742 ;
     RECT  105.304 12 105.365 13.944 ;
     RECT  105.304 15.024 105.365 17.64 ;
     RECT  105.304 22.752 105.365 25.848 ;
     RECT  105.304 40.848 105.365 45.912 ;
     RECT  105.304 27.936 105.401 30.168 ;
     RECT  105.304 34.752 105.401 37.08 ;
     RECT  105.365 12 105.437 13.608 ;
     RECT  105.365 40.848 105.443 43.656 ;
     RECT  105.304 2.784 105.473 3.624 ;
     RECT  105.304 8.016 105.473 9.384 ;
     RECT  105.365 15.024 105.473 17.448 ;
     RECT  105.365 22.8 105.473 25.848 ;
     RECT  105.304 106.704 105.473 106.728 ;
     RECT  105.304 77.952 105.509 78.936 ;
     RECT  105.304 95.664 105.509 96.696 ;
     RECT  105.473 2.784 105.545 2.808 ;
     RECT  105.401 29.76 105.581 30.168 ;
     RECT  105.304 50.688 105.617 66.552 ;
     RECT  105.304 80.64 105.653 80.904 ;
     RECT  105.437 13.152 105.689 13.608 ;
     RECT  105.443 40.848 105.689 40.872 ;
     RECT  105.304 93.312 105.689 94.056 ;
     RECT  105.473 8.544 105.724 9.384 ;
     RECT  105.437 12 105.725 12.024 ;
     RECT  105.617 63.84 105.725 66.552 ;
     RECT  105.304 99.744 105.761 100.104 ;
     RECT  105.304 104.88 105.797 104.904 ;
     RECT  105.617 50.688 105.82 62.712 ;
     RECT  105.304 10.56 105.905 10.728 ;
     RECT  105.304 47.424 105.941 48.648 ;
     RECT  105.304 38.112 105.977 39.816 ;
     RECT  105.401 34.752 106.013 36.936 ;
     RECT  105.725 64.128 106.013 66.552 ;
     RECT  105.304 84.192 106.013 87.384 ;
     RECT  105.581 30.144 106.049 30.168 ;
     RECT  105.653 80.784 106.049 80.904 ;
     RECT  105.304 81.936 106.049 82.632 ;
     RECT  105.689 93.312 106.049 93.768 ;
     RECT  105.304 6.624 106.085 6.648 ;
     RECT  105.304 31.728 106.121 33.672 ;
     RECT  105.304 73.872 106.165 74.328 ;
     RECT  106.049 80.832 106.193 80.904 ;
     RECT  105.724 8.544 106.229 9.096 ;
     RECT  105.304 71.616 106.297 71.976 ;
     RECT  105.473 23.664 106.301 25.848 ;
     RECT  105.401 27.936 106.301 28.44 ;
     RECT  105.304 92.16 106.301 92.184 ;
     RECT  105.473 15.168 106.307 17.448 ;
     RECT  105.509 78.384 106.369 78.936 ;
     RECT  106.121 31.728 106.373 33.096 ;
     RECT  105.304 98.064 106.373 98.616 ;
     RECT  105.761 100.08 106.405 100.104 ;
     RECT  106.049 82.272 106.409 82.632 ;
     RECT  106.013 86.544 106.441 87.384 ;
     RECT  106.373 31.728 106.445 33.048 ;
     RECT  105.82 51.36 106.445 62.712 ;
     RECT  106.297 70.896 106.477 71.976 ;
     RECT  106.445 31.728 106.513 32.856 ;
     RECT  105.304 75.696 106.513 76.008 ;
     RECT  106.229 9.072 106.517 9.096 ;
     RECT  106.445 54.624 106.553 62.712 ;
     RECT  106.013 84.192 106.553 85.464 ;
     RECT  106.049 93.312 106.577 93.48 ;
     RECT  106.301 23.664 106.585 24.648 ;
     RECT  106.013 34.752 106.585 35.736 ;
     RECT  106.477 70.656 106.585 71.976 ;
     RECT  106.441 86.544 106.585 87.48 ;
     RECT  106.307 16.8 106.589 17.448 ;
     RECT  106.585 70.416 106.589 71.976 ;
     RECT  106.165 73.872 106.589 74.136 ;
     RECT  106.553 85.152 106.589 85.464 ;
     RECT  106.585 86.544 106.589 88.056 ;
     RECT  105.304 67.824 106.597 68.808 ;
     RECT  106.477 103.728 106.597 103.752 ;
     RECT  106.513 75.696 106.621 76.104 ;
     RECT  106.307 15.168 106.625 15.624 ;
     RECT  106.513 31.248 106.625 32.856 ;
     RECT  105.443 42.816 106.625 43.656 ;
     RECT  106.553 62.496 106.625 62.712 ;
     RECT  106.589 87.36 106.625 88.056 ;
     RECT  106.585 23.328 106.643 24.648 ;
     RECT  106.597 67.824 106.643 69.336 ;
     RECT  106.625 87.456 106.643 88.056 ;
     RECT  106.585 34.656 106.645 35.736 ;
     RECT  106.621 75.456 106.645 76.104 ;
     RECT  106.553 54.624 106.661 61.368 ;
     RECT  106.013 66.528 106.661 66.552 ;
     RECT  106.409 82.272 106.661 82.488 ;
     RECT  106.577 92.88 106.661 93.48 ;
     RECT  105.509 95.712 106.661 96.696 ;
     RECT  106.643 23.328 106.669 23.352 ;
     RECT  106.589 70.416 106.669 70.44 ;
     RECT  106.643 88.032 106.669 88.056 ;
     RECT  106.585 102.576 106.669 102.6 ;
     RECT  106.625 31.248 106.684 31.944 ;
     RECT  106.597 103.728 106.684 103.8 ;
     RECT  106.369 78.384 106.691 79.656 ;
     RECT  106.613 80.928 106.697 80.952 ;
     RECT  106.373 98.592 106.697 98.616 ;
     RECT  106.589 71.616 106.704 71.976 ;
     RECT  106.645 75.456 106.705 76.728 ;
     RECT  105.689 13.152 106.729 13.176 ;
     RECT  106.704 71.952 106.729 71.976 ;
     RECT  106.705 75.936 106.732 76.728 ;
     RECT  106.645 34.56 106.733 35.736 ;
     RECT  106.297 40.416 106.733 40.44 ;
     RECT  106.013 64.128 106.733 65.496 ;
     RECT  106.729 71.952 106.733 72.648 ;
     RECT  105.977 38.112 106.739 39.384 ;
     RECT  106.691 78.384 106.741 78.696 ;
     RECT  105.905 10.56 106.769 10.584 ;
     RECT  106.684 31.248 106.769 31.752 ;
     RECT  106.625 42.816 106.769 42.84 ;
     RECT  105.941 47.712 106.769 48.648 ;
     RECT  106.445 51.36 106.769 53.112 ;
     RECT  106.733 64.944 106.769 65.496 ;
     RECT  106.589 73.872 106.769 73.896 ;
     RECT  106.739 39.36 106.777 39.384 ;
     RECT  106.741 77.712 106.787 78.696 ;
     RECT  106.769 31.248 106.789 31.272 ;
     RECT  106.589 16.8 106.805 16.872 ;
     RECT  106.769 65.472 106.805 65.496 ;
     RECT  106.597 89.136 106.805 89.16 ;
     RECT  106.684 103.728 106.805 103.752 ;
     RECT  106.787 77.712 106.828 77.736 ;
     RECT  106.789 30.72 106.835 31.272 ;
     RECT  106.733 34.848 106.841 35.736 ;
     RECT  106.733 72.624 106.841 72.648 ;
     RECT  105.304 19.296 106.876 21.144 ;
     RECT  106.835 30.72 106.876 30.744 ;
     RECT  106.301 28.416 106.877 28.44 ;
     RECT  105.365 45.024 106.877 45.912 ;
     RECT  106.769 48.624 106.877 48.648 ;
     RECT  106.643 69.312 106.877 69.336 ;
     RECT  106.661 93.456 106.877 93.48 ;
     RECT  106.661 95.76 106.877 96.696 ;
     RECT  106.405 100.08 106.877 100.296 ;
     RECT  106.729 13.152 106.913 13.512 ;
     RECT  106.625 15.216 106.913 15.624 ;
     RECT  106.876 19.296 106.913 19.608 ;
     RECT  106.876 21.12 106.913 21.144 ;
     RECT  106.643 24.624 106.913 24.648 ;
     RECT  106.301 25.824 106.913 25.848 ;
     RECT  106.841 34.848 106.913 34.872 ;
     RECT  106.013 36.912 106.913 36.936 ;
     RECT  106.877 96.672 106.913 96.696 ;
     RECT  106.913 13.152 106.949 13.272 ;
     RECT  106.877 45.888 106.949 45.912 ;
     RECT  106.625 62.688 106.949 62.712 ;
     RECT  106.913 15.216 106.985 15.24 ;
     RECT  106.805 16.848 106.985 16.872 ;
     RECT  106.913 19.296 106.985 19.32 ;
     RECT  106.661 60.336 107.021 61.368 ;
     RECT  106.643 67.824 107.021 67.848 ;
     RECT  106.739 38.112 107.057 38.136 ;
     RECT  106.732 75.936 107.057 76.104 ;
     RECT  106.877 100.272 107.057 100.296 ;
     RECT  107.021 60.624 107.093 61.368 ;
     RECT  106.949 13.248 107.129 13.272 ;
     RECT  107.057 75.936 107.129 75.96 ;
     RECT  106.661 54.624 107.201 59.208 ;
     RECT  106.589 85.152 107.201 85.176 ;
     RECT  106.769 52.224 107.237 53.112 ;
     RECT  106.873 11.28 107.273 11.304 ;
     RECT  107.201 54.672 107.345 59.208 ;
     RECT  107.237 53.088 107.417 53.112 ;
     RECT  107.345 54.672 107.453 56.616 ;
     RECT  106.661 82.272 107.453 82.296 ;
     RECT  107.345 57.696 107.525 59.208 ;
     RECT  107.453 54.672 107.561 54.744 ;
     RECT  107.525 58.512 107.561 59.208 ;
     RECT  107.561 54.72 107.669 54.744 ;
     RECT  107.453 56.016 107.669 56.616 ;
     RECT  107.093 60.624 107.669 61.224 ;
     RECT  107.669 60.624 108.313 60.84 ;
     RECT  108.313 56.784 108.781 57 ;
     RECT  108.781 56.208 108.817 57 ;
     RECT  108.313 59.952 109.357 60.84 ;
     RECT  108.817 56.208 109.393 57.096 ;
     RECT  109.357 59.952 109.393 61.224 ;
     RECT  108.817 54.864 109.429 54.888 ;
     RECT  109.393 56.016 109.429 57.096 ;
     RECT  107.561 58.608 109.429 58.632 ;
     RECT  109.393 59.76 109.429 61.224 ;
     RECT  109.429 54.48 109.537 54.888 ;
     RECT  109.537 54.48 109.573 54.984 ;
     RECT  109.429 56.016 109.573 61.32 ;
     RECT  109.573 54.48 110.124 61.32 ;
    LAYER M5 ;
     RECT  2.4 2.137 2.52 2.151 ;
     RECT  7.8 2.137 7.92 2.151 ;
     RECT  13.2 2.137 13.32 2.151 ;
     RECT  18.6 2.137 18.72 2.151 ;
     RECT  24 2.137 24.12 2.151 ;
     RECT  29.4 2.137 29.52 2.151 ;
     RECT  34.8 2.137 34.92 2.151 ;
     RECT  40.2 2.137 40.32 2.151 ;
     RECT  45.6 2.137 45.72 2.151 ;
     RECT  51 2.137 51.12 2.151 ;
     RECT  56.4 2.137 56.52 2.151 ;
     RECT  61.8 2.137 61.92 2.151 ;
     RECT  67.2 2.137 67.32 2.151 ;
     RECT  72.6 2.137 72.72 2.151 ;
     RECT  78 2.137 78.12 2.151 ;
     RECT  83.4 2.137 83.52 2.151 ;
     RECT  88.8 2.137 88.92 2.151 ;
     RECT  94.2 2.137 94.32 2.151 ;
     RECT  99.6 2.137 99.72 2.151 ;
     RECT  105 2.137 105.12 2.151 ;
     RECT  34.8 2.151 35.112 2.245 ;
     RECT  51 2.151 51.312 2.341 ;
     RECT  88.8 2.151 89.112 2.629 ;
     RECT  7.8 2.151 8.112 2.773 ;
     RECT  67.2 2.151 67.512 2.773 ;
     RECT  40.2 2.151 40.512 2.869 ;
     RECT  99.6 2.151 99.912 2.869 ;
     RECT  40.08 2.869 40.512 3.059 ;
     RECT  102.72 2.245 102.744 3.203 ;
     RECT  50.112 2.341 51.312 3.299 ;
     RECT  96.288 2.245 96.312 3.299 ;
     RECT  83.4 2.151 83.712 3.301 ;
     RECT  105 2.151 105.312 3.301 ;
     RECT  34.224 2.245 35.112 3.395 ;
     RECT  18.6 2.151 18.912 3.397 ;
     RECT  66.576 2.773 67.512 3.443 ;
     RECT  94.2 2.151 94.512 3.445 ;
     RECT  88.8 2.629 89.448 3.539 ;
     RECT  26.112 2.821 26.136 3.587 ;
     RECT  99.312 2.869 99.912 3.733 ;
     RECT  7.68 2.773 8.112 3.829 ;
     RECT  20.208 2.629 20.232 3.875 ;
     RECT  44.064 2.677 44.088 3.923 ;
     RECT  69.888 2.821 69.912 3.971 ;
     RECT  47.28 2.245 47.304 4.019 ;
     RECT  93.12 2.677 93.144 4.019 ;
     RECT  24 2.151 24.312 4.117 ;
     RECT  74.448 2.245 74.472 4.163 ;
     RECT  24 4.117 24.744 4.213 ;
     RECT  99.216 3.733 99.912 4.259 ;
     RECT  94.2 3.445 95.16 4.261 ;
     RECT  96.672 4.117 96.696 4.261 ;
     RECT  99.6 4.259 99.912 4.261 ;
     RECT  94.2 4.261 96.696 4.307 ;
     RECT  34.704 3.395 35.112 4.355 ;
     RECT  53.28 2.485 53.304 4.355 ;
     RECT  38.64 3.205 38.664 4.403 ;
     RECT  29.4 2.151 29.712 4.405 ;
     RECT  40.2 3.059 40.512 4.501 ;
     RECT  51 3.299 51.312 4.501 ;
     RECT  56.4 2.151 56.712 4.501 ;
     RECT  22.8 3.973 22.824 4.595 ;
     RECT  87.648 2.821 87.672 4.595 ;
     RECT  83.28 3.301 83.712 4.643 ;
     RECT  97.872 3.397 97.896 4.643 ;
     RECT  31.968 4.693 31.992 4.835 ;
     RECT  104.352 3.301 105.312 4.835 ;
     RECT  18.48 3.397 18.912 4.981 ;
     RECT  78 2.151 78.312 5.029 ;
     RECT  67.2 3.443 67.512 5.125 ;
     RECT  61.8 2.151 62.112 5.173 ;
     RECT  17.616 4.981 18.912 5.269 ;
     RECT  61.8 5.173 62.808 5.315 ;
     RECT  56.4 4.501 56.808 5.653 ;
     RECT  29.4 4.405 29.832 5.699 ;
     RECT  58.944 3.925 58.968 5.699 ;
     RECT  5.136 4.549 5.16 5.747 ;
     RECT  9.648 5.077 9.672 5.747 ;
     RECT  99.6 4.261 100.584 5.747 ;
     RECT  50.88 4.501 51.312 5.795 ;
     RECT  82.224 5.557 82.248 5.893 ;
     RECT  94.2 4.307 94.512 5.989 ;
     RECT  40.2 4.501 40.776 6.229 ;
     RECT  95.76 4.307 96.696 6.229 ;
     RECT  43.296 5.029 43.32 6.275 ;
     RECT  86.736 5.605 86.76 6.275 ;
     RECT  91.2 5.077 91.224 6.323 ;
     RECT  17.136 5.269 18.912 6.325 ;
     RECT  39.216 6.229 40.776 6.325 ;
     RECT  13.2 2.151 13.512 6.373 ;
     RECT  95.76 6.229 96.744 6.563 ;
     RECT  13.104 6.373 13.512 6.611 ;
     RECT  17.136 6.325 19.272 6.611 ;
     RECT  39.216 6.325 41.016 6.611 ;
     RECT  7.44 3.829 8.112 6.613 ;
     RECT  54.288 6.229 54.312 6.613 ;
     RECT  39.216 6.611 40.776 6.707 ;
     RECT  99.6 5.747 99.912 6.709 ;
     RECT  54.288 6.613 54.6 6.755 ;
     RECT  66.72 5.125 67.512 6.803 ;
     RECT  2.4 2.151 2.712 6.805 ;
     RECT  65.136 5.173 65.16 6.805 ;
     RECT  64.8 6.805 65.16 6.851 ;
     RECT  82.08 5.893 82.248 6.851 ;
     RECT  5.328 6.757 5.352 6.899 ;
     RECT  7.44 6.613 8.28 6.899 ;
     RECT  17.136 6.611 18.912 6.899 ;
     RECT  24 4.213 25.176 6.899 ;
     RECT  54.288 6.755 54.312 6.899 ;
     RECT  83.4 4.643 83.712 7.381 ;
     RECT  52.416 6.805 52.44 7.427 ;
     RECT  17.568 6.899 18.912 7.475 ;
     RECT  87.696 6.805 87.72 7.475 ;
     RECT  98.304 6.805 98.328 7.475 ;
     RECT  39.216 6.707 40.728 7.765 ;
     RECT  72.6 2.151 72.912 7.861 ;
     RECT  17.568 7.475 17.592 7.909 ;
     RECT  61.8 5.315 62.112 7.909 ;
     RECT  64.8 6.851 64.824 7.909 ;
     RECT  64.656 7.909 64.824 7.955 ;
     RECT  24 6.899 24.312 7.957 ;
     RECT  80.832 7.861 80.856 7.957 ;
     RECT  71.76 7.861 72.912 8.003 ;
     RECT  99.6 6.709 100.584 8.003 ;
     RECT  2.4 6.805 3.144 8.147 ;
     RECT  32.496 7.333 32.52 8.195 ;
     RECT  65.904 7.429 65.928 8.195 ;
     RECT  23.52 7.957 24.312 8.197 ;
     RECT  93.456 5.989 94.512 8.339 ;
     RECT  7.68 6.899 8.28 8.435 ;
     RECT  47.328 7.477 47.352 8.435 ;
     RECT  39.168 7.765 40.728 8.483 ;
     RECT  104.544 4.835 105.312 8.485 ;
     RECT  16.656 7.909 17.592 8.531 ;
     RECT  104.4 8.485 105.312 8.533 ;
     RECT  2.4 8.147 3.048 8.579 ;
     RECT  27.456 7.957 27.48 8.723 ;
     RECT  67.056 6.803 67.512 8.723 ;
     RECT  77.184 5.029 78.312 8.869 ;
     RECT  88.8 3.539 89.112 8.965 ;
     RECT  40.032 8.483 40.728 9.061 ;
     RECT  61.8 7.909 62.76 9.107 ;
     RECT  29.4 5.699 29.712 9.109 ;
     RECT  59.28 8.389 59.304 9.155 ;
     RECT  64.656 7.955 64.68 9.203 ;
     RECT  23.52 8.197 24.504 9.347 ;
     RECT  72.6 8.003 72.912 9.349 ;
     RECT  82.224 6.851 82.248 9.349 ;
     RECT  83.28 7.381 83.712 9.349 ;
     RECT  77.184 8.869 78.648 9.395 ;
     RECT  70.512 5.365 70.536 9.397 ;
     RECT  70.512 9.397 70.68 9.443 ;
     RECT  37.44 8.437 37.464 9.539 ;
     RECT  90.576 8.485 90.6 9.539 ;
     RECT  31.488 5.461 31.512 9.541 ;
     RECT  82.224 9.349 83.712 9.587 ;
     RECT  40.032 9.061 41.016 9.635 ;
     RECT  70.656 9.443 70.68 9.637 ;
     RECT  102.96 9.061 102.984 9.683 ;
     RECT  88.08 8.965 89.112 9.827 ;
     RECT  10.848 9.061 10.872 10.067 ;
     RECT  29.4 9.109 29.88 10.067 ;
     RECT  67.104 8.723 67.512 10.115 ;
     RECT  82.416 9.587 83.712 10.211 ;
     RECT  92.208 9.109 92.232 10.307 ;
     RECT  94.2 8.339 94.512 10.357 ;
     RECT  23.52 9.347 24.408 10.451 ;
     RECT  31.488 9.541 31.752 10.595 ;
     RECT  104.4 8.533 105.672 10.595 ;
     RECT  42.768 9.397 42.792 10.787 ;
     RECT  85.584 10.261 85.608 10.787 ;
     RECT  40.032 9.635 40.728 10.837 ;
     RECT  88.8 9.827 89.112 10.837 ;
     RECT  70.656 9.637 71.256 10.883 ;
     RECT  4.56 7.381 4.584 10.885 ;
     RECT  98.544 9.493 98.568 10.979 ;
     RECT  40.032 10.837 40.824 10.981 ;
     RECT  56.4 5.653 57.96 10.981 ;
     RECT  13.2 6.611 13.512 11.029 ;
     RECT  27.888 9.061 27.912 11.123 ;
     RECT  96.72 6.563 96.744 11.317 ;
     RECT  96.72 11.317 96.888 11.363 ;
     RECT  96.864 11.363 96.888 11.365 ;
     RECT  70.656 10.883 70.68 11.459 ;
     RECT  4.416 10.885 4.584 11.651 ;
     RECT  99.6 8.003 99.912 11.653 ;
     RECT  100.896 10.261 100.92 11.653 ;
     RECT  99.6 11.653 100.92 11.699 ;
     RECT  52.992 11.701 53.016 11.843 ;
     RECT  20.976 10.501 21 11.939 ;
     RECT  18.6 7.475 18.912 11.941 ;
     RECT  47.664 11.125 47.688 11.941 ;
     RECT  51 5.795 51.312 11.941 ;
     RECT  72.6 9.349 73.608 11.941 ;
     RECT  93.888 10.357 94.512 11.941 ;
     RECT  45.6 2.151 45.912 11.989 ;
     RECT  40.032 10.981 41.688 12.323 ;
     RECT  47.328 11.941 47.688 12.419 ;
     RECT  85.776 10.789 85.8 12.469 ;
     RECT  47.664 12.419 47.688 12.515 ;
     RECT  88.8 10.837 90.072 12.515 ;
     RECT  34.8 4.355 35.112 12.517 ;
     RECT  61.8 9.107 62.112 12.517 ;
     RECT  96.864 11.365 97.176 12.517 ;
     RECT  82.464 10.211 83.712 12.563 ;
     RECT  104.4 10.595 105.312 12.563 ;
     RECT  56.016 10.981 57.96 12.755 ;
     RECT  65.808 11.509 65.832 12.755 ;
     RECT  99.6 11.699 100.824 12.755 ;
     RECT  16.032 10.213 16.056 12.757 ;
     RECT  40.032 12.323 40.512 12.757 ;
     RECT  17.568 8.531 17.592 12.803 ;
     RECT  10.512 11.941 10.536 12.853 ;
     RECT  12.576 11.029 13.512 12.899 ;
     RECT  4.56 11.651 4.584 12.995 ;
     RECT  10.512 12.853 11.4 12.995 ;
     RECT  33.024 11.941 33.048 12.995 ;
     RECT  18.6 11.941 19.368 12.997 ;
     RECT  31.488 10.595 31.512 13.043 ;
     RECT  72.6 11.941 73.704 13.043 ;
     RECT  7.8 8.435 8.28 13.045 ;
     RECT  18.24 12.997 19.368 13.045 ;
     RECT  72.6 13.043 72.912 13.045 ;
     RECT  85.776 12.469 86.04 13.045 ;
     RECT  20.784 12.757 20.808 13.093 ;
     RECT  67.2 10.115 67.512 13.093 ;
     RECT  36.432 12.181 36.456 13.139 ;
     RECT  43.296 12.469 43.32 13.139 ;
     RECT  51 11.941 52.296 13.139 ;
     RECT  54.144 11.317 54.168 13.139 ;
     RECT  82.656 12.563 83.712 13.139 ;
     RECT  96.864 12.517 97.512 13.139 ;
     RECT  78 9.395 78.648 13.285 ;
     RECT  93.504 11.941 94.512 13.429 ;
     RECT  96.912 13.139 97.512 13.475 ;
     RECT  39.888 12.757 40.512 13.573 ;
     RECT  41.664 12.323 41.688 13.573 ;
     RECT  51 13.139 51.312 13.573 ;
     RECT  85.584 13.045 86.04 13.621 ;
     RECT  20.784 13.093 21.432 13.667 ;
     RECT  34.656 12.517 35.112 13.715 ;
     RECT  20.784 13.667 20.808 13.763 ;
     RECT  87.216 13.621 87.24 13.859 ;
     RECT  45.6 11.989 46.008 13.907 ;
     RECT  6.912 13.045 8.28 14.003 ;
     RECT  64.512 12.517 64.536 14.003 ;
     RECT  13.2 12.899 13.512 14.005 ;
     RECT  5.712 13.669 5.736 14.147 ;
     RECT  78 13.285 78.936 14.147 ;
     RECT  50.784 13.573 51.312 14.243 ;
     RECT  59.328 12.613 59.352 14.243 ;
     RECT  71.76 13.045 72.912 14.243 ;
     RECT  85.584 13.621 86.136 14.243 ;
     RECT  97.488 13.475 97.512 14.243 ;
     RECT  18.24 13.045 19.656 14.291 ;
     RECT  86.016 14.243 86.136 14.291 ;
     RECT  93.504 13.429 95.16 14.291 ;
     RECT  78 14.147 78.408 14.341 ;
     RECT  32.64 13.621 32.664 14.387 ;
     RECT  75.12 12.517 75.144 14.387 ;
     RECT  45.6 13.907 45.912 14.389 ;
     RECT  61.8 12.517 62.328 14.483 ;
     RECT  67.2 13.093 67.848 14.533 ;
     RECT  68.928 10.789 68.952 14.533 ;
     RECT  15.984 12.757 16.056 14.675 ;
     RECT  67.2 14.533 68.952 14.723 ;
     RECT  77.856 14.341 78.408 14.723 ;
     RECT  11.376 12.995 11.4 14.867 ;
     RECT  12.528 14.005 13.512 14.867 ;
     RECT  39.888 13.573 41.688 14.867 ;
     RECT  50.832 14.243 51.312 14.867 ;
     RECT  93.504 14.291 94.512 14.915 ;
     RECT  36.48 14.197 36.504 14.963 ;
     RECT  78 14.723 78.408 14.963 ;
     RECT  23.52 10.451 24.312 15.061 ;
     RECT  103.92 13.957 103.944 15.203 ;
     RECT  66.144 14.821 66.168 15.491 ;
     RECT  105 12.563 105.312 15.541 ;
     RECT  7.8 14.003 8.28 15.589 ;
     RECT  51 14.867 51.312 15.589 ;
     RECT  104.88 15.541 105.312 15.589 ;
     RECT  2.4 8.579 2.712 15.829 ;
     RECT  16.032 14.675 16.056 15.829 ;
     RECT  78 14.963 78.312 15.829 ;
     RECT  13.2 14.867 13.512 15.973 ;
     RECT  51 15.589 51.912 16.019 ;
     RECT  93.648 14.915 94.512 16.019 ;
     RECT  56.016 12.755 57.432 16.165 ;
     RECT  18.6 14.291 19.656 16.261 ;
     RECT  77.28 15.829 78.312 16.403 ;
     RECT  15.984 15.829 16.056 16.453 ;
     RECT  44.736 14.389 45.912 16.499 ;
     RECT  104.88 15.589 106.296 16.499 ;
     RECT  43.632 16.021 43.656 16.501 ;
     RECT  80.832 7.957 81.096 16.501 ;
     RECT  82.368 15.541 82.392 16.501 ;
     RECT  80.832 16.501 82.392 16.549 ;
     RECT  83.4 13.139 83.712 16.549 ;
     RECT  104.88 16.499 105.432 16.835 ;
     RECT  2.4 15.829 2.808 16.837 ;
     RECT  80.832 16.549 83.712 17.029 ;
     RECT  7.248 15.589 8.28 17.075 ;
     RECT  61.8 14.483 62.112 17.077 ;
     RECT  72.6 14.243 72.912 17.077 ;
     RECT  78 16.403 78.312 17.077 ;
     RECT  9.792 15.685 9.816 17.123 ;
     RECT  44.976 16.499 45.912 17.123 ;
     RECT  15.936 16.453 16.056 17.173 ;
     RECT  61.008 17.077 62.112 17.219 ;
     RECT  80.304 17.029 83.712 17.411 ;
     RECT  28.32 15.829 28.344 17.461 ;
     RECT  29.4 10.067 29.712 17.461 ;
     RECT  23.232 15.061 24.312 17.509 ;
     RECT  15.936 17.173 16.296 17.605 ;
     RECT  41.664 14.867 41.688 17.605 ;
     RECT  53.088 16.501 53.112 17.605 ;
     RECT  54.288 15.157 54.312 17.605 ;
     RECT  68.928 14.723 68.952 17.605 ;
     RECT  94.08 16.019 94.512 17.605 ;
     RECT  41.664 17.605 41.784 17.651 ;
     RECT  67.2 14.723 67.512 17.653 ;
     RECT  12.432 15.973 13.512 17.699 ;
     RECT  14.496 16.933 14.52 17.699 ;
     RECT  72.6 17.077 73.032 17.843 ;
     RECT  63.552 16.405 63.576 17.891 ;
     RECT  18.6 16.261 19.992 17.941 ;
     RECT  23.232 17.509 24.888 17.987 ;
     RECT  34.8 13.715 35.112 17.989 ;
     RECT  45.6 17.123 45.912 18.037 ;
     RECT  78 17.077 79.128 18.037 ;
     RECT  15.936 17.605 17.016 18.083 ;
     RECT  47.856 16.981 47.88 18.083 ;
     RECT  34.032 17.989 35.112 18.181 ;
     RECT  86.112 14.291 86.136 18.181 ;
     RECT  88.8 12.515 89.112 18.181 ;
     RECT  18.192 17.941 19.992 18.275 ;
     RECT  23.328 17.987 24.888 18.275 ;
     RECT  28.32 17.461 29.712 18.275 ;
     RECT  66.912 17.653 67.512 18.275 ;
     RECT  80.304 17.411 81.816 18.275 ;
     RECT  91.728 17.077 91.752 18.275 ;
     RECT  2.4 16.837 2.856 18.419 ;
     RECT  29.136 18.275 29.712 18.421 ;
     RECT  99.6 12.755 99.912 18.421 ;
     RECT  53.088 17.605 54.312 18.467 ;
     RECT  85.104 18.181 86.136 18.469 ;
     RECT  94.08 17.605 95.16 18.515 ;
     RECT  58.656 18.181 58.68 18.517 ;
     RECT  68.928 17.605 69.24 18.517 ;
     RECT  70.368 18.373 70.392 18.517 ;
     RECT  31.584 17.029 31.608 18.611 ;
     RECT  75.84 16.501 75.864 18.661 ;
     RECT  23.52 18.275 24.888 18.707 ;
     RECT  75.84 18.661 76.056 18.707 ;
     RECT  61.8 17.219 62.112 18.709 ;
     RECT  68.928 18.517 70.392 18.755 ;
     RECT  7.8 17.075 8.28 18.757 ;
     RECT  99.6 18.421 100.344 18.757 ;
     RECT  34.032 18.181 35.88 18.851 ;
     RECT  70.368 18.755 70.392 18.949 ;
     RECT  85.056 18.469 86.136 18.995 ;
     RECT  85.056 18.995 85.128 19.093 ;
     RECT  98.976 18.757 100.344 19.235 ;
     RECT  45.6 18.037 46.392 19.333 ;
     RECT  77.52 18.037 79.128 19.333 ;
     RECT  53.088 18.467 53.352 19.379 ;
     RECT  61.344 18.709 62.112 19.379 ;
     RECT  70.368 18.949 70.68 19.427 ;
     RECT  21.504 18.229 21.528 19.523 ;
     RECT  51 16.019 51.312 19.621 ;
     RECT  64.944 17.029 64.968 19.763 ;
     RECT  13.056 17.699 13.512 19.765 ;
     RECT  16.272 18.083 17.016 19.765 ;
     RECT  18.192 18.275 19.656 19.765 ;
     RECT  7.8 18.757 8.52 19.811 ;
     RECT  88.8 18.181 89.208 19.811 ;
     RECT  29.136 18.421 30.552 20.003 ;
     RECT  34.032 18.851 35.112 20.003 ;
     RECT  41.76 17.651 41.784 20.003 ;
     RECT  42.768 16.501 43.656 20.003 ;
     RECT  45.6 19.333 46.44 20.003 ;
     RECT  70.608 19.427 70.68 20.003 ;
     RECT  76.032 18.707 76.056 20.003 ;
     RECT  77.52 19.333 79.224 20.003 ;
     RECT  9.648 18.229 9.672 20.051 ;
     RECT  86.112 18.995 86.136 20.051 ;
     RECT  13.056 19.765 13.704 20.149 ;
     RECT  83.4 17.411 83.712 20.149 ;
     RECT  92.832 17.605 92.856 20.149 ;
     RECT  84.912 19.093 85.128 20.195 ;
     RECT  92.448 20.149 92.856 20.195 ;
     RECT  54.432 20.101 54.456 20.243 ;
     RECT  13.056 20.149 13.992 20.339 ;
     RECT  98.976 19.235 99.912 20.341 ;
     RECT  77.52 20.003 78.696 20.485 ;
     RECT  94.08 18.515 94.512 20.485 ;
     RECT  32.4 19.669 32.424 20.579 ;
     RECT  55.776 16.165 57.432 20.579 ;
     RECT  58.656 18.517 59.496 20.579 ;
     RECT  68.928 18.755 68.952 20.579 ;
     RECT  45.6 20.003 46.392 20.627 ;
     RECT  105 16.835 105.432 20.627 ;
     RECT  51 19.621 51.576 20.725 ;
     RECT  59.472 20.579 59.496 20.725 ;
     RECT  50.88 20.725 51.576 20.915 ;
     RECT  53.328 19.379 53.352 20.917 ;
     RECT  39.888 14.867 40.512 20.965 ;
     RECT  87.456 17.989 87.48 20.965 ;
     RECT  87.456 20.965 87.768 21.011 ;
     RECT  72.6 17.843 72.912 21.109 ;
     RECT  103.68 16.165 103.704 21.109 ;
     RECT  16.272 19.765 19.656 21.155 ;
     RECT  77.472 20.485 78.696 21.155 ;
     RECT  87.744 21.011 87.768 21.155 ;
     RECT  93.456 20.485 94.512 21.155 ;
     RECT  106.8 20.197 106.824 21.155 ;
     RECT  33.072 21.109 33.096 21.251 ;
     RECT  98.64 20.341 99.912 21.443 ;
     RECT  17.04 21.155 19.656 21.635 ;
     RECT  86.16 21.061 86.184 21.637 ;
     RECT  13.2 20.339 13.992 21.683 ;
     RECT  39.072 20.965 40.512 21.683 ;
     RECT  50.88 20.915 51.312 21.683 ;
     RECT  18.48 21.635 19.656 21.731 ;
     RECT  91.152 21.205 91.176 21.779 ;
     RECT  54.48 21.253 54.504 21.827 ;
     RECT  27.168 17.941 27.192 21.877 ;
     RECT  25.968 17.077 25.992 21.923 ;
     RECT  103.632 21.109 103.704 21.971 ;
     RECT  45.6 20.627 45.912 22.117 ;
     RECT  72.336 21.109 72.912 22.163 ;
     RECT  23.52 18.707 24.312 22.165 ;
     RECT  43.632 20.003 43.656 22.165 ;
     RECT  61.8 19.379 62.112 22.165 ;
     RECT  94.2 21.155 94.512 22.165 ;
     RECT  105 20.627 105.312 22.165 ;
     RECT  103.68 21.971 103.704 22.211 ;
     RECT  67.2 18.275 67.512 22.453 ;
     RECT  88.8 19.811 89.112 22.597 ;
     RECT  39.888 21.683 40.512 22.741 ;
     RECT  59.472 20.725 59.88 22.741 ;
     RECT  45.6 22.117 46.776 22.787 ;
     RECT  83.4 20.149 83.928 22.787 ;
     RECT  51 21.683 51.312 22.789 ;
     RECT  85.056 20.195 85.128 22.789 ;
     RECT  86.112 21.637 86.184 22.789 ;
     RECT  23.376 22.165 24.312 22.835 ;
     RECT  59.424 22.741 59.88 22.835 ;
     RECT  85.056 22.789 86.184 22.835 ;
     RECT  85.056 22.835 86.136 22.933 ;
     RECT  17.04 21.635 17.064 23.027 ;
     RECT  99.168 21.443 99.912 23.171 ;
     RECT  50.544 22.789 51.312 23.267 ;
     RECT  27.168 21.877 27.912 23.317 ;
     RECT  29.136 20.003 29.712 23.317 ;
     RECT  34.8 20.003 35.112 23.317 ;
     RECT  101.088 21.397 101.112 23.317 ;
     RECT  84.96 22.933 86.136 23.363 ;
     RECT  25.872 22.165 25.896 23.411 ;
     RECT  78 21.155 78.696 23.411 ;
     RECT  56.016 20.579 57.432 23.557 ;
     RECT  4.944 19.333 4.968 23.653 ;
     RECT  93.888 22.165 94.512 23.795 ;
     RECT  13.2 21.683 13.704 23.797 ;
     RECT  37.392 17.365 37.416 23.797 ;
     RECT  31.872 21.637 31.896 23.845 ;
     RECT  63.984 22.741 64.008 23.893 ;
     RECT  92.448 20.195 92.472 23.893 ;
     RECT  83.4 22.787 83.712 23.941 ;
     RECT  84.96 23.363 85.608 23.941 ;
     RECT  34.8 23.317 35.88 23.987 ;
     RECT  83.4 23.941 85.608 24.083 ;
     RECT  11.952 23.173 11.976 24.131 ;
     RECT  63.216 23.893 64.008 24.131 ;
     RECT  66.672 22.453 67.512 24.131 ;
     RECT  51 23.267 51.312 24.229 ;
     RECT  33.792 23.701 33.816 24.275 ;
     RECT  84.96 24.083 85.608 24.275 ;
     RECT  101.088 23.317 101.448 24.323 ;
     RECT  43.632 22.165 43.8 24.325 ;
     RECT  43.536 24.325 43.8 24.371 ;
     RECT  50.4 24.229 51.312 24.371 ;
     RECT  39.888 22.741 40.632 24.373 ;
     RECT  87.84 22.597 89.112 24.469 ;
     RECT  4.944 23.653 5.688 24.515 ;
     RECT  39.888 24.373 40.776 24.515 ;
     RECT  87.84 24.469 89.496 24.515 ;
     RECT  92.352 23.893 92.472 24.563 ;
     RECT  22.128 22.741 22.152 24.613 ;
     RECT  23.52 22.835 24.312 24.613 ;
     RECT  70.656 20.003 70.68 24.613 ;
     RECT  22.128 24.613 24.312 24.659 ;
     RECT  31.296 23.845 31.896 24.659 ;
     RECT  61.392 22.165 62.112 24.659 ;
     RECT  106.608 23.317 106.632 24.659 ;
     RECT  92.352 24.563 92.424 24.947 ;
     RECT  83.4 24.083 83.712 25.045 ;
     RECT  27.168 23.317 29.712 25.091 ;
     RECT  13.2 23.797 14.424 25.139 ;
     RECT  48.96 24.469 48.984 25.139 ;
     RECT  63.216 24.131 63.24 25.139 ;
     RECT  88.8 24.515 89.496 25.139 ;
     RECT  96.24 22.165 96.264 25.139 ;
     RECT  101.424 24.323 101.448 25.139 ;
     RECT  43.536 24.371 43.656 25.187 ;
     RECT  7.8 19.811 8.28 25.189 ;
     RECT  37.056 23.797 37.416 25.189 ;
     RECT  94.2 23.795 94.512 25.237 ;
     RECT  26.16 24.997 26.184 25.283 ;
     RECT  2.4 18.419 2.712 25.285 ;
     RECT  99.6 23.171 99.912 25.285 ;
     RECT  37.056 25.189 37.848 25.331 ;
     RECT  52.752 20.917 53.352 25.427 ;
     RECT  7.68 25.189 8.28 25.621 ;
     RECT  31.872 24.659 31.896 25.621 ;
     RECT  70.176 24.613 70.68 25.715 ;
     RECT  104.736 22.165 105.312 25.763 ;
     RECT  83.4 25.045 83.832 25.859 ;
     RECT  93.936 25.237 94.512 26.101 ;
     RECT  7.584 25.621 8.28 26.149 ;
     RECT  2.4 25.285 3.336 26.243 ;
     RECT  27.168 25.091 27.912 26.243 ;
     RECT  99.024 25.285 99.912 26.243 ;
     RECT  55.872 23.557 57.432 26.291 ;
     RECT  27.168 26.243 27.768 26.435 ;
     RECT  15.36 25.621 15.384 26.485 ;
     RECT  22.752 24.659 24.312 26.531 ;
     RECT  92.4 24.947 92.424 26.531 ;
     RECT  13.2 25.139 13.704 26.627 ;
     RECT  43.632 25.187 43.656 26.629 ;
     RECT  67.2 24.131 67.512 26.629 ;
     RECT  72.6 22.163 72.912 26.677 ;
     RECT  61.8 24.659 62.112 26.725 ;
     RECT  63.168 25.333 63.192 26.725 ;
     RECT  53.328 25.427 53.352 26.773 ;
     RECT  49.584 25.861 49.608 26.819 ;
     RECT  59.424 22.835 59.448 26.819 ;
     RECT  70.176 25.715 70.2 26.819 ;
     RECT  27.168 26.435 27.672 26.867 ;
     RECT  43.632 26.629 43.944 26.915 ;
     RECT  52.992 26.773 53.352 26.915 ;
     RECT  61.8 26.725 63.192 27.107 ;
     RECT  54.672 27.109 54.696 27.251 ;
     RECT  15.36 26.485 16.056 27.301 ;
     RECT  99.6 26.243 99.912 27.301 ;
     RECT  93.792 26.101 94.512 27.347 ;
     RECT  4.944 24.515 4.968 27.395 ;
     RECT  67.2 26.629 68.232 27.395 ;
     RECT  34.8 23.987 35.112 27.397 ;
     RECT  31.872 25.621 32.472 27.587 ;
     RECT  61.8 27.107 62.376 27.587 ;
     RECT  75.84 26.725 75.864 27.875 ;
     RECT  29.136 25.091 29.712 27.923 ;
     RECT  15.36 27.301 16.296 27.971 ;
     RECT  31.872 27.587 31.896 27.971 ;
     RECT  37.824 25.331 37.848 27.971 ;
     RECT  103.728 27.205 103.752 27.971 ;
     RECT  41.904 27.205 41.928 28.115 ;
     RECT  90.624 27.349 90.648 28.115 ;
     RECT  23.376 26.531 24.312 28.163 ;
     RECT  72.24 26.677 72.912 28.403 ;
     RECT  45.6 22.787 45.912 28.405 ;
     RECT  85.056 24.275 85.608 28.453 ;
     RECT  34.8 27.397 35.256 28.547 ;
     RECT  13.2 26.627 13.512 28.693 ;
     RECT  54.72 27.877 54.744 28.741 ;
     RECT  56.016 26.291 57.432 28.741 ;
     RECT  54.72 28.741 57.432 28.787 ;
     RECT  18.6 21.731 19.656 28.837 ;
     RECT  45.6 28.405 46.104 28.931 ;
     RECT  29.28 27.923 29.712 28.933 ;
     RECT  84.864 28.453 85.608 29.029 ;
     RECT  37.008 28.885 37.032 29.075 ;
     RECT  34.8 28.547 35.112 29.077 ;
     RECT  7.488 26.149 8.28 29.123 ;
     RECT  39.888 24.515 40.512 29.123 ;
     RECT  47.232 29.029 47.256 29.221 ;
     RECT  46.992 29.221 47.256 29.267 ;
     RECT  99.6 27.301 100.296 29.267 ;
     RECT  16.272 27.971 16.296 29.269 ;
     RECT  7.632 29.123 8.28 29.315 ;
     RECT  23.52 28.163 24.312 29.365 ;
     RECT  12.384 28.693 13.512 29.459 ;
     RECT  88.8 25.139 89.112 29.509 ;
     RECT  51 24.371 51.312 29.557 ;
     RECT  78 23.411 78.312 29.605 ;
     RECT  80.832 18.275 81.816 29.605 ;
     RECT  83.4 25.859 83.712 29.605 ;
     RECT  79.488 27.781 79.512 29.651 ;
     RECT  7.68 29.315 8.28 29.795 ;
     RECT  34.128 29.077 35.112 29.845 ;
     RECT  29.088 28.933 29.712 29.893 ;
     RECT  34.128 29.845 35.928 29.987 ;
     RECT  5.856 29.365 5.88 30.037 ;
     RECT  77.568 29.605 78.312 30.133 ;
     RECT  103.2 29.605 103.224 30.181 ;
     RECT  72.384 28.403 72.912 30.275 ;
     RECT  58.8 28.885 58.824 30.323 ;
     RECT  43.632 26.915 43.656 30.373 ;
     RECT  5.376 30.037 5.88 30.467 ;
     RECT  22.8 29.365 24.312 30.515 ;
     RECT  45.6 28.931 45.912 30.517 ;
     RECT  46.992 29.267 47.016 30.517 ;
     RECT  88.8 29.509 89.544 30.611 ;
     RECT  23.52 30.515 24.312 30.709 ;
     RECT  18.6 28.837 20.52 30.757 ;
     RECT  34.128 29.987 35.544 30.803 ;
     RECT  43.632 30.373 44.424 30.803 ;
     RECT  50.88 29.557 51.312 30.803 ;
     RECT  5.376 30.467 5.4 30.805 ;
     RECT  88.8 30.611 89.112 30.805 ;
     RECT  103.104 30.181 103.224 30.851 ;
     RECT  39.936 29.123 40.512 30.853 ;
     RECT  67.2 27.395 67.512 30.997 ;
     RECT  45.6 30.517 47.016 31.093 ;
     RECT  96.864 29.029 96.888 31.139 ;
     RECT  7.8 29.795 8.28 31.141 ;
     RECT  27.168 26.867 27.192 31.237 ;
     RECT  106.8 30.709 106.824 31.237 ;
     RECT  103.104 30.851 103.128 31.283 ;
     RECT  106.608 31.237 106.824 31.283 ;
     RECT  53.328 26.915 53.352 31.285 ;
     RECT  28.464 29.893 29.712 31.331 ;
     RECT  45.6 31.093 47.592 31.331 ;
     RECT  4.704 30.805 5.4 31.379 ;
     RECT  74.448 30.757 74.472 31.427 ;
     RECT  75.888 30.757 75.912 31.427 ;
     RECT  69.984 29.365 70.008 31.667 ;
     RECT  72.6 30.275 72.912 31.717 ;
     RECT  72.6 31.717 73.368 31.765 ;
     RECT  7.8 31.141 8.616 31.861 ;
     RECT  18.6 30.757 20.616 31.861 ;
     RECT  11.424 31.765 11.448 31.955 ;
     RECT  18.192 31.861 20.616 31.955 ;
     RECT  106.608 31.283 106.632 31.955 ;
     RECT  65.712 31.285 65.736 32.149 ;
     RECT  39.888 30.853 40.512 32.197 ;
     RECT  60.192 31.525 60.216 32.197 ;
     RECT  34.8 30.803 35.544 32.243 ;
     RECT  47.568 31.331 47.592 32.243 ;
     RECT  105 25.763 105.312 32.293 ;
     RECT  2.4 26.243 2.712 32.341 ;
     RECT  104.88 32.293 105.312 32.341 ;
     RECT  43.632 30.803 44.088 32.437 ;
     RECT  45.6 31.331 45.912 32.437 ;
     RECT  72.6 31.765 73.56 32.437 ;
     RECT  100.992 31.813 101.016 32.437 ;
     RECT  87.168 31.333 87.192 32.483 ;
     RECT  100.992 32.437 101.448 32.483 ;
     RECT  42.768 32.437 45.912 32.675 ;
     RECT  91.296 31.381 91.32 32.723 ;
     RECT  80.832 29.605 83.712 32.725 ;
     RECT  84.768 29.029 85.608 32.725 ;
     RECT  26.496 31.237 27.192 32.771 ;
     RECT  59.28 32.197 60.216 32.771 ;
     RECT  88.368 30.805 89.112 32.771 ;
     RECT  49.104 31.861 49.128 32.965 ;
     RECT  48.432 32.965 49.128 33.011 ;
     RECT  61.8 27.587 62.112 33.013 ;
     RECT  72.6 32.437 74.184 33.013 ;
     RECT  39.6 32.197 40.512 33.061 ;
     RECT  2.4 32.341 2.904 33.107 ;
     RECT  43.632 32.675 45.912 33.107 ;
     RECT  67.2 30.997 67.992 33.107 ;
     RECT  72.288 33.013 74.184 33.107 ;
     RECT  39.6 33.061 41.16 33.299 ;
     RECT  65.568 32.149 65.736 33.347 ;
     RECT  51 30.803 51.312 33.541 ;
     RECT  94.2 27.347 94.512 33.541 ;
     RECT  98.496 33.013 98.52 33.683 ;
     RECT  101.424 32.483 101.448 33.683 ;
     RECT  13.2 29.459 13.512 33.733 ;
     RECT  72.288 33.107 73.56 33.827 ;
     RECT  27.168 32.771 27.192 33.829 ;
     RECT  27.168 33.829 27.432 34.067 ;
     RECT  29.184 31.331 29.712 34.069 ;
     RECT  44.736 33.107 45.912 34.163 ;
     RECT  21.12 33.973 21.144 34.211 ;
     RECT  48.432 33.011 48.456 34.259 ;
     RECT  77.568 30.133 78.408 34.259 ;
     RECT  18.192 31.955 19.656 34.355 ;
     RECT  61.8 33.013 62.76 34.355 ;
     RECT  80.832 32.725 85.608 34.355 ;
     RECT  22.464 33.925 22.488 34.357 ;
     RECT  29.088 34.069 29.712 34.357 ;
     RECT  13.2 33.733 13.608 34.499 ;
     RECT  23.52 30.709 24.408 34.499 ;
     RECT  53.184 31.285 53.352 34.643 ;
     RECT  106.656 34.549 106.68 34.691 ;
     RECT  55.056 28.787 57.432 34.739 ;
     RECT  88.8 32.771 89.112 34.741 ;
     RECT  93.696 33.541 94.512 34.741 ;
     RECT  104.88 32.341 105.432 34.741 ;
     RECT  51 33.541 51.432 34.787 ;
     RECT  93.696 34.741 94.776 34.787 ;
     RECT  103.248 34.117 103.272 34.787 ;
     RECT  16.272 29.269 16.536 34.885 ;
     RECT  7.8 31.861 9.528 34.931 ;
     RECT  46.896 34.117 46.92 34.931 ;
     RECT  69.504 33.013 69.528 34.931 ;
     RECT  96.336 32.437 96.36 34.931 ;
     RECT  11.136 33.445 11.16 35.317 ;
     RECT  22.176 34.357 22.488 35.317 ;
     RECT  23.52 34.499 24.312 35.317 ;
     RECT  53.328 34.643 53.352 35.317 ;
     RECT  55.056 34.739 55.08 35.317 ;
     RECT  34.8 32.243 35.112 35.461 ;
     RECT  10.848 35.317 11.16 35.555 ;
     RECT  61.8 34.355 62.112 35.605 ;
     RECT  5.376 31.379 5.4 35.845 ;
     RECT  27.168 34.067 27.192 35.845 ;
     RECT  29.04 34.357 29.712 35.845 ;
     RECT  27.168 35.845 27.336 35.891 ;
     RECT  104.448 34.741 105.432 35.893 ;
     RECT  63.264 34.741 63.288 35.939 ;
     RECT  88.704 34.741 89.112 35.939 ;
     RECT  25.44 34.165 25.464 35.987 ;
     RECT  94.2 34.787 94.776 35.987 ;
     RECT  83.4 34.355 85.608 36.037 ;
     RECT  45.6 34.163 45.912 36.085 ;
     RECT  65.712 33.347 65.736 36.227 ;
     RECT  29.04 35.845 30.408 36.323 ;
     RECT  16.128 34.885 16.536 36.421 ;
     RECT  5.328 35.845 5.4 36.469 ;
     RECT  38.16 35.845 38.184 36.469 ;
     RECT  11.136 35.555 11.16 36.515 ;
     RECT  32.112 35.845 32.136 36.515 ;
     RECT  33.84 35.461 35.112 36.515 ;
     RECT  53.328 35.317 55.08 36.515 ;
     RECT  83.4 36.037 85.752 36.515 ;
     RECT  104.16 35.893 105.432 36.515 ;
     RECT  39.6 33.299 40.512 36.517 ;
     RECT  41.52 35.557 41.544 36.517 ;
     RECT  51 34.787 51.312 36.517 ;
     RECT  22.176 35.317 24.312 36.563 ;
     RECT  104.88 36.515 105.432 36.563 ;
     RECT  39.6 36.517 41.544 36.661 ;
     RECT  43.632 33.107 43.656 36.757 ;
     RECT  90.384 35.845 90.408 36.803 ;
     RECT  92.592 30.901 92.616 36.853 ;
     RECT  39.6 36.661 41.592 36.901 ;
     RECT  59.28 32.771 59.304 36.997 ;
     RECT  72.6 33.827 73.56 36.997 ;
     RECT  29.184 36.323 30.408 37.043 ;
     RECT  53.328 36.515 53.4 37.043 ;
     RECT  59.28 36.997 59.736 37.043 ;
     RECT  5.328 36.469 6.12 37.091 ;
     RECT  37.872 36.469 38.184 37.139 ;
     RECT  72.6 36.997 73.944 37.139 ;
     RECT  23.52 36.563 24.312 37.189 ;
     RECT  37.872 37.139 37.896 37.525 ;
     RECT  92.592 36.853 92.952 37.571 ;
     RECT  22.176 36.563 22.488 37.573 ;
     RECT  77.568 34.259 78.312 37.573 ;
     RECT  92.88 37.571 92.952 37.573 ;
     RECT  94.2 35.987 94.512 37.573 ;
     RECT  70.944 36.757 70.968 37.619 ;
     RECT  72.6 37.139 73.56 37.813 ;
     RECT  43.632 36.757 44.232 37.859 ;
     RECT  79.824 35.269 79.848 37.859 ;
     RECT  45.6 36.085 46.008 38.005 ;
     RECT  20.88 36.469 20.904 38.099 ;
     RECT  61.68 35.605 62.112 38.101 ;
     RECT  59.712 37.043 59.736 38.149 ;
     RECT  67.2 33.107 67.512 38.149 ;
     RECT  68.784 36.421 68.808 38.149 ;
     RECT  84.768 36.515 85.752 38.149 ;
     RECT  77.136 37.573 78.312 38.195 ;
     RECT  87.792 36.373 87.816 38.195 ;
     RECT  61.632 38.101 62.112 38.197 ;
     RECT  37.104 37.525 37.896 38.243 ;
     RECT  45.6 38.005 46.776 38.389 ;
     RECT  27.312 35.891 27.336 38.435 ;
     RECT  49.056 35.845 49.08 38.435 ;
     RECT  22.176 37.573 22.536 38.485 ;
     RECT  23.52 37.189 25.272 38.485 ;
     RECT  29.184 37.043 29.712 38.485 ;
     RECT  45.504 38.389 46.776 38.531 ;
     RECT  29.088 38.485 29.712 38.677 ;
     RECT  72.24 37.813 73.56 38.677 ;
     RECT  50.688 36.517 51.312 38.723 ;
     RECT  92.88 37.573 94.512 38.749 ;
     RECT  15.888 36.421 16.536 38.771 ;
     RECT  29.088 38.677 30.408 38.771 ;
     RECT  92.928 38.749 94.512 38.819 ;
     RECT  39.552 36.901 41.592 38.963 ;
     RECT  61.632 38.197 62.904 39.011 ;
     RECT  88.8 35.939 89.112 39.061 ;
     RECT  90.288 38.677 90.312 39.061 ;
     RECT  71.808 38.677 73.56 39.109 ;
     RECT  98.016 37.573 98.04 39.203 ;
     RECT  104.88 36.563 105.312 39.251 ;
     RECT  39.984 38.963 41.592 39.253 ;
     RECT  22.176 38.485 25.272 39.299 ;
     RECT  50.736 38.723 51.312 39.299 ;
     RECT  43.632 37.859 43.656 39.301 ;
     RECT  77.568 38.195 78.312 39.301 ;
     RECT  59.712 38.149 60.216 39.347 ;
     RECT  84.768 38.149 86.136 39.395 ;
     RECT  106.704 38.581 106.728 39.395 ;
     RECT  53.328 37.043 53.352 39.589 ;
     RECT  22.176 39.299 22.488 39.779 ;
     RECT  76.368 38.677 76.392 39.779 ;
     RECT  45.6 38.531 46.056 39.827 ;
     RECT  71.808 39.109 73.944 39.827 ;
     RECT  5.328 37.091 5.352 39.877 ;
     RECT  61.8 39.011 62.904 39.877 ;
     RECT  5.328 39.877 5.688 39.923 ;
     RECT  29.184 38.771 30.408 39.923 ;
     RECT  43.008 39.301 43.656 40.019 ;
     RECT  5.664 39.923 5.688 40.067 ;
     RECT  14.496 40.117 14.52 40.165 ;
     RECT  16.224 38.771 16.536 40.165 ;
     RECT  67.2 38.149 68.808 40.211 ;
     RECT  72.6 39.827 73.944 40.307 ;
     RECT  32.304 40.165 32.328 40.309 ;
     RECT  77.376 39.301 78.312 40.309 ;
     RECT  29.184 39.923 30.024 40.355 ;
     RECT  84.768 39.395 85.752 40.405 ;
     RECT  31.584 40.309 32.328 40.451 ;
     RECT  18.6 34.355 19.656 40.453 ;
     RECT  29.184 40.355 29.712 40.499 ;
     RECT  33.552 39.877 33.576 40.499 ;
     RECT  64.416 36.469 64.44 40.499 ;
     RECT  88.8 39.061 90.312 40.739 ;
     RECT  32.304 40.451 32.328 40.741 ;
     RECT  45.6 39.827 46.008 40.741 ;
     RECT  27.456 40.165 27.48 40.885 ;
     RECT  27.36 40.885 27.48 40.931 ;
     RECT  32.304 40.741 33.048 40.931 ;
     RECT  90.288 40.739 90.312 40.981 ;
     RECT  93.744 38.819 94.512 40.981 ;
     RECT  45.36 40.741 46.008 41.027 ;
     RECT  9.888 40.165 9.912 41.075 ;
     RECT  14.496 40.165 16.536 41.075 ;
     RECT  18.6 40.453 20.568 41.075 ;
     RECT  37.872 38.243 37.896 41.075 ;
     RECT  39.984 39.253 41.64 41.075 ;
     RECT  45.6 41.027 46.008 41.075 ;
     RECT  59.712 39.347 59.736 41.075 ;
     RECT  67.2 40.211 67.608 41.075 ;
     RECT  101.424 40.165 101.448 41.075 ;
     RECT  84.768 40.405 86.088 41.219 ;
     RECT  61.8 39.877 62.952 41.269 ;
     RECT  77.376 40.309 78.696 41.459 ;
     RECT  105 39.251 105.312 41.461 ;
     RECT  84.768 41.219 85.752 41.507 ;
     RECT  22.464 39.779 22.488 41.509 ;
     RECT  68.784 40.211 68.808 41.605 ;
     RECT  5.856 40.693 5.88 41.651 ;
     RECT  27.36 40.931 27.384 41.651 ;
     RECT  32.304 40.931 32.328 41.651 ;
     RECT  68.784 41.605 68.904 41.651 ;
     RECT  72.6 40.307 73.368 41.651 ;
     RECT  95.904 40.693 95.928 41.651 ;
     RECT  90.288 40.981 91.176 41.699 ;
     RECT  22.32 41.509 22.488 41.795 ;
     RECT  36.192 40.645 36.216 41.939 ;
     RECT  65.472 40.309 65.496 41.939 ;
     RECT  7.8 34.931 8.616 41.941 ;
     RECT  29.4 40.499 29.712 41.941 ;
     RECT  14.496 41.075 16.296 41.987 ;
     RECT  61.8 41.269 63 41.989 ;
     RECT  61.8 41.989 63.288 42.035 ;
     RECT  29.088 41.941 29.712 42.083 ;
     RECT  13.2 34.499 13.512 42.133 ;
     RECT  18.6 41.075 19.656 42.133 ;
     RECT  50.88 39.299 51.312 42.133 ;
     RECT  80.832 34.355 81.816 42.133 ;
     RECT  92.88 40.981 94.512 42.179 ;
     RECT  99.6 29.267 99.912 42.181 ;
     RECT  39.984 41.075 41.544 42.373 ;
     RECT  53.328 39.589 54.024 42.373 ;
     RECT  52.512 42.373 54.024 42.421 ;
     RECT  55.056 36.515 55.08 42.421 ;
     RECT  39.84 42.373 41.544 42.515 ;
     RECT  52.512 42.421 55.08 42.515 ;
     RECT  43.632 40.019 43.656 42.565 ;
     RECT  43.632 42.565 44.184 42.707 ;
     RECT  12.24 42.133 13.512 42.709 ;
     RECT  18.6 42.133 20.472 42.709 ;
     RECT  50.688 42.133 51.312 42.709 ;
     RECT  77.568 41.459 78.696 42.709 ;
     RECT  91.152 41.699 91.176 42.755 ;
     RECT  17.856 42.709 20.472 42.803 ;
     RECT  63.264 42.035 63.288 42.803 ;
     RECT  80.208 42.133 81.816 42.851 ;
     RECT  43.632 42.707 43.944 42.995 ;
     RECT  50.16 42.709 51.312 42.995 ;
     RECT  16.128 41.987 16.296 43.139 ;
     RECT  99.264 42.181 99.912 43.141 ;
     RECT  105 41.461 105.432 43.285 ;
     RECT  17.856 42.803 19.656 43.331 ;
     RECT  93.888 42.179 94.512 43.333 ;
     RECT  95.52 42.709 95.544 43.333 ;
     RECT  87.792 42.325 87.816 43.379 ;
     RECT  92.832 42.181 92.856 43.379 ;
     RECT  99.264 43.141 100.872 43.379 ;
     RECT  61.8 42.035 62.112 43.381 ;
     RECT  14.496 41.987 14.808 43.525 ;
     RECT  16.128 43.139 16.152 43.525 ;
     RECT  77.568 42.709 79.224 43.571 ;
     RECT  50.448 42.995 51.312 43.621 ;
     RECT  104.88 43.285 105.432 43.667 ;
     RECT  93.888 43.333 95.544 43.811 ;
     RECT  97.584 42.037 97.608 43.811 ;
     RECT  72.6 41.651 72.912 43.813 ;
     RECT  5.472 42.613 5.496 43.861 ;
     RECT  34.8 36.515 35.112 43.861 ;
     RECT  65.664 43.285 65.688 43.955 ;
     RECT  99.6 43.379 100.872 43.955 ;
     RECT  5.376 43.861 5.496 44.099 ;
     RECT  33.024 43.237 33.048 44.245 ;
     RECT  34.224 43.861 35.112 44.245 ;
     RECT  104.88 43.667 105.312 44.245 ;
     RECT  43.632 42.995 43.656 44.293 ;
     RECT  12.048 42.709 13.512 44.339 ;
     RECT  30.768 43.333 30.792 44.339 ;
     RECT  53.328 42.515 55.08 44.339 ;
     RECT  50.448 43.621 52.248 44.387 ;
     RECT  22.464 41.795 22.488 44.437 ;
     RECT  61.8 43.381 62.424 44.437 ;
     RECT  80.832 42.851 81.816 44.437 ;
     RECT  83.4 36.515 83.712 44.437 ;
     RECT  84.768 41.507 84.888 44.437 ;
     RECT  92.352 43.813 92.376 44.483 ;
     RECT  56.256 34.739 57.432 44.725 ;
     RECT  45.6 41.075 45.912 44.773 ;
     RECT  14.496 43.525 16.152 44.867 ;
     RECT  50.448 44.387 51.48 44.867 ;
     RECT  2.4 33.107 2.712 44.965 ;
     RECT  99.6 43.955 99.912 44.965 ;
     RECT  33.024 44.245 35.112 45.011 ;
     RECT  42.72 44.293 43.656 45.011 ;
     RECT  7.8 41.941 8.808 45.013 ;
     RECT  61.584 44.437 62.424 45.059 ;
     RECT  7.152 45.013 8.808 45.253 ;
     RECT  39.984 42.515 41.544 45.253 ;
     RECT  71.904 43.813 72.912 45.299 ;
     RECT  22.32 44.437 22.488 45.301 ;
     RECT  7.152 45.253 9.672 45.395 ;
     RECT  93.888 43.811 94.512 45.541 ;
     RECT  33.456 45.011 35.112 45.587 ;
     RECT  29.4 42.083 29.712 45.589 ;
     RECT  88.8 40.739 89.112 45.589 ;
     RECT  2.4 44.965 2.952 45.683 ;
     RECT  72.6 45.299 72.912 45.685 ;
     RECT  45.6 44.773 46.488 45.731 ;
     RECT  72.6 45.685 73.032 45.923 ;
     RECT  39.888 45.253 41.544 45.971 ;
     RECT  51 44.867 51.48 46.069 ;
     RECT  56.256 44.725 58.2 46.069 ;
     RECT  39.936 45.971 41.544 46.117 ;
     RECT  43.104 45.011 43.656 46.117 ;
     RECT  61.584 45.059 62.112 46.165 ;
     RECT  7.152 45.395 9.144 46.211 ;
     RECT  16.128 44.867 16.152 46.211 ;
     RECT  80.832 44.437 84.888 46.211 ;
     RECT  77.568 43.571 78.312 46.213 ;
     RECT  80.832 46.211 81.816 46.405 ;
     RECT  93.504 45.541 94.512 46.499 ;
     RECT  99.6 44.965 100.248 46.499 ;
     RECT  88.32 45.589 89.112 46.501 ;
     RECT  87.792 46.501 89.112 46.547 ;
     RECT  67.2 41.075 67.512 46.549 ;
     RECT  77.568 46.213 78.648 46.597 ;
     RECT  5.376 44.099 5.4 46.787 ;
     RECT  29.04 45.589 29.712 46.787 ;
     RECT  68.88 41.651 68.904 46.787 ;
     RECT  70.416 45.253 70.44 46.787 ;
     RECT  93.888 46.499 94.512 46.787 ;
     RECT  39.936 46.117 43.656 47.027 ;
     RECT  87.792 46.547 87.816 47.027 ;
     RECT  29.136 46.787 29.712 47.029 ;
     RECT  7.8 46.211 9.144 47.075 ;
     RECT  21.648 45.301 22.488 47.075 ;
     RECT  51 46.069 51.912 47.221 ;
     RECT  12.24 44.339 13.512 47.315 ;
     RECT  48.096 46.645 48.12 47.363 ;
     RECT  50.496 47.221 51.912 47.363 ;
     RECT  77.52 46.597 78.648 47.363 ;
     RECT  95.52 43.811 95.544 47.363 ;
     RECT  18.384 43.331 19.656 47.411 ;
     RECT  43.104 47.027 43.656 47.459 ;
     RECT  31.296 45.541 31.32 47.507 ;
     RECT  12.528 47.315 13.512 47.555 ;
     RECT  7.8 47.075 8.808 47.701 ;
     RECT  7.056 47.701 8.808 47.749 ;
     RECT  16.56 46.645 16.584 47.797 ;
     RECT  16.56 47.797 17.064 47.843 ;
     RECT  56.256 46.069 58.68 47.843 ;
     RECT  39.936 47.027 41.544 47.845 ;
     RECT  66.624 46.549 67.512 47.845 ;
     RECT  90.432 46.405 90.456 47.845 ;
     RECT  90.432 47.845 90.6 47.891 ;
     RECT  6.912 47.749 8.808 47.939 ;
     RECT  29.136 47.029 30.216 47.939 ;
     RECT  64.464 47.797 64.488 47.939 ;
     RECT  102.288 45.541 102.312 47.939 ;
     RECT  66.576 47.845 67.512 47.989 ;
     RECT  27.936 46.933 27.96 48.083 ;
     RECT  7.056 47.939 8.808 48.131 ;
     RECT  66.576 47.989 68.328 48.131 ;
     RECT  80.4 46.405 81.816 48.229 ;
     RECT  90.576 47.891 90.6 48.275 ;
     RECT  43.104 47.459 43.128 48.419 ;
     RECT  79.728 48.229 81.816 48.419 ;
     RECT  45.6 45.731 45.912 48.421 ;
     RECT  104.832 44.245 105.312 48.421 ;
     RECT  56.256 47.843 58.2 48.515 ;
     RECT  60.96 46.165 62.112 48.613 ;
     RECT  23.52 39.299 25.272 48.899 ;
     RECT  17.04 47.843 17.064 48.901 ;
     RECT  53.328 44.339 54.024 48.901 ;
     RECT  79.728 48.419 79.752 48.947 ;
     RECT  24 48.899 25.272 48.949 ;
     RECT  72.6 45.923 72.912 48.949 ;
     RECT  75.6 48.229 75.624 48.949 ;
     RECT  97.056 45.541 97.08 48.949 ;
     RECT  60.96 48.613 62.232 49.043 ;
     RECT  66.624 48.131 68.328 49.043 ;
     RECT  17.04 48.901 17.112 49.091 ;
     RECT  52.368 48.901 54.024 49.139 ;
     RECT  17.04 49.091 17.064 49.141 ;
     RECT  86.112 48.421 86.136 49.187 ;
     RECT  16.992 49.141 17.064 49.283 ;
     RECT  29.136 47.939 29.712 49.333 ;
     RECT  7.392 48.131 8.808 49.381 ;
     RECT  10.08 48.997 10.104 49.381 ;
     RECT  21.072 47.605 21.096 49.477 ;
     RECT  22.464 47.075 22.488 49.477 ;
     RECT  2.4 45.683 2.712 49.525 ;
     RECT  29.04 49.333 29.712 49.525 ;
     RECT  34.224 45.587 35.112 49.525 ;
     RECT  7.392 49.381 10.104 49.571 ;
     RECT  71.808 48.949 72.912 49.571 ;
     RECT  74.832 48.949 75.624 49.571 ;
     RECT  38.16 48.421 38.184 49.619 ;
     RECT  63.216 47.317 63.24 49.619 ;
     RECT  21.072 49.477 22.488 49.813 ;
     RECT  66.624 49.043 67.512 49.861 ;
     RECT  45.6 48.421 46.392 49.909 ;
     RECT  77.568 47.363 78.648 49.955 ;
     RECT  92.88 48.997 92.904 50.005 ;
     RECT  7.8 49.571 10.104 50.051 ;
     RECT  50.496 47.363 51.312 50.051 ;
     RECT  74.832 49.571 74.856 50.051 ;
     RECT  92.352 50.005 92.904 50.051 ;
     RECT  60.96 49.043 62.112 50.053 ;
     RECT  24 48.949 25.704 50.099 ;
     RECT  13.008 47.555 13.512 50.101 ;
     RECT  14.496 44.867 14.52 50.101 ;
     RECT  51 50.051 51.312 50.101 ;
     RECT  13.008 50.101 14.52 50.147 ;
     RECT  2.4 49.525 3.192 50.243 ;
     RECT  75.84 50.101 75.864 50.485 ;
     RECT  25.68 50.099 25.704 50.579 ;
     RECT  32.64 48.373 32.664 50.579 ;
     RECT  45.024 49.909 46.392 50.579 ;
     RECT  75.84 50.485 75.912 50.629 ;
     RECT  34.224 49.525 35.832 50.675 ;
     RECT  88.8 46.547 89.112 50.677 ;
     RECT  104.784 48.421 105.312 50.677 ;
     RECT  51 50.101 51.912 50.819 ;
     RECT  70.272 46.837 70.296 50.821 ;
     RECT  39.36 47.845 41.544 50.867 ;
     RECT  70.272 50.821 71.064 50.867 ;
     RECT  75.84 50.629 76.152 50.915 ;
     RECT  28.464 49.525 29.712 51.059 ;
     RECT  92.352 50.051 92.376 51.107 ;
     RECT  31.728 50.677 31.752 51.155 ;
     RECT  29.04 51.059 29.712 51.251 ;
     RECT  24 50.099 24.408 51.253 ;
     RECT  20.784 49.813 22.488 51.299 ;
     RECT  97.056 48.949 97.512 51.347 ;
     RECT  99.6 46.499 99.912 51.349 ;
     RECT  104.784 50.677 105.768 51.395 ;
     RECT  80.832 48.419 81.816 51.493 ;
     RECT  60.288 50.053 62.112 51.637 ;
     RECT  69.072 50.101 69.096 51.637 ;
     RECT  69.072 51.637 69.48 51.683 ;
     RECT  75.84 50.915 75.912 51.731 ;
     RECT  7.8 50.051 9.432 51.923 ;
     RECT  43.248 51.781 43.272 51.923 ;
     RECT  75.84 51.731 75.864 51.923 ;
     RECT  77.568 49.955 78.6 51.923 ;
     RECT  97.056 51.347 97.08 51.923 ;
     RECT  99.072 51.349 99.912 51.923 ;
     RECT  39.888 50.867 41.544 51.925 ;
     RECT  94.2 46.787 94.512 52.021 ;
     RECT  77.568 51.923 78.552 52.067 ;
     RECT  66.528 49.861 67.512 52.069 ;
     RECT  93.984 52.021 94.512 52.069 ;
     RECT  83.4 46.211 84.888 52.163 ;
     RECT  86.016 50.677 86.04 52.163 ;
     RECT  88.8 50.677 89.592 52.165 ;
     RECT  17.04 49.283 17.064 52.211 ;
     RECT  45.024 50.579 46.008 52.259 ;
     RECT  58.8 52.165 58.824 52.307 ;
     RECT  34.224 50.675 35.112 52.309 ;
     RECT  20.784 51.299 20.808 52.405 ;
     RECT  21.888 51.299 22.488 52.405 ;
     RECT  51 50.819 51.312 52.405 ;
     RECT  55.056 44.339 55.08 52.405 ;
     RECT  56.256 48.515 57.432 52.405 ;
     RECT  88.8 52.165 89.688 52.451 ;
     RECT  47.28 51.205 47.304 52.547 ;
     RECT  66.528 52.069 67.656 52.547 ;
     RECT  60 51.637 62.112 52.595 ;
     RECT  95.904 51.541 95.928 52.595 ;
     RECT  23.904 51.253 24.408 52.597 ;
     RECT  105 51.395 105.768 52.691 ;
     RECT  18.6 47.411 19.656 52.693 ;
     RECT  34.224 52.309 35.88 52.739 ;
     RECT  70.512 50.867 71.064 52.739 ;
     RECT  102.576 51.253 102.6 52.739 ;
     RECT  23.904 52.597 24.456 52.835 ;
     RECT  66.528 52.547 67.512 52.835 ;
     RECT  18.48 52.693 19.656 52.883 ;
     RECT  83.4 52.163 83.712 52.885 ;
     RECT  71.04 52.739 71.064 52.979 ;
     RECT  24 52.835 24.456 52.981 ;
     RECT  93.984 52.069 94.824 53.027 ;
     RECT  24 52.981 24.84 53.029 ;
     RECT  32.976 51.829 33 53.075 ;
     RECT  45.6 52.259 46.008 53.075 ;
     RECT  80.208 51.493 81.816 53.075 ;
     RECT  84.768 52.163 84.888 53.077 ;
     RECT  34.656 52.739 35.88 53.123 ;
     RECT  30.912 52.357 30.936 53.125 ;
     RECT  39.552 51.925 41.544 53.125 ;
     RECT  77.568 52.067 78.312 53.125 ;
     RECT  69.456 51.683 69.48 53.171 ;
     RECT  7.8 51.923 8.808 53.173 ;
     RECT  84.768 53.077 84.984 53.267 ;
     RECT  7.8 53.173 9.144 53.315 ;
     RECT  60.672 52.595 62.112 53.315 ;
     RECT  29.4 51.251 29.712 53.413 ;
     RECT  72.6 49.571 72.912 53.461 ;
     RECT  50.88 52.405 51.312 53.555 ;
     RECT  2.4 50.243 2.712 53.557 ;
     RECT  77.568 53.125 78.648 53.557 ;
     RECT  30.912 53.125 30.984 53.603 ;
     RECT  94.08 53.027 94.824 53.603 ;
     RECT  29.136 53.413 29.712 53.651 ;
     RECT  55.056 52.405 57.432 53.747 ;
     RECT  4.992 51.205 5.016 53.795 ;
     RECT  30.96 53.603 30.984 53.795 ;
     RECT  63.6 52.789 63.624 53.795 ;
     RECT  0.192 53.749 0.216 53.845 ;
     RECT  0.192 53.845 0.312 53.939 ;
     RECT  27.36 48.421 27.384 53.941 ;
     RECT  27.36 53.941 27.48 53.987 ;
     RECT  84.768 53.267 84.888 53.989 ;
     RECT  66.192 52.981 66.216 54.085 ;
     RECT  67.2 52.835 67.512 54.085 ;
     RECT  82.848 52.885 83.712 54.085 ;
     RECT  84.72 53.989 84.888 54.085 ;
     RECT  11.136 52.981 11.16 54.131 ;
     RECT  87.216 48.421 87.24 54.131 ;
     RECT  2.4 53.557 3.336 54.179 ;
     RECT  20.784 52.405 22.488 54.179 ;
     RECT  55.056 53.747 56.712 54.179 ;
     RECT  80.976 53.075 81.816 54.179 ;
     RECT  33.024 53.509 33.048 54.325 ;
     RECT  34.656 53.123 35.112 54.325 ;
     RECT  66.192 54.085 67.512 54.325 ;
     RECT  24 53.029 25.272 54.419 ;
     RECT  18.6 52.883 19.656 54.467 ;
     RECT  33.024 54.325 35.112 54.517 ;
     RECT  82.848 54.085 84.888 54.517 ;
     RECT  32.064 54.517 35.112 54.563 ;
     RECT  99.6 51.923 99.912 54.613 ;
     RECT  94.08 53.603 94.512 54.659 ;
     RECT  18.6 54.467 19.368 54.707 ;
     RECT  6.672 52.405 6.696 54.755 ;
     RECT  77.568 53.557 79.224 54.755 ;
     RECT  91.2 52.981 91.224 54.803 ;
     RECT  18.6 54.707 18.912 54.805 ;
     RECT  32.064 54.563 33.048 54.851 ;
     RECT  82.848 54.517 85.176 54.851 ;
     RECT  48.48 52.501 48.504 54.853 ;
     RECT  48.48 54.853 48.984 54.899 ;
     RECT  65.328 54.325 67.512 54.899 ;
     RECT  84.72 54.851 85.176 54.899 ;
     RECT  99.6 54.613 100.824 54.899 ;
     RECT  13.008 50.147 14.328 54.901 ;
     RECT  17.712 54.805 18.912 54.947 ;
     RECT  39.504 53.125 41.544 54.947 ;
     RECT  21.888 54.179 22.488 55.091 ;
     RECT  72.096 53.461 72.912 55.091 ;
     RECT  60.672 53.315 60.696 55.093 ;
     RECT  61.8 53.315 62.112 55.093 ;
     RECT  58.128 54.037 58.152 55.139 ;
     RECT  12.432 54.901 14.328 55.187 ;
     RECT  7.8 53.315 8.808 55.237 ;
     RECT  48.96 54.899 48.984 55.237 ;
     RECT  81.552 54.179 81.816 55.237 ;
     RECT  82.848 54.851 83.712 55.237 ;
     RECT  88.8 52.451 89.112 55.237 ;
     RECT  105 52.691 105.312 55.237 ;
     RECT  60.672 55.093 62.112 55.283 ;
     RECT  55.056 54.179 55.08 55.285 ;
     RECT  56.4 54.179 56.712 55.285 ;
     RECT  67.2 54.899 67.512 55.285 ;
     RECT  88.8 55.237 89.208 55.379 ;
     RECT  61.8 55.283 62.112 55.525 ;
     RECT  2.4 54.179 2.712 55.573 ;
     RECT  3.696 54.997 3.72 55.573 ;
     RECT  77.568 54.755 78.648 55.573 ;
     RECT  88.8 55.379 89.112 55.717 ;
     RECT  100.896 55.621 100.92 55.763 ;
     RECT  27.456 53.987 27.48 55.765 ;
     RECT  29.4 53.651 29.712 55.765 ;
     RECT  34.656 54.563 35.112 55.765 ;
     RECT  94.2 54.659 94.512 55.765 ;
     RECT  88.08 55.717 89.112 55.859 ;
     RECT  81.12 55.237 83.712 55.861 ;
     RECT  39.552 54.947 41.544 55.907 ;
     RECT  53.328 49.139 54.024 55.907 ;
     RECT  94.2 55.765 94.632 55.907 ;
     RECT  48.96 55.237 49.416 55.955 ;
     RECT  34.224 55.765 35.112 56.005 ;
     RECT  72.48 55.091 72.912 56.053 ;
     RECT  43.632 55.621 43.656 56.099 ;
     RECT  55.056 55.285 56.712 56.099 ;
     RECT  57.888 55.429 57.912 56.101 ;
     RECT  27.456 55.765 27.576 56.197 ;
     RECT  15.36 55.237 15.384 56.243 ;
     RECT  33.888 56.005 35.112 56.293 ;
     RECT  20.784 54.179 20.808 56.339 ;
     RECT  65.328 54.899 65.976 56.389 ;
     RECT  81.072 55.861 83.712 56.389 ;
     RECT  49.392 55.955 49.416 56.437 ;
     RECT  57.888 56.101 58.632 56.437 ;
     RECT  26.928 56.197 27.576 56.483 ;
     RECT  97.968 55.237 97.992 56.483 ;
     RECT  49.392 56.437 49.512 56.531 ;
     RECT  81.024 56.389 83.712 56.533 ;
     RECT  84.72 54.899 84.888 56.533 ;
     RECT  72.48 56.053 73.032 56.579 ;
     RECT  80.976 56.533 84.888 56.581 ;
     RECT  33.12 56.293 35.112 56.627 ;
     RECT  16.464 55.813 16.488 56.675 ;
     RECT  28.8 55.765 29.712 56.677 ;
     RECT  11.088 55.237 11.112 56.723 ;
     RECT  72.48 56.579 72.912 56.773 ;
     RECT  67.2 55.285 67.752 56.819 ;
     RECT  40.2 55.907 41.544 56.915 ;
     RECT  80.976 56.581 85.416 56.915 ;
     RECT  28.8 56.677 29.832 56.963 ;
     RECT  69.12 56.725 69.144 56.963 ;
     RECT  81.024 56.915 85.416 56.963 ;
     RECT  25.92 55.381 25.944 57.011 ;
     RECT  28.8 56.963 29.712 57.011 ;
     RECT  63.504 55.861 63.528 57.011 ;
     RECT  93.12 55.813 93.144 57.011 ;
     RECT  18.6 54.947 18.912 57.013 ;
     RECT  60.672 55.283 60.696 57.013 ;
     RECT  61.8 55.525 62.328 57.013 ;
     RECT  105 55.237 105.48 57.013 ;
     RECT  37.104 55.141 37.128 57.059 ;
     RECT  44.112 56.725 44.136 57.061 ;
     RECT  104.88 57.013 105.48 57.107 ;
     RECT  90.576 56.965 90.6 57.155 ;
     RECT  69.264 57.061 69.288 57.157 ;
     RECT  43.968 57.061 44.136 57.203 ;
     RECT  69.264 57.157 69.912 57.203 ;
     RECT  56.4 56.099 56.712 57.253 ;
     RECT  57.888 56.437 59.064 57.253 ;
     RECT  24 54.419 24.84 57.349 ;
     RECT  28.896 57.011 29.712 57.395 ;
     RECT  104.88 57.107 105.312 57.443 ;
     RECT  32.064 54.851 32.088 57.445 ;
     RECT  51 53.555 51.312 57.445 ;
     RECT  32.064 57.445 32.28 57.541 ;
     RECT  76.944 55.573 78.648 57.541 ;
     RECT  15.984 57.013 16.008 57.587 ;
     RECT  17.856 57.013 18.912 57.587 ;
     RECT  60.672 57.013 62.328 57.589 ;
     RECT  40.2 56.915 41.304 57.635 ;
     RECT  44.112 57.203 44.136 57.635 ;
     RECT  60.432 57.589 62.328 57.635 ;
     RECT  69.888 57.203 69.912 57.875 ;
     RECT  67.2 56.819 67.512 57.925 ;
     RECT  56.4 57.253 59.064 58.019 ;
     RECT  67.2 57.925 68.136 58.021 ;
     RECT  58.416 58.019 59.064 58.069 ;
     RECT  60.432 57.635 60.456 58.069 ;
     RECT  81.024 56.963 84.888 58.069 ;
     RECT  33.888 56.627 35.112 58.115 ;
     RECT  61.632 57.635 62.328 58.115 ;
     RECT  2.4 55.573 3.72 58.117 ;
     RECT  10.896 56.773 10.92 58.117 ;
     RECT  22.032 55.091 22.488 58.117 ;
     RECT  23.664 57.349 24.84 58.117 ;
     RECT  26.928 56.483 27.48 58.117 ;
     RECT  96.912 56.389 96.936 58.117 ;
     RECT  99.6 54.899 99.912 58.117 ;
     RECT  47.04 56.389 47.064 58.163 ;
     RECT  96.912 58.117 97.656 58.163 ;
     RECT  81.024 58.069 84.936 58.211 ;
     RECT  99.6 58.117 100.488 58.213 ;
     RECT  29.088 57.395 29.712 58.259 ;
     RECT  58.416 58.069 60.456 58.259 ;
     RECT  75.792 58.165 75.816 58.307 ;
     RECT  76.944 57.541 78.792 58.355 ;
     RECT  99.6 58.213 100.584 58.451 ;
     RECT  22.032 58.117 24.84 58.595 ;
     RECT  64.992 56.389 65.976 58.595 ;
     RECT  0.288 53.939 0.312 58.645 ;
     RECT  13.008 55.187 14.328 58.645 ;
     RECT  67.2 58.021 68.376 58.645 ;
     RECT  105 57.443 105.312 58.645 ;
     RECT  0.192 58.645 0.312 58.691 ;
     RECT  56.4 58.019 57.288 58.835 ;
     RECT  12.528 58.645 14.328 58.837 ;
     RECT  20.544 56.869 20.568 58.883 ;
     RECT  22.032 58.595 22.824 58.931 ;
     RECT  66.72 58.645 68.376 58.931 ;
     RECT  77.424 58.355 78.792 58.981 ;
     RECT  75.984 58.885 76.008 59.075 ;
     RECT  91.536 58.933 91.56 59.075 ;
     RECT  72.192 56.773 72.912 59.077 ;
     RECT  56.4 58.835 57.048 59.171 ;
     RECT  18.6 57.587 18.912 59.173 ;
     RECT  71.76 59.077 72.912 59.219 ;
     RECT  29.4 58.259 29.712 59.221 ;
     RECT  40.2 57.635 40.512 59.221 ;
     RECT  58.416 58.259 58.728 59.221 ;
     RECT  61.68 58.115 62.328 59.221 ;
     RECT  31.824 57.541 32.28 59.269 ;
     RECT  92.928 58.117 92.952 59.315 ;
     RECT  77.424 58.981 79.272 59.365 ;
     RECT  77.424 59.365 79.752 59.413 ;
     RECT  31.824 59.269 32.76 59.507 ;
     RECT  77.328 59.413 79.752 59.555 ;
     RECT  76.128 59.509 76.152 59.651 ;
     RECT  12.384 58.837 14.328 59.747 ;
     RECT  44.304 58.117 44.328 59.749 ;
     RECT  49.488 56.531 49.512 59.749 ;
     RECT  55.056 56.099 55.08 59.749 ;
     RECT  66.72 58.931 67.512 59.749 ;
     RECT  9.936 58.117 10.92 59.843 ;
     RECT  64.032 59.605 64.056 59.941 ;
     RECT  81.024 58.211 84.888 59.941 ;
     RECT  26.16 58.117 27.912 59.989 ;
     RECT  29.136 59.221 29.712 59.989 ;
     RECT  58.128 59.221 58.728 59.989 ;
     RECT  26.16 59.989 29.712 60.035 ;
     RECT  58.128 59.989 59.448 60.035 ;
     RECT  60.432 58.259 60.456 60.037 ;
     RECT  12.528 59.747 14.328 60.083 ;
     RECT  18.288 59.173 18.912 60.085 ;
     RECT  61.632 59.221 62.328 60.085 ;
     RECT  63.312 59.941 64.056 60.085 ;
     RECT  28.464 60.035 29.712 60.131 ;
     RECT  58.416 60.035 59.448 60.131 ;
     RECT  60.432 60.037 60.6 60.131 ;
     RECT  60.576 60.131 60.6 60.179 ;
     RECT  44.304 59.749 44.376 60.181 ;
     RECT  72.432 59.219 72.912 60.227 ;
     RECT  2.4 58.117 4.44 60.275 ;
     RECT  52.416 59.749 52.44 60.275 ;
     RECT  18.288 60.085 19.128 60.371 ;
     RECT  97.632 58.163 97.656 60.373 ;
     RECT  50.736 57.445 51.312 60.419 ;
     RECT  68.928 59.173 68.952 60.421 ;
     RECT  22.032 58.931 22.488 60.467 ;
     RECT  77.328 59.555 79.08 60.467 ;
     RECT  7.632 55.237 8.808 60.517 ;
     RECT  99.6 58.451 99.912 60.517 ;
     RECT  48.864 59.749 49.512 60.563 ;
     RECT  101.712 58.405 101.736 60.563 ;
     RECT  66.48 59.749 67.512 60.757 ;
     RECT  68.64 60.421 68.952 60.757 ;
     RECT  12.528 60.083 13.512 60.805 ;
     RECT  61.632 60.085 64.056 60.805 ;
     RECT  94.2 55.907 94.512 60.805 ;
     RECT  95.616 59.701 95.64 60.805 ;
     RECT  10.896 59.843 10.92 60.851 ;
     RECT  55.056 59.749 55.272 60.851 ;
     RECT  61.632 60.805 64.44 60.851 ;
     RECT  94.2 60.805 95.64 60.851 ;
     RECT  34.176 58.115 35.112 60.853 ;
     RECT  43.968 60.181 44.376 60.899 ;
     RECT  99.312 60.517 99.912 60.899 ;
     RECT  15.984 59.749 16.008 60.947 ;
     RECT  18.288 60.371 18.912 60.949 ;
     RECT  61.8 60.851 64.44 60.995 ;
     RECT  94.2 60.851 95.496 60.995 ;
     RECT  80.688 59.941 84.888 60.997 ;
     RECT  26.16 60.035 27.432 61.043 ;
     RECT  66.48 60.757 68.952 61.043 ;
     RECT  96.912 60.373 97.656 61.043 ;
     RECT  104.88 58.645 105.312 61.043 ;
     RECT  42.768 60.853 42.792 61.091 ;
     RECT  80.688 60.997 85.032 61.093 ;
     RECT  80.448 61.093 85.032 61.187 ;
     RECT  77.424 60.467 79.08 61.235 ;
     RECT  80.448 61.187 84.84 61.235 ;
     RECT  40.2 59.221 40.632 61.237 ;
     RECT  70.992 59.605 71.016 61.333 ;
     RECT  72.6 60.227 72.912 61.333 ;
     RECT  39.36 61.237 40.632 61.379 ;
     RECT  99.504 60.899 99.912 61.475 ;
     RECT  31.824 59.507 32.28 61.525 ;
     RECT  33.312 60.853 36.024 61.525 ;
     RECT  51 60.419 51.312 61.525 ;
     RECT  31.824 61.525 36.024 61.619 ;
     RECT  87.456 61.621 87.48 61.763 ;
     RECT  51 61.525 52.248 61.765 ;
     RECT  91.68 60.181 91.704 61.765 ;
     RECT  29.4 60.131 29.712 61.861 ;
     RECT  7.632 60.517 9.432 61.909 ;
     RECT  94.2 60.995 94.512 61.909 ;
     RECT  56.4 59.171 56.712 62.053 ;
     RECT  58.416 60.131 58.728 62.053 ;
     RECT  77.424 61.235 78.792 62.149 ;
     RECT  5.424 60.853 5.448 62.195 ;
     RECT  17.616 60.949 18.912 62.195 ;
     RECT  70.992 61.333 72.912 62.195 ;
     RECT  90.816 61.765 91.704 62.195 ;
     RECT  27.408 61.043 27.432 62.243 ;
     RECT  56.4 62.053 58.728 62.341 ;
     RECT  105 61.043 105.312 62.341 ;
     RECT  31.824 61.619 35.112 62.531 ;
     RECT  26.16 61.043 26.184 62.581 ;
     RECT  29.232 61.861 29.712 62.581 ;
     RECT  26.16 62.581 27.384 62.677 ;
     RECT  34.176 62.531 35.112 62.677 ;
     RECT  31.824 62.531 33.096 62.771 ;
     RECT  26.112 62.677 27.384 62.819 ;
     RECT  96.288 62.101 96.312 63.011 ;
     RECT  76.896 62.149 78.792 63.013 ;
     RECT  53.664 55.907 53.832 63.109 ;
     RECT  15.264 62.005 15.288 63.203 ;
     RECT  61.8 60.995 64.392 63.205 ;
     RECT  70.992 62.195 71.016 63.205 ;
     RECT  26.112 62.819 27.24 63.251 ;
     RECT  90.816 62.195 91.656 63.251 ;
     RECT  104.832 62.341 105.312 63.251 ;
     RECT  24 58.595 24.84 63.299 ;
     RECT  26.16 63.251 27.24 63.299 ;
     RECT  61.056 63.205 64.392 63.299 ;
     RECT  76.128 63.013 78.792 63.347 ;
     RECT  64.032 63.299 64.392 63.491 ;
     RECT  76.896 63.347 78.792 63.539 ;
     RECT  72.6 62.195 72.912 63.541 ;
     RECT  31.872 62.771 33.096 63.587 ;
     RECT  34.176 62.677 35.208 63.685 ;
     RECT  68.928 61.043 68.952 63.779 ;
     RECT  45.6 53.075 45.912 63.781 ;
     RECT  99.6 61.475 99.912 63.781 ;
     RECT  56.4 62.341 58.968 63.827 ;
     RECT  70.656 63.205 71.016 63.827 ;
     RECT  7.632 61.909 9.672 63.875 ;
     RECT  51 61.765 52.44 63.875 ;
     RECT  5.616 63.013 5.64 63.923 ;
     RECT  18.288 62.195 18.912 64.019 ;
     RECT  65.424 63.445 65.448 64.019 ;
     RECT  81.024 61.235 84.84 64.211 ;
     RECT  74.112 63.253 74.136 64.307 ;
     RECT  34.128 63.685 35.208 64.355 ;
     RECT  36.672 63.205 36.696 64.355 ;
     RECT  72.384 63.541 72.912 64.355 ;
     RECT  67.2 61.043 67.512 64.357 ;
     RECT  33.072 63.587 33.096 64.403 ;
     RECT  90.336 63.877 90.36 64.403 ;
     RECT  91.632 63.251 91.656 64.501 ;
     RECT  90.912 64.501 91.656 64.547 ;
     RECT  24 63.299 24.408 64.549 ;
     RECT  44.352 60.899 44.376 64.595 ;
     RECT  61.056 63.299 62.328 64.595 ;
     RECT  67.056 64.357 67.512 64.597 ;
     RECT  97.632 61.043 97.656 64.597 ;
     RECT  98.784 63.781 99.912 64.597 ;
     RECT  97.632 64.597 99.912 64.643 ;
     RECT  14.832 63.541 14.856 64.693 ;
     RECT  15.936 64.357 16.584 64.693 ;
     RECT  14.832 64.693 16.584 64.739 ;
     RECT  93.504 61.909 94.512 64.741 ;
     RECT  45.6 63.781 46.008 64.885 ;
     RECT  77.424 63.539 78.792 64.885 ;
     RECT  51 63.875 52.248 64.933 ;
     RECT  105 63.251 105.312 64.933 ;
     RECT  31.872 63.587 32.04 64.979 ;
     RECT  65.232 64.597 65.256 64.979 ;
     RECT  24 64.549 24.456 64.981 ;
     RECT  39.36 61.379 40.512 64.981 ;
     RECT  41.904 64.165 41.928 64.981 ;
     RECT  58.416 63.827 58.968 64.981 ;
     RECT  60.048 64.357 60.072 64.981 ;
     RECT  67.056 64.597 67.848 64.981 ;
     RECT  68.88 63.829 68.904 64.981 ;
     RECT  29.088 62.581 29.712 65.027 ;
     RECT  36.576 64.357 36.6 65.123 ;
     RECT  87.216 62.677 87.24 65.123 ;
     RECT  12.24 60.805 13.512 65.125 ;
     RECT  27.216 63.299 27.24 65.125 ;
     RECT  2.4 60.275 4.344 65.171 ;
     RECT  12 65.125 13.512 65.171 ;
     RECT  15.072 64.739 16.584 65.171 ;
     RECT  81.024 64.211 84.696 65.173 ;
     RECT  26.16 63.299 26.184 65.219 ;
     RECT  104.736 64.933 105.312 65.219 ;
     RECT  67.056 64.981 68.904 65.267 ;
     RECT  34.128 64.355 35.112 65.269 ;
     RECT  65.376 65.125 65.4 65.315 ;
     RECT  34.032 65.269 35.112 65.411 ;
     RECT  18.6 64.019 18.912 65.461 ;
     RECT  67.2 65.267 68.904 65.461 ;
     RECT  72.48 64.355 72.912 65.509 ;
     RECT  10.8 64.213 10.824 65.555 ;
     RECT  50.736 64.933 52.248 65.557 ;
     RECT  53.472 63.109 53.832 65.557 ;
     RECT  75.936 64.981 75.96 65.603 ;
     RECT  80.928 65.173 84.696 65.603 ;
     RECT  50.736 65.557 53.832 65.651 ;
     RECT  77.424 64.885 79.224 65.699 ;
     RECT  93.168 64.741 94.512 65.699 ;
     RECT  45.6 64.885 46.776 65.701 ;
     RECT  29.4 65.027 29.712 65.749 ;
     RECT  61.8 64.595 62.328 65.797 ;
     RECT  45.504 65.701 46.776 65.843 ;
     RECT  70.992 63.827 71.016 65.893 ;
     RECT  6.384 64.597 6.408 65.939 ;
     RECT  95.808 64.933 95.832 65.939 ;
     RECT  70.8 65.893 71.016 65.941 ;
     RECT  72.432 65.509 72.912 65.941 ;
     RECT  67.2 65.461 68.952 65.987 ;
     RECT  102.576 65.317 102.6 65.987 ;
     RECT  56.4 63.827 56.712 65.989 ;
     RECT  70.8 65.941 72.912 66.035 ;
     RECT  53.04 65.651 53.832 66.085 ;
     RECT  55.056 60.851 55.08 66.085 ;
     RECT  88.8 55.859 89.112 66.085 ;
     RECT  27.216 65.125 27.768 66.179 ;
     RECT  15.936 65.171 16.584 66.227 ;
     RECT  48.432 63.733 48.456 66.227 ;
     RECT  83.4 65.603 84.696 66.325 ;
     RECT  2.4 65.171 3.72 66.373 ;
     RECT  58.416 64.981 60.072 66.515 ;
     RECT  70.992 66.035 72.912 66.515 ;
     RECT  77.424 65.699 78.792 66.515 ;
     RECT  83.4 66.325 85.032 66.659 ;
     RECT  12 65.171 12.024 66.755 ;
     RECT  29.4 65.749 30.12 66.755 ;
     RECT  36.48 65.557 36.504 66.755 ;
     RECT  45.6 65.843 46.776 66.755 ;
     RECT  80.928 65.603 82.056 66.755 ;
     RECT  88.704 66.085 89.112 66.755 ;
     RECT  90.912 64.547 90.936 66.755 ;
     RECT  50.736 65.651 52.008 66.899 ;
     RECT  53.04 66.085 55.08 66.899 ;
     RECT  83.4 66.659 84.696 66.997 ;
     RECT  96.672 66.613 96.696 67.043 ;
     RECT  81.024 66.755 82.056 67.045 ;
     RECT  83.184 66.997 84.696 67.045 ;
     RECT  81.024 67.045 84.696 67.091 ;
     RECT  81.024 67.091 84.36 67.139 ;
     RECT  98.112 64.643 99.912 67.141 ;
     RECT  97.152 67.141 99.912 67.187 ;
     RECT  31.872 64.979 31.896 67.283 ;
     RECT  50.736 66.899 51.312 67.283 ;
     RECT  58.416 66.515 59.256 67.283 ;
     RECT  65.232 66.085 65.256 67.283 ;
     RECT  67.2 65.987 68.28 67.283 ;
     RECT  97.152 67.187 98.136 67.283 ;
     RECT  14.832 66.229 14.856 67.331 ;
     RECT  72.288 66.515 72.912 67.331 ;
     RECT  2.4 66.373 4.008 67.475 ;
     RECT  61.8 65.797 62.568 67.523 ;
     RECT  61.8 67.523 62.232 67.813 ;
     RECT  37.632 67.237 37.656 67.859 ;
     RECT  53.664 66.899 55.08 67.859 ;
     RECT  56.304 65.989 56.712 67.859 ;
     RECT  58.416 67.283 58.92 67.859 ;
     RECT  81.024 67.139 83.712 67.859 ;
     RECT  95.616 66.901 95.64 67.907 ;
     RECT  34.128 65.411 35.112 68.149 ;
     RECT  61.248 67.813 62.232 68.243 ;
     RECT  61.248 68.243 62.112 68.341 ;
     RECT  53.664 67.859 53.832 68.389 ;
     RECT  43.104 67.141 43.128 68.435 ;
     RECT  97.152 67.283 97.176 68.435 ;
     RECT  39.36 64.981 41.928 68.531 ;
     RECT  22.464 60.467 22.488 68.773 ;
     RECT  88.8 66.755 89.112 68.773 ;
     RECT  33.168 68.149 35.112 68.915 ;
     RECT  91.632 67.669 91.656 68.915 ;
     RECT  10.512 66.085 10.536 68.917 ;
     RECT  27.216 66.179 27.24 68.917 ;
     RECT  58.416 67.859 58.44 68.917 ;
     RECT  64.032 63.491 64.056 68.965 ;
     RECT  18.336 65.461 18.912 69.011 ;
     RECT  58.416 68.917 59.112 69.107 ;
     RECT  60.336 68.341 62.112 69.107 ;
     RECT  49.488 60.563 49.512 69.203 ;
     RECT  7.632 63.875 8.808 69.349 ;
     RECT  21.744 68.773 22.488 69.349 ;
     RECT  60.336 69.107 60.408 69.445 ;
     RECT  63.984 68.965 64.056 69.493 ;
     RECT  77.424 66.515 78.312 69.493 ;
     RECT  63.984 69.493 64.296 69.539 ;
     RECT  79.536 69.397 79.56 69.539 ;
     RECT  88.416 68.773 89.112 69.539 ;
     RECT  27.216 68.917 27.432 69.587 ;
     RECT  60.24 69.445 60.408 69.587 ;
     RECT  55.056 67.859 55.08 69.685 ;
     RECT  56.4 67.859 56.712 69.685 ;
     RECT  21.12 69.349 22.488 69.731 ;
     RECT  34.128 68.915 35.112 69.733 ;
     RECT  21.12 69.731 21.144 69.875 ;
     RECT  53.04 68.389 53.832 70.019 ;
     RECT  0.192 58.691 0.216 70.021 ;
     RECT  34.128 69.733 35.304 70.067 ;
     RECT  15.936 66.227 15.96 70.069 ;
     RECT  39.36 68.531 40.512 70.069 ;
     RECT  0.192 70.021 0.312 70.163 ;
     RECT  61.536 69.107 62.112 70.163 ;
     RECT  55.056 69.685 56.712 70.165 ;
     RECT  66.048 69.493 66.072 70.261 ;
     RECT  67.2 67.283 68.088 70.261 ;
     RECT  5.328 70.021 5.352 70.309 ;
     RECT  7.392 69.349 8.808 70.309 ;
     RECT  7.392 70.309 8.904 70.405 ;
     RECT  64.032 69.539 64.296 70.501 ;
     RECT  31.488 70.261 31.512 70.547 ;
     RECT  101.424 69.301 101.448 70.547 ;
     RECT  7.392 70.405 9.48 70.595 ;
     RECT  58.512 69.107 59.112 70.597 ;
     RECT  86.592 69.493 86.616 70.643 ;
     RECT  34.128 70.067 35.112 70.645 ;
     RECT  41.904 68.531 41.928 70.645 ;
     RECT  45.6 66.755 45.912 70.645 ;
     RECT  55.056 70.165 56.904 70.645 ;
     RECT  61.632 70.163 62.112 70.645 ;
     RECT  5.136 70.309 5.352 70.691 ;
     RECT  66.048 70.261 68.088 70.691 ;
     RECT  33.696 70.645 35.112 70.693 ;
     RECT  66.384 70.691 68.088 70.739 ;
     RECT  55.056 70.645 57 70.787 ;
     RECT  58.176 70.597 59.112 70.787 ;
     RECT  61.632 70.645 62.376 70.835 ;
     RECT  88.8 69.539 89.112 70.885 ;
     RECT  39.36 70.069 40.632 70.931 ;
     RECT  33.12 70.693 35.112 70.979 ;
     RECT  61.632 70.835 62.328 70.979 ;
     RECT  29.4 66.755 29.712 71.029 ;
     RECT  13.008 65.171 13.512 71.077 ;
     RECT  81.024 67.859 82.056 71.077 ;
     RECT  93.168 65.699 93.192 71.077 ;
     RECT  94.2 65.699 94.512 71.077 ;
     RECT  2.4 67.475 3.72 71.173 ;
     RECT  10.512 68.917 11.448 71.221 ;
     RECT  13.008 71.077 14.424 71.221 ;
     RECT  24 64.981 24.504 71.221 ;
     RECT  26.112 70.405 26.136 71.221 ;
     RECT  10.512 71.221 14.424 71.267 ;
     RECT  24 71.221 26.136 71.267 ;
     RECT  33.696 70.979 35.112 71.315 ;
     RECT  41.904 70.645 42.792 71.363 ;
     RECT  63.888 70.501 64.296 71.363 ;
     RECT  77.088 69.493 78.312 71.363 ;
     RECT  34.128 71.315 35.112 71.365 ;
     RECT  7.392 70.595 8.112 71.461 ;
     RECT  72.6 67.331 72.912 71.461 ;
     RECT  34.128 71.365 35.256 71.507 ;
     RECT  51 67.283 51.312 71.509 ;
     RECT  106.608 68.773 106.632 71.651 ;
     RECT  28.656 71.029 29.712 71.701 ;
     RECT  80.784 71.077 82.056 71.701 ;
     RECT  15.84 70.069 15.96 71.797 ;
     RECT  21.072 70.453 21.096 71.797 ;
     RECT  83.4 67.859 83.712 71.797 ;
     RECT  9.456 70.595 9.48 71.843 ;
     RECT  88.8 70.885 89.352 71.843 ;
     RECT  93.168 71.077 94.512 71.843 ;
     RECT  60.288 69.587 60.408 71.893 ;
     RECT  12.24 71.267 14.424 71.939 ;
     RECT  95.616 70.789 95.64 71.941 ;
     RECT  61.8 70.979 62.328 71.987 ;
     RECT  60 71.893 60.408 72.035 ;
     RECT  55.056 70.787 55.08 72.037 ;
     RECT  56.4 70.787 57 72.037 ;
     RECT  22.464 69.731 22.488 72.133 ;
     RECT  67.2 70.739 68.088 72.133 ;
     RECT  17.088 70.645 17.112 72.179 ;
     RECT  50.064 71.509 51.312 72.179 ;
     RECT  10.512 71.267 10.536 72.181 ;
     RECT  95.616 71.941 95.832 72.227 ;
     RECT  101.184 70.933 101.208 72.229 ;
     RECT  100.896 72.229 101.208 72.275 ;
     RECT  22.464 72.133 22.632 72.277 ;
     RECT  48.72 71.749 48.744 72.277 ;
     RECT  15.504 71.797 15.96 72.419 ;
     RECT  22.32 72.277 22.632 72.419 ;
     RECT  52.416 71.509 52.44 72.419 ;
     RECT  75.216 70.645 75.24 72.419 ;
     RECT  80.16 71.701 82.056 72.419 ;
     RECT  18.6 69.011 18.912 72.421 ;
     RECT  7.2 71.461 8.112 72.563 ;
     RECT  55.056 72.037 57 72.563 ;
     RECT  37.872 70.645 37.896 72.565 ;
     RECT  70.992 66.515 71.016 72.565 ;
     RECT  61.8 71.987 62.112 72.661 ;
     RECT  43.872 70.789 43.896 72.707 ;
     RECT  55.056 72.563 56.904 72.707 ;
     RECT  64.272 71.363 64.296 72.707 ;
     RECT  83.088 71.797 83.712 72.707 ;
     RECT  2.4 71.173 4.584 72.755 ;
     RECT  28.656 71.701 29.832 72.755 ;
     RECT  53.808 70.019 53.832 72.757 ;
     RECT  55.056 72.707 56.712 72.757 ;
     RECT  60.864 72.661 62.112 72.851 ;
     RECT  20.688 71.797 21.096 72.947 ;
     RECT  24 71.267 25.416 72.947 ;
     RECT  48.72 72.277 49.704 72.947 ;
     RECT  53.808 72.757 56.712 72.947 ;
     RECT  97.488 72.277 97.512 72.949 ;
     RECT  41.904 71.363 41.928 72.995 ;
     RECT  88.8 71.843 89.208 72.995 ;
     RECT  45.6 70.645 46.008 73.091 ;
     RECT  67.2 72.133 68.328 73.093 ;
     RECT  84.72 71.077 84.744 73.093 ;
     RECT  72.384 71.461 72.912 73.235 ;
     RECT  100.896 72.275 101.016 73.331 ;
     RECT  31.872 71.413 31.896 73.381 ;
     RECT  88.8 72.995 89.112 73.381 ;
     RECT  7.632 72.563 8.112 73.477 ;
     RECT  9.552 72.181 10.536 73.477 ;
     RECT  66.384 73.093 68.328 73.477 ;
     RECT  16.608 72.997 16.632 73.523 ;
     RECT  37.872 72.565 38.28 73.523 ;
     RECT  70.992 72.565 71.256 73.525 ;
     RECT  7.632 73.477 10.536 73.571 ;
     RECT  24 72.947 24.984 73.571 ;
     RECT  77.184 71.363 78.312 73.571 ;
     RECT  54.24 72.947 56.712 73.715 ;
     RECT  22.32 72.419 22.488 73.763 ;
     RECT  38.256 73.523 38.28 73.811 ;
     RECT  100.896 73.331 100.92 73.859 ;
     RECT  15.504 72.419 15.528 73.907 ;
     RECT  49.008 72.947 49.032 73.907 ;
     RECT  61.8 72.851 62.112 73.909 ;
     RECT  2.4 72.755 4.152 74.003 ;
     RECT  10.512 73.571 10.536 74.005 ;
     RECT  27.216 69.587 27.24 74.053 ;
     RECT  66.384 73.477 68.712 74.099 ;
     RECT  7.632 73.571 8.904 74.147 ;
     RECT  31.872 73.381 32.52 74.147 ;
     RECT  47.664 71.653 47.688 74.147 ;
     RECT  70.704 73.525 71.256 74.147 ;
     RECT  97.488 72.949 98.04 74.147 ;
     RECT  43.536 73.477 43.56 74.243 ;
     RECT  61.8 73.909 62.712 74.245 ;
     RECT  95.808 72.227 95.832 74.293 ;
     RECT  104.784 65.219 105.312 74.293 ;
     RECT  44.016 74.293 44.04 74.483 ;
     RECT  95.808 74.293 95.976 74.531 ;
     RECT  54.24 73.715 55.08 74.579 ;
     RECT  56.16 73.715 56.712 74.579 ;
     RECT  26.88 74.053 27.24 74.627 ;
     RECT  7.632 74.147 8.112 74.629 ;
     RECT  32.496 74.147 32.52 74.629 ;
     RECT  95.808 74.531 95.832 74.675 ;
     RECT  10.512 74.005 10.824 74.723 ;
     RECT  61.68 74.245 62.712 74.723 ;
     RECT  32.496 74.629 33.096 74.771 ;
     RECT  0.192 70.163 0.216 74.963 ;
     RECT  102.816 74.485 102.84 75.011 ;
     RECT  70.992 74.147 71.256 75.013 ;
     RECT  72.6 73.235 72.912 75.013 ;
     RECT  98.016 74.147 98.04 75.107 ;
     RECT  93.744 71.843 94.512 75.155 ;
     RECT  22.464 73.763 22.488 75.157 ;
     RECT  24 73.571 24.408 75.157 ;
     RECT  22.464 75.157 24.408 75.299 ;
     RECT  84.72 73.093 85.512 75.299 ;
     RECT  12.24 71.939 13.512 75.349 ;
     RECT  2.4 74.003 3.72 75.395 ;
     RECT  12.096 75.349 13.512 75.395 ;
     RECT  83.4 72.707 83.712 75.397 ;
     RECT  84.72 75.299 84.744 75.397 ;
     RECT  67.2 74.099 68.328 75.443 ;
     RECT  104.784 74.293 106.152 75.445 ;
     RECT  45.6 73.091 45.912 75.589 ;
     RECT  58.176 70.787 58.536 75.637 ;
     RECT  6.816 74.629 8.112 75.683 ;
     RECT  45.6 75.589 46.104 75.685 ;
     RECT  104.784 75.445 106.68 75.731 ;
     RECT  61.8 74.723 62.112 75.781 ;
     RECT  33.072 74.771 33.096 75.827 ;
     RECT  23.328 75.299 24.408 75.875 ;
     RECT  36.672 74.629 36.696 75.875 ;
     RECT  45.6 75.685 46.152 76.211 ;
     RECT  67.2 75.443 67.512 76.309 ;
     RECT  27.024 74.627 27.24 76.355 ;
     RECT  91.872 75.109 91.896 76.357 ;
     RECT  64.08 75.541 64.104 76.453 ;
     RECT  53.472 75.829 53.496 76.499 ;
     RECT  83.4 75.397 84.744 76.499 ;
     RECT  101.616 75.781 101.64 76.739 ;
     RECT  106.656 75.731 106.68 76.739 ;
     RECT  74.784 74.917 74.808 76.741 ;
     RECT  61.488 75.781 62.112 76.787 ;
     RECT  74.784 76.741 75.24 76.787 ;
     RECT  0.144 76.453 0.168 76.835 ;
     RECT  17.184 76.741 17.208 76.837 ;
     RECT  17.088 76.837 17.208 76.883 ;
     RECT  79.872 75.541 79.896 76.885 ;
     RECT  80.88 72.419 82.056 76.885 ;
     RECT  83.4 76.499 83.712 76.885 ;
     RECT  79.872 76.885 83.712 76.931 ;
     RECT  58.176 75.637 58.728 76.933 ;
     RECT  6.288 76.357 6.312 76.979 ;
     RECT  17.088 76.883 17.112 76.979 ;
     RECT  90.96 76.357 91.896 77.027 ;
     RECT  58.176 76.933 59.496 77.123 ;
     RECT  18.336 72.421 18.912 77.173 ;
     RECT  7.632 75.683 8.112 77.317 ;
     RECT  10.512 74.723 10.536 77.317 ;
     RECT  2.4 75.395 3.672 77.365 ;
     RECT  10.512 77.317 10.776 77.411 ;
     RECT  10.608 77.411 10.776 77.459 ;
     RECT  34.128 71.507 35.112 77.461 ;
     RECT  70.992 75.013 72.912 77.555 ;
     RECT  75.216 76.787 75.24 77.555 ;
     RECT  45.6 76.211 46.104 77.603 ;
     RECT  12.096 75.395 12.12 77.605 ;
     RECT  2.4 77.365 3.768 77.653 ;
     RECT  69.648 76.357 69.672 77.699 ;
     RECT  67.104 76.309 67.512 77.795 ;
     RECT  34.128 77.461 35.208 77.843 ;
     RECT  80.256 76.931 83.712 77.843 ;
     RECT  45.6 77.603 46.056 77.891 ;
     RECT  28.656 72.755 29.712 77.941 ;
     RECT  11.952 77.605 12.12 77.987 ;
     RECT  91.872 77.027 91.896 78.037 ;
     RECT  12.096 77.987 12.12 78.085 ;
     RECT  13.2 75.395 13.512 78.085 ;
     RECT  88.32 73.381 89.112 78.085 ;
     RECT  63.408 76.453 64.104 78.131 ;
     RECT  55.056 74.579 55.08 78.133 ;
     RECT  42.192 77.701 42.216 78.181 ;
     RECT  7.584 77.317 8.112 78.227 ;
     RECT  18.336 77.173 19.224 78.227 ;
     RECT  44.496 78.085 44.52 78.227 ;
     RECT  55.056 78.133 55.272 78.275 ;
     RECT  28.656 77.941 30.36 78.373 ;
     RECT  24 75.875 24.408 78.421 ;
     RECT  72.384 77.555 72.912 78.467 ;
     RECT  84.72 76.499 84.744 78.467 ;
     RECT  88.128 78.085 89.112 78.469 ;
     RECT  42.192 78.181 42.312 78.515 ;
     RECT  2.4 77.653 3.912 78.517 ;
     RECT  10.608 77.459 10.632 78.611 ;
     RECT  72.432 78.467 72.912 78.611 ;
     RECT  12.096 78.085 13.512 78.659 ;
     RECT  17.04 77.461 17.064 78.707 ;
     RECT  69.792 77.941 69.816 78.707 ;
     RECT  80.88 77.843 83.712 78.707 ;
     RECT  106.752 77.701 106.776 78.707 ;
     RECT  86.064 78.037 86.088 78.851 ;
     RECT  45.6 77.891 45.912 78.901 ;
     RECT  49.536 77.893 49.56 78.947 ;
     RECT  18.6 78.227 19.224 79.045 ;
     RECT  9.312 78.661 9.336 79.091 ;
     RECT  24 78.421 24.552 79.189 ;
     RECT  32.448 78.421 32.472 79.189 ;
     RECT  55.056 78.275 55.08 79.189 ;
     RECT  58.176 77.123 58.536 79.189 ;
     RECT  6.72 78.229 6.744 79.235 ;
     RECT  88.128 78.469 89.544 79.427 ;
     RECT  77.424 73.571 78.312 79.525 ;
     RECT  42.192 78.515 42.216 79.573 ;
     RECT  42.192 79.573 42.792 79.619 ;
     RECT  58.032 79.189 58.536 79.715 ;
     RECT  91.776 78.037 91.896 79.715 ;
     RECT  34.128 77.843 35.112 79.717 ;
     RECT  77.424 79.525 78.408 79.717 ;
     RECT  94.2 75.155 94.512 79.765 ;
     RECT  101.952 77.413 101.976 79.811 ;
     RECT  44.688 78.901 45.912 79.813 ;
     RECT  12.096 78.659 12.12 79.859 ;
     RECT  42.768 79.619 42.792 79.859 ;
     RECT  98.496 75.109 98.52 79.859 ;
     RECT  65.568 79.333 65.592 80.003 ;
     RECT  63.744 78.131 64.104 80.051 ;
     RECT  34.08 79.717 35.112 80.101 ;
     RECT  93.072 78.613 93.096 80.147 ;
     RECT  15.216 79.189 15.24 80.243 ;
     RECT  24 79.189 25.32 80.293 ;
     RECT  72.6 78.611 72.912 80.293 ;
     RECT  80.88 78.707 82.056 80.293 ;
     RECT  83.4 78.707 83.712 80.293 ;
     RECT  80.88 80.293 83.712 80.341 ;
     RECT  23.376 80.293 25.32 80.387 ;
     RECT  7.8 78.227 8.112 80.389 ;
     RECT  32.448 79.189 32.52 80.435 ;
     RECT  70.992 77.555 71.256 80.435 ;
     RECT  91.872 79.715 91.896 80.435 ;
     RECT  44.688 79.813 46.008 80.483 ;
     RECT  32.496 80.435 32.52 80.531 ;
     RECT  86.4 79.621 86.424 80.531 ;
     RECT  63.744 80.051 63.768 80.579 ;
     RECT  75.072 79.765 75.096 80.771 ;
     RECT  18.6 79.045 19.704 80.819 ;
     RECT  17.376 80.293 17.4 80.867 ;
     RECT  72.432 80.293 72.912 80.867 ;
     RECT  56.4 74.579 56.712 80.869 ;
     RECT  58.512 79.715 58.536 80.869 ;
     RECT  76.8 79.717 78.408 80.869 ;
     RECT  56.4 80.869 58.536 80.915 ;
     RECT  106.656 79.621 106.68 80.963 ;
     RECT  13.2 78.659 13.512 80.965 ;
     RECT  7.248 80.389 8.112 81.011 ;
     RECT  28.368 78.373 30.36 81.011 ;
     RECT  76.8 80.869 78.696 81.011 ;
     RECT  94.2 79.765 95.208 81.011 ;
     RECT  36.624 80.389 36.648 81.059 ;
     RECT  80.88 80.341 84.408 81.107 ;
     RECT  75.408 81.109 75.432 81.251 ;
     RECT  13.2 80.965 13.656 81.347 ;
     RECT  54.96 79.189 55.08 81.347 ;
     RECT  23.376 80.387 24.408 81.395 ;
     RECT  25.68 80.821 25.704 81.445 ;
     RECT  25.68 81.445 26.136 81.539 ;
     RECT  68.976 81.349 69 81.539 ;
     RECT  77.424 81.011 78.6 81.635 ;
     RECT  45.6 80.483 46.008 81.877 ;
     RECT  88.128 79.427 89.112 82.021 ;
     RECT  24 81.395 24.408 82.115 ;
     RECT  83.4 81.107 83.712 82.309 ;
     RECT  55.056 81.347 55.08 82.453 ;
     RECT  83.232 82.309 83.712 82.499 ;
     RECT  26.112 81.539 26.136 82.549 ;
     RECT  72.6 80.867 72.912 82.549 ;
     RECT  99.6 67.187 99.912 82.645 ;
     RECT  54.72 82.453 55.08 82.691 ;
     RECT  65.184 82.021 65.208 82.691 ;
     RECT  7.8 81.011 8.112 82.789 ;
     RECT  45.6 81.877 46.152 82.789 ;
     RECT  31.392 82.069 31.416 82.835 ;
     RECT  45.024 82.789 46.152 82.931 ;
     RECT  65.904 82.789 65.928 82.931 ;
     RECT  18.6 80.819 18.912 82.981 ;
     RECT  77.424 81.635 78.408 83.173 ;
     RECT  24 82.115 24.312 83.221 ;
     RECT  34.08 80.101 35.208 83.267 ;
     RECT  52.992 82.549 53.016 83.267 ;
     RECT  26.016 82.549 26.136 83.461 ;
     RECT  94.2 81.011 94.512 83.461 ;
     RECT  25.68 83.461 26.136 83.507 ;
     RECT  56.4 80.915 58.44 83.507 ;
     RECT  7.8 82.789 8.712 83.509 ;
     RECT  28.656 81.011 30.36 83.509 ;
     RECT  13.2 81.347 13.608 83.651 ;
     RECT  72.048 82.549 72.912 83.653 ;
     RECT  42.192 83.509 42.216 83.699 ;
     RECT  104.784 75.731 105.312 83.749 ;
     RECT  87.552 82.021 89.112 83.795 ;
     RECT  72.048 83.653 73.608 83.843 ;
     RECT  98.688 82.645 99.912 83.939 ;
     RECT  18 82.981 18.912 84.035 ;
     RECT  34.08 83.267 35.112 84.037 ;
     RECT  33.648 84.037 35.112 84.083 ;
     RECT  12 83.173 12.024 84.131 ;
     RECT  52.944 84.037 52.968 84.133 ;
     RECT  32.496 84.037 32.52 84.179 ;
     RECT  52.848 84.133 52.968 84.179 ;
     RECT  37.008 84.037 37.032 84.181 ;
     RECT  94.2 83.461 95.256 84.227 ;
     RECT  6.816 83.509 8.712 84.275 ;
     RECT  77.088 83.173 78.408 84.275 ;
     RECT  96.864 83.797 96.888 84.277 ;
     RECT  33.648 84.083 33.672 84.323 ;
     RECT  69.408 82.405 69.432 84.323 ;
     RECT  104.16 83.749 105.312 84.323 ;
     RECT  7.8 84.275 8.712 84.325 ;
     RECT  28.464 83.509 30.36 84.325 ;
     RECT  83.4 82.499 83.712 84.325 ;
     RECT  90.624 83.749 90.648 84.325 ;
     RECT  94.2 84.227 94.512 84.325 ;
     RECT  74.688 83.173 74.712 84.371 ;
     RECT  77.088 84.275 78.312 84.373 ;
     RECT  90.624 84.325 91.224 84.419 ;
     RECT  24 83.221 24.552 84.563 ;
     RECT  72.6 83.843 73.608 84.563 ;
     RECT  7.8 84.325 9.096 84.611 ;
     RECT  65.232 83.797 65.256 84.757 ;
     RECT  99.6 83.939 99.912 84.757 ;
     RECT  21.072 72.947 21.096 84.805 ;
     RECT  69.6 84.565 69.624 84.805 ;
     RECT  70.992 80.435 71.016 84.805 ;
     RECT  55.296 83.173 55.32 84.851 ;
     RECT  36.432 84.181 37.032 84.899 ;
     RECT  67.2 77.795 67.512 84.901 ;
     RECT  88.128 83.795 89.112 84.901 ;
     RECT  94.08 84.325 94.512 84.901 ;
     RECT  28.464 84.325 30.792 84.947 ;
     RECT  91.008 84.419 91.224 84.947 ;
     RECT  25.68 83.507 25.704 84.995 ;
     RECT  64.944 84.757 65.256 84.995 ;
     RECT  93.168 84.901 94.512 84.995 ;
     RECT  76.8 84.373 78.312 85.043 ;
     RECT  2.4 78.517 3.96 85.093 ;
     RECT  18.192 84.035 18.912 85.141 ;
     RECT  20.448 84.805 21.768 85.141 ;
     RECT  45.6 82.931 46.152 85.379 ;
     RECT  13.2 83.651 13.512 85.381 ;
     RECT  17.136 84.373 17.16 85.381 ;
     RECT  18.192 85.141 21.768 85.381 ;
     RECT  59.76 83.749 59.784 85.429 ;
     RECT  45.6 85.379 45.912 85.477 ;
     RECT  58.416 83.507 58.44 85.477 ;
     RECT  77.184 85.043 78.312 85.477 ;
     RECT  58.128 85.477 58.44 85.523 ;
     RECT  69.6 84.805 71.016 85.523 ;
     RECT  77.184 85.477 78.936 85.523 ;
     RECT  17.136 85.381 21.768 85.667 ;
     RECT  70.992 85.523 71.016 85.667 ;
     RECT  103.152 84.325 103.176 85.667 ;
     RECT  99.6 84.757 100.2 85.813 ;
     RECT  66.672 84.901 67.512 85.955 ;
     RECT  96.864 84.277 97.272 86.005 ;
     RECT  52.848 84.179 52.872 86.099 ;
     RECT  87.456 84.901 89.112 86.099 ;
     RECT  99.6 85.813 101.016 86.099 ;
     RECT  24 84.563 24.312 86.197 ;
     RECT  58.128 85.523 58.152 86.243 ;
     RECT  24 86.197 25.08 86.339 ;
     RECT  36.432 84.899 36.504 86.387 ;
     RECT  2.4 85.093 4.152 86.483 ;
     RECT  13.104 85.381 13.512 86.485 ;
     RECT  34.8 84.083 35.112 86.485 ;
     RECT  17.136 85.667 19.56 86.531 ;
     RECT  12.96 86.485 13.512 86.627 ;
     RECT  28.464 84.947 30.36 86.629 ;
     RECT  64.944 84.995 64.968 86.675 ;
     RECT  80.88 81.107 82.056 86.675 ;
     RECT  85.632 86.005 85.656 86.675 ;
     RECT  87.456 86.099 87.48 86.675 ;
     RECT  96.288 86.005 97.272 86.675 ;
     RECT  91.008 84.947 91.032 86.723 ;
     RECT  93.168 84.995 93.192 86.725 ;
     RECT  94.2 84.995 94.512 86.725 ;
     RECT  93.168 86.725 94.512 86.771 ;
     RECT  36.48 86.387 36.504 86.819 ;
     RECT  59.76 85.429 60.072 86.821 ;
     RECT  59.76 86.821 60.408 86.867 ;
     RECT  27.216 76.355 27.24 86.869 ;
     RECT  28.464 86.629 30.456 86.869 ;
     RECT  77.424 85.523 78.936 86.869 ;
     RECT  27.216 86.869 30.456 87.011 ;
     RECT  104.256 84.323 105.312 87.059 ;
     RECT  51 72.179 51.312 87.109 ;
     RECT  76.944 86.869 78.936 87.109 ;
     RECT  106.464 86.629 106.488 87.203 ;
     RECT  32.544 86.341 32.568 87.251 ;
     RECT  74.928 86.581 74.952 87.251 ;
     RECT  100.992 86.099 101.016 87.251 ;
     RECT  11.184 86.629 11.208 87.299 ;
     RECT  24 86.339 24.312 87.445 ;
     RECT  28.464 87.011 30.456 87.445 ;
     RECT  56.4 83.507 56.712 87.445 ;
     RECT  3.936 86.483 4.152 87.539 ;
     RECT  61.8 76.787 62.112 87.637 ;
     RECT  93.552 86.771 94.512 87.779 ;
     RECT  83.4 84.325 84.552 87.781 ;
     RECT  6.24 86.053 6.264 87.827 ;
     RECT  17.136 86.531 18.912 87.827 ;
     RECT  22.608 87.541 22.632 87.827 ;
     RECT  37.008 86.917 37.08 87.827 ;
     RECT  50.88 87.109 51.312 87.827 ;
     RECT  76.944 87.109 79.272 87.827 ;
     RECT  80.88 86.675 81.96 87.827 ;
     RECT  93.744 87.779 94.512 87.827 ;
     RECT  97.248 86.675 97.272 87.827 ;
     RECT  104.496 87.059 105.312 87.827 ;
     RECT  34.8 86.485 35.208 87.875 ;
     RECT  56.4 87.445 56.856 88.261 ;
     RECT  44.88 85.477 45.912 88.309 ;
     RECT  69.648 85.523 69.672 88.309 ;
     RECT  72.6 84.563 72.912 88.309 ;
     RECT  52.896 86.341 52.92 88.357 ;
     RECT  21.072 85.667 21.096 88.403 ;
     RECT  28.464 87.445 30.744 88.403 ;
     RECT  61.8 87.637 62.52 88.403 ;
     RECT  76.944 87.827 78.936 88.403 ;
     RECT  80.88 87.827 81.768 88.403 ;
     RECT  55.92 88.261 56.856 88.595 ;
     RECT  59.856 86.867 60.408 88.693 ;
     RECT  61.8 88.403 62.112 88.693 ;
     RECT  88.8 86.099 89.112 88.741 ;
     RECT  59.856 88.693 62.112 88.835 ;
     RECT  17.136 87.827 17.496 88.837 ;
     RECT  18.6 87.827 18.912 88.837 ;
     RECT  34.8 87.875 35.112 88.885 ;
     RECT  104.784 87.827 105.312 88.885 ;
     RECT  22.752 88.885 22.776 88.933 ;
     RECT  24 87.445 25.176 88.933 ;
     RECT  59.856 88.835 60.408 88.979 ;
     RECT  28.464 88.403 30.456 89.027 ;
     RECT  106.608 87.445 106.632 89.171 ;
     RECT  55.92 88.595 56.712 89.315 ;
     RECT  5.616 88.885 5.64 89.317 ;
     RECT  94.032 87.827 94.512 89.317 ;
     RECT  17.136 88.837 18.912 89.411 ;
     RECT  99.6 86.099 99.912 89.413 ;
     RECT  67.2 85.955 67.512 89.461 ;
     RECT  72.384 88.309 72.912 89.461 ;
     RECT  98.736 89.413 99.912 89.461 ;
     RECT  100.944 88.885 100.968 89.461 ;
     RECT  15.312 88.741 15.336 89.507 ;
     RECT  27.216 87.011 27.24 89.557 ;
     RECT  5.616 89.317 5.688 89.603 ;
     RECT  28.464 89.027 30.36 89.603 ;
     RECT  67.2 89.461 68.136 89.653 ;
     RECT  69.552 88.309 69.672 89.653 ;
     RECT  17.136 89.411 17.496 89.699 ;
     RECT  33.648 87.829 33.672 89.699 ;
     RECT  67.2 89.653 69.672 89.699 ;
     RECT  26.592 89.557 27.24 89.747 ;
     RECT  104.304 88.885 105.312 89.747 ;
     RECT  44.88 88.309 46.056 89.797 ;
     RECT  38.208 88.501 38.232 89.845 ;
     RECT  39.36 70.931 40.512 89.845 ;
     RECT  38.208 89.845 40.512 89.891 ;
     RECT  22.752 88.933 25.176 89.939 ;
     RECT  28.944 89.603 30.36 89.989 ;
     RECT  38.64 89.891 40.512 89.989 ;
     RECT  51 87.827 51.312 89.989 ;
     RECT  37.008 87.827 37.032 90.035 ;
     RECT  44.88 89.797 46.152 90.035 ;
     RECT  61.584 88.835 62.112 90.083 ;
     RECT  98.736 89.461 100.968 90.083 ;
     RECT  77.424 88.403 78.936 90.181 ;
     RECT  28.944 89.989 30.936 90.229 ;
     RECT  34.8 88.885 35.208 90.275 ;
     RECT  72.384 89.461 73.656 90.275 ;
     RECT  74.64 88.885 74.664 90.275 ;
     RECT  97.2 89.413 97.224 90.275 ;
     RECT  98.736 90.083 100.104 90.275 ;
     RECT  77.088 90.181 78.936 90.371 ;
     RECT  72.6 90.275 73.656 90.419 ;
     RECT  15.6 90.037 15.624 90.469 ;
     RECT  17.136 89.699 17.16 90.469 ;
     RECT  38.64 89.989 41.448 90.565 ;
     RECT  102.624 89.461 102.648 90.565 ;
     RECT  44.88 90.035 46.056 90.611 ;
     RECT  102.624 90.565 102.888 90.611 ;
     RECT  3.936 87.539 3.96 90.613 ;
     RECT  10.56 90.517 10.584 90.659 ;
     RECT  51 89.989 51.432 90.659 ;
     RECT  52.896 88.357 53.592 90.659 ;
     RECT  64.416 89.509 64.44 90.659 ;
     RECT  92.352 89.029 92.376 90.659 ;
     RECT  88.608 88.741 89.112 90.707 ;
     RECT  28.944 90.229 31.08 90.803 ;
     RECT  38.64 90.565 42.168 90.803 ;
     RECT  99.6 90.275 100.104 90.899 ;
     RECT  67.2 89.699 69 90.901 ;
     RECT  67.104 90.901 69 90.947 ;
     RECT  52.896 90.659 52.92 91.091 ;
     RECT  39.36 90.803 42.168 91.187 ;
     RECT  15.6 90.469 17.16 91.427 ;
     RECT  24 89.939 25.176 91.429 ;
     RECT  93.696 89.317 94.512 91.429 ;
     RECT  23.376 91.429 25.176 91.475 ;
     RECT  82.032 90.565 82.056 91.619 ;
     RECT  34.8 90.275 35.112 91.717 ;
     RECT  72.6 90.419 72.912 91.717 ;
     RECT  58.656 88.885 58.68 91.763 ;
     RECT  23.376 91.475 24.312 91.859 ;
     RECT  68.832 90.947 69 91.859 ;
     RECT  99.6 90.899 99.912 91.861 ;
     RECT  102.864 90.611 102.888 91.955 ;
     RECT  93.504 91.429 94.512 92.005 ;
     RECT  41.664 91.187 42.168 92.099 ;
     RECT  3.84 90.613 3.96 92.147 ;
     RECT  5.664 89.603 5.688 92.197 ;
     RECT  39.36 91.187 40.512 92.197 ;
     RECT  41.664 92.099 41.688 92.197 ;
     RECT  5.136 92.197 5.688 92.243 ;
     RECT  9.648 91.285 9.672 92.243 ;
     RECT  48.432 90.037 48.456 92.341 ;
     RECT  77.424 90.371 78.936 92.341 ;
     RECT  5.136 92.243 5.16 92.387 ;
     RECT  74.064 91.429 74.088 92.387 ;
     RECT  34.8 91.717 35.208 92.435 ;
     RECT  76.944 92.341 78.936 92.435 ;
     RECT  48.432 92.341 49.032 92.483 ;
     RECT  76.944 92.435 78.312 92.579 ;
     RECT  15.6 91.427 16.392 92.675 ;
     RECT  87.312 92.437 87.336 92.723 ;
     RECT  2.4 86.483 2.712 92.773 ;
     RECT  88.8 90.707 89.112 92.773 ;
     RECT  60.384 88.979 60.408 92.821 ;
     RECT  51 90.659 51.312 92.869 ;
     RECT  39.36 92.197 41.688 92.915 ;
     RECT  72.48 91.717 72.912 92.915 ;
     RECT  15.6 92.675 15.864 92.963 ;
     RECT  28.944 90.803 30.36 92.963 ;
     RECT  43.248 91.669 43.272 92.963 ;
     RECT  60.384 92.821 60.456 92.963 ;
     RECT  83.4 87.781 84.648 92.963 ;
     RECT  33.744 92.245 33.768 93.107 ;
     RECT  48.432 92.483 48.456 93.251 ;
     RECT  65.472 92.245 65.496 93.347 ;
     RECT  67.104 90.947 67.512 93.347 ;
     RECT  50.88 92.869 51.312 93.397 ;
     RECT  54 92.293 54.024 93.491 ;
     RECT  106.608 92.869 106.632 93.491 ;
     RECT  80.88 88.403 80.904 93.539 ;
     RECT  63.504 92.869 63.528 93.635 ;
     RECT  13.2 86.627 13.512 93.925 ;
     RECT  98.976 91.861 99.912 94.019 ;
     RECT  68.832 91.859 68.856 94.021 ;
     RECT  68.64 94.021 68.856 94.067 ;
     RECT  75.84 92.869 75.864 94.115 ;
     RECT  2.304 92.773 2.712 94.259 ;
     RECT  44.448 94.261 44.472 94.403 ;
     RECT  95.952 94.261 95.976 94.403 ;
     RECT  13.2 93.925 14.04 94.451 ;
     RECT  11.376 93.061 11.4 94.499 ;
     RECT  15.84 92.963 15.864 94.549 ;
     RECT  43.44 93.349 43.464 94.595 ;
     RECT  45.6 90.611 46.056 94.595 ;
     RECT  50.736 93.397 51.312 94.595 ;
     RECT  60.432 92.963 60.456 94.595 ;
     RECT  80.592 94.357 80.616 94.595 ;
     RECT  88.704 92.773 89.112 94.595 ;
     RECT  3.84 92.147 3.864 94.597 ;
     RECT  34.8 92.435 35.112 94.597 ;
     RECT  67.2 93.347 67.512 94.597 ;
     RECT  3.84 94.597 3.96 94.643 ;
     RECT  38.256 92.101 38.28 94.643 ;
     RECT  45.6 94.595 46.008 94.691 ;
     RECT  59.232 93.493 59.256 94.691 ;
     RECT  56.4 89.315 56.712 94.693 ;
     RECT  34.8 94.597 35.208 94.739 ;
     RECT  3.936 94.643 3.96 94.835 ;
     RECT  17.28 93.445 17.304 94.835 ;
     RECT  56.4 94.693 56.904 94.883 ;
     RECT  24 91.859 24.312 94.981 ;
     RECT  77.424 92.579 78.312 94.981 ;
     RECT  13.2 94.451 13.512 95.125 ;
     RECT  15.84 94.549 15.912 95.125 ;
     RECT  29.4 92.963 30.36 95.125 ;
     RECT  66.768 94.597 67.512 95.701 ;
     RECT  68.64 94.067 68.664 95.701 ;
     RECT  99.6 94.019 99.912 95.701 ;
     RECT  12.672 95.125 13.512 95.747 ;
     RECT  2.4 94.259 2.712 95.749 ;
     RECT  99.6 95.701 100.344 95.749 ;
     RECT  57.84 95.653 57.864 95.797 ;
     RECT  66.768 95.701 68.664 95.939 ;
     RECT  104.784 89.747 105.312 95.939 ;
     RECT  23.136 94.981 24.312 96.035 ;
     RECT  9.648 95.125 9.672 96.133 ;
     RECT  9.648 96.133 9.96 96.179 ;
     RECT  57.84 95.797 58.008 96.275 ;
     RECT  45.6 94.691 45.912 96.277 ;
     RECT  67.2 95.939 68.664 96.277 ;
     RECT  59.808 94.981 59.832 96.371 ;
     RECT  27.216 89.747 27.24 96.419 ;
     RECT  72.6 92.915 72.912 96.517 ;
     RECT  2.4 95.749 3.432 96.709 ;
     RECT  16.992 96.469 17.016 96.709 ;
     RECT  16.992 96.709 17.112 96.755 ;
     RECT  77.424 94.981 78.84 96.755 ;
     RECT  93.264 92.005 94.512 96.853 ;
     RECT  102.624 96.037 102.648 96.853 ;
     RECT  103.776 95.893 103.8 96.853 ;
     RECT  98.64 95.749 100.344 96.899 ;
     RECT  17.088 96.755 17.112 96.901 ;
     RECT  77.424 96.755 78.312 96.901 ;
     RECT  15.648 95.125 15.912 96.947 ;
     RECT  17.088 96.901 17.208 96.947 ;
     RECT  86.832 95.125 86.856 96.947 ;
     RECT  45.6 96.277 46.008 96.997 ;
     RECT  9.936 96.179 9.96 97.139 ;
     RECT  77.232 96.901 78.312 97.139 ;
     RECT  99.504 96.899 100.344 97.139 ;
     RECT  39.36 92.915 41.448 97.141 ;
     RECT  49.152 96.901 49.176 97.283 ;
     RECT  22.8 96.085 22.824 97.379 ;
     RECT  18.6 89.411 18.912 97.381 ;
     RECT  67.2 96.277 69.144 97.477 ;
     RECT  2.4 96.709 3.96 97.523 ;
     RECT  29.28 95.125 30.36 97.523 ;
     RECT  38.208 96.565 38.232 97.523 ;
     RECT  2.4 97.523 3.432 97.571 ;
     RECT  21.12 94.933 21.144 97.571 ;
     RECT  102.624 96.853 103.8 97.571 ;
     RECT  77.424 97.139 78.312 97.667 ;
     RECT  83.4 92.963 83.712 97.765 ;
     RECT  34.8 94.739 35.112 97.957 ;
     RECT  91.152 95.605 91.176 98.005 ;
     RECT  92.928 96.853 94.512 98.005 ;
     RECT  91.152 98.005 94.512 98.051 ;
     RECT  72.48 96.517 72.912 98.053 ;
     RECT  18.6 97.381 19.032 98.099 ;
     RECT  27.792 96.853 27.816 98.099 ;
     RECT  45.6 96.997 46.152 98.099 ;
     RECT  92.064 98.051 94.512 98.099 ;
     RECT  95.76 97.429 95.784 98.099 ;
     RECT  15.84 96.947 15.912 98.339 ;
     RECT  57.84 96.275 57.864 98.341 ;
     RECT  56.4 94.883 56.712 98.485 ;
     RECT  48.528 97.381 48.552 98.581 ;
     RECT  49.968 97.429 49.992 98.629 ;
     RECT  51 94.595 51.312 98.629 ;
     RECT  39.36 97.141 41.592 98.675 ;
     RECT  49.968 98.629 51.312 98.675 ;
     RECT  56.16 98.485 56.712 98.675 ;
     RECT  57.744 98.341 57.864 98.675 ;
     RECT  67.2 97.477 69.576 98.675 ;
     RECT  102.624 97.571 103.464 98.675 ;
     RECT  48.528 98.581 48.984 98.771 ;
     RECT  72.48 98.053 73.656 98.867 ;
     RECT  83.4 97.765 83.832 98.965 ;
     RECT  64.992 95.557 65.016 99.011 ;
     RECT  17.184 96.947 17.208 99.061 ;
     RECT  9.84 97.669 9.864 99.155 ;
     RECT  103.44 98.675 103.464 99.157 ;
     RECT  39.36 98.675 41.448 99.203 ;
     RECT  72.48 98.867 72.912 99.203 ;
     RECT  75.504 98.485 75.528 99.203 ;
     RECT  80.352 98.341 80.376 99.443 ;
     RECT  13.2 95.747 13.512 99.493 ;
     RECT  18.6 98.099 18.912 99.541 ;
     RECT  2.4 97.571 2.712 99.685 ;
     RECT  50.688 98.675 51.312 99.685 ;
     RECT  60.624 99.589 60.648 99.685 ;
     RECT  45.6 98.099 45.912 99.733 ;
     RECT  48.96 98.771 48.984 99.779 ;
     RECT  54.72 99.637 54.744 99.779 ;
     RECT  34.224 97.957 35.112 99.923 ;
     RECT  59.808 99.685 60.648 99.973 ;
     RECT  61.8 90.083 62.112 99.973 ;
     RECT  59.808 99.973 62.112 100.115 ;
     RECT  49.056 99.925 49.08 100.163 ;
     RECT  71.28 99.157 71.304 100.211 ;
     RECT  34.704 99.923 35.112 100.259 ;
     RECT  7.8 84.611 8.112 100.261 ;
     RECT  88.8 94.595 89.112 100.261 ;
     RECT  74.064 99.157 74.088 100.307 ;
     RECT  15.84 98.339 15.864 100.355 ;
     RECT  18.6 99.541 19.032 100.355 ;
     RECT  21.216 99.157 21.24 100.355 ;
     RECT  59.808 100.115 60.648 100.355 ;
     RECT  103.44 99.157 103.848 100.355 ;
     RECT  50.64 99.685 51.312 100.499 ;
     RECT  13.2 99.493 14.28 100.739 ;
     RECT  67.2 98.675 67.848 100.787 ;
     RECT  17.136 99.061 17.208 100.789 ;
     RECT  57.744 98.675 57.768 100.789 ;
     RECT  17.088 100.789 17.208 100.835 ;
     RECT  99.504 97.139 99.912 100.835 ;
     RECT  34.8 100.259 35.112 100.837 ;
     RECT  36.816 100.069 36.84 100.837 ;
     RECT  34.8 100.837 36.84 100.883 ;
     RECT  45.6 99.733 46.2 100.883 ;
     RECT  56.208 98.675 56.712 100.883 ;
     RECT  17.088 100.835 17.112 100.885 ;
     RECT  16.992 100.885 17.112 100.931 ;
     RECT  44.544 100.069 44.568 100.931 ;
     RECT  59.808 100.355 59.832 100.931 ;
     RECT  2.4 99.685 3.624 101.075 ;
     RECT  42.96 97.525 42.984 101.075 ;
     RECT  65.088 99.157 65.112 101.075 ;
     RECT  88.8 100.261 89.88 101.075 ;
     RECT  57.744 100.789 58.056 101.171 ;
     RECT  11.376 99.157 11.4 101.221 ;
     RECT  11.232 101.221 11.4 101.267 ;
     RECT  86.304 100.789 86.328 101.363 ;
     RECT  92.064 98.099 92.088 101.413 ;
     RECT  80.736 101.317 80.76 101.459 ;
     RECT  103.824 100.355 103.848 101.507 ;
     RECT  34.8 100.883 35.928 101.603 ;
     RECT  77.808 97.667 78.312 101.749 ;
     RECT  45.6 100.883 45.912 101.845 ;
     RECT  66.192 98.965 66.216 101.845 ;
     RECT  6.864 100.261 8.112 101.891 ;
     RECT  39.36 99.203 40.512 101.989 ;
     RECT  81.744 101.413 81.768 101.989 ;
     RECT  83.4 98.965 84.216 101.989 ;
     RECT  63.264 101.413 63.288 102.131 ;
     RECT  38.784 101.989 40.512 102.277 ;
     RECT  88.8 101.075 89.112 102.277 ;
     RECT  61.8 100.115 62.112 102.325 ;
     RECT  4.56 101.269 4.584 102.373 ;
     RECT  4.56 102.373 4.824 102.419 ;
     RECT  16.992 100.931 17.016 102.419 ;
     RECT  81.744 101.989 84.216 102.469 ;
     RECT  73.968 102.373 73.992 102.515 ;
     RECT  81.216 102.469 84.216 102.563 ;
     RECT  7.8 101.891 8.112 102.565 ;
     RECT  11.232 101.267 11.256 102.565 ;
     RECT  18.6 100.355 18.912 102.565 ;
     RECT  44.304 102.469 44.328 102.611 ;
     RECT  81.216 102.563 82.056 102.611 ;
     RECT  4.8 102.419 4.824 102.659 ;
     RECT  11.232 102.565 11.736 102.659 ;
     RECT  45.6 101.845 46.008 102.659 ;
     RECT  53.856 101.749 53.88 102.659 ;
     RECT  91.728 101.413 92.088 102.707 ;
     RECT  81.744 102.611 82.056 102.755 ;
     RECT  29.4 97.523 30.36 102.949 ;
     RECT  2.4 101.075 2.712 103.045 ;
     RECT  29.4 102.949 30.696 103.091 ;
     RECT  63.408 102.565 63.432 103.091 ;
     RECT  24 96.035 24.312 103.093 ;
     RECT  7.8 102.565 8.328 103.189 ;
     RECT  38.784 102.277 41.064 103.235 ;
     RECT  61.584 102.325 62.112 103.235 ;
     RECT  75.936 102.565 75.96 103.235 ;
     RECT  77.808 101.749 78.744 103.235 ;
     RECT  83.184 102.563 84.216 103.235 ;
     RECT  97.008 102.277 97.032 103.331 ;
     RECT  56.4 100.883 56.712 103.429 ;
     RECT  57.744 101.171 57.768 103.429 ;
     RECT  56.4 103.429 57.768 103.475 ;
     RECT  77.904 103.235 78.744 103.475 ;
     RECT  56.4 103.475 57.624 103.621 ;
     RECT  65.568 101.845 66.216 103.715 ;
     RECT  34.8 101.603 35.112 103.717 ;
     RECT  72.6 99.203 72.912 103.717 ;
     RECT  91.968 102.707 92.088 103.717 ;
     RECT  28.032 101.989 28.056 103.763 ;
     RECT  31.872 102.229 31.896 103.763 ;
     RECT  82.032 102.755 82.056 103.811 ;
     RECT  86.736 102.949 86.76 103.811 ;
     RECT  88.656 102.277 89.112 103.811 ;
     RECT  106.608 102.565 106.632 103.811 ;
     RECT  45.6 102.659 45.912 104.005 ;
     RECT  105 95.939 105.312 104.101 ;
     RECT  56.304 103.621 57.624 104.147 ;
     RECT  45.072 104.005 45.912 104.243 ;
     RECT  13.2 100.739 13.512 104.245 ;
     RECT  50.688 100.499 51.312 104.245 ;
     RECT  66.096 103.715 66.216 104.245 ;
     RECT  67.2 100.787 67.512 104.245 ;
     RECT  94.2 98.099 94.512 104.245 ;
     RECT  2.4 103.045 2.856 104.291 ;
     RECT  7.8 103.189 8.76 104.291 ;
     RECT  91.968 103.717 92.328 104.291 ;
     RECT  66.096 104.245 67.512 104.531 ;
     RECT  23.664 103.093 24.312 104.579 ;
     RECT  102.576 103.237 102.6 104.819 ;
     RECT  45.6 104.243 45.912 104.821 ;
     RECT  98.064 97.525 98.088 104.821 ;
     RECT  39.312 103.235 40.512 104.867 ;
     RECT  47.184 103.717 47.208 104.867 ;
     RECT  66.288 104.531 67.512 104.867 ;
     RECT  29.4 103.091 29.712 104.869 ;
     RECT  34.8 103.717 36.072 104.915 ;
     RECT  93.456 104.245 94.512 104.915 ;
     RECT  39.6 104.867 40.512 105.059 ;
     RECT  70.08 104.821 70.104 105.107 ;
     RECT  78 103.475 78.744 105.395 ;
     RECT  36.48 104.917 36.504 105.443 ;
     RECT  76.368 103.477 76.392 105.443 ;
     RECT  80.928 105.301 80.952 105.443 ;
     RECT  16.992 104.821 17.016 105.491 ;
     RECT  26.112 98.485 26.136 105.491 ;
     RECT  50.544 104.245 51.312 105.491 ;
     RECT  56.4 104.147 57.624 105.491 ;
     RECT  83.4 103.235 84.216 105.491 ;
     RECT  87.216 104.821 87.24 105.491 ;
     RECT  18.6 102.565 19.032 105.683 ;
     RECT  45.6 104.821 46.056 105.683 ;
     RECT  33.792 104.677 33.816 105.731 ;
     RECT  92.304 104.291 92.328 105.925 ;
     RECT  67.104 104.867 67.512 105.973 ;
     RECT  9.648 105.109 9.672 106.067 ;
     RECT  13.2 104.245 13.704 106.067 ;
     RECT  29.136 104.869 29.712 106.067 ;
     RECT  98.064 104.821 98.472 106.067 ;
     RECT  92.304 105.925 93.144 106.211 ;
     RECT  56.4 105.491 56.904 106.307 ;
     RECT  72.6 103.717 73.8 106.307 ;
     RECT  5.04 104.101 5.064 106.403 ;
     RECT  98.064 106.067 98.088 106.403 ;
     RECT  11.712 102.659 11.736 106.451 ;
     RECT  54.144 105.397 54.168 106.643 ;
     RECT  104.88 104.101 105.312 106.739 ;
     RECT  31.44 105.397 31.464 106.837 ;
     RECT  40.2 105.059 40.512 106.837 ;
     RECT  30.768 106.837 31.464 106.883 ;
     RECT  27.6 104.821 27.624 106.931 ;
     RECT  26.208 105.781 26.232 107.027 ;
     RECT  11.808 106.549 11.832 107.267 ;
     RECT  57.936 105.781 57.96 107.267 ;
     RECT  59.28 104.245 59.304 107.267 ;
     RECT  90.576 106.549 90.6 107.267 ;
     RECT  21.264 105.397 21.288 107.507 ;
     RECT  39.792 106.837 40.512 107.555 ;
     RECT  64.944 106.309 64.968 107.555 ;
     RECT  81.984 104.725 82.008 107.555 ;
     RECT  96.288 106.549 96.312 107.699 ;
     RECT  30.768 106.883 30.792 107.795 ;
     RECT  33.504 107.653 33.528 107.795 ;
     RECT  41.808 105.397 41.832 107.795 ;
     RECT  66.72 105.973 67.512 107.795 ;
     RECT  68.976 107.125 69 107.795 ;
     RECT  75.216 106.261 75.24 107.795 ;
     RECT  93.12 106.211 93.144 107.795 ;
     RECT  2.4 104.291 2.712 108.009 ;
     RECT  7.8 104.291 8.112 108.009 ;
     RECT  13.2 106.067 13.512 108.009 ;
     RECT  18.6 105.683 18.912 108.009 ;
     RECT  24 104.579 24.312 108.009 ;
     RECT  29.4 106.067 29.712 108.009 ;
     RECT  34.8 104.915 35.112 108.009 ;
     RECT  40.2 107.555 40.512 108.009 ;
     RECT  45.6 105.683 45.912 108.009 ;
     RECT  51 105.491 51.312 108.009 ;
     RECT  56.4 106.307 56.712 108.009 ;
     RECT  61.8 103.235 62.112 108.009 ;
     RECT  67.2 107.795 67.512 108.009 ;
     RECT  72.6 106.307 72.912 108.009 ;
     RECT  78 105.395 78.312 108.009 ;
     RECT  83.4 105.491 83.712 108.009 ;
     RECT  88.8 103.811 89.112 108.009 ;
     RECT  94.2 104.915 94.512 108.009 ;
     RECT  99.6 100.835 99.912 108.009 ;
     RECT  105 106.739 105.312 108.009 ;
     RECT  2.4 108.009 2.52 108.023 ;
     RECT  7.8 108.009 7.92 108.023 ;
     RECT  13.2 108.009 13.32 108.023 ;
     RECT  18.6 108.009 18.72 108.023 ;
     RECT  24 108.009 24.12 108.023 ;
     RECT  29.4 108.009 29.52 108.023 ;
     RECT  34.8 108.009 34.92 108.023 ;
     RECT  40.2 108.009 40.32 108.023 ;
     RECT  45.6 108.009 45.72 108.023 ;
     RECT  51 108.009 51.12 108.023 ;
     RECT  56.4 108.009 56.52 108.023 ;
     RECT  61.8 108.009 61.92 108.023 ;
     RECT  67.2 108.009 67.32 108.023 ;
     RECT  72.6 108.009 72.72 108.023 ;
     RECT  78 108.009 78.12 108.023 ;
     RECT  83.4 108.009 83.52 108.023 ;
     RECT  88.8 108.009 88.92 108.023 ;
     RECT  94.2 108.009 94.32 108.023 ;
     RECT  99.6 108.009 99.72 108.023 ;
     RECT  105 108.009 105.12 108.023 ;
     RECT  64.656 108.181 64.68 108.229 ;
     RECT  64.464 108.229 64.68 108.277 ;
     RECT  64.368 108.277 64.68 109.429 ;
     RECT  64.368 109.429 64.776 109.477 ;
     RECT  64.368 109.477 64.872 109.525 ;
     RECT  64.368 109.525 64.968 110.096 ;
  END
END ot_pqc_t_prom
END LIBRARY
